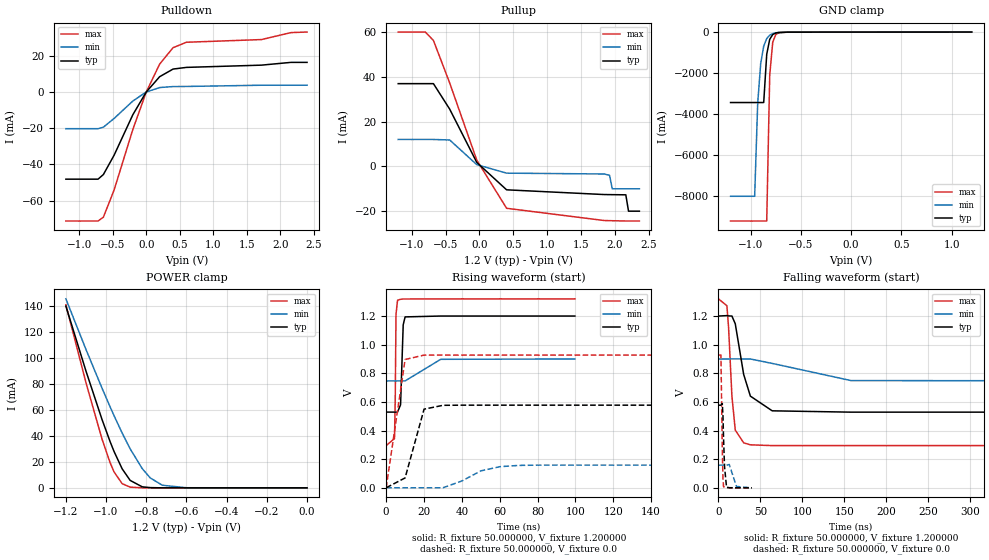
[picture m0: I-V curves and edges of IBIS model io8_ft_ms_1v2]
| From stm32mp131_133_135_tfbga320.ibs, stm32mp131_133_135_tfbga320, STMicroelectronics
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|   Model io8_ft_ms_1v2
[Model]  io8_ft_ms_1v2
Model_type I/O
Polarity   Non-Inverting
Enable   Active-Low
Vinl =   0.360000V
Vinh =   0.840000V
Vmeas =  0.600000V
Cref =   50.000000pF
Rref =   100.000000M
Vref =   0.0V
C_comp   2.961900pF   2.937700pF   2.984500pF
[Temperature Range]   25.000000   0.140000k   -40.000000
[Pullup Reference]   1.200000V   0.900000V   1.320000V
[Pulldown Reference]   0.0V   0.0V   0.0V
[POWER Clamp Reference]   1.200000V   0.900000V   1.320000V
[GND Clamp Reference]   0.0V   0.0V   0.0V
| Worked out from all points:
|   slope of the pulldown table from 0 to 0.18 V, typ, clamps not added: 23.2 ohm
|   slope of the pullup table from 0 to 0.18 V, typ, clamps not added: 28.5 ohm
|   GND clamp passes 1 mA (typ) near -0.47 V on its own axis
|   POWER clamp passes 1 mA (typ) near -0.83 V on its own axis
|   rising waveform, R_fixture 50.000000, V_fixture 1.200000: 20-80 % time 808ps typ, 2.63ns min, 431ps max; typ from 0.529 V to 1.2 V
|   rising waveform, R_fixture 50.000000, V_fixture 0.0: 20-80 % time 7.22ns typ, 16.4ns min, 6.21ns max; typ from 0 V to 0.577 V
|   falling waveform, R_fixture 50.000000, V_fixture 1.200000: 20-80 % time 13.7ns typ, 36.4ns min, 5.62ns max; typ from 1.2 V to 0.529 V
|   falling waveform, R_fixture 50.000000, V_fixture 0.0: 20-80 % time 2.02ns typ, 4.76ns min, 1.41ns max; typ from 0.577 V to 0 V
[Pulldown]
|Voltage   I(typ)   I(min)   I(max)
-1.2V     -48.14mA   -20.28mA   -71.24mA
-720mV    -48.14mA   -20.28mA   -71.24mA
-640mV    -45.58mA   -19.44mA   -69.11mA
-480mV    -34.9mA    -14.62mA   -54.1mA
-200mV    -12.54mA   -4.99mA    -20.65mA
0V        0A         0A         0A
200mV     8.434mA    2.44mA     15.39mA
400mV     12.64mA    2.983mA    24.45mA
600mV     13.57mA    3.042mA    27.45mA
1.72V     14.81mA    3.724mA    28.93mA
2.16V     16.34mA    3.724mA    32.78mA
2.4V      16.34mA    3.724mA    33.09mA
[Pullup]
|Voltage   I(typ)   I(min)   I(max)
-1.2V     36.95mA    12.02mA    60mA
-800mV    36.95mA    12.02mA    60mA
-680mV    36.95mA    12.02mA    56.24mA
-440mV    25.56mA    11.79mA    37.24mA
-40mV     1.753mA    765uA      2.773mA
400mV     -10.47mA   -3.023mA   -18.71mA
1.84V     -12.58mA   -3.4mA     -24.17mA
1.92V     -12.61mA   -4mA       -24.24mA
1.96V     -12.63mA   -10mA      -24.27mA
2.16V     -12.7mA    -10mA      -24.4mA
2.2V      -20mA      -10mA      -24.4mA
2.36V     -20mA      -10mA      -24.4mA
[GND_clamp]
|Voltage   I(typ)   I(min)   I(max)
-1.2V     -3.45A     -8.037A    -9.248A
-960mV    -3.45A     -8.037A    -9.248A
-930mV    -3.45A     -3.504A    -9.248A
-900mV    -3.45A     -1.544A    -9.248A
-870mV    -3.45A     -693.1mA   -9.248A
-840mV    -1.093A    -319.7mA   -9.248A
-810mV    -355mA     -153mA     -2.104A
-780mV    -122.1mA   -76.47mA   -492.8mA
-750mV    -46.85mA   -40.02mA   -125.6mA
-720mV    -21.41mA   -22.04mA   -38.94mA
-630mV    -6.028mA   -5.668mA   -6.589mA
1.2V      0A         44.19nA    0A
[POWER_clamp]
|Voltage   I(typ)   I(min)   I(max)
-1.2V     139.7mA    145.3mA    140.7mA
-1.1V     89.79mA    106.4mA    80.86mA
-1.02V    52.48mA    76.58mA    37.41mA
-980mV    35.57mA    62.3mA     19.38mA
-960mV    27.85mA    55.39mA    12.18mA
-920mV    14.63mA    42.15mA    3.226mA
-880mV    5.71mA     29.97mA    537.4uA
-820mV    777uA      14.76mA    28.17uA
-780mV    170.8uA    7.604mA    3.856uA
-720mV    16.71uA    2.018mA    195.3nA
-600mV    157.7nA    78.69uA    0A
0V        0A         56.62nA    0A
[Ramp]
| variable   typ   min   max
dV/dt_r  0.34636/5.28165n   95.23162m/14.22434n 0.55615/2.66557n
dV/dt_f  0.40279/13.61951n   92.01000m/36.38758n 0.61498/5.52083n
R_load = 50.000000
[Rising Waveform]
R_fixture= 50.000000
V_fixture= 1.200000
V_fixture_min= 0.900000
V_fixture_max= 1.320000
|time   V(typ)   V(min)   V(max)
0s        528.7mV    746.6mV    295mV
4.404ns   528.7mV    746.6mV    343.5mV
4.805ns   528.7mV    746.6mV    622.6mV
5.205ns   528.7mV    746.6mV    1.212V
6.006ns   528.3mV    746.6mV    1.31V
7.608ns   579.8mV    746.6mV    1.317V
9.009ns   1.139V     746.6mV    1.319V
10.01ns   1.194V     746.6mV    1.319V
28.83ns   1.2V       897.6mV    1.32V
99.7ns    1.2V       900mV      1.32V
[Rising Waveform]
R_fixture= 50.000000
V_fixture= 0.0
V_fixture_min= 0.0
V_fixture_max= 0.0
|time   V(typ)   V(min)   V(max)
0s        8.948nV    633.8nV    -5.106nV
10.01ns   68.77mV    634.1nV    896.4mV
20.02ns   549.2mV    -635.6uV   926.8mV
30.03ns   576.1mV    50.63uV    926.9mV
40.04ns   577.1mV    47.62mV    926.9mV
50.05ns   577.2mV    118.2mV    926.9mV
60.06ns   577.2mV    147.2mV    926.9mV
70.07ns   577.2mV    156.2mV    926.9mV
80.08ns   577.2mV    158mV      926.9mV
991ns     577.3mV    158.7mV    926.9mV
[Falling Waveform]
R_fixture= 50.000000
V_fixture= 1.200000
V_fixture_min= 0.900000
V_fixture_max= 1.320000
|time   V(typ)   V(min)   V(max)
0s        1.2V       900mV      1.32V
10.01ns   1.203V     900mV      1.272V
12.01ns   1.201V     899.9mV    1.122V
16.02ns   1.2V       900.9mV    639.5mV
20.02ns   1.146V     900.7mV    403.6mV
30.03ns   792.2mV    900.4mV    314.3mV
38.04ns   640.6mV    900mV      300.5mV
64.06ns   538mV      869.2mV    295.1mV
158.2ns   528.7mV    749.1mV    295mV
997ns     528.7mV    746.6mV    295mV
[Falling Waveform]
R_fixture= 50.000000
V_fixture= 0.0
V_fixture_min= 0.0
V_fixture_max= 0.0
|time   V(typ)   V(min)   V(max)
0s        577.3mV    158.7mV    926.9mV
2.883ns   577.3mV    158.7mV    927.6mV
4.565ns   589.1mV    158.7mV    261mV
5.365ns   499.6mV    158.7mV    63.97mV
6.006ns   352.4mV    158.7mV    9.718mV
7.207ns   148.3mV    158.7mV    2.954mV
9.61ns    3.974mV    158.6mV    1.562mV
12.81ns   921.1uV    163.1mV    784.7uV
21.46ns   480.6uV    9.73mV     155.7uV
39.88ns   8.948nV    633.8nV    -5.106nV
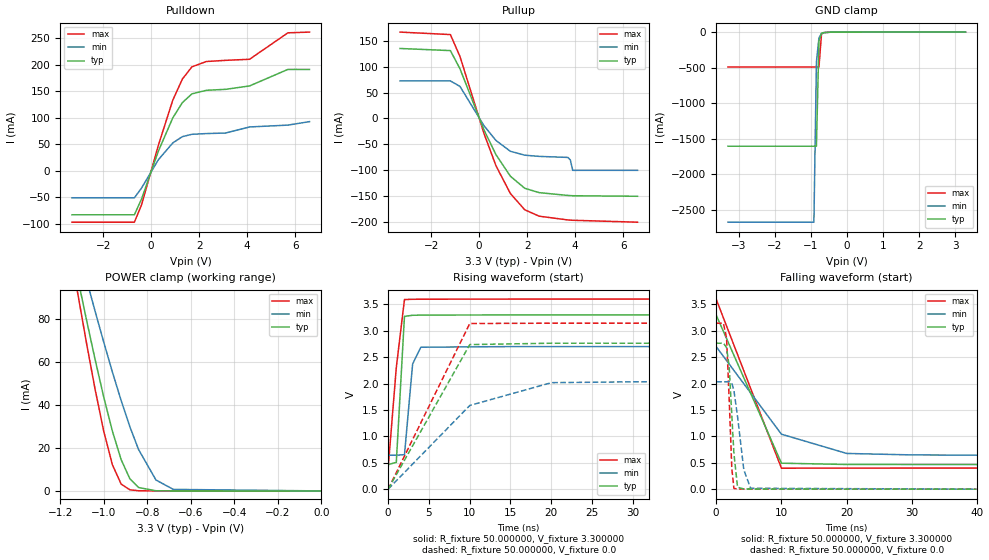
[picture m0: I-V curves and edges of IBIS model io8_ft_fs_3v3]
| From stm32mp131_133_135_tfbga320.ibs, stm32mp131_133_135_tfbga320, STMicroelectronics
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|   Model io8_ft_fs_3v3
[Model]  io8_ft_fs_3v3
Model_type I/O
Polarity   Non-Inverting
Enable   Active-Low
Vinl =   0.990000V
Vinh =   2.310000V
Vmeas =  1.650000V
Cref =   50.000000pF
Rref =   100.000000M
Vref =   0.0V
C_comp   3.331100pF   3.329200pF   3.346200pF
[Temperature Range]   25.000000   0.140000k   -40.000000
[Pullup Reference]   3.300000V   2.700000V   3.600000V
[Pulldown Reference]   0.0V   0.0V   0.0V
[POWER Clamp Reference]   3.300000V   2.700000V   3.600000V
[GND Clamp Reference]   0.0V   0.0V   0.0V
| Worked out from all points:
|   slope of the pulldown table from 0 to 0.495 V, typ, clamps not added: 8.27 ohm
|   slope of the pullup table from 0 to 0.495 V, typ, clamps not added: 9.61 ohm
|   GND clamp passes 1 mA (typ) near -0.46 V on its own axis
|   POWER clamp passes 1 mA (typ) near -0.82 V on its own axis
|   rising waveform, R_fixture 50.000000, V_fixture 3.300000: 20-80 % time 616ps typ, 720ps min, 1.17ns max; typ from 0.466 V to 3.3 V
|   rising waveform, R_fixture 50.000000, V_fixture 0.0: 20-80 % time 6.06ns typ, 8.41ns min, 6.02ns max; typ from 0 V to 2.76 V
|   falling waveform, R_fixture 50.000000, V_fixture 3.300000: 20-80 % time 6.06ns typ, 7.45ns min, 6ns max; typ from 3.3 V to 0.466 V
|   falling waveform, R_fixture 50.000000, V_fixture 0.0: 20-80 % time 734ps typ, 1.13ns min, 547ps max; typ from 2.76 V to 0 V
[Pulldown]
|Voltage   I(typ)   I(min)   I(max)
-3.3V     -82.68mA   -50.69mA   -96.69mA
-700mV    -82.68mA   -50.69mA   -96.69mA
-400mV    -52.74mA   -32.14mA   -63.87mA
300mV     37.41mA    21.2mA     48.47mA
900mV     100mA      52.8mA     133.4mA
1.3V      128.9mA    64.69mA    173.3mA
1.7V      145.4mA    69.09mA    196.4mA
2.3V      152.1mA    70.46mA    206.4mA
3.1V      153.9mA    71.5mA     208.6mA
4.1V      160.3mA    82.94mA    210.6mA
5.7V      191.5mA    86.44mA    260.5mA
6.6V      191.5mA    93mA       261.9mA
[Pullup]
|Voltage   I(typ)   I(min)   I(max)
-3.3V     135mA      72.45mA    166.6mA
-1.2V     130.9mA    72.45mA    161.8mA
-800mV    95.9mA     61.87mA    119.5mA
200mV     -22.04mA   -13.96mA   -28.88mA
700mV     -69.71mA   -42.31mA   -91.11mA
1.3V      -111.3mA   -63.25mA   -144.6mA
1.9V      -134.6mA   -70.77mA   -176.1mA
2.5V      -143mA     -73.1mA    -188.4mA
3.7V      -148.4mA   -75.1mA    -195.7mA
3.8V      -148.7mA   -80mA      -196mA
3.9V      -149mA     -100mA     -196.3mA
6.6V      -150mA     -100mA     -200mA
[GND_clamp]
|Voltage   I(typ)   I(min)   I(max)
-3.3V     -1.605A    -2.674A    -491.7mA
-920mV    -1.605A    -2.674A    -491.7mA
-850mV    -1.605A    -419.8mA   -491.7mA
-780mV    -124.6mA   -80.71mA   -491.7mA
-710mV    -18.13mA   -20.11mA   -27.93mA
-640mV    -6.917mA   -6.958mA   -7.362mA
-430mV    -466.9uA   -1.206mA   -281.7uA
3.28V     0A         45.63nA    0A
[POWER_clamp]
|Voltage   I(typ)   I(min)   I(max)
-3.28V    1.28A      1.024A     1.509A
-1.12V    99.56mA    114.1mA    92.51mA
-1.08V    80.16mA    98.83mA    69.45mA
-1.04V    61.47mA    83.9mA     47.62mA
-1V       43.82mA    69.37mA    27.91mA
-960mV    27.85mA    55.39mA    12.18mA
-920mV    14.63mA    42.15mA    3.226mA
-880mV    5.71mA     29.97mA    537.4uA
-840mV    1.599mA    19.32mA    75.95uA
-760mV    78.93uA    5.095mA    1.426uA
-680mV    3.528uA    713.7uA    27.27nA
0V        0A         62.3nA     0A
[Ramp]
| variable   typ   min   max
dV/dt_r  1.65858/1.98757n   1.22046/4.05944n   1.88568/1.46534n
dV/dt_f  1.70023/1.60172n   1.23439/3.65057n   1.92035/1.27355n
R_load = 50.000000
[Rising Waveform]
R_fixture= 50.000000
V_fixture= 3.300000
V_fixture_min= 2.700000
V_fixture_max= 3.600000
|time   V(typ)   V(min)   V(max)
0s        466.3mV    642.7mV    399.6mV
1.001ns   507.8mV    642.7mV    2.303V
2.002ns   3.273V     652.8mV    3.591V
3.003ns   3.293V     2.37V      3.596V
4.004ns   3.296V     2.688V     3.597V
15.02ns   3.3V       2.7V       3.6V
99.1ns    3.3V       2.7V       3.6V
[Rising Waveform]
R_fixture= 50.000000
V_fixture= 0.0
V_fixture_min= 0.0
V_fixture_max= 0.0
|time   V(typ)   V(min)   V(max)
0s        2.574nV    280.9nV    5.711nV
10.01ns   2.738V     1.585V     3.137V
20.02ns   2.764V     2.017V     3.143V
30.03ns   2.764V     2.033V     3.143V
991ns     2.764V     2.034V     3.143V
[Falling Waveform]
R_fixture= 50.000000
V_fixture= 3.300000
V_fixture_min= 2.700000
V_fixture_max= 3.600000
|time   V(typ)   V(min)   V(max)
0s        3.3V       2.7V       3.6V
10.01ns   491.7mV    1.041V     397mV
20.02ns   467.4mV    676.4mV    399.4mV
30.03ns   466.4mV    648.6mV    399.6mV
40.04ns   466.3mV    643.8mV    399.6mV
991ns     466.3mV    642.7mV    399.6mV
[Falling Waveform]
R_fixture= 50.000000
V_fixture= 0.0
V_fixture_min= 0.0
V_fixture_max= 0.0
|time   V(typ)   V(min)   V(max)
0s        2.764V     2.034V     3.143V
1.121ns   2.764V     2.034V     3.14V
1.602ns   2.683V     2.034V     2.86V
2.002ns   2.313V     2.037V     1.695V
2.402ns   1.399V     2.005V     398mV
2.723ns   679.6mV    1.871V     14.33mV
3.283ns   37.66mV    1.373V     3.216mV
4.244ns   3.147mV    366mV      1.679mV
5.285ns   1.801mV    16.96mV    1.163mV
39.88ns   2.574nV    280.9nV    5.711nV
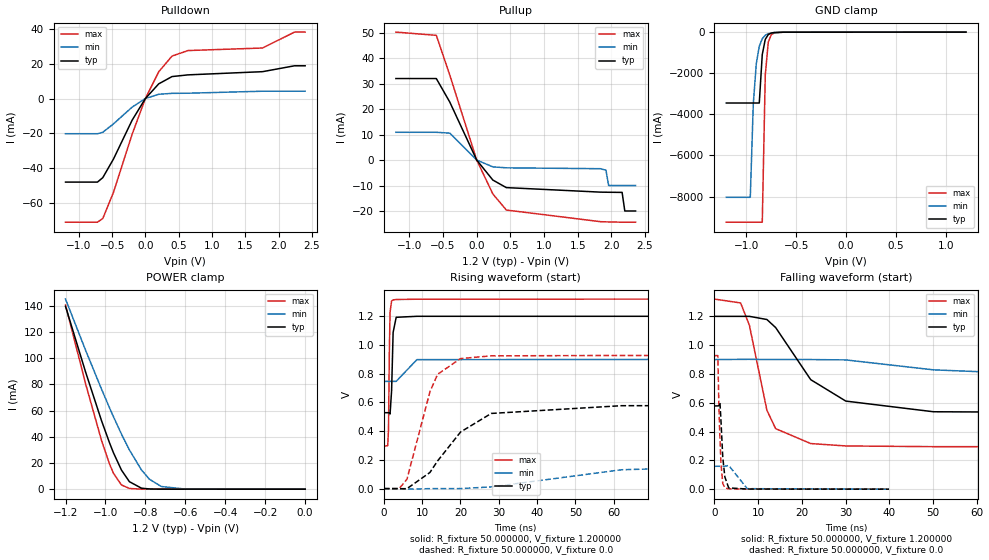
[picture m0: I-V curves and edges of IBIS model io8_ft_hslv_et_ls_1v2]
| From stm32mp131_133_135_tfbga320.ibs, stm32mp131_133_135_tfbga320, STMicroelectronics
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|   Model io8_ft_hslv_et_ls_1v2
[Model]  io8_ft_hslv_et_ls_1v2
Model_type I/O
Polarity   Non-Inverting
Enable   Active-Low
Vinl =   0.360000V
Vinh =   0.840000V
Vmeas =  0.600000V
Cref =   50.000000pF
Rref =   100.000000M
Vref =   0.0V
C_comp   2.961500pF   2.939400pF   2.982700pF
[Temperature Range]   25.000000   0.140000k   -40.000000
[Pullup Reference]   1.200000V   0.900000V   1.320000V
[Pulldown Reference]   0.0V   0.0V   0.0V
[POWER Clamp Reference]   1.200000V   0.900000V   1.320000V
[GND Clamp Reference]   0.0V   0.0V   0.0V
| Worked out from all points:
|   slope of the pulldown table from 0 to 0.18 V, typ, clamps not added: 23.2 ohm
|   slope of the pullup table from 0 to 0.18 V, typ, clamps not added: 28.5 ohm
|   GND clamp passes 1 mA (typ) near -0.47 V on its own axis
|   POWER clamp passes 1 mA (typ) near -0.83 V on its own axis
|   rising waveform, R_fixture 50.000000, V_fixture 1.200000: 20-80 % time 406ps typ, 1.12ns min, 291ps max; typ from 0.529 V to 1.2 V
|   rising waveform, R_fixture 50.000000, V_fixture 0.0: 20-80 % time 11.1ns typ, 27.1ns min, 5.96ns max; typ from 0 V to 0.578 V
|   falling waveform, R_fixture 50.000000, V_fixture 1.200000: 20-80 % time 10.9ns typ, 27.7ns min, 4.6ns max; typ from 1.2 V to 0.529 V
|   falling waveform, R_fixture 50.000000, V_fixture 0.0: 20-80 % time 720ps typ, 1.5ns min, 567ps max; typ from 0.578 V to 0 V
[Pulldown]
|Voltage   I(typ)   I(min)   I(max)
-1.2V     -48.14mA   -20.28mA   -71.24mA
-720mV    -48.14mA   -20.28mA   -71.24mA
-640mV    -45.58mA   -19.44mA   -69.11mA
-480mV    -34.9mA    -14.62mA   -54.1mA
-200mV    -12.54mA   -4.988mA   -20.65mA
0V        0A         -5pA       0A
200mV     8.434mA    2.439mA    15.39mA
400mV     12.64mA    2.982mA    24.45mA
640mV     13.62mA    3.048mA    27.62mA
1.76V     15.46mA    4.2mA      29.09mA
2.24V     18.85mA    4.2mA      38.26mA
2.4V      18.85mA    4.2mA      38.26mA
[Pullup]
|Voltage   I(typ)   I(min)   I(max)
-1.2V     32mA       10.9mA     50.24mA
-600mV    32mA       10.9mA     48.96mA
-400mV    22.77mA    10.57mA    33.4mA
0V        4.56pA     736pA      2.874pA
240mV     -7.862mA   -2.681mA   -13.32mA
440mV     -10.82mA   -3.056mA   -19.62mA
1.84V     -12.6mA    -3.4mA     -24.2mA
1.92V     -12.63mA   -4mA       -24.27mA
1.96V     -12.65mA   -10mA      -24.3mA
2.16V     -12.7mA    -10mA      -24.4mA
2.2V      -20mA      -10mA      -24.4mA
2.36V     -20mA      -10mA      -24.4mA
[GND_clamp]
|Voltage   I(typ)   I(min)   I(max)
-1.2V     -3.45A     -8.037A    -9.248A
-960mV    -3.45A     -8.037A    -9.248A
-930mV    -3.45A     -3.504A    -9.248A
-900mV    -3.45A     -1.544A    -9.248A
-870mV    -3.45A     -693.1mA   -9.248A
-840mV    -1.093A    -319.7mA   -9.248A
-810mV    -355mA     -153mA     -2.104A
-780mV    -122.1mA   -76.47mA   -492.8mA
-750mV    -46.85mA   -40.02mA   -125.6mA
-720mV    -21.41mA   -22.04mA   -38.94mA
-630mV    -6.028mA   -5.668mA   -6.589mA
1.2V      0A         44.1nA     0A
[POWER_clamp]
|Voltage   I(typ)   I(min)   I(max)
-1.2V     139.7mA    145.3mA    140.7mA
-1.1V     89.79mA    106.4mA    80.86mA
-1.02V    52.48mA    76.58mA    37.41mA
-980mV    35.57mA    62.3mA     19.38mA
-960mV    27.85mA    55.39mA    12.18mA
-920mV    14.63mA    42.15mA    3.226mA
-880mV    5.71mA     29.97mA    537.4uA
-820mV    777uA      14.76mA    28.17uA
-780mV    170.8uA    7.604mA    3.856uA
-720mV    16.71uA    2.018mA    195.3nA
-600mV    157.7nA    78.69uA    0A
0V        0A         56.62nA    0A
[Ramp]
| variable   typ   min   max
dV/dt_r  0.34679/11.12933n   95.37562m/27.01924n 0.55638/5.76617n
dV/dt_f  0.40279/10.87971n   91.97400m/27.71296n 0.61499/4.42118n
R_load = 50.000000
[Rising Waveform]
R_fixture= 50.000000
V_fixture= 1.200000
V_fixture_min= 0.900000
V_fixture_max= 1.320000
|time   V(typ)   V(min)   V(max)
0s        528.7mV    746.7mV    295mV
1.001ns   528.7mV    746.7mV    299.4mV
1.201ns   529.1mV    746.7mV    417.4mV
1.401ns   524.8mV    746.7mV    933.8mV
1.602ns   519.9mV    746.7mV    1.229V
2.002ns   681.5mV    746.7mV    1.307V
2.402ns   1.088V     746.7mV    1.314V
3.203ns   1.193V     746.8mV    1.317V
8.609ns   1.2V       898.2mV    1.319V
99.7ns    1.2V       900mV      1.32V
[Rising Waveform]
R_fixture= 50.000000
V_fixture= 0.0
V_fixture_min= 0.0
V_fixture_max= 0.0
|time   V(typ)   V(min)   V(max)
0s        2.355nV    640.6nV    922.8pV
4.004ns   -781.1uV   177.4uV    1.005mV
6.006ns   -347.3uV   -3.799mV   64.82mV
12.01ns   112.3mV    -159.2uV   673.9mV
14.01ns   192.4mV    -71.37uV   795.9mV
20.02ns   394.2mV    385uV      905.6mV
28.03ns   523.5mV    11.86mV    924.5mV
62.06ns   577.5mV    131.3mV    927.3mV
96.1ns    577.8mV    156.7mV    927.3mV
997ns     578mV      159mV      927.3mV
[Falling Waveform]
R_fixture= 50.000000
V_fixture= 1.200000
V_fixture_min= 0.900000
V_fixture_max= 1.320000
|time   V(typ)   V(min)   V(max)
0s        1.2V       900mV      1.32V
6.006ns   1.2V       901.2mV    1.293V
8.008ns   1.2V       901.4mV    1.138V
12.01ns   1.178V     900.4mV    547.6mV
14.01ns   1.122V     900mV      420.1mV
22.02ns   760.3mV    900mV      316.7mV
30.03ns   611.6mV    897.5mV    300.1mV
50.05ns   537.5mV    828.5mV    295.1mV
114.1ns   528.7mV    749.5mV    295mV
997ns     528.7mV    746.7mV    295mV
[Falling Waveform]
R_fixture= 50.000000
V_fixture= 0.0
V_fixture_min= 0.0
V_fixture_max= 0.0
|time   V(typ)   V(min)   V(max)
0s        578mV      159mV      927.3mV
800.8ps   578.2mV    159mV      927.5mV
1.041ns   580.3mV    159mV      576.3mV
1.281ns   600.9mV    159mV      349.1mV
1.522ns   472.8mV    159mV      177mV
1.922ns   223.3mV    159mV      40.48mV
2.402ns   85.02mV    159.1mV    9.092mV
3.283ns   8.813mV    165mV      2.349mV
7.528ns   842.2uV    3.331mV    1.073mV
39.88ns   2.355nV    640.6nV    922.8pV
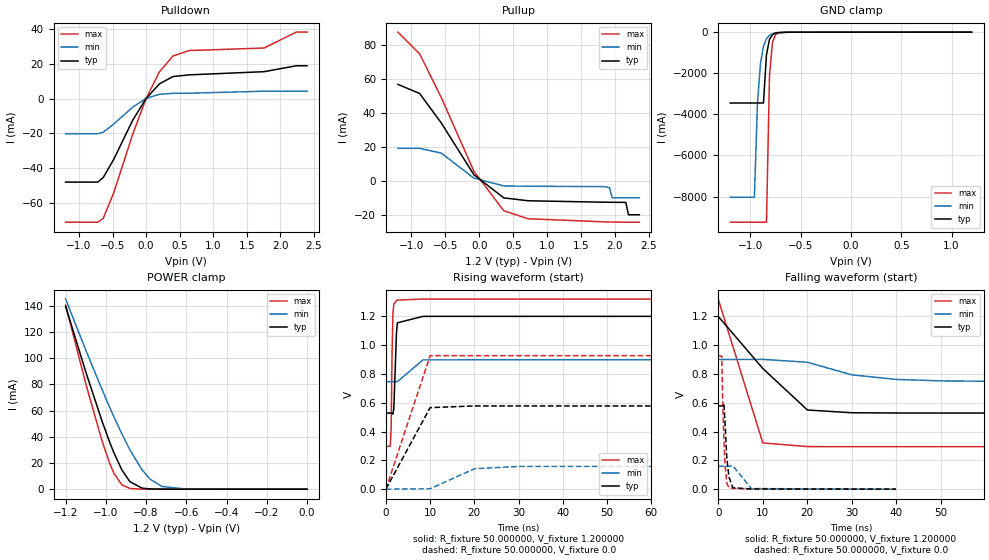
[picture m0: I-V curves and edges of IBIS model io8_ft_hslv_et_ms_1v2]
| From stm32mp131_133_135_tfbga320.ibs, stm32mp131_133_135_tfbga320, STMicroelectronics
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|   Model io8_ft_hslv_et_ms_1v2
[Model]  io8_ft_hslv_et_ms_1v2
Model_type I/O
Polarity   Non-Inverting
Enable   Active-Low
Vinl =   0.360000V
Vinh =   0.840000V
Vmeas =  0.600000V
Cref =   50.000000pF
Rref =   100.000000M
Vref =   0.0V
C_comp   2.961500pF   2.939400pF   2.982700pF
[Temperature Range]   25.000000   0.140000k   -40.000000
[Pullup Reference]   1.200000V   0.900000V   1.320000V
[Pulldown Reference]   0.0V   0.0V   0.0V
[POWER Clamp Reference]   1.200000V   0.900000V   1.320000V
[GND Clamp Reference]   0.0V   0.0V   0.0V
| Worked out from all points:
|   slope of the pulldown table from 0 to 0.18 V, typ, clamps not added: 23.2 ohm
|   slope of the pullup table from 0 to 0.18 V, typ, clamps not added: 28.5 ohm
|   GND clamp passes 1 mA (typ) near -0.47 V on its own axis
|   POWER clamp passes 1 mA (typ) near -0.83 V on its own axis
|   rising waveform, R_fixture 50.000000, V_fixture 1.200000: 20-80 % time 417ps typ, 1.1ns min, 296ps max; typ from 0.529 V to 1.2 V
|   rising waveform, R_fixture 50.000000, V_fixture 0.0: 20-80 % time 6.13ns typ, 6.88ns min, 6.01ns max; typ from 0 V to 0.578 V
|   falling waveform, R_fixture 50.000000, V_fixture 1.200000: 20-80 % time 12.4ns typ, 13.8ns min, 6.16ns max; typ from 1.2 V to 0.529 V
|   falling waveform, R_fixture 50.000000, V_fixture 0.0: 20-80 % time 724ps typ, 1.52ns min, 571ps max; typ from 0.578 V to 0 V
[Pulldown]
|Voltage   I(typ)   I(min)   I(max)
-1.2V     -48.14mA   -20.28mA   -71.24mA
-720mV    -48.14mA   -20.28mA   -71.24mA
-640mV    -45.58mA   -19.44mA   -69.11mA
-480mV    -34.9mA    -14.62mA   -54.1mA
-200mV    -12.54mA   -4.989mA   -20.65mA
0V        0A         -5pA       0A
200mV     8.434mA    2.44mA     15.39mA
400mV     12.64mA    2.983mA    24.45mA
640mV     13.62mA    3.049mA    27.62mA
1.76V     15.46mA    4.201mA    29.09mA
2.24V     18.85mA    4.201mA    38.26mA
2.4V      18.85mA    4.201mA    38.26mA
[Pullup]
|Voltage   I(typ)   I(min)   I(max)
-1.2V     56.97mA    19.21mA    87.84mA
-880mV    51.58mA    19.21mA    75mA
-560mV    34.14mA    16.37mA    49.11mA
-80mV     3.633mA    1.627mA    5.693mA
360mV     -10.03mA   -2.99mA    -17.65mA
720mV     -11.75mA   -3.174mA   -22.37mA
1.84V     -12.6mA    -3.4mA     -24.2mA
1.92V     -12.63mA   -4mA       -24.27mA
1.96V     -12.65mA   -10mA      -24.3mA
2.16V     -12.7mA    -10mA      -24.4mA
2.2V      -20mA      -10mA      -24.4mA
2.36V     -20mA      -10mA      -24.4mA
[GND_clamp]
|Voltage   I(typ)   I(min)   I(max)
-1.2V     -3.45A     -8.037A    -9.248A
-960mV    -3.45A     -8.037A    -9.248A
-930mV    -3.45A     -3.504A    -9.248A
-900mV    -3.45A     -1.544A    -9.248A
-870mV    -3.45A     -693.1mA   -9.248A
-840mV    -1.093A    -319.7mA   -9.248A
-810mV    -355mA     -153mA     -2.104A
-780mV    -122.1mA   -76.47mA   -492.8mA
-750mV    -46.85mA   -40.02mA   -125.6mA
-720mV    -21.41mA   -22.04mA   -38.94mA
-630mV    -6.028mA   -5.668mA   -6.589mA
1.2V      0A         44.1nA     0A
[POWER_clamp]
|Voltage   I(typ)   I(min)   I(max)
-1.2V     139.7mA    145.3mA    140.7mA
-1.1V     89.79mA    106.4mA    80.86mA
-1.02V    52.48mA    76.58mA    37.41mA
-980mV    35.57mA    62.3mA     19.38mA
-960mV    27.85mA    55.39mA    12.18mA
-920mV    14.63mA    42.15mA    3.226mA
-880mV    5.71mA     29.97mA    537.4uA
-820mV    777uA      14.76mA    28.17uA
-780mV    170.8uA    7.604mA    3.856uA
-720mV    16.71uA    2.018mA    195.3nA
-600mV    157.7nA    78.69uA    0A
0V        0A         56.62nA    0A
[Ramp]
| variable   typ   min   max
dV/dt_r  0.34679/2.43029n   95.41762m/5.70342n  0.55638/1.39894n
dV/dt_f  0.40279/4.90733n   92.01000m/12.32053n 0.61499/2.07988n
R_load = 50.000000
[Rising Waveform]
R_fixture= 50.000000
V_fixture= 1.200000
V_fixture_min= 0.900000
V_fixture_max= 1.320000
|time   V(typ)   V(min)   V(max)
0s        528.7mV    746.7mV    295mV
1.001ns   528.7mV    746.7mV    298.8mV
1.201ns   529.2mV    746.7mV    426.7mV
1.401ns   525.4mV    746.7mV    940.7mV
1.602ns   520.9mV    746.7mV    1.222V
1.802ns   561.7mV    746.7mV    1.286V
2.402ns   1.087V     746.7mV    1.31V
2.603ns   1.155V     746.7mV    1.313V
8.408ns   1.2V       897.8mV    1.32V
99.7ns    1.2V       900mV      1.32V
[Rising Waveform]
R_fixture= 50.000000
V_fixture= 0.0
V_fixture_min= 0.0
V_fixture_max= 0.0
|time   V(typ)   V(min)   V(max)
0s        2.355nV    640.5nV    922.8pV
10.01ns   566mV      2.87mV     927mV
20.02ns   577.8mV    141.7mV    927.3mV
30.03ns   577.9mV    157.8mV    927.3mV
991ns     578mV      159mV      927.3mV
[Falling Waveform]
R_fixture= 50.000000
V_fixture= 1.200000
V_fixture_min= 0.900000
V_fixture_max= 1.320000
|time   V(typ)   V(min)   V(max)
0s        1.2V       900mV      1.32V
10.01ns   837.9mV    901.3mV    321.1mV
20.02ns   549.7mV    881.1mV    295.7mV
30.03ns   530.6mV    793.6mV    295mV
40.04ns   528.9mV    761.8mV    295mV
50.05ns   528.7mV    751.8mV    295mV
70.07ns   528.7mV    746.9mV    295mV
991ns     528.7mV    746.7mV    295mV
[Falling Waveform]
R_fixture= 50.000000
V_fixture= 0.0
V_fixture_min= 0.0
V_fixture_max= 0.0
|time   V(typ)   V(min)   V(max)
0s        578mV      159mV      927.3mV
800.8ps   578.1mV    159mV      923.6mV
1.041ns   580.1mV    159.1mV    573.1mV
1.281ns   595.6mV    159.1mV    348.3mV
1.522ns   469.1mV    159.1mV    178.6mV
1.922ns   221.4mV    159mV      42.83mV
2.402ns   85.74mV    159.2mV    11.29mV
3.283ns   9.852mV    162.7mV    4.563mV
7.447ns   1.557mV    4.099mV    453.9uV
39.88ns   2.355nV    640.5nV    922.8pV
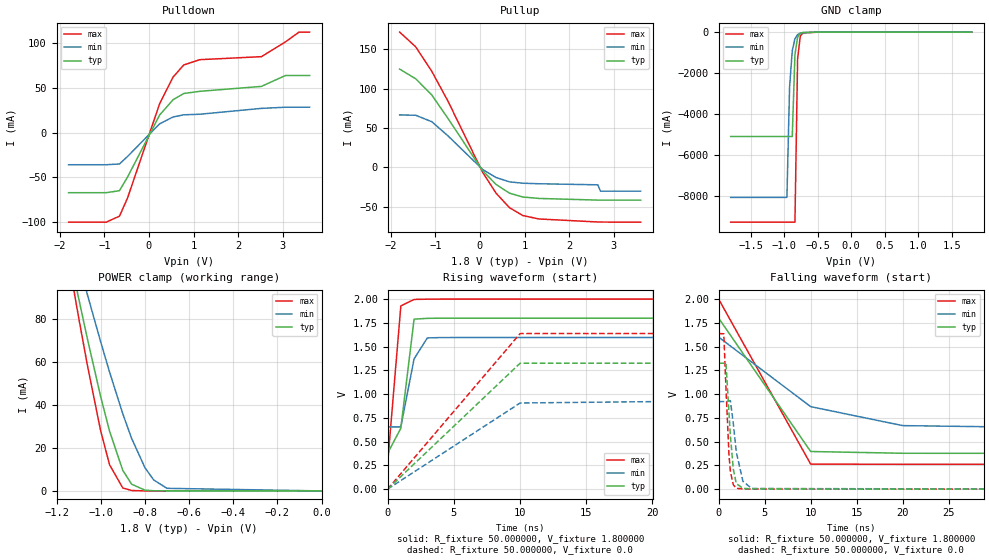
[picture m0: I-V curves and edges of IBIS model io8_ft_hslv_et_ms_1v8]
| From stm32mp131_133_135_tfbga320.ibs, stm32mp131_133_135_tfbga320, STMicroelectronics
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|   Model io8_ft_hslv_et_ms_1v8
[Model]  io8_ft_hslv_et_ms_1v8
Model_type I/O
Polarity   Non-Inverting
Enable   Active-Low
Vinl =   0.540000V
Vinh =   1.260000V
Vmeas =  0.900000V
Cref =   50.000000pF
Rref =   100.000000M
Vref =   0.0V
C_comp   3.177500pF   3.161600pF   3.207000pF
[Temperature Range]   25.000000   0.140000k   -40.000000
[Pullup Reference]   1.800000V   1.600000V   2.000000V
[Pulldown Reference]   0.0V   0.0V   0.0V
[POWER Clamp Reference]   1.800000V   1.600000V   2.000000V
[GND Clamp Reference]   0.0V   0.0V   0.0V
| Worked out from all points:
|   slope of the pulldown table from 0 to 0.27 V, typ, clamps not added: 12.5 ohm
|   slope of the pullup table from 0 to 0.27 V, typ, clamps not added: 16 ohm
|   GND clamp passes 1 mA (typ) near -0.47 V on its own axis
|   POWER clamp passes 1 mA (typ) near -0.83 V on its own axis
|   rising waveform, R_fixture 50.000000, V_fixture 1.800000: 20-80 % time 744ps typ, 917ps min, 627ps max; typ from 0.377 V to 1.8 V
|   rising waveform, R_fixture 50.000000, V_fixture 0.0: 20-80 % time 6.01ns typ, 6.1ns min, 6.01ns max; typ from 0 V to 1.32 V
|   falling waveform, R_fixture 50.000000, V_fixture 1.800000: 20-80 % time 6.09ns typ, 8.66ns min, 6.01ns max; typ from 1.8 V to 0.377 V
|   falling waveform, R_fixture 50.000000, V_fixture 0.0: 20-80 % time 548ps typ, 754ps min, 438ps max; typ from 1.32 V to 0 V
[Pulldown]
|Voltage   I(typ)   I(min)   I(max)
-1.8V     -67.09mA   -35.91mA   -100mA
-960mV    -67.09mA   -35.91mA   -100mA
-660mV    -64.86mA   -35.04mA   -93.29mA
-480mV    -49.73mA   -26.69mA   -73.15mA
240mV     19.58mA    9.767mA    32.18mA
540mV     36.57mA    17.36mA    61.85mA
780mV     43.58mA    19.81mA    75.41mA
1.14V     46.02mA    20.44mA    81.32mA
2.52V     51.5mA     26.98mA    84.69mA
3.06V     63.69mA    28.28mA    101.2mA
3.36V     63.69mA    28.28mA    112mA
3.6V      63.69mA    28.28mA    112.1mA
[Pullup]
|Voltage   I(typ)   I(min)   I(max)
-1.8V     124.8mA    66.67mA    171.7mA
-1.44V    112.5mA    66.21mA    153mA
-1.08V    91.95mA    58.05mA    122mA
-720mV    62.47mA    40.28mA    84.45mA
60mV      -4.156mA   -2.568mA   -6.128mA
360mV     -21.47mA   -12.71mA   -32.54mA
660mV     -32.57mA   -18.23mA   -50.94mA
960mV     -37.44mA   -19.97mA   -60.97mA
1.32V     -39.27mA   -20.64mA   -65.31mA
2.64V     -41.4mA    -22mA      -69.14mA
2.7V      -41.4mA    -30mA      -69.23mA
3.6V      -41.4mA    -30mA      -69.4mA
[GND_clamp]
|Voltage   I(typ)   I(min)   I(max)
-1.8V     -5.08A     -8.044A    -9.251A
-960mV    -5.08A     -8.044A    -9.251A
-920mV    -5.08A     -2.669A    -9.251A
-880mV    -5.08A     -908mA     -9.251A
-840mV    -1.096A    -323.6mA   -9.251A
-800mV    -248.9mA   -123.7mA   -1.293A
-760mV    -64.81mA   -51.32mA   -196.6mA
-720mV    -22.13mA   -23.23mA   -39.69mA
-480mV    -1.149mA   -1.898mA   -936.1uA
1.8V      0A         44.23nA    0A
[POWER_clamp]
|Voltage   I(typ)   I(min)   I(max)
-1.8V     460.5mA    392.1mA    526.9mA
-1.12V    99.56mA    114.1mA    92.51mA
-1.1V     89.79mA    106.4mA    80.86mA
-1.06V    70.71mA    91.32mA    58.34mA
-1V       43.82mA    69.37mA    27.91mA
-960mV    27.85mA    55.39mA    12.18mA
-900mV    9.544mA    35.9mA     1.368mA
-860mV    3.133mA    24.42mA    203.6uA
-800mV    367uA      10.84mA    10.43uA
-760mV    78.93uA    5.095mA    1.426uA
-700mV    7.679uA    1.212mA    72.46nA
0V        0A         59.16nA    0A
[Ramp]
| variable   typ   min   max
dV/dt_r  0.79494/1.05601n   0.55271/2.58524n   0.98232/0.66792n
dV/dt_f  0.85363/1.86364n   0.56723/4.41681n   1.04297/1.12588n
R_load = 50.000000
[Rising Waveform]
R_fixture= 50.000000
V_fixture= 1.800000
V_fixture_min= 1.600000
V_fixture_max= 2.000000
|time   V(typ)   V(min)   V(max)
0s        377.3mV    654.6mV    261.7mV
1.001ns   640.6mV    654.7mV    1.928V
2.002ns   1.789V     1.371V     1.996V
3.003ns   1.797V     1.591V     1.999V
4.004ns   1.799V     1.595V     2V
99.1ns    1.8V       1.6V       2V
[Rising Waveform]
R_fixture= 50.000000
V_fixture= 0.0
V_fixture_min= 0.0
V_fixture_max= 0.0
|time   V(typ)   V(min)   V(max)
0s        2.011nV    381.3nV    939.1pV
10.01ns   1.325V     906.6mV    1.637V
20.02ns   1.325V     921mV      1.637V
991ns     1.325V     921.2mV    1.637V
[Falling Waveform]
R_fixture= 50.000000
V_fixture= 1.800000
V_fixture_min= 1.600000
V_fixture_max= 2.000000
|time   V(typ)   V(min)   V(max)
0s        1.8V       1.6V       2V
10.01ns   396.2mV    868.3mV    263.5mV
20.02ns   377.6mV    668.6mV    261.7mV
30.03ns   377.3mV    655.8mV    261.7mV
991ns     377.3mV    654.6mV    261.7mV
[Falling Waveform]
R_fixture= 50.000000
V_fixture= 0.0
V_fixture_min= 0.0
V_fixture_max= 0.0
|time   V(typ)   V(min)   V(max)
0s        1.325V     921.2mV    1.637V
560.6ps   1.325V     921.3mV    1.635V
800.8ps   1.326V     921.3mV    1.064V
1.121ns   811.6mV    928.4mV    374.9mV
1.281ns   562.6mV    930.1mV    183.1mV
1.602ns   207.9mV    684.9mV    45.57mV
1.922ns   59.69mV    391.6mV    9.243mV
2.643ns   8.436mV    82.7mV     2.54mV
3.604ns   2.876mV    6.95mV     1.258mV
39.88ns   2.011nV    381.3nV    939.1pV
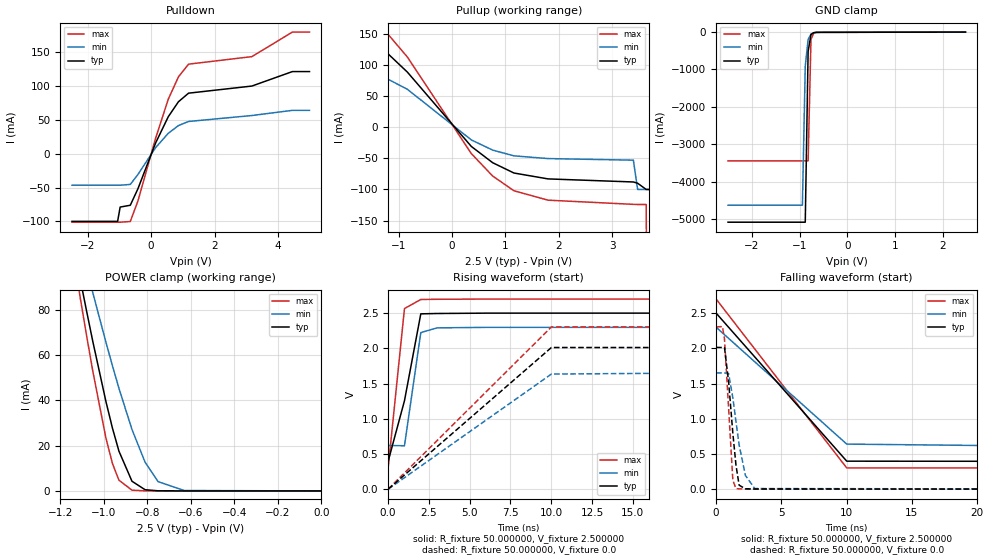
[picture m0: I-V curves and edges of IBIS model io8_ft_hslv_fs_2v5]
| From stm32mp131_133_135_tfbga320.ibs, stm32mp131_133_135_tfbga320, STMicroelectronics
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|   Model io8_ft_hslv_fs_2v5
[Model]  io8_ft_hslv_fs_2v5
Model_type I/O
Polarity   Non-Inverting
Enable   Active-Low
Vinl =   0.750000V
Vinh =   1.750000V
Vmeas =  1.250000V
Cref =   50.000000pF
Rref =   100.000000M
Vref =   0.0V
C_comp   3.247300pF   3.246200pF   3.289300pF
[Temperature Range]   25.000000   0.140000k   -40.000000
[Pullup Reference]   2.500000V   2.300000V   2.700000V
[Pulldown Reference]   0.0V   0.0V   0.0V
[POWER Clamp Reference]   2.500000V   2.300000V   2.700000V
[GND Clamp Reference]   0.0V   0.0V   0.0V
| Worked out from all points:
|   slope of the pulldown table from 0 to 0.375 V, typ, clamps not added: 9.35 ohm
|   slope of the pullup table from 0 to 0.375 V, typ, clamps not added: 11.7 ohm
|   GND clamp passes 1 mA (typ) near -0.47 V on its own axis
|   POWER clamp passes 1 mA (typ) near -0.82 V on its own axis
|   rising waveform, R_fixture 50.000000, V_fixture 2.500000: 20-80 % time 1.18ns typ, 628ps min, 637ps max; typ from 0.396 V to 2.5 V
|   rising waveform, R_fixture 50.000000, V_fixture 0.0: 20-80 % time 6.01ns typ, 6.07ns min, 6.01ns max; typ from 0 V to 2.01 V
|   falling waveform, R_fixture 50.000000, V_fixture 2.500000: 20-80 % time 6.01ns typ, 6.08ns min, 6.01ns max; typ from 2.5 V to 0.396 V
|   falling waveform, R_fixture 50.000000, V_fixture 0.0: 20-80 % time 563ps typ, 798ps min, 407ps max; typ from 2.01 V to 0 V
[Pulldown]
|Voltage   I(typ)   I(min)   I(max)
-2.5V     -100mA     -46.5mA    -101.2mA
-1.06V    -100mA     -46.5mA    -101.2mA
-980mV    -78.83mA   -46.5mA    -101.2mA
-660mV    -76.17mA   -45.35mA   -100.2mA
-420mV    -51.93mA   -30.73mA   -70.08mA
140mV     15.93mA    9.072mA    22.96mA
540mV     54.77mA    30.25mA    80.67mA
860mV     76.84mA    41.64mA    113.6mA
1.18V     89.58mA    47.74mA    132.5mA
3.18V     100.1mA    56.52mA    143.6mA
4.46V     121.5mA    64.18mA    179.9mA
5V        121.5mA    64.18mA    179.9mA
[Pullup]
|Voltage   I(typ)   I(min)   I(max)
-2.5V     139.1mA    85.69mA    180.7mA
-1.4V     133.7mA    85.69mA    168.9mA
-840mV    88.37mA    60.77mA    112.6mA
360mV     -30.93mA   -20.47mA   -42.36mA
760mV     -57.06mA   -36.84mA   -78.41mA
1.16V     -73.62mA   -46.07mA   -102.1mA
1.8V      -83.07mA   -50.45mA   -117.2mA
3.4V      -88mA      -53mA      -123.9mA
3.48V     -90mA      -100mA     -124.1mA
3.64V     -100mA     -100mA     -124.1mA
3.72V     -100mA     -100mA     -1A
4.92V     -100mA     -100mA     -1A
[GND_clamp]
|Voltage   I(typ)   I(min)   I(max)
-2.5V     -5.082A    -4.628A    -3.442A
-940mV    -5.082A    -4.628A    -3.442A
-880mV    -5.082A    -910.9mA   -3.442A
-820mV    -518.2mA   -200mA     -3.442A
-760mV    -65.41mA   -52.42mA   -196.1mA
-700mV    -14.98mA   -16.7mA    -21.53mA
-640mV    -6.913mA   -6.897mA   -7.503mA
2.48V     0A         43.12nA    0A
[POWER_clamp]
|Voltage   I(typ)   I(min)   I(max)
-2.49V    840.6mA    685.1mA    983.2mA
-1.11V    94.66mA    110.3mA    86.66mA
-1.08V    80.16mA    98.83mA    69.45mA
-1.05V    66.06mA    87.6mA     52.92mA
-990mV    39.64mA    65.82mA    23.5mA
-960mV    27.85mA    55.39mA    12.18mA
-930mV    17.59mA    45.37mA    4.744mA
-870mV    4.273mA    27.14mA    331.7uA
-810mV    535.4uA    12.72mA    17.14uA
-750mV    53.58uA    4.101mA    867.4nA
-630mV    505.2nA    181.4uA    0A
0V        0A         61.21nA    0A
[Ramp]
| variable   typ   min   max
dV/dt_r  1.20750/1.29660n   0.99036/2.29959n   1.38252/1.19782n
dV/dt_f  1.26241/1.27627n   1.00776/1.91550n   1.43924/0.66013n
R_load = 50.000000
[Rising Waveform]
R_fixture= 50.000000
V_fixture= 2.500000
V_fixture_min= 2.300000
V_fixture_max= 2.700000
|time   V(typ)   V(min)   V(max)
0s        396mV      620.4mV    301.3mV
1.001ns   1.256V     616.4mV    2.565V
2.002ns   2.49V      2.224V     2.694V
3.003ns   2.495V     2.291V     2.697V
6.006ns   2.5V       2.298V     2.7V
99.1ns    2.5V       2.3V       2.7V
[Rising Waveform]
R_fixture= 50.000000
V_fixture= 0.0
V_fixture_min= 0.0
V_fixture_max= 0.0
|time   V(typ)   V(min)   V(max)
0s        2.072nV    301.7nV    1.128nV
10.01ns   2.012V     1.635V     2.304V
20.02ns   2.012V     1.651V     2.304V
991ns     2.013V     1.651V     2.304V
[Falling Waveform]
R_fixture= 50.000000
V_fixture= 2.500000
V_fixture_min= 2.300000
V_fixture_max= 2.700000
|time   V(typ)   V(min)   V(max)
0s        2.5V       2.3V       2.7V
10.01ns   397.6mV    639.9mV    301.3mV
20.02ns   396mV      620.8mV    301.3mV
30.03ns   396mV      620.4mV    301.3mV
991ns     396mV      620.4mV    301.3mV
[Falling Waveform]
R_fixture= 50.000000
V_fixture= 0.0
V_fixture_min= 0.0
V_fixture_max= 0.0
|time   V(typ)   V(min)   V(max)
0s        2.013V     1.651V     2.304V
480.5ps   2.012V     1.651V     2.31V
640.6ps   2.012V     1.651V     2.135V
961ps     1.518V     1.639V     1.129V
1.281ns   792.3mV    1.297V     125.4mV
1.522ns   338.7mV    958.2mV    8.053mV
1.762ns   56.86mV    629.8mV    4.279mV
2.242ns   5.095mV    194.9mV    2.432mV
2.963ns   2.45mV     8.498mV    1.429mV
39.88ns   2.072nV    301.7nV    1.128nV
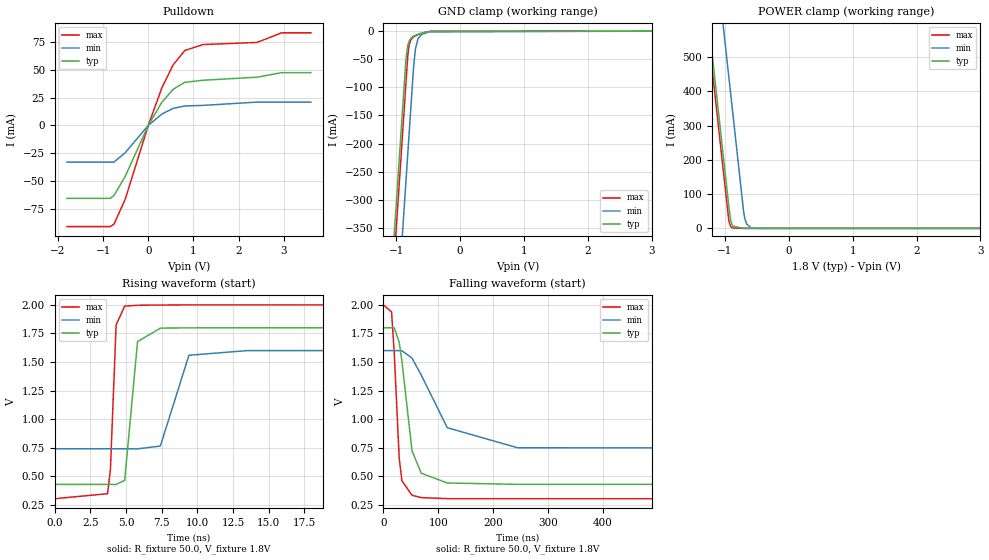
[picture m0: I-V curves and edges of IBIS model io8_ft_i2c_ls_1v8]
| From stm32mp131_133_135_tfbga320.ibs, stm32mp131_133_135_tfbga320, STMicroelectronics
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|   io8_ft_i2c_ls_1v8
[Model]   io8_ft_i2c_ls_1v8
Model_type I/O_open_drain
Polarity   Non-Inverting
Enable   Active-Low
| CAP_THRESHOLD on pad IOFT is "UDTCAPC" :
| Rising=20.0% of vddiom   Falling=80.0% of vddiom
| C_comp min and max val. don't necessarily correlate with the min and max pvt
| but are the smallest and greatest pad capacitance found.
| var   typ   min   max
C_comp   1.45870pF  1.28163pF  1.53120pF
Vinl = 540.0mV
Vinh = 1.26V
Vmeas = 900.0mV   | Reference voltage for timing measurements
Cref  = 100.0nF   | Timing specification test load capacitance value
Rref  = 1.0kOhm   | Timing specification test load resistance value
Vref  = 900.1mV   | Timing specification test load voltage
[Model Spec]
| TIME_THRESHOLD on pin ZIV11 is "CMOS" :
| Rising=40.0% of vdd   Falling=60.0% of vdd
Vinl 740.80000mV 668.80000mV 832.80000mV
Vinh 1.03520V 915.20000mV 1.12020V
| variable   typ   min   max
[Temperature Range] 25.0 140.0 -40.0
| variable   typ   min   max
[Voltage Range] 1.8V 1.6V 2.0V
| variable   typ   min   max
[POWER Clamp Reference] 1.8V 1.6V 2.0V
| variable   typ   min   max
[GND Clamp Reference] 0V 0V 0V
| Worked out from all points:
|   slope of the pulldown table from 0 to 0.27 V, typ, clamps not added: 14.5 ohm
|   GND clamp passes 1 mA (typ) near -0.49 V on its own axis
|   POWER clamp passes 1 mA (typ) near -0.83 V on its own axis
|   rising waveform, R_fixture 50.0, V_fixture 1.8V: 20-80 % time 406ps typ, 830ps min, 292ps max; typ from 0.428 V to 1.8 V
|   falling waveform, R_fixture 50.0, V_fixture 1.8V: 20-80 % time 19.6ns typ, 57.4ns min, 10.2ns max; typ from 1.8 V to 0.428 V
[POWER Clamp]
-1.8V     1.527A     1.905A     1.483A
-940mV    65mA       442.8mA    22.8mA
-910mV    22.04mA    391.8mA    5.123mA
-880mV    6.856mA    340.8mA    1.151mA
-710mV    9.171uA    51.95mA    243.5nA
-690mV    4.21uA     29.62mA    90.02nA
-660mV    1.309uA    12.75mA    20.26nA
-600mV    126nA      2.365mA    1.066nA
-490mV    1.212nA    108uA      55.85pA
3.6V      0A         0A         0A
[GND Clamp]
-1.8V     -1.667A    -1.885A    -1.711A
-1.2V     -647.4mA   -864.8mA   -690.7mA
-850mV    -52.41mA   -269.8mA   -95.74mA
-820mV    -25.59mA   -218.8mA   -44.74mA
-800mV    -18.09mA   -184.8mA   -25.73mA
-770mV    -12.56mA   -133.8mA   -15.37mA
-730mV    -9.041mA   -65.79mA   -10.63mA
-700mV    -7.362mA   -32.04mA   -8.614mA
-660mV    -5.605mA   -13.99mA   -6.466mA
-600mV    -3.519mA   -5.612mA   -3.864mA
-470mV    -757.9uA   -1.397mA   -584.8uA
3.6V      7.149nA    1.67uA     413.4pA
| variable   typ   min   max
[Pullup Reference] 1.8V 1.6V 2.0V
| variable   typ   min   max
[Pulldown Reference] 0V 0V 0V
[Pulldown]
-1.8V     -65.59mA   -33.02mA   -91mA
-840mV    -65.59mA   -33.02mA   -91mA
-760mV    -63.14mA   -33.02mA   -88.84mA
-510mV    -45.79mA   -24.49mA   -66.42mA
0V        0A         0A         0A
300mV     20.74mA    10.18mA    33.66mA
550mV     32.47mA    15.31mA    54.44mA
810mV     38.76mA    17.5mA     67.42mA
1.21V     40.63mA    18.01mA    72.72mA
2.41V     43.39mA    20.99mA    74.66mA
2.95V     47.42mA    20.99mA    83.3mA
3.6V      47.42mA    20.99mA    83.3mA
[Ramp]
dV/dt_r 823.09565mV/400.07771ps 515.90748mV/827.80235ps 1.0183V/271.63722ps
dV/dt_f 823.10173mV/19.55376ns 515.99677mV/54.69946ns 1.0183V/10.16466ns
R_load = 50.0
| Removed startup time: 0s 0s 0s  .
| Removed end time: 2.1994us.
[Rising Waveform]
R_fixture   = 50.0
V_fixture   = 1.8V
V_fixture_min = 1.6V
V_fixture_max = 2.0V
0s        428.2mV    740.1mV    302.8mV
3.7ns     428.1mV    740.1mV    346.7mV
3.9ns     427.8mV    740.1mV    560.1mV
4.3ns     426.8mV    740.1mV    1.825V
4.9ns     464.2mV    740.1mV    1.99V
5.8ns     1.678V     739.4mV    1.997V
7.4ns     1.797V     764.2mV    1.999V
9.4ns     1.799V     1.559V     2V
13.5ns    1.8V       1.6V       2V
2.199us   1.8V       1.6V       2V
| Removed startup time: 0s 0s 0s  .
| Removed end time: 2.1994us.
[Falling Waveform]
R_fixture   = 50.0
V_fixture   = 1.8V
V_fixture_min = 1.6V
V_fixture_max = 2.0V
0s        1.8V       1.6V       2V
14.7ns    1.8V       1.6V       1.939V
19.6ns    1.8V       1.6V       1.582V
28.6ns    1.673V     1.6V       661.9mV
33.5ns    1.513V     1.599V     460.5mV
52ns      721.6mV    1.534V     332.9mV
68.9ns    525.8mV    1.385V     312.2mV
116.2ns   440.5mV    924.7mV    303.4mV
244.4ns   428.3mV    748.9mV    302.8mV
2.199us   428.2mV    740mV      302.8mV
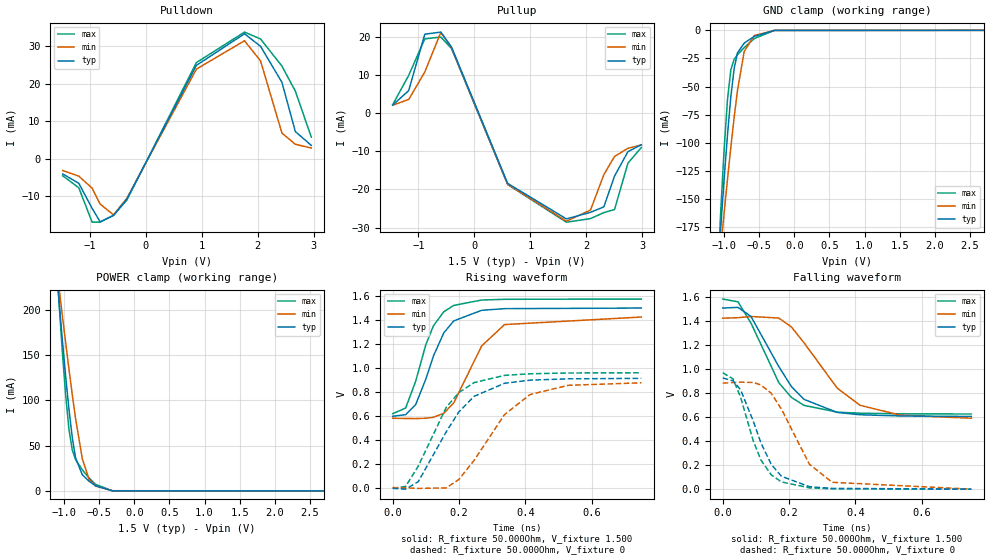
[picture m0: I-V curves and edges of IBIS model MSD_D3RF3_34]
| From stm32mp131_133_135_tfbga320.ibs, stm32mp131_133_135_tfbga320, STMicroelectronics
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[Model] MSD_D3RF3_34
Model_type   I/O
C_comp 2.240pF   2.160pF   2.357pF
Vinh = 925.000mV
Vinl = 575.000mV
Vmeas = 750.000mV
Vref = 750.000mV
[Model Spec]
Vinh   925.000mV   888.000mV   963.000mV
Vinl   575.000mV   538.000mV   613.000mV
Vmeas   750.000mV   713.000mV   788.000mV
Vref   750.000mV   713.000mV   788.000mV
[Temperature Range]   25.000   125.000   -40.000
[Voltage Range]   1.500V   1.425V   1.575V
[GND Clamp Reference]   0.00V   0.00V   0.00V
[Pulldown Reference]   0.00V   0.00V   0.00V
[POWER Clamp Reference]   1.500V   1.425V   1.575V
[Pullup Reference]   1.500V   1.425V   1.575V
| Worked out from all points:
|   slope of the pulldown table from 0 to 0.225 V, typ, clamps not added: 31.5 ohm
|   slope of the pullup table from 0 to 0.225 V, typ, clamps not added: 26.9 ohm
|   GND clamp passes 1 mA (typ) near -0.40 V on its own axis
|   POWER clamp passes 1 mA (typ) near -0.41 V on its own axis
|   rising waveform, R_fixture 50.000Ohm, V_fixture 1.500: 20-80 % time 77.2ps typ, 93.4ps min, 68.4ps max; typ from 0.596 V to 1.5 V
|   rising waveform, R_fixture 50.000Ohm, V_fixture 0: 20-80 % time 122ps typ, 138ps min, 111ps max; typ from -0.005 V to 0.913 V
|   falling waveform, R_fixture 50.000Ohm, V_fixture 1.500: 20-80 % time 118ps typ, 144ps min, 104ps max; typ from 1.51 V to 0.605 V
|   falling waveform, R_fixture 50.000Ohm, V_fixture 0: 20-80 % time 82.4ps typ, 101ps min, 72.4ps max; typ from 0.925 V to 0 V
[GND Clamp]
-1.48V    -593.9mA   -479.7mA   -763.1mA
-1.098V   -218.2mA   -223.3mA   -220.2mA
-1.05V    -174.1mA   -192.4mA   -159.6mA
-1.002V   -131.9mA   -161.9mA   -105.2mA
-954.6mV  -92.83mA   -132.3mA   -61.52mA
-906.8mV  -59.01mA   -103.9mA   -35.13mA
-859.1mV  -33.79mA   -77.16mA   -25.62mA
-811.4mV  -19.9mA    -53.07mA   -21.61mA
-715.9mV  -11.4mA    -18.73mA   -15.39mA
-572.7mV  -5.41mA    -4.631mA   -7.313mA
-286.4mV  -67.53uA   -115uA     -52.79uA
2.959V    27.81nA    447.4nA    3.163nA
[Power Clamp]
-1.459V   577.6mA    479.2mA    722.9mA
-1.077V   211mA      225.5mA    210.2mA
-1.03V    168.2mA    194.7mA    155.6mA
-981.8mV  127.5mA    164.3mA    106.7mA
-934.1mV  90.48mA    134.7mA    68.25mA
-886.4mV  59mA       106.2mA    45.16mA
-838.6mV  36.16mA    79.4mA     34.6mA
-743.2mV  17.85mA    35.54mA    23.3mA
-647.7mV  10.74mA    12.83mA    14.33mA
-552.3mV  5.472mA    5.424mA    7.214mA
-313.6mV  99.23uA    231.1uA    112.6uA
2.98V     -43.92nA   -827nA     -4.179nA
[Pulldown]
-1.48V    -4mA       -3.1mA     -4.5mA
-1.193V   -6.5mA     -4.6mA     -7.7mA
-954.6mV  -13.17mA   -7.8mA     -16.87mA
-811.4mV  -16.78mA   -12.04mA   -16.85mA
-572.7mV  -15.06mA   -14.91mA   -15.04mA
-334.1mV  -10.72mA   -10.48mA   -10.95mA
906.8mV   24.93mA    23.93mA    25.67mA
1.766V    33.35mA    31.49mA    33.8mA
2.052V    30.02mA    26.14mA    31.97mA
2.434V    20.42mA    6.9mA      24.74mA
2.673V    7.3mA      3.9mA      18.1mA
2.959V    3.6mA      2.9mA      5.8mA
[Pullup]
-1.459V   2.1mA      2.057mA    2.214mA
-1.173V   5.9mA      3.586mA    9.9mA
-886.4mV  20.67mA    10.76mA    19.45mA
-600mV    21.23mA    21.13mA    19.93mA
-409.1mV  17.29mA    17.18mA    16.92mA
593.2mV   -18.41mA   -18.64mA   -18.71mA
1.643V    -27.73mA   -28.33mA   -28.59mA
2.073V    -25.99mA   -25.39mA   -27.65mA
2.311V    -24.57mA   -16.14mA   -26.08mA
2.502V    -16.5mA    -11.36mA   -25.27mA
2.741V    -10.1mA    -9.229mA   -13.11mA
2.98V     -8.3mA     -8.343mA   -9.029mA
[Ramp]
R_load=50.000Ohm
dV/dt_r   542.580mV/99.500ps  515.459mV/116.500ps  572.760mV/90.500ps
dV/dt_f   542.580mV/100.500ps  515.459mV/124.500ps  572.760mV/89.000ps
[Rising waveform]
R_fixture=50.000Ohm
V_fixture=1.500
V_fixture_min=1.425
V_fixture_max=1.575
0s        596.5mV    580.1mV    618.2mV
39ps      609.5mV    577.8mV    665.1mV
69ps      692.6mV    577.2mV    887.1mV
100ps     909mV      580mV      1.196V
123ps     1.102V     588.2mV    1.353V
154ps     1.293V     621.6mV    1.469V
184ps     1.393V     708.6mV    1.522V
268ps     1.481V     1.184V     1.567V
337ps     1.495V     1.362V     1.573V
749ps     1.5V       1.425V     1.575V
[Rising waveform]
R_fixture=50.000Ohm
V_fixture=0
0s        -5.453mV   818.4uV    -5.814mV
39ps      -12.32mV   -1.118mV   10.88mV
77ps      50.28mV    -5.812mV   180mV
161ps     465.3mV    -1.835mV   669.3mV
199ps     631.8mV    67.48mV    794mV
245ps     762.4mV    227.5mV    877.3mV
337ps     871.9mV    610.9mV    937.9mV
414ps     898mV      778.2mV    951.1mV
529ps     908.8mV    854.7mV    957.7mV
749ps     913mV      875.8mV    959.5mV
[Falling waveform]
R_fixture=50.000Ohm
V_fixture=1.500
V_fixture_min=1.425
V_fixture_max=1.575
0s        1.507V     1.423V     1.582V
46ps      1.513V     1.427V     1.559V
85ps      1.438V     1.437V     1.383V
169ps     1.02V      1.424V     886.4mV
207ps     854mV      1.35V      763.5mV
245ps     747.3mV    1.218V     697.5mV
345ps     638.6mV    841.1mV    640.9mV
414ps     619.2mV    697.6mV    632.2mV
536ps     609.1mV    615.2mV    627mV
749ps     605.2mV    590.6mV    625.5mV
[Falling waveform]
R_fixture=50.000Ohm
V_fixture=0
0s        925.2mV    882.2mV    968.8mV
31ps      902.2mV    887.3mV    918.6mV
54ps      826.7mV    891.1mV    763.9mV
92ps      566.9mV    887.7mV    402.4mV
115ps     386.2mV    867.4mV    242.8mV
146ps     207.4mV    798.8mV    119.8mV
177ps     107.1mV    665.5mV    60.24mV
261ps     20.51mV    207.7mV    11.13mV
330ps     6.543mV    57.15mV    2.982mV
749ps     21.46uV    267.9uV    14.11uV
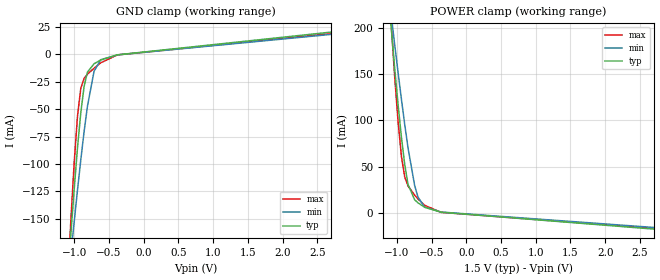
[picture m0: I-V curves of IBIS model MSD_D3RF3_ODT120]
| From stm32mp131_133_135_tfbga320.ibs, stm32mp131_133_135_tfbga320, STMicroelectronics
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[Model] MSD_D3RF3_ODT120
Model_type   Input
C_comp 2.181pF   2.140pF   2.280pF
Vinh = 925.000mV
Vinl = 575.000mV
[Model Spec]
Vinh   925.000mV   888.000mV   963.000mV
Vinl   575.000mV   538.000mV   613.000mV
[Temperature Range]   25.000   125.000   -40.000
[Voltage Range]   1.500V   1.425V   1.575V
[GND Clamp Reference]   0.00V   0.00V   0.00V
[POWER Clamp Reference]   1.500V   1.425V   1.575V
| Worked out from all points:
|   GND clamp passes 1 mA (typ) near -0.44 V on its own axis
|   POWER clamp passes 1 mA (typ) near -0.39 V on its own axis
[GND Clamp]
-1.48V    -577.6mA   -465.4mA   -747.1mA
-1.098V   -207mA     -212.9mA   -210.2mA
-1.05V    -163.8mA   -182.4mA   -151.2mA
-1.002V   -122.8mA   -152.6mA   -98.72mA
-954.6mV  -85.17mA   -123.8mA   -56.41mA
-906.8mV  -53.02mA   -96.03mA   -30.76mA
-859.1mV  -29.15mA   -70.25mA   -21.7mA
-811.4mV  -16.07mA   -47.25mA   -18.06mA
-715.9mV  -8.511mA   -15.32mA   -12.55mA
-620.5mV  -5.113mA   -4.826mA   -7.688mA
-381.8mV  -365uA     -430.6uA   -437.6uA
2.959V    22.13mA    19.88mA    20.67mA
[Power Clamp]
-1.459V   556.7mA    460.9mA    703mA
-1.077V   196.8mA    211.5mA    199.6mA
-1.03V    155.5mA    181.4mA    146.4mA
-981.8mV  116.9mA    151.8mA    98.64mA
-934.1mV  82.02mA    123.1mA    61.14mA
-886.4mV  52.35mA    95.66mA    38.94mA
-838.6mV  30.82mA    70.18mA    29.16mA
-743.2mV  14.21mA    29.64mA    19.24mA
-695.5mV  10.99mA    17.18mA    15.18mA
-600mV    6.166mA    6.426mA    8.339mA
-361.4mV  816uA      995.3uA    663uA
2.98V     -19.07mA   -17.17mA   -18.22mA
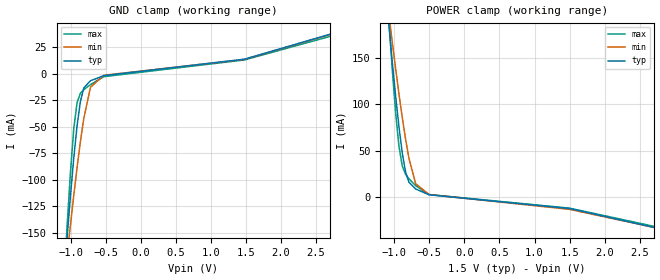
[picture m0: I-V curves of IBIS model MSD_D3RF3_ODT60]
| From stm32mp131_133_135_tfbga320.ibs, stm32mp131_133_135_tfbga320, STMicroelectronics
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[Model] MSD_D3RF3_ODT60
Model_type   Input
C_comp 2.171pF   2.128pF   2.226pF
Vinh = 925.000mV
Vinl = 575.000mV
[Temperature Range]   25.000   125.000   -40.000
[Voltage Range]   1.500V   1.425V   1.575V
[GND Clamp Reference]   0.00V   0.00V   0.00V
[POWER Clamp Reference]   1.500V   1.425V   1.575V
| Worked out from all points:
|   GND clamp passes 1 mA (typ) near -0.48 V on its own axis
|   POWER clamp passes 1 mA (typ) near -0.30 V on its own axis
[GND Clamp]
-1.48V    -562.7mA   -449.4mA   -732.1mA
-1.098V   -197.3mA   -201.4mA   -201.6mA
-1.05V    -155.3mA   -171.8mA   -144.4mA
-1.002V   -115.6mA   -142.8mA   -93.39mA
-954.6mV  -79.61mA   -114.8mA   -52.04mA
-906.8mV  -48.87mA   -88.29mA   -26.94mA
-859.1mV  -25.89mA   -63.76mA   -18.27mA
-811.4mV  -13.34mA   -42.19mA   -14.97mA
-715.9mV  -6.476mA   -12.63mA   -10.14mA
-525mV    -1.688mA   -1.345mA   -2.655mA
1.48V     13.83mA    13.63mA    13.12mA
2.959V    42.37mA    42.04mA    40.01mA
[Power Clamp]
-1.459V   537.8mA    440.7mA    684.7mA
-1.077V   185.4mA    196.8mA    190.9mA
-1.03V    146.3mA    167.6mA    138.7mA
-981.8mV  109.6mA    139.1mA    91.85mA
-934.1mV  76.33mA    111.7mA    55.24mA
-886.4mV  47.71mA    86mA       33.83mA
-838.6mV  27.02mA    62.46mA    24.77mA
-790.9mV  16.29mA    42mA       19.98mA
-695.5mV  9.062mA    14.68mA    12.6mA
-504.6mV  2.831mA    3.039mA    3.087mA
1.5V      -11.98mA   -12.86mA   -11.59mA
2.98V     -36.95mA   -36.78mA   -35.63mA
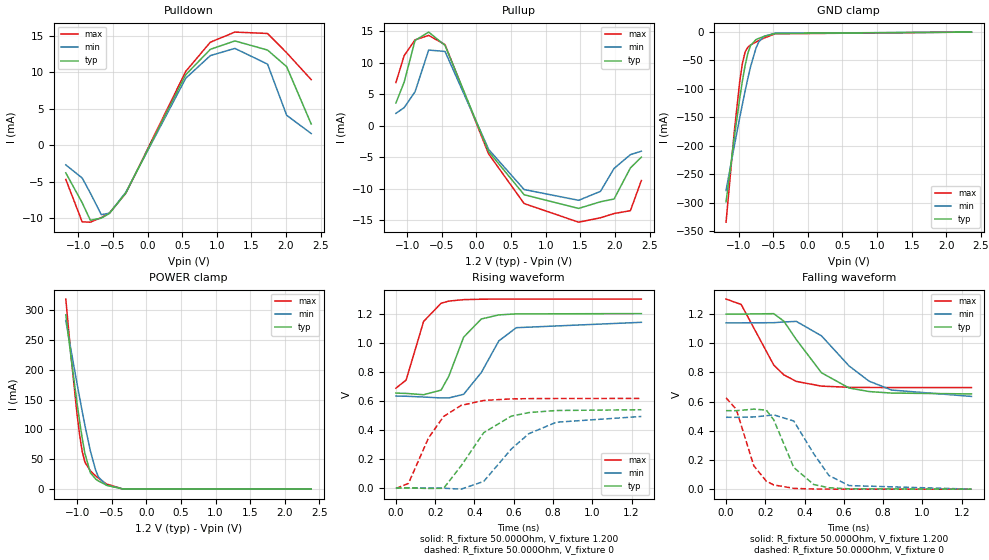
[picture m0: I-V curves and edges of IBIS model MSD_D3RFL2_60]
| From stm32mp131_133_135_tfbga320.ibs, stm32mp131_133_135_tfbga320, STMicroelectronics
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[Model] MSD_D3RFL2_60
Model_type   I/O
C_comp 2.255pF   2.172pF   2.373pF
Vinh = 820.000mV
Vinl = 380.000mV
Vmeas = 600.000mV
Vref = 600.000mV
[Model Spec]
Vinh   820.000mV   790.000mV   870.000mV
Vinl   380.000mV   350.000mV   430.000mV
Vmeas   600.000mV   570.000mV   650.000mV
Vref   600.000mV   570.000mV   650.000mV
[Receiver Thresholds]
Vth   =  0.600V
Vth_min  =  0.5880V
Vth_max  =  0.6120V
Vinh_ac  =  0.220V
Vinh_dc  =  0.130V
Vinl_ac  = -0.220V
Vinl_dc  = -0.130V
Tslew_ac =  5.000ns |Not specified, so set to high value
[Temperature Range]   25.000   125.000   -40.000
[Voltage Range]   1.200V   1.140V   1.300V
[GND Clamp Reference]   0.00V   0.00V   0.00V
[Pulldown Reference]   0.00V   0.00V   0.00V
[POWER Clamp Reference]   1.200V   1.140V   1.300V
[Pullup Reference]   1.200V   1.140V   1.300V
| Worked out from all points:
|   slope of the pulldown table from 0 to 0.18 V, typ, clamps not added: 50.1 ohm
|   slope of the pullup table from 0 to 0.18 V, typ, clamps not added: 42.9 ohm
|   GND clamp passes 1 mA (typ) near -0.41 V on its own axis
|   POWER clamp passes 1 mA (typ) near -0.41 V on its own axis
|   rising waveform, R_fixture 50.000Ohm, V_fixture 1.200: 20-80 % time 103ps typ, 131ps min, 85.3ps max; typ from 0.653 V to 1.2 V
|   rising waveform, R_fixture 50.000Ohm, V_fixture 0: 20-80 % time 177ps typ, 217ps min, 147ps max; typ from 0 V to 0.538 V
|   falling waveform, R_fixture 50.000Ohm, V_fixture 1.200: 20-80 % time 192ps typ, 240ps min, 154ps max; typ from 1.2 V to 0.653 V
|   falling waveform, R_fixture 50.000Ohm, V_fixture 0: 20-80 % time 109ps typ, 134ps min, 93.5ps max; typ from 0.538 V to 0 V
[GND Clamp]
-1.182V   -298.7mA   -278.8mA   -334.6mA
-1.064V   -186.5mA   -201.2mA   -176.5mA
-984.9mV  -117.2mA   -151mA     -87.71mA
-945.5mV  -85.9mA    -126.8mA   -54.95mA
-906.1mV  -58.53mA   -103.4mA   -34.88mA
-866.7mV  -37.07mA   -81.25mA   -26.52mA
-827.3mV  -23.31mA   -60.73mA   -22.77mA
-748.5mV  -13.21mA   -27.8mA    -17.44mA
-709.1mV  -11.06mA   -17.22mA   -14.97mA
-630.3mV  -7.606mA   -7.312mA   -10.35mA
-472.7mV  -2.342mA   -2.056mA   -3.037mA
2.364V    24.05nA    406.6nA    2.606nA
[Power Clamp]
-1.164V   291.7mA    282.1mA    318.2mA
-1.085V   217.9mA    230.4mA    219.1mA
-1.006V   147.8mA    179.6mA    130.3mA
-966.7mV  115.3mA    154.7mA    92.57mA
-927.3mV  85.58mA    130.4mA    63.26mA
-887.9mV  59.89mA    107mA      45.2mA
-809.1mV  27.4mA     63.99mA    30.58mA
-730.3mV  16.7mA     30.88mA    21.97mA
-690.9mV  13.64mA    20.08mA    18.15mA
-572.7mV  6.466mA    6.412mA    8.539mA
-336.4mV  182.5uA    350.9uA    204.7uA
2.382V    -20.25nA   -432nA     -2.132nA
[Pulldown]
-1.182V   -3.8mA     -2.7mA     -4.7mA
-945.5mV  -7.9mA     -4.5mA     -10.52mA
-827.3mV  -10.3mA    -6.57mA    -10.57mA
-669.7mV  -10.02mA   -9.53mA    -9.94mA
-551.5mV  -9.368mA   -9.334mA   -9.306mA
-315.1mV  -6.567mA   -6.464mA   -6.607mA
551.5mV   9.679mA    9.198mA    10.14mA
906.1mV   13.16mA    12.3mA     14.14mA
1.261V    14.32mA    13.29mA    15.53mA
1.733V    13.06mA    11.13mA    15.34mA
2.009V    10.78mA    4.11mA     12.69mA
2.364V    2.9mA      1.6mA      9mA
[Pullup]
-1.164V   3.6mA      1.952mA    6.838mA
-1.045V   6.9mA      2.862mA    11.11mA
-887.9mV  13.51mA    5.376mA    13.61mA
-690.9mV  14.84mA    11.99mA    14.32mA
-454.5mV  12.73mA    11.77mA    12.85mA
175.8mV   -4.107mA   -3.772mA   -4.491mA
687.9mV   -10.95mA   -10.13mA   -12.35mA
1.476V    -13.13mA   -11.84mA   -15.31mA
1.791V    -12.07mA   -10.42mA   -14.61mA
1.988V    -11.63mA   -6.784mA   -13.94mA
2.224V    -6.7mA     -4.595mA   -13.48mA
2.382V    -5mA       -4.048mA   -8.7mA
[Ramp]
R_load=50.000Ohm
dV/dt_r   325.710mV/140.500ps  300.149mV/175.500ps  366.060mV/116.500ps
dV/dt_f   325.740mV/151.500ps  300.090mV/188.500ps  366.060mV/124.500ps
[Rising waveform]
R_fixture=50.000Ohm
V_fixture=1.200
V_fixture_min=1.140
V_fixture_max=1.300
0s        652.8mV    632.7mV    686.9mV
52ps      650.8mV    631.2mV    742.8mV
141ps     641.6mV    625.8mV    1.146V
230ps     673.4mV    619.4mV    1.271V
269ps     767.9mV    619.4mV    1.286V
345ps     1.038V     644.8mV    1.296V
435ps     1.163V     794.7mV    1.299V
524ps     1.191V     1.012V     1.3V
613ps     1.198V     1.103V     1.3V
1.25ns    1.2V       1.14V      1.3V
[Rising waveform]
R_fixture=50.000Ohm
V_fixture=0
0s        128.9uV    127.7uV    -3.707mV
64ps      683.8uV    487.7uV    31.51mV
166ps     -3.462mV   622.1uV    344.5mV
243ps     -2.163mV   -1.678mV   492.3mV
332ps     152.1mV    -8.254mV   568.2mV
447ps     380.6mV    44.98mV    602.2mV
588ps     494.5mV    268.5mV    613mV
677ps     518.8mV    373.5mV    614.7mV
817ps     533.1mV    452.4mV    615.6mV
1.25ns    538.4mV    492mV      616mV
[Falling waveform]
R_fixture=50.000Ohm
V_fixture=1.200
V_fixture_min=1.140
V_fixture_max=1.300
0s        1.2V       1.14V      1.303V
77ps      1.2V       1.14V      1.266V
243ps     1.203V     1.141V     850.5mV
294ps     1.152V     1.146V     783.7mV
358ps     1.025V     1.15V      738.5mV
486ps     797.9mV    1.051V     706.2mV
626ps     693.7mV    845.4mV    698.3mV
728ps     669.1mV    740.5mV    697mV
843ps     658.6mV    679.4mV    696.4mV
1.25ns    652.8mV    635.7mV    696.1mV
[Falling waveform]
R_fixture=50.000Ohm
V_fixture=0
0s        538.1mV    492.8mV    625.8mV
52ps      537.8mV    492.4mV    547.1mV
141ps     548.6mV    494.9mV    161.2mV
205ps     541.9mV    503.3mV    54.78mV
243ps     474.8mV    509.2mV    29.05mV
345ps     148.5mV    467.2mV    5.444mV
447ps     31.52mV    241.9mV    1.01mV
524ps     9.877mV    93.5mV     245uV
626ps     2.294mV    24.61mV    16.78uV
1.25ns    -11.36uV   10.36uV    720.5nV
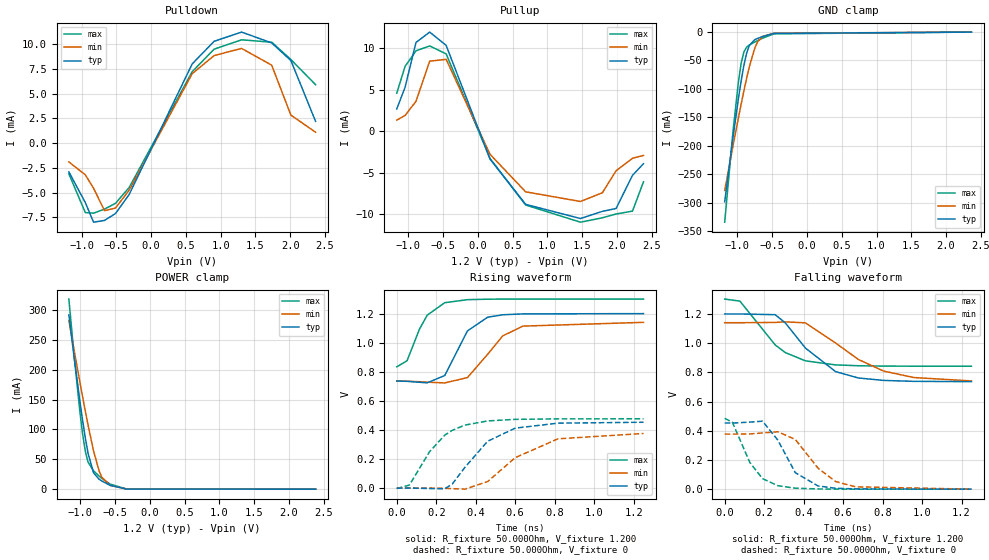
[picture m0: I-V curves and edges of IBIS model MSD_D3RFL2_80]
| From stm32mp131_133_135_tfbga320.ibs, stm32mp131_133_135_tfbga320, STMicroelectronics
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[Model] MSD_D3RFL2_80
Model_type   I/O
C_comp 2.255pF   2.172pF   2.373pF
Vinh = 820.000mV
Vinl = 380.000mV
Vmeas = 600.000mV
Vref = 600.000mV
[Model Spec]
Vinh   820.000mV   790.000mV   870.000mV
Vinl   380.000mV   350.000mV   430.000mV
Vmeas   600.000mV   570.000mV   650.000mV
Vref   600.000mV   570.000mV   650.000mV
[Receiver Thresholds]
Vth   =  0.600V
Vth_min  =  0.5880V
Vth_max  =  0.6120V
Vinh_ac  =  0.220V
Vinh_dc  =  0.130V
Vinl_ac  = -0.220V
Vinl_dc  = -0.130V
Tslew_ac =  5.000ns |Not specified, so set to high value
[Temperature Range]   25.000   125.000   -40.000
[Voltage Range]   1.200V   1.140V   1.300V
[GND Clamp Reference]   0.00V   0.00V   0.00V
[Pulldown Reference]   0.00V   0.00V   0.00V
[POWER Clamp Reference]   1.200V   1.140V   1.300V
[Pullup Reference]   1.200V   1.140V   1.300V
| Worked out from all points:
|   slope of the pulldown table from 0 to 0.18 V, typ, clamps not added: 63.6 ohm
|   slope of the pullup table from 0 to 0.18 V, typ, clamps not added: 52.8 ohm
|   GND clamp passes 1 mA (typ) near -0.41 V on its own axis
|   POWER clamp passes 1 mA (typ) near -0.41 V on its own axis
|   rising waveform, R_fixture 50.000Ohm, V_fixture 1.200: 20-80 % time 108ps typ, 144ps min, 95.2ps max; typ from 0.736 V to 1.2 V
|   rising waveform, R_fixture 50.000Ohm, V_fixture 0: 20-80 % time 186ps typ, 231ps min, 162ps max; typ from 0 V to 0.453 V
|   falling waveform, R_fixture 50.000Ohm, V_fixture 1.200: 20-80 % time 201ps typ, 272ps min, 183ps max; typ from 1.2 V to 0.736 V
|   falling waveform, R_fixture 50.000Ohm, V_fixture 0: 20-80 % time 114ps typ, 146ps min, 107ps max; typ from 0.453 V to 0 V
[GND Clamp]
-1.182V   -298.7mA   -278.8mA   -334.6mA
-1.064V   -186.5mA   -201.2mA   -176.5mA
-984.9mV  -117.2mA   -151mA     -87.71mA
-945.5mV  -85.9mA    -126.8mA   -54.95mA
-906.1mV  -58.53mA   -103.4mA   -34.88mA
-866.7mV  -37.07mA   -81.25mA   -26.52mA
-827.3mV  -23.31mA   -60.73mA   -22.77mA
-748.5mV  -13.21mA   -27.8mA    -17.44mA
-709.1mV  -11.06mA   -17.22mA   -14.97mA
-630.3mV  -7.606mA   -7.312mA   -10.35mA
-472.7mV  -2.342mA   -2.056mA   -3.037mA
2.364V    24.05nA    406.6nA    2.606nA
[Power Clamp]
-1.164V   291.7mA    282.1mA    318.2mA
-1.085V   217.9mA    230.4mA    219.1mA
-1.006V   147.8mA    179.6mA    130.3mA
-966.7mV  115.3mA    154.7mA    92.57mA
-927.3mV  85.58mA    130.4mA    63.26mA
-887.9mV  59.89mA    107mA      45.2mA
-809.1mV  27.4mA     63.99mA    30.58mA
-730.3mV  16.7mA     30.88mA    21.97mA
-690.9mV  13.64mA    20.08mA    18.15mA
-572.7mV  6.466mA    6.412mA    8.539mA
-336.4mV  182.5uA    350.9uA    204.7uA
2.382V    -20.25nA   -432nA     -2.132nA
[Pulldown]
-1.182V   -2.9mA     -1.9mA     -3.1mA
-945.5mV  -6mA       -3.2mA     -7.01mA
-827.3mV  -7.98mA    -4.55mA    -7.07mA
-669.7mV  -7.802mA   -6.81mA    -6.66mA
-512.1mV  -7.11mA    -6.557mA   -6.074mA
-315.1mV  -5.18mA    -4.739mA   -4.478mA
590.9mV   8.002mA    7.016mA    7.22mA
906.1mV   10.28mA    8.84mA     9.488mA
1.3V      11.21mA    9.561mA    10.43mA
1.733V    10.12mA    7.873mA    10.19mA
2.009V    8.34mA     2.83mA     8.44mA
2.364V    2.2mA      1.1mA      5.9mA
[Pullup]
-1.164V   2.7mA      1.352mA    4.608mA
-1.045V   5.3mA      1.909mA    7.823mA
-887.9mV  10.71mA    3.619mA    9.704mA
-690.9mV  11.96mA    8.455mA    10.29mA
-454.5mV  10.36mA    8.68mA     9.331mA
175.8mV   -3.334mA   -2.766mA   -3.264mA
687.9mV   -8.798mA   -7.289mA   -8.88mA
1.476V    -10.51mA   -8.454mA   -10.95mA
1.791V    -9.646mA   -7.403mA   -10.42mA
1.988V    -9.3mA     -4.754mA   -9.962mA
2.224V    -5.3mA     -3.248mA   -9.615mA
2.382V    -3.9mA     -2.9mA     -6.085mA
[Ramp]
R_load=50.000Ohm
dV/dt_r   275.100mV/148.000ps  234.149mV/189.000ps  280.380mV/128.500ps
dV/dt_f   275.100mV/158.000ps  234.180mV/213.000ps  280.380mV/144.500ps
[Rising waveform]
R_fixture=50.000Ohm
V_fixture=1.200
V_fixture_min=1.140
V_fixture_max=1.300
0s        736.5mV    736.8mV    833.9mV
52ps      734.4mV    735.3mV    875.9mV
115ps     728.1mV    731.6mV    1.093V
154ps     724mV      728.7mV    1.189V
243ps     774.4mV    723.4mV    1.275V
358ps     1.081V     760.2mV    1.296V
460ps     1.175V     919.9mV    1.299V
537ps     1.192V     1.047V     1.3V
639ps     1.198V     1.114V     1.3V
1.25ns    1.2V       1.14V      1.3V
[Rising waveform]
R_fixture=50.000Ohm
V_fixture=0
0s        85.97uV    105.2uV    -2.584mV
64ps      564.1uV    382.4uV    21.36mV
166ps     -2.484mV   502.5uV    250.5mV
243ps     -4.398mV   -1.302mV   364.2mV
281ps     28.17mV    -3.417mV   397.5mV
345ps     142.8mV    -6.888mV   433.5mV
460ps     322.4mV    45.1mV     462.2mV
600ps     412.7mV    209.6mV    473mV
817ps     446.9mV    339.3mV    476.4mV
1.25ns    453.1mV    376mV      476.8mV
[Falling waveform]
R_fixture=50.000Ohm
V_fixture=1.200
V_fixture_min=1.140
V_fixture_max=1.300
0s        1.2V       1.14V      1.302V
77ps      1.2V       1.14V      1.288V
256ps     1.195V     1.142V     987.8mV
307ps     1.139V     1.146V     935.4mV
409ps     966.3mV    1.139V     878.8mV
562ps     805.1mV    1.001V     851.1mV
677ps     761.6mV    888.5mV    845.3mV
805ps     744.8mV    808.9mV    842.9mV
958ps     738.4mV    764.6mV    842.3mV
1.25ns    736.5mV    741.2mV    842.2mV
[Falling waveform]
R_fixture=50.000Ohm
V_fixture=0
0s        453mV      377.1mV    485.2mV
39ps      452.7mV    376.9mV    458.1mV
128ps     459.4mV    378.3mV    180.9mV
192ps     465.6mV    384.9mV    72.03mV
269ps     336.3mV    393.3mV    23.68mV
358ps     112.6mV    340.2mV    6.585mV
473ps     21.8mV     143.6mV    1.375mV
562ps     6.327mV    51.93mV    334.4uV
664ps     1.655mV    16.04mV    -16.03uV
1.25ns    5.35uV     12.15uV    -7.666uV
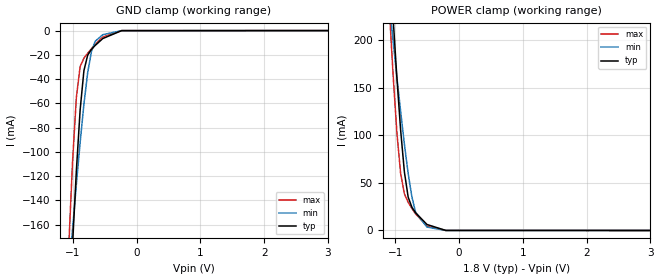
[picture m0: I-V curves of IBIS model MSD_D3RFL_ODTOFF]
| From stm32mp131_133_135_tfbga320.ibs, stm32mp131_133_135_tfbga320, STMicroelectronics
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[Model] MSD_D3RFL_ODTOFF
Model_type   Input
C_comp 2.206pF   2.147pF   2.347pF
Vinh = 1.440V
Vinl = 360.000mV
[Temperature Range]   25.000   125.000   -40.000
[Voltage Range]   1.800V   1.650V   1.950V
[GND Clamp Reference]   0.00V   0.00V   0.00V
[POWER Clamp Reference]   1.800V   1.650V   1.950V
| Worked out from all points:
|   GND clamp passes 1 mA (typ) near -0.35 V on its own axis
|   POWER clamp passes 1 mA (typ) near -0.35 V on its own axis
[GND Clamp]
-1.773V   -1.116A    -680.4mA   -1.192A
-1.064V   -241.9mA   -201.2mA   -176.5mA
-1.005V   -175.9mA   -163.4mA   -107.6mA
-945.5mV  -115.4mA   -126.8mA   -54.95mA
-886.4mV  -65.3mA    -92.18mA   -29.68mA
-827.3mV  -33.03mA   -60.73mA   -22.77mA
-768.2mV  -20.28mA   -34.71mA   -18.7mA
-709.1mV  -15.53mA   -17.22mA   -14.97mA
-650mV    -12.21mA   -8.794mA   -11.47mA
-531.8mV  -6.589mA   -3.406mA   -5.382mA
-236.4mV  -73.12uA   -36.2uA    -7.669uA
3.545V    240.9nA    447.4nA    3.631nA
[Power Clamp]
-1.745V   1.068A     673.3mA    1.125A
-1.095V   289.3mA    237.3mA    232.3mA
-1.036V   223.2mA    199mA      163.4mA
-977.3mV  161mA      161.5mA    103.2mA
-918.2mV  105.6mA    125.1mA    60.03mA
-859.1mV  61.5mA     90.74mA    38.59mA
-800mV    35.11mA    59.93mA    29.58mA
-740.9mV  24.34mA    35.13mA    23.09mA
-681.8mV  18.5mA     18.78mA    17.36mA
-504.5mV  6.286mA    3.577mA    4.548mA
-209.1mV  28.34uA    23.37uA    3.148uA
3.573V    -330.8nA   -532.8nA   -4.245nA
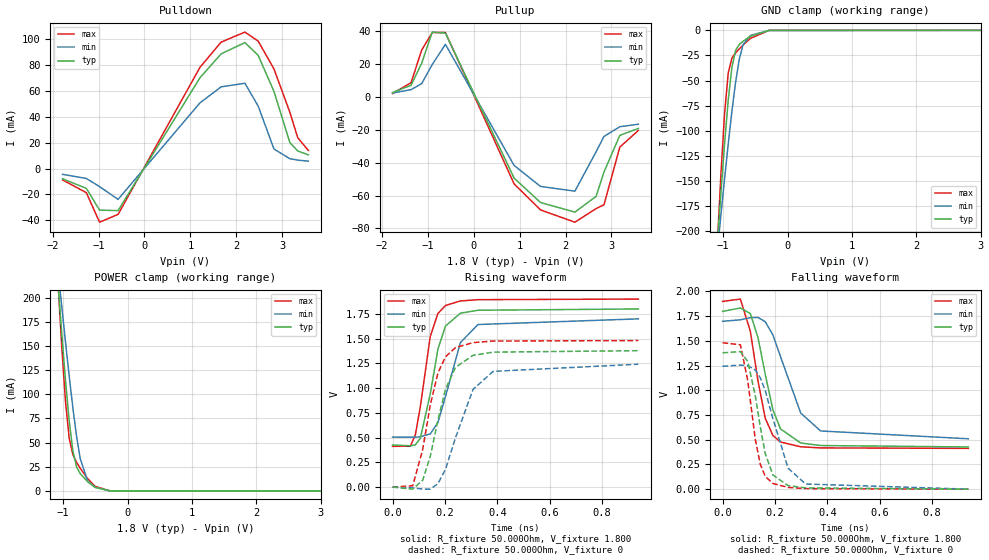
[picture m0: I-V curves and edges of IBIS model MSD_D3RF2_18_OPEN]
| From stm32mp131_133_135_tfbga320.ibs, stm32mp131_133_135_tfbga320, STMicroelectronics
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[Model] MSD_D3RF2_18_OPEN
Model_type   I/O
C_comp 2.550pF   2.465pF   2.675pF
Vinh = 1.150V
Vinl = 650.000mV
Vmeas = 900.000mV
Vref = 900.000mV
[Model Spec]
Vinh   1.150V   1.100V   1.200V
Vinl   650.000mV   600.000mV   700.000mV
Vmeas   900.000mV   850.000mV   950.000mV
Vref   900.000mV   850.000mV   950.000mV
[Temperature Range]   25.000   125.000   -40.000
[Voltage Range]   1.800V   1.700V   1.900V
[GND Clamp Reference]   0.00V   0.00V   0.00V
[Pulldown Reference]   0.00V   0.00V   0.00V
[POWER Clamp Reference]   1.800V   1.700V   1.900V
[Pullup Reference]   1.800V   1.700V   1.900V
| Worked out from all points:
|   slope of the pulldown table from 0 to 0.27 V, typ, clamps not added: 15.3 ohm
|   slope of the pullup table from 0 to 0.27 V, typ, clamps not added: 14.6 ohm
|   GND clamp passes 1 mA (typ) near -0.40 V on its own axis
|   POWER clamp passes 1 mA (typ) near -0.40 V on its own axis
|   rising waveform, R_fixture 50.000Ohm, V_fixture 1.800: 20-80 % time 58.8ps typ, 74.1ps min, 51.5ps max; typ from 0.426 V to 1.8 V
|   rising waveform, R_fixture 50.000Ohm, V_fixture 0: 20-80 % time 77.4ps typ, 97ps min, 68.8ps max; typ from 0.001 V to 1.38 V
|   falling waveform, R_fixture 50.000Ohm, V_fixture 1.800: 20-80 % time 69ps typ, 97.6ps min, 58.2ps max; typ from 1.8 V to 0.427 V
|   falling waveform, R_fixture 50.000Ohm, V_fixture 0: 20-80 % time 57.5ps typ, 80.2ps min, 48.7ps max; typ from 1.38 V to 0 V
[GND Clamp]
-1.785V   -904.7mA   -691.7mA   -1.214A
-1.094V   -216.3mA   -222.2mA   -217.4mA
-1.036V   -163.3mA   -184.8mA   -145.2mA
-978.8mV  -113.5mA   -148.4mA   -83.76mA
-921.2mV  -69.69mA   -113.3mA   -42.51mA
-863.6mV  -36.79mA   -80.49mA   -27.53mA
-806.1mV  -19.91mA   -51.37mA   -22.45mA
-748.5mV  -14mA      -28.45mA   -18.47mA
-690.9mV  -10.87mA   -14.34mA   -14.73mA
-575.8mV  -5.929mA   -5.08mA    -8.007mA
-287.9mV  -82.85uA   -135.6uA   -69.2uA
3.57V     41.7nA     685.7nA    4.362nA
[Power Clamp]
-1.77V    886.2mA    693mA      1.163A
-1.079V   214.1mA    227.9mA    214.3mA
-1.021V   162.4mA    190.6mA    148.6mA
-963.6mV  114.3mA    154.1mA    92.64mA
-906.1mV  72.38mA    118.8mA    54.46mA
-848.5mV  41.09mA    85.68mA    37.53mA
-790.9mV  24.71mA    56.22mA    29.66mA
-733.3mV  17.76mA    32.9mA     23.31mA
-618.2mV  9.462mA    10.19mA    12.58mA
-503mV    3.682mA    3.772mA    4.784mA
-272.7mV  36.6uA     118.7uA    36.53uA
3.585V    -62.58nA   -1.1uA     -6.985nA
[Pulldown]
-1.785V   -7.8mA     -4.4mA     -8.7mA
-1.267V   -15.3mA    -7.6mA     -18.6mA
-978.8mV  -32.1mA    -13.9mA    -41.44mA
-575.8mV  -32.49mA   -23.76mA   -35.4mA
1.209V    70.38mA    50.93mA    78.44mA
1.67V     88.85mA    63.32mA    97.95mA
2.188V    97.58mA    66.1mA     105.7mA
2.476V    87.76mA    48.51mA    98.76mA
2.821V    59.8mA     15.2mA     77.17mA
3.167V    20.2mA     7.7mA      43.7mA
3.339V    13.7mA     6.6mA      23.9mA
3.57V     10.7mA     5.8mA      14.1mA
[Pullup]
-1.77V    2.8mA      2.474mA    2.179mA
-1.367V   7.2mA      4.542mA    8.789mA
-1.136V   20.6mA     8.205mA    28.66mA
-906.1mV  39.62mA    19.85mA    39.36mA
-618.2mV  38.98mA    32.14mA    39.33mA
878.8mV   -49.38mA   -41.65mA   -52.89mA
1.455V    -64.25mA   -54.44mA   -68.75mA
2.203V    -70.07mA   -57.29mA   -76.21mA
2.664V    -60.5mA    -33.33mA   -67.93mA
2.836V    -45.7mA    -23.98mA   -65.62mA
3.182V    -23.3mA    -18.03mA   -30.45mA
3.585V    -19.1mA    -16.53mA   -20.3mA
[Ramp]
R_load=50.000Ohm
dV/dt_r   825.630mV/68.500ps  729.899mV/86.500ps  890.610mV/61.000ps
dV/dt_f   825.630mV/64.000ps  729.899mV/89.500ps  890.610mV/54.000ps
[Rising waveform]
R_fixture=50.000Ohm
V_fixture=1.800
V_fixture_min=1.700
V_fixture_max=1.900
0s        426mV      506.7mV    412.6mV
68ps      418.1mV    505.1mV    414.7mV
87ps      428.3mV    505.9mV    530.2mV
106ps     494.4mV    508.8mV    813.9mV
144ps     943.8mV    538.9mV    1.525V
173ps     1.393V     652.4mV    1.754V
202ps     1.627V     916mV      1.835V
259ps     1.758V     1.461V     1.881V
326ps     1.787V     1.643V     1.894V
938ps     1.8V       1.7V       1.9V
[Rising waveform]
R_fixture=50.000Ohm
V_fixture=0
0s        1.022mV    964.9uV    1.006mV
77ps      -19.7mV    -6.905mV   14.95mV
115ps     70.66mV    -18.63mV   381.3mV
144ps     312.3mV    -19.62mV   830.4mV
173ps     676mV      35.56mV    1.153V
202ps     989.7mV    180.7mV    1.317V
240ps     1.209V     497.8mV    1.41V
307ps     1.332V     987.5mV    1.46V
384ps     1.364V     1.17V      1.476V
938ps     1.379V     1.242V     1.481V
[Falling waveform]
R_fixture=50.000Ohm
V_fixture=1.800
V_fixture_min=1.700
V_fixture_max=1.900
0s        1.798V     1.698V     1.899V
68ps      1.833V     1.713V     1.923V
106ps     1.776V     1.735V     1.597V
135ps     1.535V     1.737V     1.097V
163ps     1.161V     1.694V     716.5mV
192ps     804.3mV    1.561V     543.5mV
221ps     609.3mV    1.342V     477mV
298ps     467.5mV    771.2mV    428.8mV
374ps     441.3mV    588.8mV    417.3mV
938ps     427.1mV    509.6mV    412.8mV
[Falling waveform]
R_fixture=50.000Ohm
V_fixture=0
0s        1.379V     1.243V     1.481V
68ps      1.392V     1.255V     1.461V
96ps      1.293V     1.25V      1.101V
125ps     944.8mV    1.205V     503.4mV
144ps     628.4mV    1.127V     251.2mV
163ps     358.6mV    997.2mV    129.4mV
192ps     143.8mV    713.9mV    57.28mV
250ps     36.35mV    212.5mV    17.83mV
317ps     12.85mV    52.16mV    5.436mV
938ps     13.26uV    62.98uV    -622.7nV
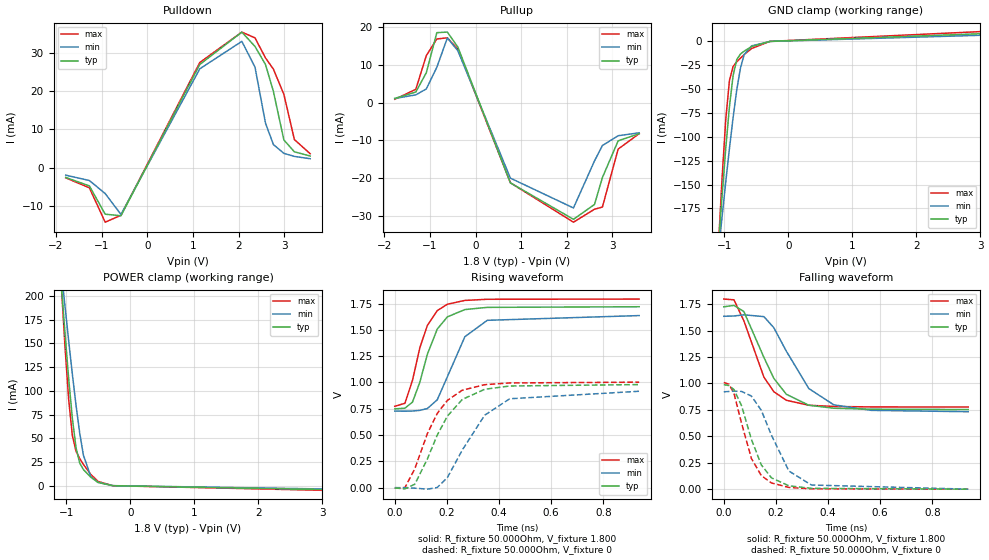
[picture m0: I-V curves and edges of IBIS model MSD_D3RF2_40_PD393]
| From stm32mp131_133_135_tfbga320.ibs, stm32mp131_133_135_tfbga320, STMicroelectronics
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[Model] MSD_D3RF2_40_PD393
Model_type   I/O
C_comp 2.343pF   2.262pF   2.463pF
Vinh = 1.150V
Vinl = 650.000mV
Vmeas = 900.000mV
Vref = 900.000mV
[Model Spec]
Vinh   1.150V   1.100V   1.200V
Vinl   650.000mV   600.000mV   700.000mV
Vmeas   900.000mV   850.000mV   950.000mV
Vref   900.000mV   850.000mV   950.000mV
[Temperature Range]   25.000   125.000   -40.000
[Voltage Range]   1.800V   1.700V   1.900V
[GND Clamp Reference]   0.00V   0.00V   0.00V
[Pulldown Reference]   0.00V   0.00V   0.00V
[POWER Clamp Reference]   1.800V   1.700V   1.900V
[Pullup Reference]   1.800V   1.700V   1.900V
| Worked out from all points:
|   slope of the pulldown table from 0 to 0.27 V, typ, clamps not added: 37.2 ohm
|   slope of the pullup table from 0 to 0.27 V, typ, clamps not added: 29.4 ohm
|   GND clamp passes 1 mA (typ) near -0.41 V on its own axis
|   POWER clamp passes 1 mA (typ) near -0.41 V on its own axis
|   rising waveform, R_fixture 50.000Ohm, V_fixture 1.800: 20-80 % time 78.5ps typ, 96.1ps min, 70.7ps max; typ from 0.749 V to 1.72 V
|   rising waveform, R_fixture 50.000Ohm, V_fixture 0: 20-80 % time 122ps typ, 140ps min, 112ps max; typ from -0.002 V to 0.98 V
|   falling waveform, R_fixture 50.000Ohm, V_fixture 1.800: 20-80 % time 112ps typ, 133ps min, 95.8ps max; typ from 1.73 V to 0.753 V
|   falling waveform, R_fixture 50.000Ohm, V_fixture 0: 20-80 % time 83.9ps typ, 100ps min, 72.2ps max; typ from 0.988 V to 0 V
[GND Clamp]
-1.785V   -901.7mA   -689.1mA   -1.21A
-1.094V   -214.9mA   -221.1mA   -215.5mA
-1.036V   -162mA     -183.8mA   -143.5mA
-978.8mV  -112.3mA   -147.4mA   -82.22mA
-921.2mV  -68.63mA   -112.4mA   -41.13mA
-863.6mV  -35.85mA   -79.72mA   -26.32mA
-806.1mV  -19.09mA   -50.71mA   -21.39mA
-748.5mV  -13.31mA   -27.88mA   -17.56mA
-690.9mV  -10.29mA   -13.87mA   -13.98mA
-575.8mV  -5.571mA   -4.782mA   -7.532mA
-287.9mV  -72.78uA   -122.5uA   -58.3uA
3.57V     9.343mA    7.446mA    11.95mA
[Power Clamp]
-1.77V    883mA      690.1mA    1.159A
-1.079V   212.6mA    226.6mA    212.3mA
-1.021V   161mA      189.4mA    146.9mA
-963.6mV  113.1mA    153mA      91.13mA
-906.1mV  71.28mA    117.8mA    53.07mA
-848.5mV  40.13mA    84.84mA    36.32mA
-790.9mV  23.88mA    55.48mA    28.61mA
-733.3mV  17.05mA    32.27mA    22.42mA
-618.2mV  8.997mA    9.762mA    11.99mA
-503mV    3.435mA    3.526mA    4.476mA
-272.7mV  28uA       96.27uA    27.84uA
3.585V    -4.731mA   -4.02mA    -5.687mA
[Pulldown]
-1.785V   -2.6mA     -2mA       -2.7mA
-1.267V   -4.8mA     -3.4mA     -5.3mA
-921.2mV  -12.19mA   -6.8mA     -14.28mA
-575.8mV  -12.6mA    -12.25mA   -12.47mA
1.152V    26.92mA    25.78mA    27.43mA
2.073V    35.36mA    32.95mA    35.37mA
2.361V    31.62mA    26.22mA    33.86mA
2.591V    26.91mA    11.6mA     28.62mA
2.764V    19.9mA     6mA        25.7mA
2.994V    7.2mA      3.7mA      19.1mA
3.224V    4.1mA      2.9mA      7.3mA
3.57V     3mA        2.3mA      3.6mA
[Pullup]
-1.77V    1.1mA      1.1mA      873.7uA
-1.309V   2.8mA      2.047mA    3.516mA
-1.079V   7.9mA      3.616mA    12.43mA
-848.5mV  18.49mA    9.339mA    16.82mA
-618.2mV  18.64mA    17.11mA    17.12mA
-387.9mV  14.68mA    13.71mA    14.14mA
763.6mV   -21.21mA   -19.96mA   -21.19mA
2.145V    -30.84mA   -27.84mA   -31.6mA
2.606V    -26.91mA   -15.4mA    -28.17mA
2.779V    -19.8mA    -11.34mA   -27.6mA
3.124V    -10.1mA    -8.753mA   -12.28mA
3.585V    -8.2mA     -7.974mA   -8.2mA
[Ramp]
R_load=50.000Ohm
dV/dt_r   584.160mV/101.000ps  546.599mV/119.000ps  605.820mV/92.000ps
dV/dt_f   584.160mV/99.000ps  546.599mV/117.000ps  605.820mV/84.000ps
[Rising waveform]
R_fixture=50.000Ohm
V_fixture=1.800
V_fixture_min=1.700
V_fixture_max=1.900
0s        749.2mV    728.1mV    773.4mV
39ps      755.6mV    727.3mV    802.6mV
68ps      813.8mV    728.8mV    1.02V
96ps      1.001V     735mV      1.328V
125ps     1.267V     752.4mV    1.542V
163ps     1.508V     835.4mV    1.683V
202ps     1.624V     1.055V     1.744V
269ps     1.693V     1.435V     1.78V
355ps     1.714V     1.591V     1.791V
938ps     1.72V      1.636V     1.793V
[Rising waveform]
R_fixture=50.000Ohm
V_fixture=0
0s        -2.079mV   655.5uV    -2.629mV
39ps      -11.37mV   -460.8uV   1.176mV
77ps      33.33mV    -4.472mV   180.2mV
125ps     272.1mV    -13.98mV   513.7mV
163ps     499.8mV    1.62mV     706.2mV
202ps     680.5mV    96.89mV    830.2mV
259ps     839mV      357.6mV    926.5mV
345ps     935.4mV    688.9mV    979.2mV
441ps     966.7mV    845.3mV    995.7mV
938ps     980.3mV    916.7mV    1.003V
[Falling waveform]
R_fixture=50.000Ohm
V_fixture=1.800
V_fixture_min=1.700
V_fixture_max=1.900
0s        1.725V     1.635V     1.798V
39ps      1.738V     1.638V     1.791V
77ps      1.68V      1.649V     1.593V
154ps     1.246V     1.632V     1.059V
192ps     1.048V     1.527V     922.1mV
240ps     897.6mV    1.305V     840.9mV
326ps     794.1mV    952.2mV    793.7mV
422ps     765.3mV    797.7mV    782.2mV
566ps     756.1mV    745.4mV    777.8mV
938ps     753.2mV    732.5mV    777mV
[Falling waveform]
R_fixture=50.000Ohm
V_fixture=0
0s        988.4mV    920.8mV    1.009V
20ps      979.9mV    923.9mV    992.5mV
39ps      941.8mV    926.6mV    906.8mV
68ps      790.8mV    924.8mV    625.2mV
106ps     471.4mV    880.5mV    289.8mV
144ps     229.3mV    745.5mV    128.6mV
183ps     106.9mV    509.4mV    58.58mV
250ps     31.63mV    171.1mV    16.36mV
336ps     7.702mV    39.2mV     3.387mV
938ps     3.497uV    26.78uV    -4.712uV
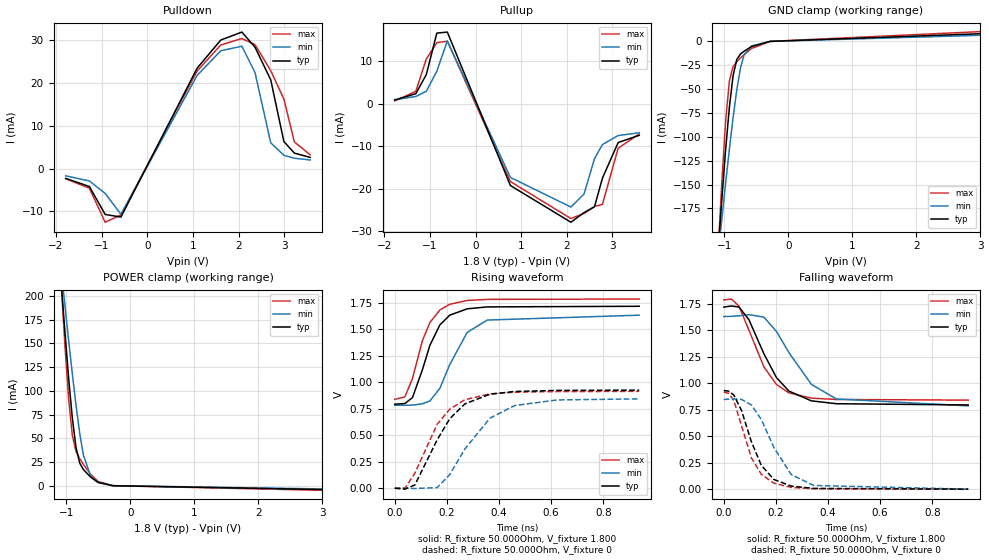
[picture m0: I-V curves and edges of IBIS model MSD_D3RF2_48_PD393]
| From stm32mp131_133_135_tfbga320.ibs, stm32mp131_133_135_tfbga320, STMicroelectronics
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[Model] MSD_D3RF2_48_PD393
Model_type   I/O
C_comp 2.343pF   2.262pF   2.463pF
Vinh = 1.150V
Vinl = 650.000mV
Vmeas = 900.000mV
Vref = 900.000mV
[Model Spec]
Vinh   1.150V   1.100V   1.200V
Vinl   650.000mV   600.000mV   700.000mV
Vmeas   900.000mV   850.000mV   950.000mV
Vref   900.000mV   850.000mV   950.000mV
[Temperature Range]   25.000   125.000   -40.000
[Voltage Range]   1.800V   1.700V   1.900V
[GND Clamp Reference]   0.00V   0.00V   0.00V
[Pulldown Reference]   0.00V   0.00V   0.00V
[POWER Clamp Reference]   1.800V   1.700V   1.900V
[Pullup Reference]   1.800V   1.700V   1.900V
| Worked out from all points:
|   slope of the pulldown table from 0 to 0.27 V, typ, clamps not added: 41 ohm
|   slope of the pullup table from 0 to 0.27 V, typ, clamps not added: 32.3 ohm
|   GND clamp passes 1 mA (typ) near -0.41 V on its own axis
|   POWER clamp passes 1 mA (typ) near -0.41 V on its own axis
|   rising waveform, R_fixture 50.000Ohm, V_fixture 1.800: 20-80 % time 81.9ps typ, 100ps min, 75.7ps max; typ from 0.791 V to 1.72 V
|   rising waveform, R_fixture 50.000Ohm, V_fixture 0: 20-80 % time 128ps typ, 151ps min, 121ps max; typ from -0.002 V to 0.924 V
|   falling waveform, R_fixture 50.000Ohm, V_fixture 1.800: 20-80 % time 117ps typ, 143ps min, 105ps max; typ from 1.72 V to 0.795 V
|   falling waveform, R_fixture 50.000Ohm, V_fixture 0: 20-80 % time 86.3ps typ, 107ps min, 77.7ps max; typ from 0.932 V to 0 V
[GND Clamp]
-1.785V   -901.7mA   -689.1mA   -1.21A
-1.094V   -214.9mA   -221.1mA   -215.5mA
-1.036V   -162mA     -183.8mA   -143.5mA
-978.8mV  -112.3mA   -147.4mA   -82.22mA
-921.2mV  -68.63mA   -112.4mA   -41.13mA
-863.6mV  -35.85mA   -79.72mA   -26.32mA
-806.1mV  -19.09mA   -50.71mA   -21.39mA
-748.5mV  -13.31mA   -27.88mA   -17.56mA
-690.9mV  -10.29mA   -13.87mA   -13.98mA
-575.8mV  -5.571mA   -4.782mA   -7.532mA
-287.9mV  -72.78uA   -122.5uA   -58.3uA
3.57V     9.343mA    7.446mA    11.95mA
[Power Clamp]
-1.77V    883mA      690.1mA    1.159A
-1.079V   212.6mA    226.6mA    212.3mA
-1.021V   161mA      189.4mA    146.9mA
-963.6mV  113.1mA    153mA      91.13mA
-906.1mV  71.28mA    117.8mA    53.07mA
-848.5mV  40.13mA    84.84mA    36.32mA
-790.9mV  23.88mA    55.48mA    28.61mA
-733.3mV  17.05mA    32.27mA    22.42mA
-618.2mV  8.997mA    9.762mA    11.99mA
-503mV    3.435mA    3.526mA    4.476mA
-272.7mV  28uA       96.27uA    27.84uA
3.585V    -4.731mA   -4.02mA    -5.687mA
[Pulldown]
-1.785V   -2.3mA     -1.7mA     -2.4mA
-1.267V   -4.2mA     -2.9mA     -4.6mA
-921.2mV  -10.72mA   -5.8mA     -12.52mA
-575.8mV  -11.32mA   -10.69mA   -10.82mA
1.094V    23.43mA    21.74mA    22.76mA
1.612V    29.99mA    27.49mA    28.84mA
2.073V    31.84mA    28.54mA    30.34mA
2.361V    28.33mA    22.42mA    28.91mA
2.706V    20.7mA     6mA        22.84mA
2.994V    6.3mA      3.1mA      16.2mA
3.224V    3.6mA      2.4mA      6.2mA
3.57V     2.6mA      2mA        3.2mA
[Pullup]
-1.77V    900uA      973.7uA    673.7uA
-1.309V   2.4mA      1.747mA    2.963mA
-1.079V   6.9mA      2.968mA    10.55mA
-848.5mV  16.65mA    7.693mA    14.41mA
-618.2mV  16.89mA    14.81mA    14.74mA
763.6mV   -19.22mA   -17.31mA   -18.28mA
2.088V    -27.84mA   -24.27mA   -26.98mA
2.376V    -25.59mA   -21.22mA   -25.8mA
2.606V    -24.21mA   -12.89mA   -24.14mA
2.779V    -17.5mA    -9.584mA   -23.66mA
3.124V    -9.1mA     -7.453mA   -10.44mA
3.585V    -7.4mA     -6.8mA     -7.074mA
[Ramp]
R_load=50.000Ohm
dV/dt_r   553.320mV/105.500ps  506.459mV/127.000ps  556.530mV/99.000ps
dV/dt_f   553.320mV/102.500ps  506.459mV/125.500ps  556.530mV/91.500ps
[Rising waveform]
R_fixture=50.000Ohm
V_fixture=1.800
V_fixture_min=1.700
V_fixture_max=1.900
0s        791.1mV    781.4mV    837.6mV
39ps      797.6mV    780.8mV    860.2mV
68ps      853.6mV    782.8mV    1.034V
106ps     1.116V     794.9mV    1.39V
135ps     1.348V     822.6mV    1.562V
173ps     1.539V     940.9mV    1.68V
211ps     1.631V     1.165V     1.734V
278ps     1.691V     1.469V     1.77V
355ps     1.709V     1.585V     1.78V
938ps     1.715V     1.631V     1.783V
[Rising waveform]
R_fixture=50.000Ohm
V_fixture=0
0s        -1.682mV   573.4uV    -1.968mV
39ps      -10.4mV    -575.8uV   -1.563mV
77ps      29.01mV    -4.465mV   139.9mV
163ps     456.8mV    4.612mV    603mV
211ps     654.2mV    127.7mV    743.6mV
269ps     794.2mV    368.4mV    833.7mV
365ps     885.6mV    659.2mV    888.4mV
460ps     911.2mV    778.2mV    904.5mV
623ps     921.2mV    831.4mV    910.7mV
938ps     923.9mV    841.3mV    912.1mV
[Falling waveform]
R_fixture=50.000Ohm
V_fixture=1.800
V_fixture_min=1.700
V_fixture_max=1.900
0s        1.719V     1.63V      1.787V
29ps      1.73V      1.632V     1.795V
58ps      1.72V      1.637V     1.73V
96ps      1.602V     1.648V     1.504V
154ps     1.278V     1.624V     1.154V
202ps     1.054V     1.49V      988.6mV
250ps     926.2mV    1.289V     909.5mV
336ps     833.9mV    989.9mV    859.6mV
432ps     806.8mV    851.7mV    846.9mV
938ps     795.2mV    786.5mV    840.8mV
[Falling waveform]
R_fixture=50.000Ohm
V_fixture=0
0s        932mV      846.8mV    917.5mV
20ps      924.3mV    850.1mV    902.9mV
39ps      887.3mV    852.3mV    833.8mV
68ps      743mV      847.6mV    598mV
106ps     446.5mV    794.8mV    296mV
144ps     225.4mV    658.1mV    140.7mV
192ps     91.85mV    394.5mV    56.77mV
259ps     28.8mV     137.1mV    16.79mV
345ps     7.264mV    34.88mV    3.714mV
938ps     4.156uV    38.07uV    -1.693uV
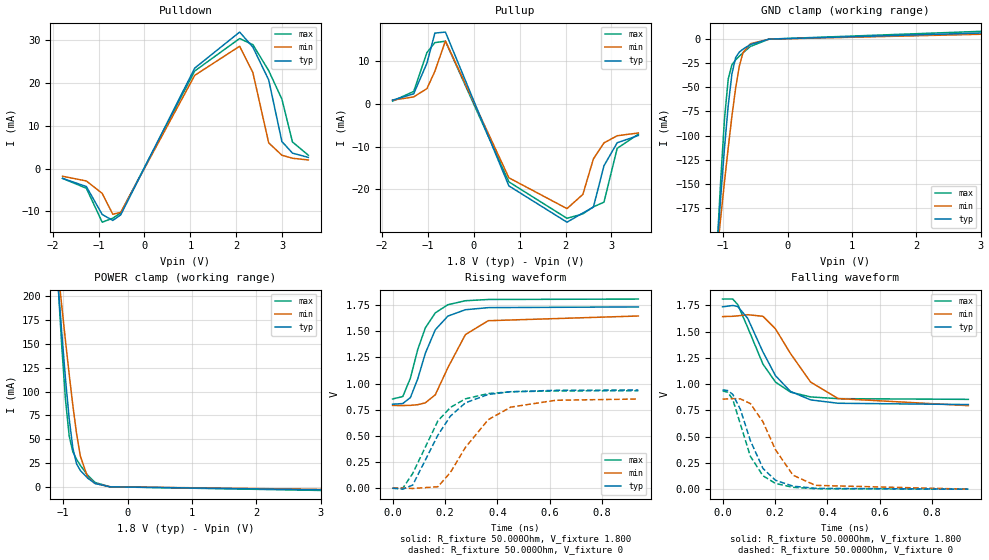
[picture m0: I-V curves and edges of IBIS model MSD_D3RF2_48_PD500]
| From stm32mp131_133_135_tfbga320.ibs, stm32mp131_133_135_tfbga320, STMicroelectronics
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[Model] MSD_D3RF2_48_PD500
Model_type   I/O
C_comp 2.389pF   2.307pF   2.511pF
Vinh = 1.150V
Vinl = 650.000mV
Vmeas = 900.000mV
Vref = 900.000mV
[Model Spec]
Vinh   1.150V   1.100V   1.200V
Vinl   650.000mV   600.000mV   700.000mV
Vmeas   900.000mV   850.000mV   950.000mV
Vref   900.000mV   850.000mV   950.000mV
[Temperature Range]   25.000   125.000   -40.000
[Voltage Range]   1.800V   1.700V   1.900V
[GND Clamp Reference]   0.00V   0.00V   0.00V
[Pulldown Reference]   0.00V   0.00V   0.00V
[POWER Clamp Reference]   1.800V   1.700V   1.900V
[Pullup Reference]   1.800V   1.700V   1.900V
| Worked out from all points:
|   slope of the pulldown table from 0 to 0.27 V, typ, clamps not added: 41 ohm
|   slope of the pullup table from 0 to 0.27 V, typ, clamps not added: 32.3 ohm
|   GND clamp passes 1 mA (typ) near -0.40 V on its own axis
|   POWER clamp passes 1 mA (typ) near -0.41 V on its own axis
|   rising waveform, R_fixture 50.000Ohm, V_fixture 1.800: 20-80 % time 82.6ps typ, 102ps min, 76.9ps max; typ from 0.802 V to 1.73 V
|   rising waveform, R_fixture 50.000Ohm, V_fixture 0: 20-80 % time 130ps typ, 153ps min, 124ps max; typ from -0.002 V to 0.938 V
|   falling waveform, R_fixture 50.000Ohm, V_fixture 1.800: 20-80 % time 120ps typ, 145ps min, 108ps max; typ from 1.74 V to 0.806 V
|   falling waveform, R_fixture 50.000Ohm, V_fixture 0: 20-80 % time 88.2ps typ, 108ps min, 79.8ps max; typ from 0.946 V to 0 V
[GND Clamp]
-1.785V   -902.3mA   -689.6mA   -1.211A
-1.094V   -215.1mA   -221.3mA   -215.9mA
-1.036V   -162.2mA   -184mA     -144mA
-978.8mV  -112.6mA   -147.7mA   -82.55mA
-921.2mV  -68.85mA   -112.7mA   -41.43mA
-863.6mV  -36.05mA   -79.88mA   -26.58mA
-806.1mV  -19.27mA   -50.85mA   -21.61mA
-748.5mV  -13.46mA   -28mA      -17.75mA
-690.9mV  -10.41mA   -13.96mA   -14.14mA
-575.8mV  -5.648mA   -4.846mA   -7.634mA
-287.9mV  -74.98uA   -125.3uA   -60.3uA
3.57V     7.346mA    5.855mA    9.39mA
[Power Clamp]
-1.77V    883.7mA    690.7mA    1.16A
-1.079V   212.9mA    226.9mA    212.8mA
-1.021V   161.3mA    189.7mA    147.3mA
-963.6mV  113.3mA    153.3mA    91.41mA
-906.1mV  71.51mA    118.1mA    53.37mA
-848.5mV  40.33mA    85.03mA    36.57mA
-790.9mV  24.05mA    55.63mA    28.83mA
-733.3mV  17.2mA     32.4mA     22.61mA
-618.2mV  9.094mA    9.85mA     12.12mA
-503mV    3.487mA    3.577mA    4.547mA
-272.7mV  29uA       100.4uA    30.26uA
3.585V    -3.718mA   -3.159mA   -4.469mA
[Pulldown]
-1.785V   -2.3mA     -1.8mA     -2.3mA
-1.267V   -4.2mA     -2.9mA     -4.6mA
-921.2mV  -10.72mA   -5.8mA     -12.52mA
-690.9mV  -12.11mA   -10.66mA   -11.59mA
-518.2mV  -10.81mA   -10.23mA   -10.35mA
1.094V    23.43mA    21.74mA    22.76mA
2.073V    31.84mA    28.54mA    30.34mA
2.361V    28.33mA    22.42mA    28.91mA
2.706V    20.69mA    6mA        22.85mA
2.994V    6.3mA      3.1mA      16.2mA
3.224V    3.6mA      2.4mA      6.2mA
3.57V     2.6mA      2mA        3.1mA
[Pullup]
-1.77V    900uA      900uA      673.7uA
-1.309V   2.4mA      1.674mA    2.963mA
-1.021V   9.6mA      3.616mA    12.09mA
-848.5mV  16.65mA    7.674mA    14.42mA
-618.2mV  16.89mA    14.81mA    14.74mA
763.6mV   -19.22mA   -17.32mA   -18.28mA
2.03V     -27.75mA   -24.56mA   -26.84mA
2.376V    -25.59mA   -21.23mA   -25.8mA
2.606V    -24.21mA   -12.89mA   -24.14mA
2.836V    -14.5mA    -9.132mA   -23.05mA
3.124V    -9.1mA     -7.453mA   -10.41mA
3.585V    -7.4mA     -6.8mA     -7.074mA
[Ramp]
R_load=50.000Ohm
dV/dt_r   559.710mV/107.000ps  511.379mV/128.500ps  565.140mV/101.000ps
dV/dt_f   559.710mV/104.500ps  511.379mV/127.500ps  565.140mV/94.500ps
[Rising waveform]
R_fixture=50.000Ohm
V_fixture=1.800
V_fixture_min=1.700
V_fixture_max=1.900
0s        801.9mV    790.5mV    852.3mV
39ps      808.6mV    789.6mV    875.5mV
68ps      865.5mV    791.2mV    1.051V
96ps      1.044V     797.6mV    1.325V
125ps     1.289V     815.4mV    1.532V
163ps     1.514V     892.3mV    1.676V
211ps     1.645V     1.151V     1.754V
278ps     1.706V     1.468V     1.792V
365ps     1.726V     1.601V     1.804V
938ps     1.733V     1.646V     1.808V
[Rising waveform]
R_fixture=50.000Ohm
V_fixture=0
0s        -1.679mV   610.7uV    -1.967mV
39ps      -10.41mV   -361.8uV   -1.576mV
77ps      28.98mV    -3.922mV   140mV
173ps     506.4mV    12.89mV    643.1mV
221ps     689mV      150.3mV    771.8mV
278ps     815.5mV    388.9mV    853.8mV
365ps     895.6mV    654.1mV    903.8mV
451ps     921.9mV    774.5mV    921mV
623ps     935.1mV    839.9mV    929.4mV
938ps     938.3mV    852mV      931.2mV
[Falling waveform]
R_fixture=50.000Ohm
V_fixture=1.800
V_fixture_min=1.700
V_fixture_max=1.900
0s        1.737V     1.644V     1.811V
39ps      1.75V      1.647V     1.811V
58ps      1.74V      1.651V     1.758V
96ps      1.627V     1.662V     1.54V
154ps     1.308V     1.647V     1.192V
202ps     1.081V     1.527V     1.02V
259ps     931.5mV    1.293V     924.7mV
336ps     850.4mV    1.02V      878.6mV
441ps     818.4mV    863.2mV    862.3mV
938ps     806mV      795.6mV    855.6mV
[Falling waveform]
R_fixture=50.000Ohm
V_fixture=0
0s        946.4mV    857.1mV    936.7mV
20ps      939mV      860.3mV    922.6mV
39ps      902.8mV    863mV      854.6mV
68ps      760mV      860.1mV    619.6mV
106ps     463.2mV    815.6mV    313.6mV
154ps     197.9mV    641.9mV    127.7mV
202ps     84.59mV    375.4mV    54.49mV
269ps     28.52mV    132.5mV    17.46mV
355ps     7.905mV    36mV       4.29mV
938ps     -4.491uV   45.12uV    12.18uV
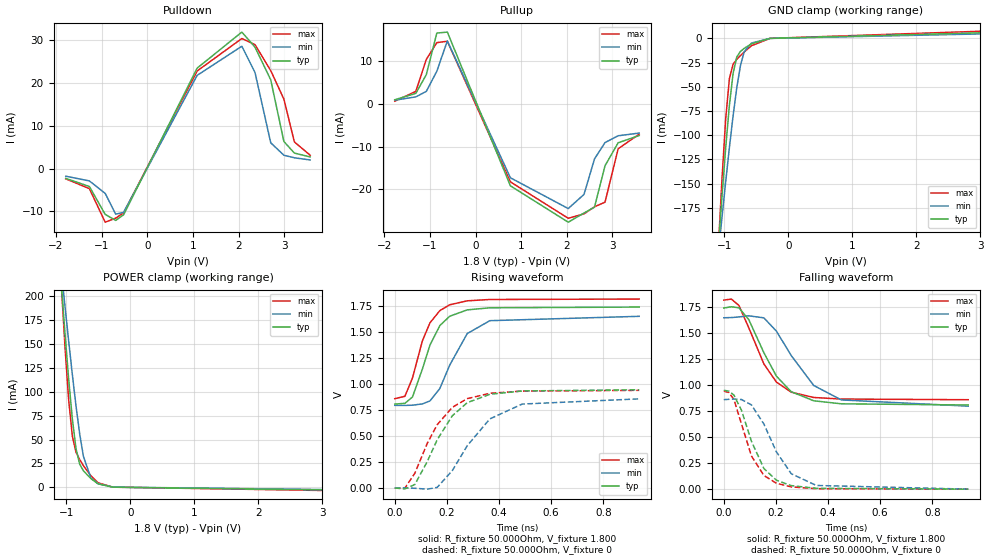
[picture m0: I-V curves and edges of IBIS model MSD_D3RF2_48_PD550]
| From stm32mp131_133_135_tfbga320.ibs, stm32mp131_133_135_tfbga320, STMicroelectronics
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[Model] MSD_D3RF2_48_PD550
Model_type   I/O
C_comp 2.402pF   2.319pF   2.523pF
Vinh = 1.150V
Vinl = 650.000mV
Vmeas = 900.000mV
Vref = 900.000mV
[Model Spec]
Vinh   1.150V   1.100V   1.200V
Vinl   650.000mV   600.000mV   700.000mV
Vmeas   900.000mV   850.000mV   950.000mV
Vref   900.000mV   850.000mV   950.000mV
[Temperature Range]   25.000   125.000   -40.000
[Voltage Range]   1.800V   1.700V   1.900V
[GND Clamp Reference]   0.00V   0.00V   0.00V
[Pulldown Reference]   0.00V   0.00V   0.00V
[POWER Clamp Reference]   1.800V   1.700V   1.900V
[Pullup Reference]   1.800V   1.700V   1.900V
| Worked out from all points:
|   slope of the pulldown table from 0 to 0.27 V, typ, clamps not added: 41 ohm
|   slope of the pullup table from 0 to 0.27 V, typ, clamps not added: 32.3 ohm
|   GND clamp passes 1 mA (typ) near -0.40 V on its own axis
|   POWER clamp passes 1 mA (typ) near -0.41 V on its own axis
|   rising waveform, R_fixture 50.000Ohm, V_fixture 1.800: 20-80 % time 82.9ps typ, 101ps min, 77ps max; typ from 0.806 V to 1.74 V
|   rising waveform, R_fixture 50.000Ohm, V_fixture 0: 20-80 % time 131ps typ, 154ps min, 125ps max; typ from -0.002 V to 0.943 V
|   falling waveform, R_fixture 50.000Ohm, V_fixture 1.800: 20-80 % time 121ps typ, 147ps min, 110ps max; typ from 1.74 V to 0.81 V
|   falling waveform, R_fixture 50.000Ohm, V_fixture 0: 20-80 % time 88.9ps typ, 109ps min, 80.4ps max; typ from 0.951 V to 0 V
[GND Clamp]
-1.785V   -902.5mA   -689.8mA   -1.211A
-1.094V   -215.2mA   -221.3mA   -216.1mA
-1.036V   -162.3mA   -184.1mA   -144mA
-978.8mV  -112.6mA   -147.7mA   -82.66mA
-921.2mV  -68.94mA   -112.7mA   -41.52mA
-863.6mV  -36.12mA   -79.94mA   -26.66mA
-806.1mV  -19.32mA   -50.9mA    -21.69mA
-748.5mV  -13.5mA    -28.05mA   -17.83mA
-690.9mV  -10.45mA   -14mA      -14.19mA
-575.8mV  -5.674mA   -4.868mA   -7.668mA
-287.9mV  -75.78uA   -126.4uA   -61.1uA
3.57V     6.676mA    5.321mA    8.541mA
[Power Clamp]
-1.77V    883.8mA    690.9mA    1.161A
-1.079V   213mA      227mA      212.9mA
-1.021V   161.4mA    189.7mA    147.4mA
-963.6mV  113.4mA    153.3mA    91.57mA
-906.1mV  71.59mA    118.1mA    53.46mA
-848.5mV  40.4mA     85.07mA    36.66mA
-790.9mV  24.12mA    55.69mA    28.9mA
-733.3mV  17.24mA    32.45mA    22.67mA
-618.2mV  9.128mA    9.881mA    12.16mA
-503mV    3.505mA    3.595mA    4.563mA
-272.7mV  30uA       102.8uA    29.36uA
3.585V    -3.38mA    -2.872mA   -4.063mA
[Pulldown]
-1.785V   -2.3mA     -1.8mA     -2.4mA
-1.267V   -4.2mA     -2.9mA     -4.7mA
-921.2mV  -10.71mA   -5.8mA     -12.53mA
-690.9mV  -12.11mA   -10.66mA   -11.59mA
-518.2mV  -10.81mA   -10.24mA   -10.35mA
1.094V    23.43mA    21.74mA    22.76mA
2.073V    31.84mA    28.54mA    30.34mA
2.361V    28.33mA    22.42mA    28.91mA
2.706V    20.7mA     6mA        22.85mA
2.994V    6.3mA      3.1mA      16.2mA
3.224V    3.6mA      2.5mA      6.2mA
3.57V     2.7mA      2mA        3.1mA
[Pullup]
-1.77V    1mA        900uA      673.7uA
-1.309V   2.5mA      1.674mA    2.963mA
-1.079V   6.9mA      2.968mA    10.47mA
-848.5mV  16.66mA    7.7mA      14.42mA
-618.2mV  16.89mA    14.82mA    14.74mA
763.6mV   -19.21mA   -17.32mA   -18.28mA
2.03V     -27.75mA   -24.55mA   -26.83mA
2.376V    -25.6mA    -21.23mA   -25.8mA
2.606V    -24.21mA   -12.89mA   -24.14mA
2.836V    -14.5mA    -9.058mA   -23.05mA
3.124V    -9.1mA     -7.453mA   -10.51mA
3.585V    -7.4mA     -6.826mA   -7.074mA
[Ramp]
R_load=50.000Ohm
dV/dt_r   561.870mV/107.500ps  513.059mV/128.500ps  568.050mV/101.500ps
dV/dt_f   561.870mV/105.000ps  513.059mV/129.000ps  568.050mV/96.000ps
[Rising waveform]
R_fixture=50.000Ohm
V_fixture=1.800
V_fixture_min=1.700
V_fixture_max=1.900
0s        805.5mV    793.4mV    857.3mV
39ps      813mV      792.7mV    880.7mV
68ps      873.9mV    794.8mV    1.057V
106ps     1.143V     807.3mV    1.414V
135ps     1.373V     835.8mV    1.587V
173ps     1.561V     955.9mV    1.705V
211ps     1.651V     1.181V     1.761V
278ps     1.712V     1.484V     1.799V
365ps     1.732V     1.608V     1.812V
938ps     1.739V     1.65V      1.816V
[Rising waveform]
R_fixture=50.000Ohm
V_fixture=0
0s        -1.817mV   576uV      -1.966mV
39ps      -10.61mV   -572.1uV   -1.581mV
77ps      31.64mV    -4.463mV   140mV
125ps     254.4mV    -13.04mV   429.4mV
163ps     463.3mV    4.563mV    607.6mV
221ps     693.6mV    166.4mV    774.6mV
278ps     819.3mV    405.1mV    857.9mV
365ps     899.6mV    663.4mV    909.3mV
489ps     932mV      805.8mV    930.6mV
938ps     943.2mV    855.7mV    937.7mV
[Falling waveform]
R_fixture=50.000Ohm
V_fixture=1.800
V_fixture_min=1.700
V_fixture_max=1.900
0s        1.743V     1.649V     1.819V
29ps      1.755V     1.651V     1.829V
58ps      1.745V     1.657V     1.768V
96ps      1.631V     1.668V     1.552V
154ps     1.312V     1.648V     1.204V
202ps     1.087V     1.52V      1.03V
259ps     937.2mV    1.285V     932.9mV
345ps     850.4mV    997.9mV    882.1mV
451ps     821.2mV    858.5mV    866.9mV
938ps     809.7mV    798.7mV    860.6mV
[Falling waveform]
R_fixture=50.000Ohm
V_fixture=0
0s        951.3mV    861.3mV    943.2mV
20ps      942.8mV    864.6mV    929.4mV
39ps      905.2mV    866.9mV    861.7mV
68ps      758.6mV    862.4mV    627mV
106ps     461.1mV    810.9mV    319.5mV
154ps     198.5mV    626.2mV    131.6mV
202ps     85.65mV    358.6mV    56.76mV
259ps     34.18mV    148.5mV    21.76mV
355ps     8.231mV    35.67mV    4.615mV
938ps     -4.867uV   62.68uV    -2.708uV
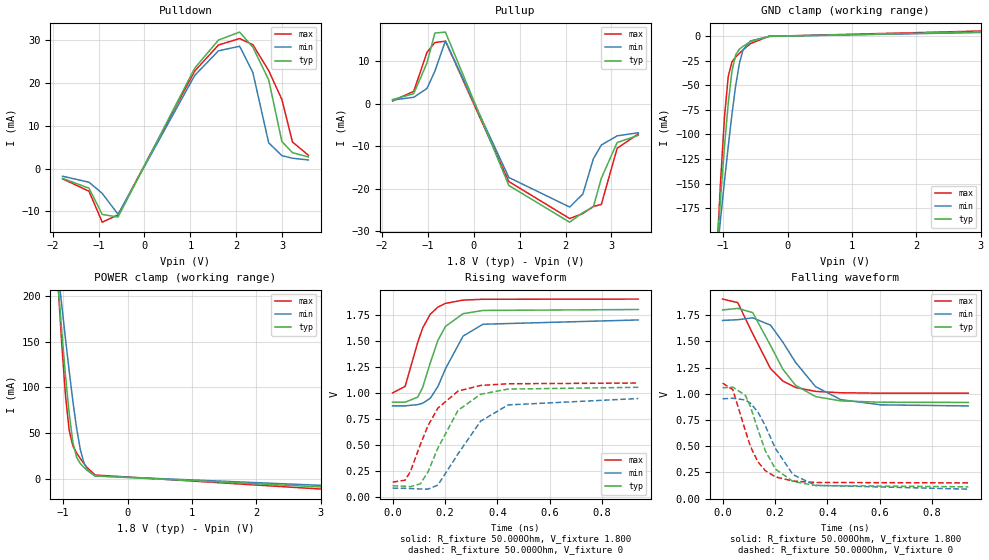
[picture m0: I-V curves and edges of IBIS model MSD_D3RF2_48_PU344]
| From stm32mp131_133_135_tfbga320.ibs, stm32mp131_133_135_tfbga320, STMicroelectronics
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[Model] MSD_D3RF2_48_PU344
Model_type   I/O
C_comp 2.316pF   2.235pF   2.435pF
Vinh = 1.150V
Vinl = 650.000mV
Vmeas = 900.000mV
Vref = 900.000mV
[Model Spec]
Vinh   1.150V   1.100V   1.200V
Vinl   650.000mV   600.000mV   700.000mV
Vmeas   900.000mV   850.000mV   950.000mV
Vref   900.000mV   850.000mV   950.000mV
[Temperature Range]   25.000   125.000   -40.000
[Voltage Range]   1.800V   1.700V   1.900V
[GND Clamp Reference]   0.00V   0.00V   0.00V
[Pulldown Reference]   0.00V   0.00V   0.00V
[POWER Clamp Reference]   1.800V   1.700V   1.900V
[Pullup Reference]   1.800V   1.700V   1.900V
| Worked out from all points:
|   slope of the pulldown table from 0 to 0.27 V, typ, clamps not added: 41 ohm
|   slope of the pullup table from 0 to 0.27 V, typ, clamps not added: 32.3 ohm
|   GND clamp passes 1 mA (typ) near -0.41 V on its own axis
|   POWER clamp passes 1 mA (typ) near -0.41 V on its own axis
|   rising waveform, R_fixture 50.000Ohm, V_fixture 1.800: 20-80 % time 78.1ps typ, 97.1ps min, 70.4ps max; typ from 0.913 V to 1.8 V
|   rising waveform, R_fixture 50.000Ohm, V_fixture 0: 20-80 % time 116ps typ, 140ps min, 108ps max; typ from 0.112 V to 1.05 V
|   falling waveform, R_fixture 50.000Ohm, V_fixture 1.800: 20-80 % time 121ps typ, 147ps min, 112ps max; typ from 1.8 V to 0.916 V
|   falling waveform, R_fixture 50.000Ohm, V_fixture 0: 20-80 % time 88.7ps typ, 110ps min, 79.6ps max; typ from 1.06 V to 0.112 V
[GND Clamp]
-1.785V   -901.1mA   -688.6mA   -1.21A
-1.094V   -214.7mA   -220.8mA   -215.3mA
-1.036V   -161.7mA   -183.5mA   -143.3mA
-978.8mV  -112.2mA   -147.2mA   -81.99mA
-921.2mV  -68.46mA   -112.3mA   -40.92mA
-863.6mV  -35.71mA   -79.59mA   -26.13mA
-806.1mV  -18.97mA   -50.59mA   -21.23mA
-748.5mV  -13.2mA    -27.78mA   -17.42mA
-690.9mV  -10.2mA    -13.78mA   -13.86mA
-575.8mV  -5.513mA   -4.723mA   -7.459mA
-287.9mV  -68.99uA   -116uA     -52.99uA
3.57V     5.268mA    4.537mA    6.293mA
[Power Clamp]
-1.77V    882.6mA    689.9mA    1.159A
-1.079V   212.4mA    226.5mA    212.1mA
-1.021V   160.9mA    189.3mA    146.7mA
-963.6mV  112.9mA    152.9mA    90.9mA
-906.1mV  71.15mA    117.8mA    52.89mA
-848.5mV  40.01mA    84.77mA    36.16mA
-790.9mV  23.78mA    55.42mA    28.47mA
-733.3mV  16.97mA    32.21mA    22.3mA
-675.8mV  12.59mA    17.37mA    16.79mA
-618.2mV  8.95mA     9.729mA    11.92mA
-503mV    3.412mA    3.511mA    4.443mA
3.585V    -10.57mA   -8.572mA   -13.43mA
[Pulldown]
-1.785V   -2.3mA     -1.8mA     -2.4mA
-1.209V   -4.6mA     -3.2mA     -5.3mA
-921.2mV  -10.72mA   -5.8mA     -12.53mA
-575.8mV  -11.32mA   -10.69mA   -10.82mA
1.094V    23.43mA    21.74mA    22.75mA
1.612V    29.99mA    27.48mA    28.84mA
2.073V    31.85mA    28.54mA    30.34mA
2.361V    28.33mA    22.42mA    28.91mA
2.706V    20.7mA     6mA        22.85mA
2.994V    6.3mA      3mA        16.1mA
3.224V    3.7mA      2.4mA      6.2mA
3.57V     2.7mA      2mA        3.1mA
[Pullup]
-1.77V    1mA        900uA      673.7uA
-1.309V   2.4mA      1.547mA    2.937mA
-1.021V   9.6mA      3.616mA    12.09mA
-848.5mV  16.65mA    7.674mA    14.42mA
-618.2mV  16.88mA    14.82mA    14.75mA
763.6mV   -19.21mA   -17.32mA   -18.28mA
2.088V    -27.84mA   -24.27mA   -26.98mA
2.376V    -25.59mA   -21.23mA   -25.8mA
2.606V    -24.21mA   -12.89mA   -24.15mA
2.779V    -17.5mA    -9.684mA   -23.65mA
3.124V    -9.1mA     -7.526mA   -10.44mA
3.585V    -7.4mA     -6.8mA     -7.074mA
[Ramp]
R_load=50.000Ohm
dV/dt_r   548.370mV/97.500ps  503.040mV/119.500ps  552.720mV/89.500ps
dV/dt_f   548.370mV/105.500ps  503.040mV/129.000ps  552.720mV/96.500ps
[Rising waveform]
R_fixture=50.000Ohm
V_fixture=1.800
V_fixture_min=1.700
V_fixture_max=1.900
0s        913mV      877.3mV    1.001V
48ps      912.2mV    877.2mV    1.064V
96ps      960.6mV    889.1mV    1.485V
115ps     1.055V     902.8mV    1.624V
144ps     1.29V      950.6mV    1.755V
173ps     1.504V     1.062V     1.823V
202ps     1.638V     1.233V     1.859V
269ps     1.76V      1.545V     1.89V
345ps     1.791V     1.659V     1.898V
938ps     1.8V       1.7V       1.9V
[Rising waveform]
R_fixture=50.000Ohm
V_fixture=0
0s        111.9mV    89.42mV    147.3mV
48ps      107.6mV    87.75mV    165.8mV
68ps      103.3mV    86mV       247.9mV
106ps     130.6mV    80.96mV    506.1mV
135ps     243.8mV    79.64mV    687mV
173ps     473.7mV    119.3mV    855.8mV
250ps     834.8mV    418.1mV    1.019V
336ps     988.5mV    730.4mV    1.073V
441ps     1.038V     886.4mV    1.089V
938ps     1.055V     947.6mV    1.096V
[Falling waveform]
R_fixture=50.000Ohm
V_fixture=1.800
V_fixture_min=1.700
V_fixture_max=1.900
0s        1.799V     1.699V     1.903V
58ps      1.814V     1.706V     1.869V
115ps     1.774V     1.724V     1.572V
183ps     1.46V      1.654V     1.24V
230ps     1.234V     1.492V     1.121V
278ps     1.081V     1.301V     1.06V
355ps     972.5mV    1.067V     1.022V
451ps     931.4mV    943.8mV    1.009V
604ps     918.9mV    893.7mV    1.005V
938ps     916.5mV    883.3mV    1.005V
[Falling waveform]
R_fixture=50.000Ohm
V_fixture=0
0s        1.057V     951.6mV    1.101V
39ps      1.063V     956.8mV    1.039V
87ps      984.9mV    940.5mV    647.4mV
106ps     879.6mV    910.7mV    500.3mV
135ps     657.3mV    825mV      349.5mV
163ps     456.5mV    694.2mV    265.9mV
202ps     280.6mV    476.3mV    206.1mV
269ps     162.2mV    227mV      166.4mV
355ps     124mV      125.7mV    152.9mV
938ps     111.5mV    89.24mV    149.2mV
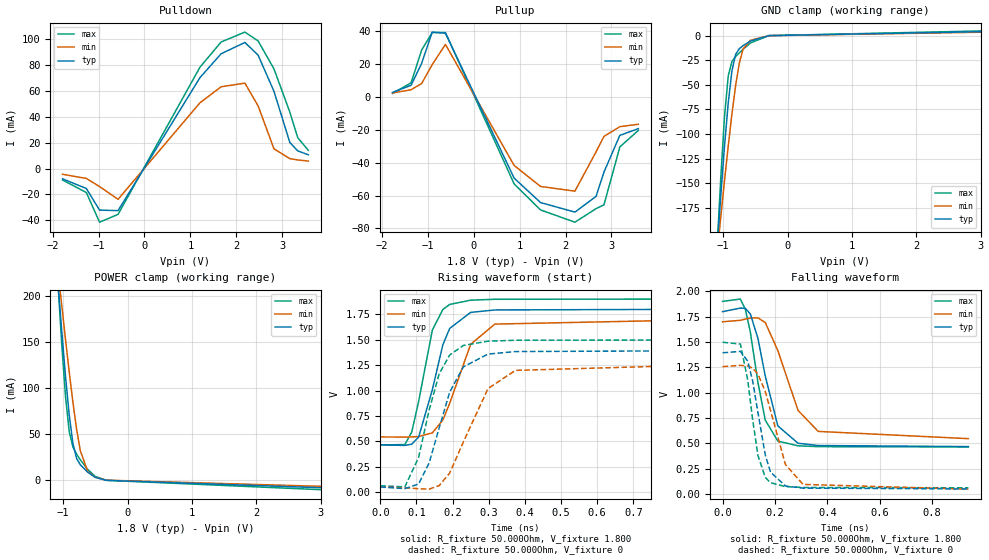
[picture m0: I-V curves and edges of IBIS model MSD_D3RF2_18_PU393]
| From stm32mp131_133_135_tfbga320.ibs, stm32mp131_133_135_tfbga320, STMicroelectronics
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[Model] MSD_D3RF2_18_PU393
Model_type   I/O
C_comp 2.345pF   2.264pF   2.466pF
Vinh = 1.150V
Vinl = 650.000mV
Vmeas = 900.000mV
Vref = 900.000mV
[Model Spec]
Vinh   1.150V   1.100V   1.200V
Vinl   650.000mV   600.000mV   700.000mV
Vmeas   900.000mV   850.000mV   950.000mV
Vref   900.000mV   850.000mV   950.000mV
[Temperature Range]   25.000   125.000   -40.000
[Voltage Range]   1.800V   1.700V   1.900V
[GND Clamp Reference]   0.00V   0.00V   0.00V
[Pulldown Reference]   0.00V   0.00V   0.00V
[POWER Clamp Reference]   1.800V   1.700V   1.900V
[Pullup Reference]   1.800V   1.700V   1.900V
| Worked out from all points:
|   slope of the pulldown table from 0 to 0.27 V, typ, clamps not added: 15.3 ohm
|   slope of the pullup table from 0 to 0.27 V, typ, clamps not added: 14.6 ohm
|   GND clamp passes 1 mA (typ) near -0.41 V on its own axis
|   POWER clamp passes 1 mA (typ) near -0.41 V on its own axis
|   rising waveform, R_fixture 50.000Ohm, V_fixture 1.800: 20-80 % time 55.4ps typ, 71.2ps min, 47.7ps max; typ from 0.468 V to 1.8 V
|   rising waveform, R_fixture 50.000Ohm, V_fixture 0: 20-80 % time 71.1ps typ, 90.3ps min, 62.1ps max; typ from 0.053 V to 1.39 V
|   falling waveform, R_fixture 50.000Ohm, V_fixture 1.800: 20-80 % time 66.1ps typ, 93.6ps min, 55.9ps max; typ from 1.8 V to 0.47 V
|   falling waveform, R_fixture 50.000Ohm, V_fixture 0: 20-80 % time 55.7ps typ, 77.7ps min, 46.8ps max; typ from 1.39 V to 0.052 V
[GND Clamp]
-1.785V   -901.6mA   -689mA     -1.21A
-1.094V   -214.8mA   -221mA     -215.5mA
-1.036V   -162mA     -183.8mA   -143.6mA
-978.8mV  -112.3mA   -147.4mA   -82.21mA
-921.2mV  -68.61mA   -112.4mA   -41.12mA
-863.6mV  -35.84mA   -79.69mA   -26.31mA
-806.1mV  -19.09mA   -50.68mA   -21.38mA
-748.5mV  -13.3mA    -27.86mA   -17.56mA
-690.9mV  -10.28mA   -13.84mA   -13.97mA
-575.8mV  -5.56mA    -4.768mA   -7.53mA
-287.9mV  -69.99uA   -117uA     -56.99uA
3.57V     4.61mA     3.97mA     5.507mA
[Power Clamp]
-1.77V    883mA      690.2mA    1.159A
-1.079V   212.6mA    226.6mA    212.4mA
-1.021V   161mA      189.5mA    146.9mA
-963.6mV  113.1mA    153.1mA    91.15mA
-906.1mV  71.31mA    117.9mA    53.09mA
-848.5mV  40.15mA    84.87mA    36.33mA
-790.9mV  23.9mA     55.52mA    28.61mA
-733.3mV  17.07mA    32.3mA     22.42mA
-618.2mV  9.01mA     9.784mA    12.01mA
-503mV    3.446mA    3.544mA    4.486mA
-330.3mV  160.6uA    336.1uA    187.2uA
3.585V    -9.248mA   -7.505mA   -11.75mA
[Pulldown]
-1.785V   -7.9mA     -4.4mA     -8.8mA
-1.267V   -15.4mA    -7.6mA     -18.5mA
-978.8mV  -32.1mA    -13.9mA    -41.45mA
-575.8mV  -32.5mA    -23.75mA   -35.4mA
1.209V    70.38mA    50.93mA    78.44mA
1.67V     88.85mA    63.31mA    97.95mA
2.188V    97.58mA    66.1mA     105.6mA
2.476V    87.77mA    48.51mA    98.73mA
2.821V    59.8mA     15.3mA     77.15mA
3.167V    20.2mA     7.7mA      43.7mA
3.339V    13.7mA     6.7mA      23.9mA
3.57V     10.7mA     5.8mA      14.1mA
[Pullup]
-1.77V    2.9mA      2.547mA    2.253mA
-1.367V   7.2mA      4.495mA    8.716mA
-1.136V   20.6mA     8.305mA    28.69mA
-906.1mV  39.63mA    19.82mA    39.35mA
-618.2mV  38.98mA    32.14mA    39.33mA
878.8mV   -49.38mA   -41.66mA   -52.88mA
1.455V    -64.25mA   -54.44mA   -68.75mA
2.203V    -70.07mA   -57.29mA   -76.21mA
2.664V    -60.48mA   -33.33mA   -67.94mA
2.836V    -45.7mA    -23.95mA   -65.66mA
3.182V    -23.3mA    -18.01mA   -30.35mA
3.585V    -19.2mA    -16.53mA   -20.27mA
[Ramp]
R_load=50.000Ohm
dV/dt_r   801.285mV/64.000ps  707.547mV/82.000ps  860.346mV/55.500ps
dV/dt_f   801.285mV/61.500ps  707.547mV/86.500ps  860.346mV/52.000ps
[Rising waveform]
R_fixture=50.000Ohm
V_fixture=1.800
V_fixture_min=1.700
V_fixture_max=1.900
0s        468.3mV    544.6mV    465.6mV
68ps      461.5mV    543.5mV    470.2mV
87ps      473.3mV    544.9mV    592mV
106ps     542.1mV    548.7mV    891.4mV
144ps     1.008V     584.7mV    1.594V
173ps     1.449V     709.6mV    1.797V
192ps     1.611V     875.3mV    1.847V
250ps     1.769V     1.455V     1.889V
317ps     1.793V     1.654V     1.898V
938ps     1.8V       1.7V       1.9V
[Rising waveform]
R_fixture=50.000Ohm
V_fixture=0
0s        53.16mV    50.97mV    64.72mV
68ps      36.92mV    45.27mV    53.97mV
106ps     82.33mV    35.83mV    342.6mV
135ps     287.1mV    31.41mV    806.6mV
163ps     633.6mV    66.44mV    1.165V
192ps     985.2mV    189.5mV    1.35V
230ps     1.234V     496.2mV    1.444V
298ps     1.359V     1.02V      1.486V
374ps     1.384V     1.199V     1.495V
938ps     1.393V     1.256V     1.498V
[Falling waveform]
R_fixture=50.000Ohm
V_fixture=1.800
V_fixture_min=1.700
V_fixture_max=1.900
0s        1.798V     1.698V     1.899V
68ps      1.833V     1.713V     1.922V
87ps      1.831V     1.725V     1.821V
106ps     1.775V     1.735V     1.597V
135ps     1.535V     1.737V     1.101V
163ps     1.164V     1.691V     729.9mV
211ps     673.2mV    1.415V     523.6mV
288ps     502.5mV    825.9mV    477.3mV
365ps     479.9mV    618.9mV    468.9mV
938ps     469.6mV    547.7mV    466mV
[Falling waveform]
R_fixture=50.000Ohm
V_fixture=0
0s        1.393V     1.257V     1.497V
68ps      1.407V     1.269V     1.479V
96ps      1.311V     1.264V     1.127V
115ps     1.114V     1.242V     730mV
135ps     805.8mV    1.184V     382.8mV
163ps     386.8mV    1.012V     166.8mV
183ps     218.4mV    825.4mV    113.7mV
240ps     81.58mV    292.9mV    75.53mV
307ps     60.6mV     97.26mV    66.89mV
938ps     52.36mV    50.33mV    63.88mV
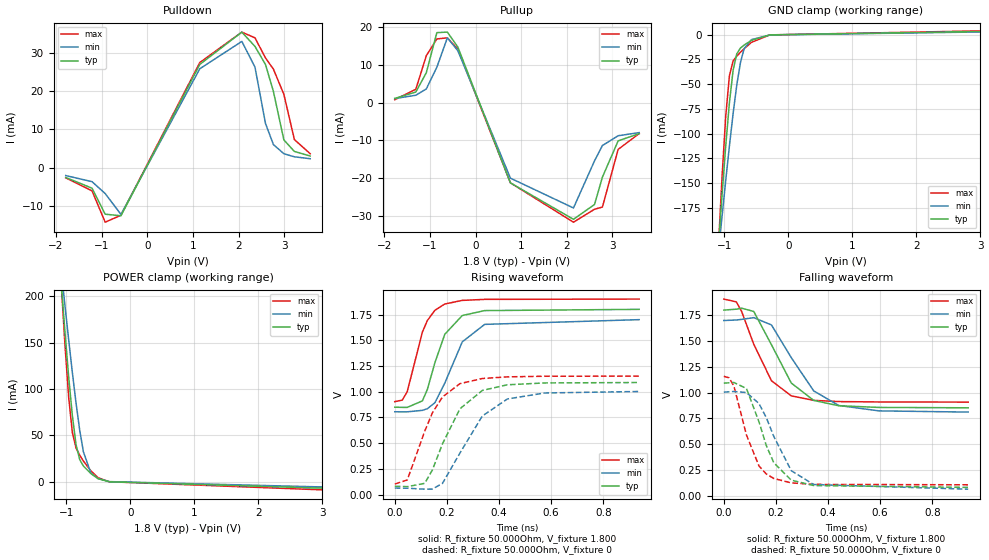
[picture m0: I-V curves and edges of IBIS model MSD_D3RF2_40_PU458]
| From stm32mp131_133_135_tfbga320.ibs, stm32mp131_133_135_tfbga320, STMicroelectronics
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[Model] MSD_D3RF2_40_PU458
Model_type   I/O
C_comp 2.374pF   2.292pF   2.496pF
Vinh = 1.150V
Vinl = 650.000mV
Vmeas = 900.000mV
Vref = 900.000mV
[Model Spec]
Vinh   1.150V   1.100V   1.200V
Vinl   650.000mV   600.000mV   700.000mV
Vmeas   900.000mV   850.000mV   950.000mV
Vref   900.000mV   850.000mV   950.000mV
[Temperature Range]   25.000   125.000   -40.000
[Voltage Range]   1.800V   1.700V   1.900V
[GND Clamp Reference]   0.00V   0.00V   0.00V
[Pulldown Reference]   0.00V   0.00V   0.00V
[POWER Clamp Reference]   1.800V   1.700V   1.900V
[Pullup Reference]   1.800V   1.700V   1.900V
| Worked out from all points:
|   slope of the pulldown table from 0 to 0.27 V, typ, clamps not added: 37.2 ohm
|   slope of the pullup table from 0 to 0.27 V, typ, clamps not added: 29.4 ohm
|   GND clamp passes 1 mA (typ) near -0.40 V on its own axis
|   POWER clamp passes 1 mA (typ) near -0.41 V on its own axis
|   rising waveform, R_fixture 50.000Ohm, V_fixture 1.800: 20-80 % time 76.1ps typ, 94.1ps min, 68.1ps max; typ from 0.849 V to 1.8 V
|   rising waveform, R_fixture 50.000Ohm, V_fixture 0: 20-80 % time 116ps typ, 135ps min, 105ps max; typ from 0.081 V to 1.09 V
|   falling waveform, R_fixture 50.000Ohm, V_fixture 1.800: 20-80 % time 119ps typ, 138ps min, 104ps max; typ from 1.8 V to 0.852 V
|   falling waveform, R_fixture 50.000Ohm, V_fixture 0: 20-80 % time 87.2ps typ, 104ps min, 76.1ps max; typ from 1.09 V to 0.08 V
[GND Clamp]
-1.785V   -902.1mA   -689.3mA   -1.211A
-1.094V   -215mA     -221.2mA   -215.8mA
-1.036V   -162.1mA   -183.9mA   -143.7mA
-978.8mV  -112.5mA   -147.5mA   -82.43mA
-921.2mV  -68.76mA   -112.6mA   -41.32mA
-863.6mV  -35.98mA   -79.81mA   -26.48mA
-806.1mV  -19.2mA    -50.78mA   -21.53mA
-748.5mV  -13.39mA   -27.95mA   -17.68mA
-690.9mV  -10.36mA   -13.92mA   -14.07mA
-575.8mV  -5.615mA   -4.814mA   -7.598mA
-287.9mV  -70.99uA   -120uA     -56.99uA
3.57V     3.952mA    3.403mA    4.721mA
[Power Clamp]
-1.77V    883.4mA    690.7mA    1.16A
-1.079V   212.8mA    226.9mA    212.7mA
-1.021V   161.2mA    189.6mA    147.2mA
-963.6mV  113.2mA    153.2mA    91.32mA
-906.1mV  71.46mA    118mA      53.29mA
-848.5mV  40.28mA    85mA       36.5mA
-790.9mV  24.01mA    55.62mA    28.77mA
-733.3mV  17.16mA    32.39mA    22.55mA
-618.2mV  9.07mA     9.843mA    12.09mA
-503mV    3.48mA     3.576mA    4.528mA
-330.3mV  164.3uA    342.2uA    191.7uA
3.585V    -7.932mA   -6.431mA   -10.07mA
[Pulldown]
-1.785V   -2.6mA     -2.1mA     -2.7mA
-1.209V   -5.4mA     -3.7mA     -6.1mA
-921.2mV  -12.19mA   -6.8mA     -14.28mA
-575.8mV  -12.6mA    -12.24mA   -12.47mA
1.152V    26.93mA    25.79mA    27.42mA
2.073V    35.36mA    32.94mA    35.37mA
2.361V    31.62mA    26.21mA    33.86mA
2.591V    26.91mA    11.5mA     28.62mA
2.764V    19.9mA     6mA        25.71mA
2.994V    7.2mA      3.6mA      19.1mA
3.224V    4.2mA      2.8mA      7.3mA
3.57V     3mA        2.3mA      3.6mA
[Pullup]
-1.77V    1.1mA      1.074mA    773.7uA
-1.309V   2.8mA      1.947mA    3.516mA
-1.079V   7.9mA      3.616mA    12.4mA
-848.5mV  18.49mA    9.339mA    16.82mA
-618.2mV  18.64mA    17.12mA    17.12mA
-387.9mV  14.68mA    13.72mA    14.14mA
763.6mV   -21.21mA   -19.96mA   -21.19mA
2.145V    -30.84mA   -27.84mA   -31.6mA
2.606V    -26.92mA   -15.4mA    -28.18mA
2.779V    -19.7mA    -11.34mA   -27.6mA
3.124V    -10.1mA    -8.753mA   -12.36mA
3.585V    -8.2mA     -7.926mA   -8.174mA
[Ramp]
R_load=50.000Ohm
dV/dt_r   587.172mV/97.000ps  548.808mV/115.000ps  611.610mV/87.500ps
dV/dt_f   587.172mV/103.500ps  548.778mV/122.000ps  611.610mV/90.500ps
[Rising waveform]
R_fixture=50.000Ohm
V_fixture=1.800
V_fixture_min=1.700
V_fixture_max=1.900
0s        849.2mV    804.9mV    903.3mV
29ps      847.6mV    804mV      918.3mV
48ps      847.5mV    804.3mV    1.002V
106ps     910.7mV    818.7mV    1.579V
125ps     1.021V     834.4mV    1.691V
154ps     1.282V     892.9mV    1.791V
192ps     1.558V     1.084V     1.852V
259ps     1.74V      1.484V     1.887V
345ps     1.788V     1.654V     1.897V
938ps     1.8V       1.7V       1.9V
[Rising waveform]
R_fixture=50.000Ohm
V_fixture=0
0s        80.95mV    63.64mV    102.3mV
48ps      77.12mV    62.04mV    142mV
115ps     109.5mV    52.79mV    616.1mV
144ps     237.1mV    53.32mV    792.5mV
183ps     492.5mV    108.9mV    948.4mV
250ps     833.6mV    403.3mV    1.078V
336ps     1.012V     763.7mV    1.128V
432ps     1.067V     929.1mV    1.144V
575ps     1.085V     987.4mV    1.15V
938ps     1.089V     1.002V     1.151V
[Falling waveform]
R_fixture=50.000Ohm
V_fixture=1.800
V_fixture_min=1.700
V_fixture_max=1.900
0s        1.799V     1.698V     1.906V
48ps      1.808V     1.703V     1.879V
68ps      1.818V     1.709V     1.789V
115ps     1.786V     1.726V     1.468V
183ps     1.463V     1.655V     1.114V
259ps     1.092V     1.338V     967.8mV
345ps     923.8mV    1.016V     923.9mV
441ps     871.8mV    874.6mV    912.3mV
595ps     855.7mV    822.2mV    908.6mV
938ps     851.9mV    810.4mV    907.2mV
[Falling waveform]
R_fixture=50.000Ohm
V_fixture=0
0s        1.091V     1.004V     1.157V
20ps      1.094V     1.007V     1.143V
39ps      1.097V     1.01V      1.061V
87ps      1.039V     1V         588mV
135ps     716.7mV    893.5mV    288.4mV
163ps     487.2mV    757.1mV    210.7mV
192ps     319.3mV    573.6mV    166.8mV
259ps     150.6mV    242.2mV    124.2mV
345ps     98.11mV    108mV      109.7mV
938ps     80.45mV    63.28mV    105.5mV
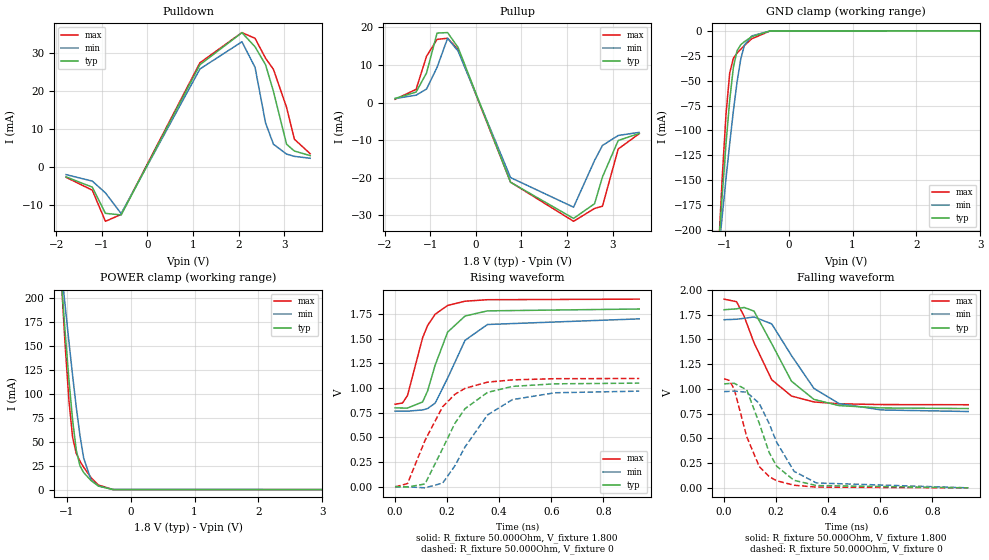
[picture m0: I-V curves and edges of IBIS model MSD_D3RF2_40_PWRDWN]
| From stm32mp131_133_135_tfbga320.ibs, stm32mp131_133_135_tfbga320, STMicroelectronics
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[Model] MSD_D3RF2_40_PWRDWN
Model_type   I/O
C_comp 2.550pF   2.465pF   2.675pF
Vinh = 1.150V
Vinl = 650.000mV
Vmeas = 900.000mV
Vref = 900.000mV
[Model Spec]
Vinh   1.150V   1.100V   1.200V
Vinl   650.000mV   600.000mV   700.000mV
Vmeas   900.000mV   850.000mV   950.000mV
Vref   900.000mV   850.000mV   950.000mV
[Temperature Range]   25.000   125.000   -40.000
[Voltage Range]   1.800V   1.700V   1.900V
[GND Clamp Reference]   0.00V   0.00V   0.00V
[Pulldown Reference]   0.00V   0.00V   0.00V
[POWER Clamp Reference]   1.800V   1.700V   1.900V
[Pullup Reference]   1.800V   1.700V   1.900V
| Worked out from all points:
|   slope of the pulldown table from 0 to 0.27 V, typ, clamps not added: 37.2 ohm
|   slope of the pullup table from 0 to 0.27 V, typ, clamps not added: 29.4 ohm
|   GND clamp passes 1 mA (typ) near -0.40 V on its own axis
|   POWER clamp passes 1 mA (typ) near -0.40 V on its own axis
|   rising waveform, R_fixture 50.000Ohm, V_fixture 1.800: 20-80 % time 81.9ps typ, 99.4ps min, 75ps max; typ from 0.798 V to 1.8 V
|   rising waveform, R_fixture 50.000Ohm, V_fixture 0: 20-80 % time 132ps typ, 149ps min, 124ps max; typ from 0.001 V to 1.05 V
|   falling waveform, R_fixture 50.000Ohm, V_fixture 1.800: 20-80 % time 126ps typ, 145ps min, 112ps max; typ from 1.8 V to 0.801 V
|   falling waveform, R_fixture 50.000Ohm, V_fixture 0: 20-80 % time 91.9ps typ, 108ps min, 81.7ps max; typ from 1.05 V to 0 V
[GND Clamp]
-1.785V   -904.7mA   -691.7mA   -1.214A
-1.094V   -216.3mA   -222.2mA   -217.4mA
-1.036V   -163.3mA   -184.8mA   -145.2mA
-978.8mV  -113.5mA   -148.4mA   -83.76mA
-921.2mV  -69.69mA   -113.3mA   -42.51mA
-863.6mV  -36.79mA   -80.49mA   -27.53mA
-806.1mV  -19.91mA   -51.37mA   -22.45mA
-748.5mV  -14mA      -28.45mA   -18.47mA
-690.9mV  -10.87mA   -14.34mA   -14.73mA
-575.8mV  -5.929mA   -5.08mA    -8.007mA
-287.9mV  -82.85uA   -135.6uA   -69.2uA
3.57V     41.7nA     685.7nA    4.362nA
[Power Clamp]
-1.77V    886.2mA    693mA      1.163A
-1.079V   214.1mA    227.9mA    214.3mA
-1.021V   162.4mA    190.6mA    148.6mA
-963.6mV  114.3mA    154.1mA    92.64mA
-906.1mV  72.38mA    118.8mA    54.46mA
-848.5mV  41.09mA    85.68mA    37.53mA
-790.9mV  24.71mA    56.22mA    29.66mA
-733.3mV  17.76mA    32.9mA     23.31mA
-618.2mV  9.462mA    10.19mA    12.58mA
-503mV    3.682mA    3.772mA    4.784mA
-272.7mV  36.6uA     118.7uA    36.53uA
3.585V    -62.58nA   -1.1uA     -6.985nA
[Pulldown]
-1.785V   -2.6mA     -2mA       -2.7mA
-1.209V   -5.3mA     -3.7mA     -6.1mA
-921.2mV  -12.19mA   -6.8mA     -14.28mA
-575.8mV  -12.6mA    -12.25mA   -12.47mA
1.152V    26.92mA    25.79mA    27.42mA
2.073V    35.35mA    32.95mA    35.37mA
2.361V    31.62mA    26.21mA    33.85mA
2.591V    26.91mA    11.6mA     28.62mA
2.764V    19.9mA     6mA        25.7mA
3.052V    6mA        3.4mA      15.7mA
3.224V    4.2mA      2.8mA      7.3mA
3.57V     3mA        2.3mA      3.5mA
[Pullup]
-1.77V    1.1mA      1.074mA    873.7uA
-1.309V   2.8mA      1.974mA    3.516mA
-1.079V   7.9mA      3.616mA    12.35mA
-848.5mV  18.5mA     9.373mA    16.82mA
-618.2mV  18.64mA    17.12mA    17.13mA
-387.9mV  14.68mA    13.71mA    14.14mA
763.6mV   -21.21mA   -19.96mA   -21.18mA
2.145V    -30.84mA   -27.84mA   -31.6mA
2.606V    -26.91mA   -15.4mA    -28.18mA
2.779V    -19.8mA    -11.41mA   -27.59mA
3.124V    -10.1mA    -8.753mA   -12.36mA
3.585V    -8.2mA     -7.926mA   -8.274mA
[Ramp]
R_load=50.000Ohm
dV/dt_r   614.460mV/108.000ps  569.819mV/125.000ps  646.950mV/100.000ps
dV/dt_f   614.460mV/110.000ps  569.819mV/128.000ps  646.950mV/98.000ps
[Rising waveform]
R_fixture=50.000Ohm
V_fixture=1.800
V_fixture_min=1.700
V_fixture_max=1.900
0s        798.4mV    765.6mV    835.6mV
29ps      796.8mV    764.6mV    848mV
48ps      796.6mV    764.9mV    925mV
106ps     858.5mV    777.6mV    1.51V
125ps     969.7mV    791.8mV    1.633V
154ps     1.231V     846.2mV    1.747V
202ps     1.566V     1.1V       1.836V
269ps     1.729V     1.483V     1.879V
355ps     1.781V     1.643V     1.894V
938ps     1.8V       1.7V       1.9V
[Rising waveform]
R_fixture=50.000Ohm
V_fixture=0
0s        671.3uV    672.7uV    -3.063mV
48ps      -3.498mV   -982.5uV   31.85mV
115ps     27.34mV    -11.92mV   468.6mV
183ps     387.4mV    36.51mV    810.9mV
230ps     642.6mV    212mV      935.6mV
269ps     790.5mV    403.2mV    996.4mV
355ps     954.9mV    726.2mV    1.059V
451ps     1.016V     882mV      1.082V
614ps     1.042V     951.4mV    1.094V
938ps     1.049V     967.9mV    1.096V
[Falling waveform]
R_fixture=50.000Ohm
V_fixture=1.800
V_fixture_min=1.700
V_fixture_max=1.900
0s        1.799V     1.698V     1.906V
48ps      1.808V     1.703V     1.88V
77ps      1.822V     1.712V     1.733V
115ps     1.785V     1.726V     1.466V
183ps     1.456V     1.656V     1.092V
259ps     1.077V     1.336V     927.2mV
345ps     893.7mV    1.005V     867.7mV
441ps     830.9mV    851.8mV    849.1mV
604ps     807mV      786.9mV    841.2mV
938ps     801mV      771mV      839.4mV
[Falling waveform]
R_fixture=50.000Ohm
V_fixture=0
0s        1.05V      971.9mV    1.102V
20ps      1.054V     974.8mV    1.085V
39ps      1.056V     977.5mV    997.3mV
87ps      989.8mV    966.1mV    517.3mV
135ps     653mV      853.3mV    215.9mV
173ps     358.3mV    650.6mV    113.7mV
202ps     218.8mV    460.7mV    71.96mV
269ps     75.86mV    166.5mV    26.19mV
355ps     23.39mV    49.41mV    7.451mV
938ps     -2.021uV   130.8uV    20.61uV
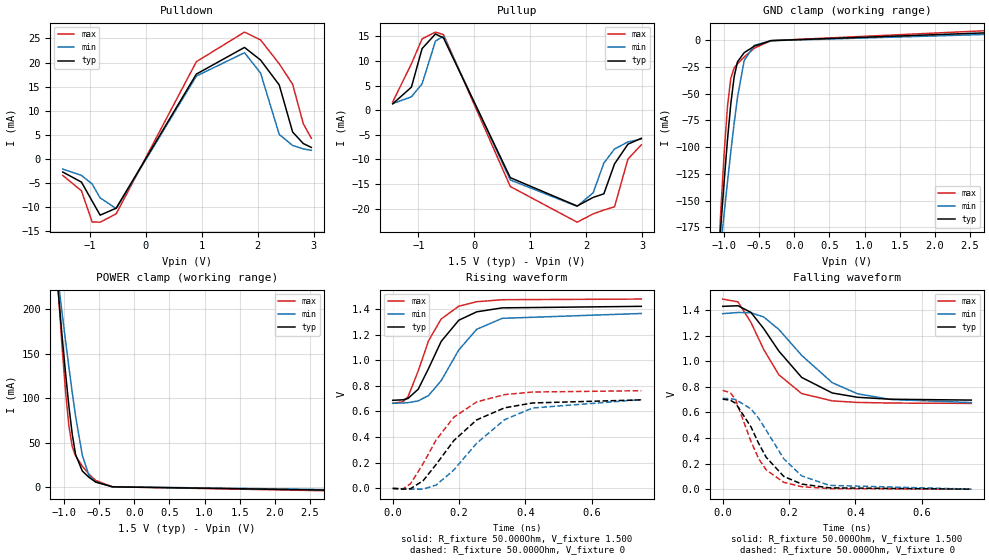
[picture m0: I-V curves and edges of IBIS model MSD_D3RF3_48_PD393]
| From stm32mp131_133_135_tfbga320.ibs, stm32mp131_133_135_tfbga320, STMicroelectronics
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[Model] MSD_D3RF3_48_PD393
Model_type   I/O
C_comp 2.355pF   2.274pF   2.477pF
Vinh = 925.000mV
Vinl = 575.000mV
Vmeas = 750.000mV
Vref = 750.000mV
[Model Spec]
Vinh   925.000mV   888.000mV   963.000mV
Vinl   575.000mV   538.000mV   613.000mV
Vmeas   750.000mV   713.000mV   788.000mV
Vref   750.000mV   713.000mV   788.000mV
[Temperature Range]   25.000   125.000   -40.000
[Voltage Range]   1.500V   1.425V   1.575V
[GND Clamp Reference]   0.00V   0.00V   0.00V
[Pulldown Reference]   0.00V   0.00V   0.00V
[POWER Clamp Reference]   1.500V   1.425V   1.575V
[Pullup Reference]   1.500V   1.425V   1.575V
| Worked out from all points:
|   slope of the pulldown table from 0 to 0.225 V, typ, clamps not added: 44.1 ohm
|   slope of the pullup table from 0 to 0.225 V, typ, clamps not added: 37.5 ohm
|   GND clamp passes 1 mA (typ) near -0.40 V on its own axis
|   POWER clamp passes 1 mA (typ) near -0.41 V on its own axis
|   rising waveform, R_fixture 50.000Ohm, V_fixture 1.500: 20-80 % time 92.1ps typ, 109ps min, 78.3ps max; typ from 0.688 V to 1.42 V
|   rising waveform, R_fixture 50.000Ohm, V_fixture 0: 20-80 % time 147ps typ, 168ps min, 126ps max; typ from -0.003 V to 0.691 V
|   falling waveform, R_fixture 50.000Ohm, V_fixture 1.500: 20-80 % time 137ps typ, 166ps min, 109ps max; typ from 1.43 V to 0.696 V
|   falling waveform, R_fixture 50.000Ohm, V_fixture 0: 20-80 % time 93.9ps typ, 113ps min, 77.2ps max; typ from 0.703 V to 0 V
[GND Clamp]
-1.48V    -594.2mA   -480mA     -763.6mA
-1.098V   -218.4mA   -223.5mA   -220.5mA
-1.05V    -174.3mA   -192.5mA   -159.9mA
-1.002V   -132.1mA   -162.1mA   -105.5mA
-954.6mV  -92.99mA   -132.5mA   -61.72mA
-906.8mV  -59.16mA   -104mA     -35.32mA
-859.1mV  -33.93mA   -77.28mA   -25.79mA
-811.4mV  -20.01mA   -53.17mA   -21.76mA
-715.9mV  -11.49mA   -18.81mA   -15.51mA
-572.7mV  -5.463mA   -4.679mA   -7.379mA
-334.1mV  -245.4uA   -313.4uA   -248.8uA
2.959V    7.591mA    5.979mA    9.761mA
[Power Clamp]
-1.459V   577.8mA    479.3mA    723.3mA
-1.077V   211.2mA    225.6mA    210.4mA
-1.03V    168.3mA    194.7mA    155.7mA
-981.8mV  127.7mA    164.4mA    106.9mA
-934.1mV  90.61mA    134.7mA    68.43mA
-886.4mV  59.12mA    106.2mA    45.32mA
-838.6mV  36.26mA    79.46mA    34.74mA
-743.2mV  17.92mA    35.58mA    23.41mA
-647.7mV  10.79mA    12.86mA    14.4mA
-552.3mV  5.5mA      5.442mA    7.264mA
-313.6mV  95.81uA    225.2uA    112.2uA
2.98V     -3.864mA   -3.241mA   -4.693mA
[Pulldown]
-1.48V    -2.7mA     -2.1mA     -3.4mA
-1.145V   -4.8mA     -3.4mA     -6.6mA
-954.6mV  -8.72mA    -5.2mA     -13.06mA
-811.4mV  -11.65mA   -8.07mA    -13.11mA
-525mV    -10.2mA    -10.28mA   -11.37mA
906.8mV   17.61mA    17.2mA     20.18mA
1.766V    23.14mA    22.04mA    26.32mA
2.052V    20.53mA    17.85mA    24.7mA
2.386V    15.36mA    5.1mA      19.75mA
2.625V    5.6mA      2.8mA      15.5mA
2.816V    3.2mA      2.1mA      7.3mA
2.959V    2.4mA      1.8mA      4.3mA
[Pullup]
-1.459V   1.3mA      1.357mA    1.686mA
-1.125V   4.7mA      2.729mA    9.443mA
-934.1mV  12.54mA    5.386mA    14.52mA
-695.5mV  15.51mA    14.06mA    15.89mA
-552.3mV  14.7mA     15.08mA    15.38mA
640.9mV   -13.71mA   -14.18mA   -15.51mA
1.834V    -19.47mA   -19.54mA   -22.76mA
2.12V     -17.72mA   -16.78mA   -21.07mA
2.311V    -16.99mA   -10.74mA   -20.29mA
2.502V    -10.9mA    -7.871mA   -19.63mA
2.741V    -6.9mA     -6.443mA   -9.928mA
2.98V     -5.7mA     -5.843mA   -7.029mA
[Ramp]
R_load=50.000Ohm
dV/dt_r   426.660mV/120.500ps  417.599mV/139.500ps  472.320mV/102.500ps
dV/dt_f   426.660mV/116.000ps  417.599mV/140.500ps  472.320mV/93.500ps
[Rising waveform]
R_fixture=50.000Ohm
V_fixture=1.500
V_fixture_min=1.425
V_fixture_max=1.575
0s        687.7mV    664.5mV    664.3mV
31ps      691.5mV    666.3mV    676.3mV
46ps      701.8mV    669mV      715.1mV
77ps      775.1mV    683.1mV    918.5mV
108ps     937.1mV    725.2mV    1.154V
146ps     1.149V     841.4mV    1.325V
199ps     1.315V     1.082V     1.425V
253ps     1.381V     1.244V     1.46V
330ps     1.412V     1.33V      1.476V
749ps     1.424V     1.368V     1.481V
[Rising waveform]
R_fixture=50.000Ohm
V_fixture=0
0s        -2.897mV   -1.868mV   -3.356mV
31ps      -8.445mV   -5.466mV   -6.13mV
54ps      -4.686mV   -8.807mV   34.04mV
92ps      58.58mV    -8.54mV    192.6mV
131ps     185.6mV    23.65mV    377.9mV
184ps     371.6mV    141.3mV    554.7mV
253ps     534.2mV    351.3mV    675.2mV
337ps     628.6mV    535.6mV    732.1mV
421ps     666.7mV    627.1mV    752.4mV
749ps     691mV      693mV      762.8mV
[Falling waveform]
R_fixture=50.000Ohm
V_fixture=1.500
V_fixture_min=1.425
V_fixture_max=1.575
0s        1.428V     1.371V     1.485V
46ps      1.433V     1.38V      1.463V
85ps      1.381V     1.378V     1.303V
123ps     1.256V     1.346V     1.094V
169ps     1.079V     1.248V     893.6mV
238ps     872.7mV    1.045V     746.9mV
330ps     751.4mV    831.8mV    689.7mV
406ps     717.7mV    745.3mV    677.6mV
506ps     702.4mV    700.7mV    672.7mV
749ps     695.9mV    676.4mV    670mV
[Falling waveform]
R_fixture=50.000Ohm
V_fixture=0
0s        703mV      708.6mV    771.5mV
23ps      695mV      707.1mV    754mV
39ps      670.8mV    700.1mV    698.8mV
85ps      487mV      627.4mV    374.5mV
108ps     359mV      554.4mV    239mV
131ps     248.9mV    460.5mV    150.4mV
184ps     99.61mV    237.2mV    53.29mV
238ps     39.71mV    103.5mV    19.48mV
322ps     10.3mV     29.57mV    4.31mV
749ps     31.26uV    180uV      -10.72uV
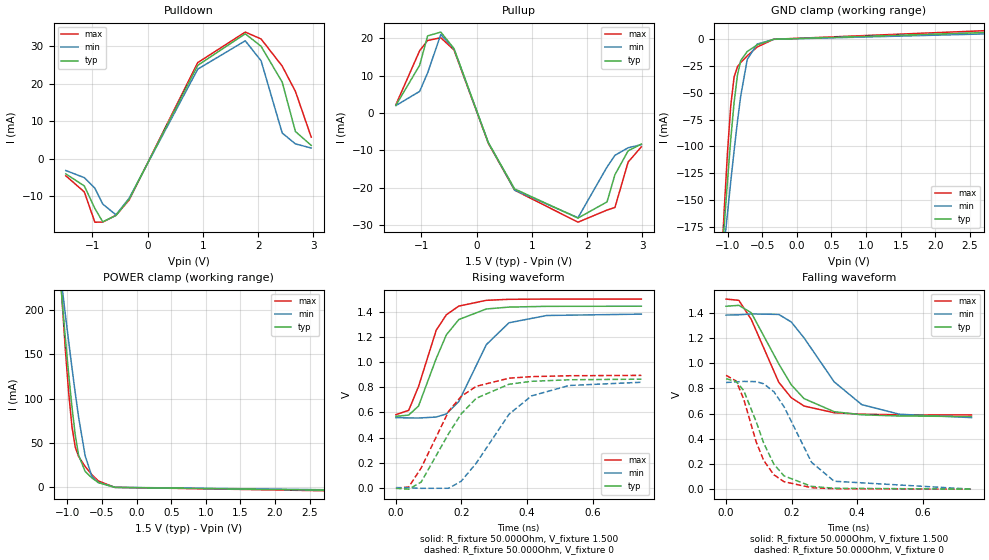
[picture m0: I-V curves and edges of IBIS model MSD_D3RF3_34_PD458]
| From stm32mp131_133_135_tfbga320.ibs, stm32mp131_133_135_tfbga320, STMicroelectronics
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[Model] MSD_D3RF3_34_PD458
Model_type   I/O
C_comp 2.385pF   2.303pF   2.507pF
Vinh = 925.000mV
Vinl = 575.000mV
Vmeas = 750.000mV
Vref = 750.000mV
[Model Spec]
Vinh   925.000mV   888.000mV   963.000mV
Vinl   575.000mV   538.000mV   613.000mV
Vmeas   750.000mV   713.000mV   788.000mV
Vref   750.000mV   713.000mV   788.000mV
[Temperature Range]   25.000   125.000   -40.000
[Voltage Range]   1.500V   1.425V   1.575V
[GND Clamp Reference]   0.00V   0.00V   0.00V
[Pulldown Reference]   0.00V   0.00V   0.00V
[POWER Clamp Reference]   1.500V   1.425V   1.575V
[Pullup Reference]   1.500V   1.425V   1.575V
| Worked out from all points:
|   slope of the pulldown table from 0 to 0.225 V, typ, clamps not added: 31.5 ohm
|   slope of the pullup table from 0 to 0.225 V, typ, clamps not added: 26.9 ohm
|   GND clamp passes 1 mA (typ) near -0.40 V on its own axis
|   POWER clamp passes 1 mA (typ) near -0.41 V on its own axis
|   rising waveform, R_fixture 50.000Ohm, V_fixture 1.500: 20-80 % time 81.1ps typ, 97ps min, 72.2ps max; typ from 0.569 V to 1.45 V
|   rising waveform, R_fixture 50.000Ohm, V_fixture 0: 20-80 % time 126ps typ, 142ps min, 114ps max; typ from -0.005 V to 0.865 V
|   falling waveform, R_fixture 50.000Ohm, V_fixture 1.500: 20-80 % time 116ps typ, 143ps min, 101ps max; typ from 1.45 V to 0.577 V
|   falling waveform, R_fixture 50.000Ohm, V_fixture 0: 20-80 % time 83.6ps typ, 102ps min, 72.8ps max; typ from 0.878 V to 0 V
[GND Clamp]
-1.48V    -594.6mA   -480.3mA   -764mA
-1.098V   -218.6mA   -223.7mA   -220.8mA
-1.05V    -174.4mA   -192.7mA   -160.1mA
-1.002V   -132.3mA   -162.2mA   -105.6mA
-954.6mV  -93.15mA   -132.6mA   -61.94mA
-906.8mV  -59.31mA   -104.2mA   -35.51mA
-859.1mV  -34.06mA   -77.39mA   -25.96mA
-811.4mV  -20.13mA   -53.27mA   -21.92mA
-715.9mV  -11.58mA   -18.88mA   -15.63mA
-572.7mV  -5.513mA   -4.72mA    -7.447mA
-334.1mV  -249.6uA   -317.8uA   -254.1uA
2.959V    6.512mA    5.126mA    8.372mA
[Power Clamp]
-1.459V   578.2mA    479.5mA    723.7mA
-1.077V   211.3mA    225.7mA    210.8mA
-1.03V    168.5mA    194.9mA    156mA
-981.8mV  127.8mA    164.6mA    107.1mA
-934.1mV  90.77mA    134.9mA    68.64mA
-886.4mV  59.26mA    106.4mA    45.51mA
-838.6mV  36.4mA     79.58mA    34.92mA
-743.2mV  18.03mA    35.67mA    23.54mA
-647.7mV  10.86mA    12.93mA    14.5mA
-552.3mV  5.551mA    5.488mA    7.32mA
-313.6mV  97.21uA    230.9uA    114.2uA
2.98V     -3.313mA   -2.778mA   -4.023mA
[Pulldown]
-1.48V    -4mA       -3.1mA     -4.5mA
-1.145V   -7.2mA     -5mA       -8.8mA
-954.6mV  -13.21mA   -7.8mA     -16.87mA
-811.4mV  -16.78mA   -12.04mA   -16.85mA
-572.7mV  -15.07mA   -14.91mA   -15.03mA
-334.1mV  -10.72mA   -10.48mA   -10.95mA
906.8mV   24.93mA    23.93mA    25.67mA
1.766V    33.35mA    31.48mA    33.8mA
2.052V    30.01mA    26.15mA    31.97mA
2.434V    20.47mA    6.9mA      24.73mA
2.673V    7.3mA      4mA        18mA
2.959V    3.6mA      2.9mA      5.8mA
[Pullup]
-1.459V   2.1mA      2.014mA    2.271mA
-1.03V    12.8mA     5.814mA    16.7mA
-886.4mV  20.67mA    10.74mA    19.44mA
-647.7mV  21.69mA    21.03mA    20.17mA
-409.1mV  17.29mA    17.18mA    16.92mA
211.4mV   -7.901mA   -7.87mA    -8.056mA
688.6mV   -20.3mA    -20.62mA   -20.64mA
1.834V    -28.1mA    -28.01mA   -29.21mA
2.359V    -23.78mA   -14.44mA   -25.96mA
2.502V    -16.5mA    -11.3mA    -25.27mA
2.741V    -10.1mA    -9.286mA   -13.11mA
2.98V     -8.3mA     -8.443mA   -9.029mA
[Ramp]
R_load=50.000Ohm
dV/dt_r   520.800mV/104.000ps  499.589mV/120.500ps  543.330mV/93.500ps
dV/dt_f   520.800mV/100.000ps  499.559mV/124.500ps  543.330mV/87.500ps
[Rising waveform]
R_fixture=50.000Ohm
V_fixture=1.500
V_fixture_min=1.425
V_fixture_max=1.575
0s        568.9mV    558.7mV    582.8mV
39ps      579.3mV    556.5mV    617.2mV
69ps      651.2mV    555.6mV    807mV
123ps     1.03V      563.5mV    1.256V
154ps     1.219V     588.5mV    1.379V
192ps     1.341V     687.6mV    1.448V
276ps     1.425V     1.141V     1.494V
345ps     1.44V      1.315V     1.502V
460ps     1.446V     1.373V     1.504V
749ps     1.447V     1.384V     1.504V
[Rising waveform]
R_fixture=50.000Ohm
V_fixture=0
0s        -4.989mV   861.6uV    -4.846mV
39ps      -11.59mV   -716.1uV   5.72mV
77ps      45.08mV    -4.815mV   157.3mV
161ps     431.7mV    -4.367mV   609.9mV
199ps     588mV      51.37mV    727.8mV
245ps     712.9mV    195.2mV    808.4mV
345ps     824.9mV    585.6mV    873.1mV
414ps     848.3mV    732.3mV    885.7mV
529ps     860.6mV    815.2mV    892.7mV
749ps     865.4mV    840.6mV    895.5mV
[Falling waveform]
R_fixture=50.000Ohm
V_fixture=1.500
V_fixture_min=1.425
V_fixture_max=1.575
0s        1.453V     1.383V     1.51V
39ps      1.46V      1.385V     1.5V
77ps      1.401V     1.392V     1.348V
161ps     995.1mV    1.388V     848.2mV
199ps     829mV      1.328V     726.7mV
238ps     719.4mV    1.202V     660.3mV
330ps     615.4mV    852.4mV    607.1mV
414ps     590.7mV    671.8mV    595.5mV
529ps     581.2mV    595.1mV    590.6mV
749ps     577.1mV    568.4mV    589.3mV
[Falling waveform]
R_fixture=50.000Ohm
V_fixture=0
0s        877.6mV    847.2mV    904.5mV
31ps      855.5mV    852.1mV    858.7mV
54ps      782.8mV    855.9mV    714.6mV
92ps      535.7mV    854.2mV    375.4mV
115ps     365.4mV    836.9mV    227.3mV
146ps     198.6mV    773.9mV    114.5mV
177ps     105.3mV    654.5mV    59.13mV
261ps     22.01mV    213.2mV    11.92mV
330ps     7.497mV    62.94mV    3.456mV
749ps     40.25uV    360.2uV    24.27uV
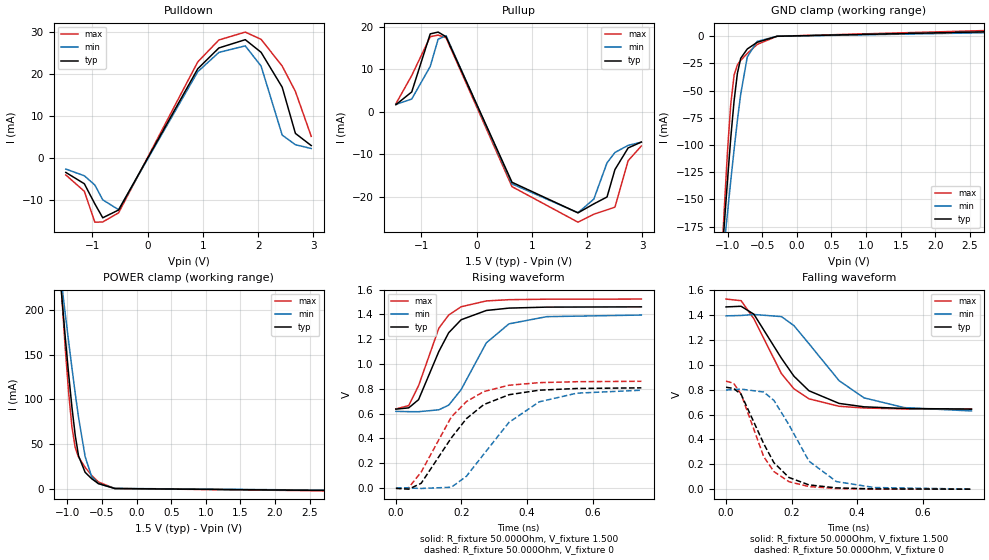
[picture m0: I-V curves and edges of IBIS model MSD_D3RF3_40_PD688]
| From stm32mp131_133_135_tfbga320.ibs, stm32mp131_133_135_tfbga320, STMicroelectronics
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[Model] MSD_D3RF3_40_PD688
Model_type   I/O
C_comp 2.444pF   2.361pF   2.568pF
Vinh = 925.000mV
Vinl = 575.000mV
Vmeas = 750.000mV
Vref = 750.000mV
[Model Spec]
Vinh   925.000mV   888.000mV   963.000mV
Vinl   575.000mV   538.000mV   613.000mV
Vmeas   750.000mV   713.000mV   788.000mV
Vref   750.000mV   713.000mV   788.000mV
[Temperature Range]   25.000   125.000   -40.000
[Voltage Range]   1.500V   1.425V   1.575V
[GND Clamp Reference]   0.00V   0.00V   0.00V
[Pulldown Reference]   0.00V   0.00V   0.00V
[POWER Clamp Reference]   1.500V   1.425V   1.575V
[Pullup Reference]   1.500V   1.425V   1.575V
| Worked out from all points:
|   slope of the pulldown table from 0 to 0.225 V, typ, clamps not added: 36.6 ohm
|   slope of the pullup table from 0 to 0.225 V, typ, clamps not added: 31.2 ohm
|   GND clamp passes 1 mA (typ) near -0.40 V on its own axis
|   POWER clamp passes 1 mA (typ) near -0.41 V on its own axis
|   rising waveform, R_fixture 50.000Ohm, V_fixture 1.500: 20-80 % time 87.3ps typ, 104ps min, 77.6ps max; typ from 0.636 V to 1.46 V
|   rising waveform, R_fixture 50.000Ohm, V_fixture 0: 20-80 % time 139ps typ, 155ps min, 125ps max; typ from -0.004 V to 0.807 V
|   falling waveform, R_fixture 50.000Ohm, V_fixture 1.500: 20-80 % time 131ps typ, 156ps min, 114ps max; typ from 1.47 V to 0.644 V
|   falling waveform, R_fixture 50.000Ohm, V_fixture 0: 20-80 % time 91.1ps typ, 109ps min, 79.5ps max; typ from 0.82 V to 0 V
[GND Clamp]
-1.48V    -595.2mA   -480.8mA   -764.9mA
-1.098V   -219.1mA   -224mA     -221.3mA
-1.05V    -174.8mA   -193mA     -160.6mA
-1.002V   -132.6mA   -162.5mA   -106.1mA
-954.6mV  -93.48mA   -132.9mA   -62.36mA
-906.8mV  -59.6mA    -104.4mA   -35.9mA
-859.1mV  -34.32mA   -77.6mA    -26.31mA
-811.4mV  -20.37mA   -53.46mA   -22.22mA
-715.9mV  -11.76mA   -19.03mA   -15.86mA
-572.7mV  -5.614mA   -4.804mA   -7.58mA
-286.4mV  -74.25uA   -124.6uA   -59.77uA
2.959V    4.342mA    3.42mA     5.581mA
[Power Clamp]
-1.459V   578.9mA    480.2mA    724.6mA
-1.077V   211.8mA    226.1mA    211.3mA
-1.03V    168.9mA    195.3mA    156.5mA
-981.8mV  128.3mA    164.9mA    107.6mA
-934.1mV  91.11mA    135.2mA    69.06mA
-886.4mV  59.57mA    106.6mA    45.9mA
-838.6mV  36.67mA    79.82mA    35.26mA
-743.2mV  18.24mA    35.86mA    23.8mA
-647.7mV  11.02mA    13.07mA    14.69mA
-552.3mV  5.649mA    5.582mA    7.444mA
-313.6mV  104.8uA    243.3uA    121.9uA
2.98V     -2.208mA   -1.853mA   -2.682mA
[Pulldown]
-1.48V    -3.4mA     -2.6mA     -4mA
-1.145V   -6.1mA     -4.2mA     -7.9mA
-954.6mV  -10.9mA    -6.4mA     -15.27mA
-811.4mV  -14.22mA   -9.94mA    -15.22mA
-525mV    -12.36mA   -12.3mA    -13.03mA
906.8mV   21.31mA    20.61mA    22.95mA
1.289V    26.28mA    25.22mA    28.18mA
1.766V    28.25mA    26.77mA    30.06mA
2.052V    25.24mA    21.96mA    28.34mA
2.434V    16.91mA    5.5mA      21.96mA
2.673V    5.9mA      3.2mA      15.9mA
2.959V    3mA        2.3mA      5.2mA
[Pullup]
-1.459V   1.7mA      1.757mA    1.929mA
-1.173V   4.7mA      3.029mA    8.571mA
-838.6mV  18.38mA    10.71mA    17.71mA
-695.5mV  18.8mA     17.13mA    18.09mA
-552.3mV  17.7mA     17.94mA    17.46mA
640.9mV   -16.59mA   -16.97mA   -17.62mA
1.834V    -23.79mA   -23.77mA   -25.99mA
2.12V     -21.68mA   -20.55mA   -24.11mA
2.359V    -20.05mA   -12.01mA   -23.08mA
2.502V    -13.6mA    -9.571mA   -22.45mA
2.741V    -8.5mA     -7.886mA   -11.5mA
2.98V     -7.1mA     -7.143mA   -8.029mA
[Ramp]
R_load=50.000Ohm
dV/dt_r   487.980mV/114.500ps  469.859mV/131.500ps  522.690mV/102.000ps
dV/dt_f   487.980mV/111.500ps  469.859mV/134.000ps  522.690mV/97.000ps
[Rising waveform]
R_fixture=50.000Ohm
V_fixture=1.500
V_fixture_min=1.425
V_fixture_max=1.575
0s        635.7mV    617.6mV    637.1mV
39ps      645.9mV    615.3mV    664.2mV
69ps      711.8mV    614.7mV    824.1mV
131ps     1.101V     630.3mV    1.289V
161ps     1.252V     667.6mV    1.395V
199ps     1.357V     793.1mV    1.462V
276ps     1.432V     1.171V     1.509V
345ps     1.451V     1.324V     1.519V
460ps     1.459V     1.382V     1.523V
749ps     1.461V     1.395V     1.524V
[Rising waveform]
R_fixture=50.000Ohm
V_fixture=0
0s        -4.119mV   800.7uV    -3.958mV
39ps      -10.37mV   -739.5uV   1.602mV
77ps      36.94mV    -4.717mV   127.5mV
169ps     403.4mV    5.026mV    572.2mV
215ps     558.4mV    93.39mV    696.3mV
268ps     672.1mV    271.9mV    777.3mV
345ps     752mV      528.8mV    828.5mV
437ps     788.4mV    694.1mV    849.3mV
552ps     802.3mV    764.4mV    857mV
749ps     807.4mV    788.3mV    860.4mV
[Falling waveform]
R_fixture=50.000Ohm
V_fixture=1.500
V_fixture_min=1.425
V_fixture_max=1.575
0s        1.466V     1.394V     1.529V
46ps      1.471V     1.397V     1.516V
85ps      1.407V     1.405V     1.37V
169ps     1.053V     1.388V     929.2mV
207ps     909.2mV    1.316V     807.6mV
253ps     791.4mV    1.17V      726.6mV
345ps     689.7mV    872.5mV    666.7mV
421ps     662.3mV    734.5mV    652.7mV
544ps     648.9mV    655.8mV    645.5mV
749ps     644.1mV    629mV      643.2mV
[Falling waveform]
R_fixture=50.000Ohm
V_fixture=0
0s        820mV      797.4mV    868.8mV
23ps      810mV      801mV      852.3mV
46ps      762.9mV    804.8mV    764.4mV
115ps     365.5mV    781.4mV    260.9mV
146ps     213.2mV    714.4mV    141.8mV
192ps     93.79mV    517.6mV    59.92mV
253ps     34.41mV    225.5mV    20.85mV
337ps     10.17mV    60.93mV    5.215mV
452ps     2.128mV    13.1mV     842.7uV
749ps     83.49uV    498.7uV    -10.96uV
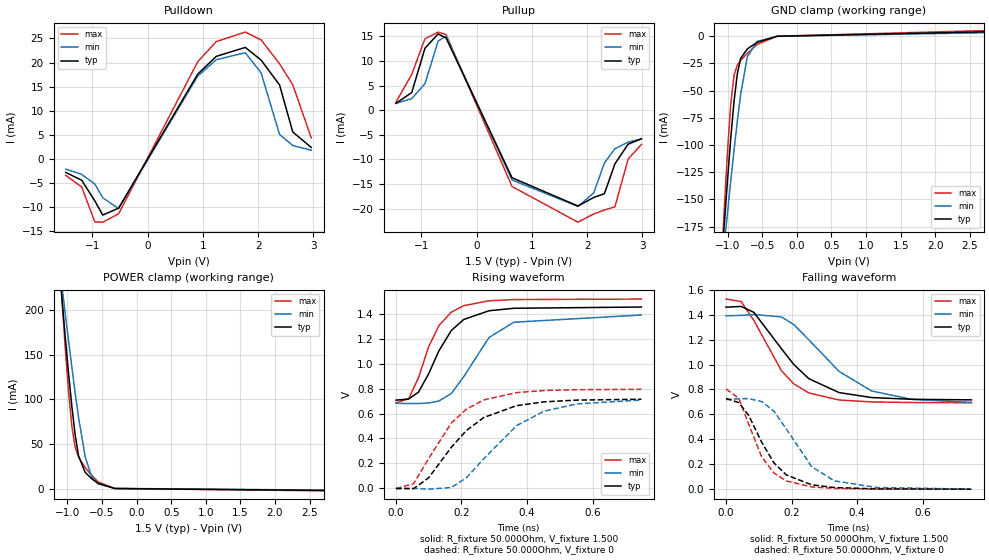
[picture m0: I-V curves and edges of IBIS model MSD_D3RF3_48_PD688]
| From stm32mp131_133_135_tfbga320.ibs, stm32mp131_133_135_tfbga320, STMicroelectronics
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[Model] MSD_D3RF3_48_PD688
Model_type   I/O
C_comp 2.444pF   2.361pF   2.568pF
Vinh = 925.000mV
Vinl = 575.000mV
Vmeas = 750.000mV
Vref = 750.000mV
[Model Spec]
Vinh   925.000mV   888.000mV   963.000mV
Vinl   575.000mV   538.000mV   613.000mV
Vmeas   750.000mV   713.000mV   788.000mV
Vref   750.000mV   713.000mV   788.000mV
[Temperature Range]   25.000   125.000   -40.000
[Voltage Range]   1.500V   1.425V   1.575V
[GND Clamp Reference]   0.00V   0.00V   0.00V
[Pulldown Reference]   0.00V   0.00V   0.00V
[POWER Clamp Reference]   1.500V   1.425V   1.575V
[Pullup Reference]   1.500V   1.425V   1.575V
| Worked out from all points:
|   slope of the pulldown table from 0 to 0.225 V, typ, clamps not added: 44.1 ohm
|   slope of the pullup table from 0 to 0.225 V, typ, clamps not added: 37.5 ohm
|   GND clamp passes 1 mA (typ) near -0.40 V on its own axis
|   POWER clamp passes 1 mA (typ) near -0.41 V on its own axis
|   rising waveform, R_fixture 50.000Ohm, V_fixture 1.500: 20-80 % time 94.3ps typ, 110ps min, 80ps max; typ from 0.708 V to 1.46 V
|   rising waveform, R_fixture 50.000Ohm, V_fixture 0: 20-80 % time 153ps typ, 170ps min, 131ps max; typ from -0.003 V to 0.715 V
|   falling waveform, R_fixture 50.000Ohm, V_fixture 1.500: 20-80 % time 144ps typ, 171ps min, 116ps max; typ from 1.46 V to 0.716 V
|   falling waveform, R_fixture 50.000Ohm, V_fixture 0: 20-80 % time 97.9ps typ, 116ps min, 81.4ps max; typ from 0.727 V to 0 V
[GND Clamp]
-1.48V    -595.2mA   -480.8mA   -764.9mA
-1.098V   -219.1mA   -224mA     -221.3mA
-1.05V    -174.8mA   -193mA     -160.6mA
-1.002V   -132.6mA   -162.5mA   -106.1mA
-954.6mV  -93.48mA   -132.9mA   -62.36mA
-906.8mV  -59.6mA    -104.4mA   -35.9mA
-859.1mV  -34.32mA   -77.6mA    -26.31mA
-811.4mV  -20.37mA   -53.46mA   -22.22mA
-715.9mV  -11.76mA   -19.03mA   -15.86mA
-572.7mV  -5.614mA   -4.804mA   -7.58mA
-286.4mV  -74.25uA   -124.6uA   -59.77uA
2.959V    4.342mA    3.42mA     5.581mA
[Power Clamp]
-1.459V   578.9mA    480.2mA    724.6mA
-1.077V   211.8mA    226.1mA    211.3mA
-1.03V    168.9mA    195.3mA    156.5mA
-981.8mV  128.3mA    164.9mA    107.6mA
-934.1mV  91.11mA    135.2mA    69.06mA
-886.4mV  59.57mA    106.6mA    45.9mA
-838.6mV  36.67mA    79.82mA    35.26mA
-743.2mV  18.24mA    35.86mA    23.8mA
-647.7mV  11.02mA    13.07mA    14.69mA
-552.3mV  5.649mA    5.582mA    7.444mA
-313.6mV  104.8uA    243.3uA    121.9uA
2.98V     -2.208mA   -1.853mA   -2.682mA
[Pulldown]
-1.48V    -2.8mA     -2.1mA     -3.4mA
-1.193V   -4.4mA     -3.2mA     -5.8mA
-954.6mV  -8.7mA     -5.2mA     -13.05mA
-811.4mV  -11.64mA   -8.06mA    -13.11mA
-525mV    -10.19mA   -10.28mA   -11.37mA
906.8mV   17.61mA    17.2mA     20.18mA
1.241V    21.28mA    20.59mA    24.35mA
1.766V    23.14mA    22.04mA    26.32mA
2.052V    20.52mA    17.86mA    24.7mA
2.386V    15.36mA    5.1mA      19.75mA
2.625V    5.6mA      2.8mA      15.4mA
2.959V    2.4mA      1.8mA      4.4mA
[Pullup]
-1.459V   1.4mA      1.4mA      1.629mA
-1.173V   3.6mA      2.371mA    7.3mA
-934.1mV  12.61mA    5.386mA    14.52mA
-695.5mV  15.52mA    14.06mA    15.89mA
-552.3mV  14.69mA    15.08mA    15.38mA
640.9mV   -13.72mA   -14.18mA   -15.51mA
1.834V    -19.47mA   -19.55mA   -22.76mA
2.12V     -17.72mA   -16.78mA   -21.08mA
2.311V    -16.98mA   -10.74mA   -20.29mA
2.502V    -10.9mA    -7.829mA   -19.63mA
2.741V    -6.9mA     -6.486mA   -9.928mA
2.98V     -5.8mA     -5.843mA   -6.971mA
[Ramp]
R_load=50.000Ohm
dV/dt_r   437.490mV/124.500ps  425.549mV/143.000ps  487.050mV/106.000ps
dV/dt_f   437.490mV/122.000ps  425.549mV/146.000ps  487.050mV/99.000ps
[Rising waveform]
R_fixture=50.000Ohm
V_fixture=1.500
V_fixture_min=1.425
V_fixture_max=1.575
0s        707.7mV    682.4mV    687mV
39ps      717mV      680.3mV    719.1mV
69ps      772.4mV    680.5mV    889.2mV
100ps     919.9mV    685.2mV    1.137V
131ps     1.103V     700.2mV    1.306V
169ps     1.267V     760.6mV    1.415V
207ps     1.356V     896.4mV    1.467V
284ps     1.426V     1.211V     1.506V
360ps     1.446V     1.334V     1.516V
749ps     1.456V     1.392V     1.52V
[Rising waveform]
R_fixture=50.000Ohm
V_fixture=0
0s        -3.055mV   655.6uV    -3.592mV
54ps      -4.047mV   -1.966mV   37.1mV
100ps     83.83mV    -7.82mV    238.8mV
169ps     328.6mV    5.591mV    523.8mV
215ps     463.7mV    83.51mV    635.2mV
268ps     567.9mV    236.2mV    709.3mV
368ps     663.3mV    502.1mV    768.2mV
452ps     693.9mV    618.9mV    785.1mV
552ps     708mV      677.4mV    791.6mV
749ps     714.9mV    708.1mV    794.8mV
[Falling waveform]
R_fixture=50.000Ohm
V_fixture=1.500
V_fixture_min=1.425
V_fixture_max=1.575
0s        1.46V      1.391V     1.525V
46ps      1.466V     1.394V     1.505V
85ps      1.418V     1.401V     1.353V
169ps     1.127V     1.382V     950mV
207ps     999.2mV    1.32V      843.8mV
253ps     885.7mV    1.197V     771.7mV
345ps     774.7mV    944.5mV    715.3mV
444ps     734.9mV    787.9mV    700mV
567ps     720.8mV    720.5mV    695.1mV
749ps     716.4mV    696mV      693.1mV
[Falling waveform]
R_fixture=50.000Ohm
V_fixture=0
0s        727.2mV    719mV      803.6mV
39ps      694.3mV    725.2mV    728.9mV
69ps      592.2mV    726.6mV    522.7mV
108ps     380mV      704.1mV    263.1mV
146ps     211.3mV    625.7mV    129.7mV
184ps     114.2mV    482.5mV    66.07mV
261ps     35.08mV    181.1mV    18.36mV
330ps     13.24mV    67.21mV    6.093mV
460ps     2.342mV    12.94mV    962.2uV
749ps     32.59uV    556uV      -37.35uV
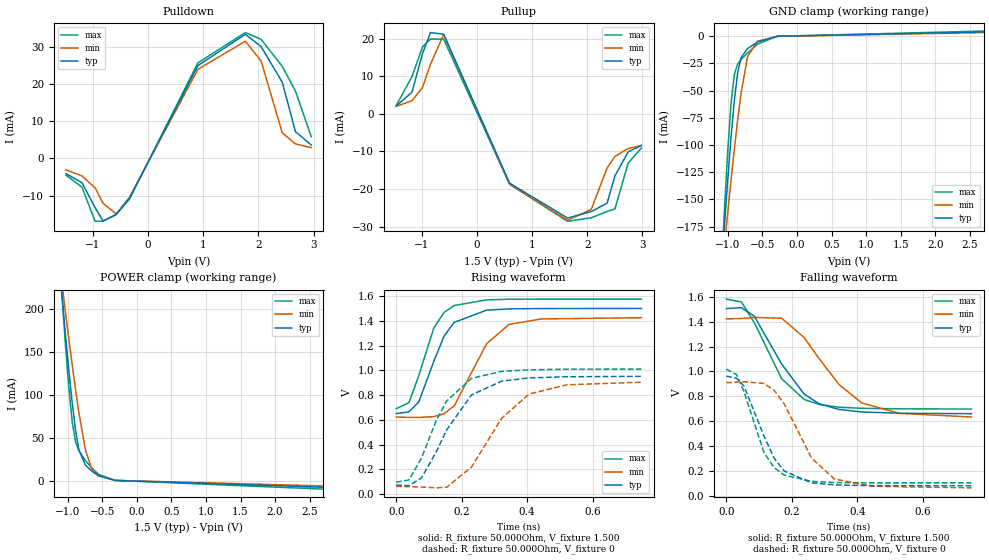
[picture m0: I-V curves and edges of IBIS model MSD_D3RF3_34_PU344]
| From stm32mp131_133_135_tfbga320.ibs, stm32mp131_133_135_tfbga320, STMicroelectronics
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[Model] MSD_D3RF3_34_PU344
Model_type   I/O
C_comp 2.329pF   2.247pF   2.450pF
Vinh = 925.000mV
Vinl = 575.000mV
Vmeas = 750.000mV
Vref = 750.000mV
[Model Spec]
Vinh   925.000mV   888.000mV   963.000mV
Vinl   575.000mV   538.000mV   613.000mV
Vmeas   750.000mV   713.000mV   788.000mV
Vref   750.000mV   713.000mV   788.000mV
[Temperature Range]   25.000   125.000   -40.000
[Voltage Range]   1.500V   1.425V   1.575V
[GND Clamp Reference]   0.00V   0.00V   0.00V
[Pulldown Reference]   0.00V   0.00V   0.00V
[POWER Clamp Reference]   1.500V   1.425V   1.575V
[Pullup Reference]   1.500V   1.425V   1.575V
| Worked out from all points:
|   slope of the pulldown table from 0 to 0.225 V, typ, clamps not added: 31.5 ohm
|   slope of the pullup table from 0 to 0.225 V, typ, clamps not added: 26.9 ohm
|   GND clamp passes 1 mA (typ) near -0.40 V on its own axis
|   POWER clamp passes 1 mA (typ) near -0.41 V on its own axis
|   rising waveform, R_fixture 50.000Ohm, V_fixture 1.500: 20-80 % time 76.7ps typ, 94.7ps min, 67.4ps max; typ from 0.65 V to 1.5 V
|   rising waveform, R_fixture 50.000Ohm, V_fixture 0: 20-80 % time 114ps typ, 132ps min, 100ps max; typ from 0.073 V to 0.951 V
|   falling waveform, R_fixture 50.000Ohm, V_fixture 1.500: 20-80 % time 120ps typ, 147ps min, 106ps max; typ from 1.51 V to 0.66 V
|   falling waveform, R_fixture 50.000Ohm, V_fixture 0: 20-80 % time 85.3ps typ, 104ps min, 74ps max; typ from 0.962 V to 0.079 V
[GND Clamp]
-1.48V    -593.8mA   -479.5mA   -763mA
-1.098V   -218.2mA   -223.3mA   -220.2mA
-1.05V    -174mA     -192.3mA   -159.6mA
-1.002V   -131.9mA   -161.9mA   -105.2mA
-954.6mV  -92.79mA   -132.2mA   -61.49mA
-906.8mV  -58.98mA   -103.9mA   -35.12mA
-859.1mV  -33.77mA   -77.12mA   -25.6mA
-811.4mV  -19.87mA   -53.03mA   -21.59mA
-715.9mV  -11.38mA   -18.7mA    -15.38mA
-572.7mV  -5.4mA     -4.611mA   -7.303mA
-286.4mV  -62.82uA   -108.6uA   -50.82uA
2.959V    4.272mA    3.643mA    5.154mA
[Power Clamp]
-1.459V   577.6mA    479.2mA    722.9mA
-1.077V   211mA      225.5mA    210.3mA
-1.03V    168.2mA    194.7mA    155.6mA
-981.8mV  127.5mA    164.3mA    106.7mA
-934.1mV  90.5mA     134.7mA    68.26mA
-886.4mV  59.02mA    106.2mA    45.17mA
-838.6mV  36.17mA    79.41mA    34.61mA
-743.2mV  17.86mA    35.55mA    23.3mA
-647.7mV  10.74mA    12.84mA    14.33mA
-552.3mV  5.478mA    5.433mA    7.218mA
-313.6mV  101.8uA    235.2uA    114.2uA
2.98V     -8.607mA   -6.939mA   -10.98mA
[Pulldown]
-1.48V    -4.1mA     -3.1mA     -4.5mA
-1.193V   -6.5mA     -4.7mA     -7.7mA
-954.6mV  -13.21mA   -7.9mA     -16.88mA
-811.4mV  -16.78mA   -12.04mA   -16.85mA
-572.7mV  -15.06mA   -14.91mA   -15.04mA
-334.1mV  -10.72mA   -10.49mA   -10.95mA
906.8mV   24.92mA    23.93mA    25.67mA
1.766V    33.34mA    31.48mA    33.8mA
2.052V    30.02mA    26.14mA    31.97mA
2.434V    20.47mA    6.9mA      24.73mA
2.673V    7.2mA      3.9mA      18.1mA
2.959V    3.6mA      2.9mA      5.8mA
[Pullup]
-1.459V   2.1mA      2.014mA    2.229mA
-1.173V   5.8mA      3.529mA    9.943mA
-981.8mV  16.1mA     7.043mA    17.88mA
-838.6mV  21.66mA    13.24mA    19.92mA
-600mV    21.23mA    21.13mA    19.93mA
593.2mV   -18.41mA   -18.64mA   -18.71mA
1.643V    -27.73mA   -28.33mA   -28.59mA
2.073V    -25.99mA   -25.4mA    -27.65mA
2.359V    -23.78mA   -14.44mA   -25.97mA
2.502V    -16.5mA    -11.3mA    -25.27mA
2.741V    -10.1mA    -9.229mA   -13.11mA
2.98V     -8.4mA     -8.4mA     -9.071mA
[Ramp]
R_load=50.000Ohm
dV/dt_r   514.194mV/96.000ps  492.543mV/114.000ps  535.830mV/84.500ps
dV/dt_f   514.194mV/103.500ps  492.543mV/127.500ps  535.830mV/90.000ps
[Rising waveform]
R_fixture=50.000Ohm
V_fixture=1.500
V_fixture_min=1.425
V_fixture_max=1.575
0s        650.5mV    622.3mV    690mV
39ps      664.4mV    620mV      739.1mV
69ps      744.9mV    619.5mV    957.9mV
115ps     1.074V     626.1mV    1.343V
146ps     1.275V     648.9mV    1.467V
177ps     1.387V     712.6mV    1.523V
276ps     1.486V     1.214V     1.569V
345ps     1.496V     1.371V     1.574V
444ps     1.499V     1.415V     1.575V
749ps     1.5V       1.425V     1.575V
[Rising waveform]
R_fixture=50.000Ohm
V_fixture=0
0s        73.38mV    62.42mV    96.55mV
39ps      68.5mV     60.79mV    114.8mV
77ps      130.2mV    56.98mV    290.6mV
123ps     344.4mV    50.65mV    597.6mV
154ps     518.9mV    55.42mV    751.7mV
230ps     801.2mV    218.7mV    935.2mV
322ps     912.7mV    612.1mV    991.7mV
406ps     938.7mV    808.4mV    1.004V
521ps     947.9mV    883mV      1.009V
749ps     951.2mV    904.1mV    1.01V
[Falling waveform]
R_fixture=50.000Ohm
V_fixture=1.500
V_fixture_min=1.425
V_fixture_max=1.575
0s        1.506V     1.423V     1.582V
46ps      1.513V     1.426V     1.559V
85ps      1.446V     1.435V     1.395V
169ps     1.059V     1.428V     940.9mV
238ps     816.5mV    1.272V     774mV
284ps     739.4mV    1.101V     733.6mV
345ps     693.4mV    892.1mV    711.3mV
414ps     673.2mV    746.1mV    703mV
529ps     663.4mV    662mV      698.9mV
749ps     659.5mV    633mV      697mV
[Falling waveform]
R_fixture=50.000Ohm
V_fixture=0
0s        962mV      908.9mV    1.018V
31ps      945.6mV    913.3mV    974.9mV
54ps      882mV      917mV      836.7mV
115ps     479.5mV    903.1mV    347.1mV
146ps     301.6mV    847.9mV    224.8mV
177ps     198.5mV    737.9mV    164.6mV
261ps     102.5mV    300.4mV    114.3mV
330ps     86.62mV    134mV      105.5mV
444ps     80.11mV    75.21mV    102.6mV
749ps     78.66mV    62.45mV    102.1mV
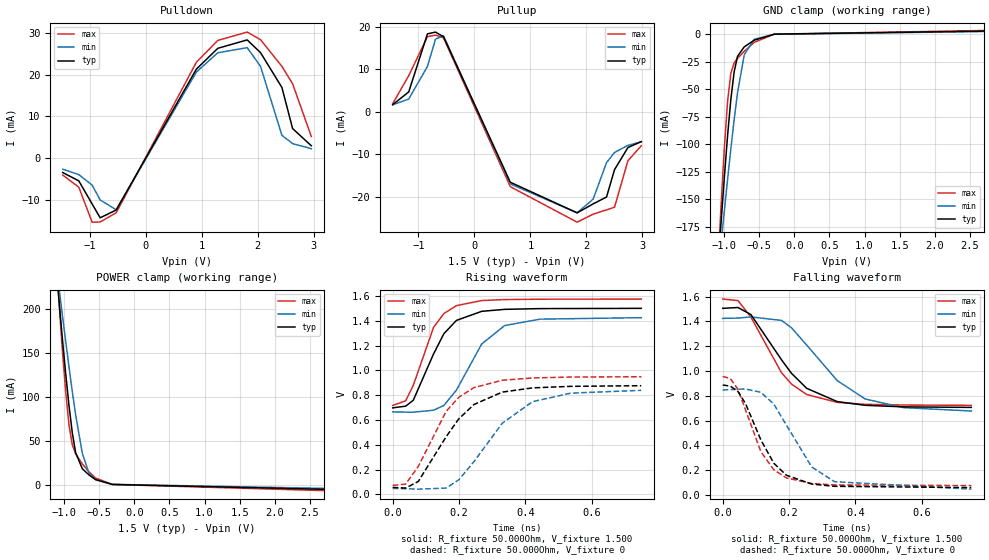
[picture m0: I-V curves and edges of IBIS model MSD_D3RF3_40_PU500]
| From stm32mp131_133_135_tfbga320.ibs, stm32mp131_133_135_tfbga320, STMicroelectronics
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[Model] MSD_D3RF3_40_PU500
Model_type   I/O
C_comp 2.404pF   2.322pF   2.527pF
Vinh = 925.000mV
Vinl = 575.000mV
Vmeas = 750.000mV
Vref = 750.000mV
[Model Spec]
Vinh   925.000mV   888.000mV   963.000mV
Vinl   575.000mV   538.000mV   613.000mV
Vmeas   750.000mV   713.000mV   788.000mV
Vref   750.000mV   713.000mV   788.000mV
[Temperature Range]   25.000   125.000   -40.000
[Voltage Range]   1.500V   1.425V   1.575V
[GND Clamp Reference]   0.00V   0.00V   0.00V
[Pulldown Reference]   0.00V   0.00V   0.00V
[POWER Clamp Reference]   1.500V   1.425V   1.575V
[Pullup Reference]   1.500V   1.425V   1.575V
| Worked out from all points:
|   slope of the pulldown table from 0 to 0.225 V, typ, clamps not added: 36.6 ohm
|   slope of the pullup table from 0 to 0.225 V, typ, clamps not added: 31.2 ohm
|   GND clamp passes 1 mA (typ) near -0.40 V on its own axis
|   POWER clamp passes 1 mA (typ) near -0.41 V on its own axis
|   rising waveform, R_fixture 50.000Ohm, V_fixture 1.500: 20-80 % time 83.8ps typ, 101ps min, 73.2ps max; typ from 0.697 V to 1.5 V
|   rising waveform, R_fixture 50.000Ohm, V_fixture 0: 20-80 % time 129ps typ, 147ps min, 114ps max; typ from 0.055 V to 0.876 V
|   falling waveform, R_fixture 50.000Ohm, V_fixture 1.500: 20-80 % time 133ps typ, 159ps min, 117ps max; typ from 1.5 V to 0.707 V
|   falling waveform, R_fixture 50.000Ohm, V_fixture 0: 20-80 % time 92.4ps typ, 110ps min, 80.7ps max; typ from 0.887 V to 0.06 V
[GND Clamp]
-1.48V    -594.7mA   -480.3mA   -764.2mA
-1.098V   -218.6mA   -223.8mA   -220.9mA
-1.05V    -174.5mA   -192.7mA   -160.2mA
-1.002V   -132.3mA   -162.3mA   -105.8mA
-954.6mV  -93.21mA   -132.7mA   -62.02mA
-906.8mV  -59.35mA   -104.2mA   -35.59mA
-859.1mV  -34.1mA    -77.4mA    -26.03mA
-811.4mV  -20.17mA   -53.28mA   -21.97mA
-715.9mV  -11.61mA   -18.89mA   -15.68mA
-572.7mV  -5.526mA   -4.722mA   -7.477mA
-286.4mV  -67.61uA   -115uA     -54.41uA
2.959V    2.938mA    2.505mA    3.545mA
[Power Clamp]
-1.459V   578.5mA    479.9mA    724mA
-1.077V   211.5mA    225.9mA    210.9mA
-1.03V    168.6mA    195.1mA    156.2mA
-981.8mV  128mA      164.7mA    107.3mA
-934.1mV  90.9mA     135mA      68.78mA
-886.4mV  59.39mA    106.5mA    45.64mA
-838.6mV  36.5mA     79.7mA     35.03mA
-743.2mV  18.11mA    35.77mA    23.62mA
-647.7mV  10.93mA    13mA       14.56mA
-552.3mV  5.593mA    5.539mA    7.365mA
-313.6mV  107.3uA    245.7uA    121uA
2.98V     -5.92mA    -4.774mA   -7.555mA
[Pulldown]
-1.48V    -3.4mA     -2.6mA     -4mA
-1.193V   -5.4mA     -3.9mA     -6.9mA
-954.6mV  -10.91mA   -6.4mA     -15.27mA
-811.4mV  -14.22mA   -9.95mA    -15.22mA
-525mV    -12.36mA   -12.3mA    -13.02mA
906.8mV   21.31mA    20.61mA    22.96mA
1.289V    26.28mA    25.22mA    28.17mA
1.814V    28.29mA    26.44mA    30.16mA
2.052V    25.25mA    21.96mA    28.34mA
2.434V    16.92mA    5.5mA      21.96mA
2.625V    7.1mA      3.5mA      17.8mA
2.959V    3mA        2.3mA      5.2mA
[Pullup]
-1.459V   1.7mA      1.657mA    1.929mA
-1.173V   4.7mA      3.029mA    8.528mA
-838.6mV  18.38mA    10.71mA    17.71mA
-695.5mV  18.8mA     17.13mA    18.09mA
-552.3mV  17.7mA     17.94mA    17.46mA
640.9mV   -16.58mA   -16.97mA   -17.62mA
1.834V    -23.79mA   -23.78mA   -25.99mA
2.12V     -21.68mA   -20.55mA   -24.1mA
2.359V    -20.05mA   -11.96mA   -23.08mA
2.502V    -13.6mA    -9.557mA   -22.45mA
2.741V    -8.4mA     -7.886mA   -11.5mA
2.98V     -7mA       -7.043mA   -7.971mA
[Ramp]
R_load=50.000Ohm
dV/dt_r   483.489mV/106.500ps  464.877mV/125.500ps  517.296mV/94.500ps
dV/dt_f   483.489mV/114.000ps  464.877mV/136.000ps  517.296mV/99.500ps
[Rising waveform]
R_fixture=50.000Ohm
V_fixture=1.500
V_fixture_min=1.425
V_fixture_max=1.575
0s        697.4mV    665.1mV    716.6mV
39ps      711mV      662.8mV    754mV
62ps      758.8mV    662.6mV    879.4mV
123ps     1.132V     678.1mV    1.346V
154ps     1.295V     716.5mV    1.458V
192ps     1.403V     840.7mV    1.522V
268ps     1.476V     1.212V     1.563V
337ps     1.492V     1.361V     1.571V
444ps     1.498V     1.413V     1.574V
749ps     1.5V       1.425V     1.575V
[Rising waveform]
R_fixture=50.000Ohm
V_fixture=0
0s        55.37mV    47.22mV    71.63mV
39ps      50.49mV    45.45mV    82.39mV
77ps      103.4mV    41.4mV     224.5mV
161ps     464.5mV    50.51mV    669.3mV
199ps     608.4mV    116.5mV    782.7mV
245ps     724.6mV    264.4mV    860.9mV
330ps     824.4mV    573.1mV    920mV
421ps     858.5mV    746.9mV    938.5mV
536ps     870.9mV    816mV      945.9mV
749ps     876mV      838.8mV    948.2mV
[Falling waveform]
R_fixture=50.000Ohm
V_fixture=1.500
V_fixture_min=1.425
V_fixture_max=1.575
0s        1.505V     1.424V     1.58V
46ps      1.512V     1.427V     1.568V
85ps      1.455V     1.436V     1.434V
177ps     1.091V     1.408V     987.2mV
207ps     981.9mV    1.349V     894.7mV
253ps     860.3mV    1.209V     810.6mV
345ps     753.5mV    922.7mV    747mV
429ps     723.5mV    774.7mV    731.1mV
544ps     711mV      704.8mV    725.7mV
749ps     706.6mV    677.5mV    723.3mV
[Falling waveform]
R_fixture=50.000Ohm
V_fixture=0
0s        887.1mV    846.4mV    955.9mV
23ps      878.1mV    849.8mV    939.8mV
46ps      834.3mV    853.3mV    851.6mV
69ps      735.8mV    854.9mV    685.2mV
115ps     444mV      828.1mV    349.5mV
154ps     256.5mV    733.2mV    203.3mV
192ps     159.5mV    563.6mV    138.1mV
268ps     88.49mV    226.5mV    92.82mV
337ps     70.46mV    107.6mV    81.47mV
749ps     59.93mV    47.35mV    76.16mV
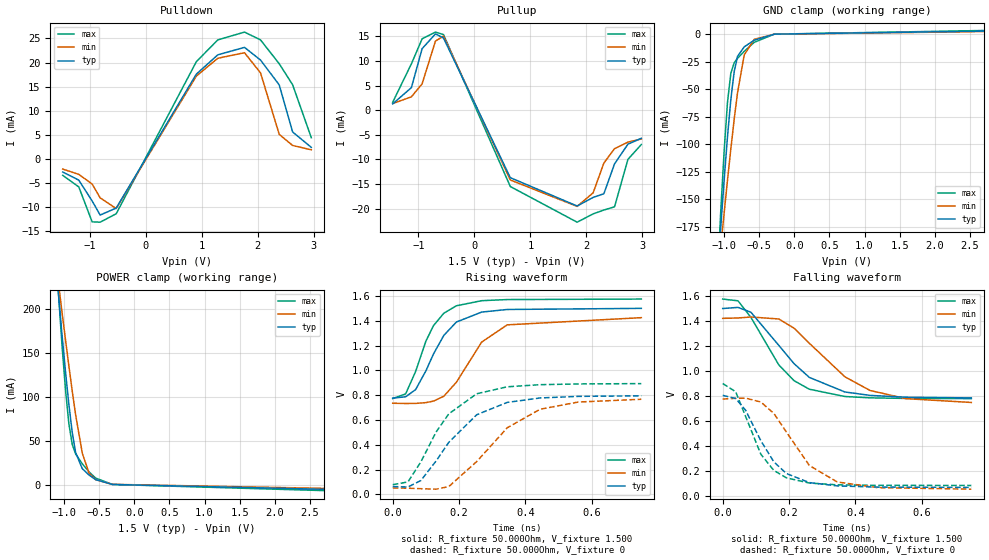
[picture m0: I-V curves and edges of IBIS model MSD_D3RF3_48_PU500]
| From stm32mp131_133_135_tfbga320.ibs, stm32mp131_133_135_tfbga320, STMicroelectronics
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[Model] MSD_D3RF3_48_PU500
Model_type   I/O
C_comp 2.404pF   2.322pF   2.527pF
Vinh = 925.000mV
Vinl = 575.000mV
Vmeas = 750.000mV
Vref = 750.000mV
[Model Spec]
Vinh   925.000mV   888.000mV   963.000mV
Vinl   575.000mV   538.000mV   613.000mV
Vmeas   750.000mV   713.000mV   788.000mV
Vref   750.000mV   713.000mV   788.000mV
[Temperature Range]   25.000   125.000   -40.000
[Voltage Range]   1.500V   1.425V   1.575V
[GND Clamp Reference]   0.00V   0.00V   0.00V
[Pulldown Reference]   0.00V   0.00V   0.00V
[POWER Clamp Reference]   1.500V   1.425V   1.575V
[Pullup Reference]   1.500V   1.425V   1.575V
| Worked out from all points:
|   slope of the pulldown table from 0 to 0.225 V, typ, clamps not added: 44.1 ohm
|   slope of the pullup table from 0 to 0.225 V, typ, clamps not added: 37.5 ohm
|   GND clamp passes 1 mA (typ) near -0.40 V on its own axis
|   POWER clamp passes 1 mA (typ) near -0.41 V on its own axis
|   rising waveform, R_fixture 50.000Ohm, V_fixture 1.500: 20-80 % time 90.2ps typ, 107ps min, 75.7ps max; typ from 0.776 V to 1.5 V
|   rising waveform, R_fixture 50.000Ohm, V_fixture 0: 20-80 % time 141ps typ, 160ps min, 119ps max; typ from 0.063 V to 0.795 V
|   falling waveform, R_fixture 50.000Ohm, V_fixture 1.500: 20-80 % time 148ps typ, 174ps min, 120ps max; typ from 1.5 V to 0.785 V
|   falling waveform, R_fixture 50.000Ohm, V_fixture 0: 20-80 % time 99.6ps typ, 118ps min, 82.2ps max; typ from 0.806 V to 0.066 V
[GND Clamp]
-1.48V    -594.7mA   -480.3mA   -764.2mA
-1.098V   -218.6mA   -223.8mA   -220.9mA
-1.05V    -174.5mA   -192.7mA   -160.2mA
-1.002V   -132.3mA   -162.3mA   -105.8mA
-954.6mV  -93.21mA   -132.7mA   -62.02mA
-906.8mV  -59.35mA   -104.2mA   -35.59mA
-859.1mV  -34.1mA    -77.4mA    -26.03mA
-811.4mV  -20.17mA   -53.28mA   -21.97mA
-715.9mV  -11.61mA   -18.89mA   -15.68mA
-572.7mV  -5.526mA   -4.722mA   -7.477mA
-286.4mV  -67.61uA   -115uA     -54.41uA
2.959V    2.938mA    2.505mA    3.545mA
[Power Clamp]
-1.459V   578.5mA    479.9mA    724mA
-1.077V   211.5mA    225.9mA    210.9mA
-1.03V    168.6mA    195.1mA    156.2mA
-981.8mV  128mA      164.7mA    107.3mA
-934.1mV  90.9mA     135mA      68.78mA
-886.4mV  59.39mA    106.5mA    45.64mA
-838.6mV  36.5mA     79.7mA     35.03mA
-743.2mV  18.11mA    35.77mA    23.62mA
-647.7mV  10.93mA    13mA       14.56mA
-552.3mV  5.593mA    5.539mA    7.365mA
-313.6mV  107.3uA    245.7uA    121uA
2.98V     -5.92mA    -4.774mA   -7.555mA
[Pulldown]
-1.48V    -2.7mA     -2.1mA     -3.4mA
-1.193V   -4.4mA     -3.2mA     -5.8mA
-954.6mV  -8.71mA    -5.2mA     -13.05mA
-811.4mV  -11.64mA   -8.07mA    -13.12mA
-525mV    -10.19mA   -10.29mA   -11.37mA
906.8mV   17.61mA    17.2mA     20.19mA
1.289V    21.6mA     20.89mA    24.7mA
1.766V    23.15mA    22.04mA    26.32mA
2.052V    20.52mA    17.86mA    24.7mA
2.386V    15.36mA    5.1mA      19.75mA
2.625V    5.6mA      2.8mA      15.4mA
2.959V    2.4mA      1.9mA      4.4mA
[Pullup]
-1.459V   1.3mA      1.357mA    1.629mA
-1.125V   4.6mA      2.729mA    9.443mA
-934.1mV  12.52mA    5.372mA    14.52mA
-695.5mV  15.52mA    14.06mA    15.89mA
-552.3mV  14.69mA    15.08mA    15.38mA
640.9mV   -13.71mA   -14.18mA   -15.51mA
1.834V    -19.47mA   -19.55mA   -22.76mA
2.12V     -17.72mA   -16.78mA   -21.07mA
2.311V    -16.98mA   -10.74mA   -20.29mA
2.502V    -10.9mA    -7.814mA   -19.63mA
2.741V    -6.9mA     -6.486mA   -9.986mA
2.98V     -5.7mA     -5.843mA   -6.971mA
[Ramp]
R_load=50.000Ohm
dV/dt_r   433.971mV/116.500ps  421.146mV/135.000ps  482.421mV/98.000ps
dV/dt_f   433.971mV/124.500ps  421.116mV/148.000ps  482.421mV/102.000ps
[Rising waveform]
R_fixture=50.000Ohm
V_fixture=1.500
V_fixture_min=1.425
V_fixture_max=1.575
0s        775.9mV    734.8mV    772.5mV
39ps      786.8mV    732.8mV    810.3mV
69ps      845mV      733.4mV    990.8mV
100ps     996mV      739.8mV    1.236V
123ps     1.133V     752.1mV    1.361V
154ps     1.282V     791.2mV    1.461V
192ps     1.39V      904.8mV    1.521V
268ps     1.47V      1.228V     1.562V
345ps     1.491V     1.367V     1.571V
749ps     1.5V       1.425V     1.575V
[Rising waveform]
R_fixture=50.000Ohm
V_fixture=0
0s        63mV       51.68mV    77.99mV
46ps      59.11mV    49.57mV    100.1mV
85ps      111.9mV    45.52mV    262.4mV
131ps     270.1mV    41.76mV    504.1mV
169ps     419.9mV    62.7mV     649.1mV
253ps     642mV      264mV      811.2mV
345ps     741.5mV    536.8mV    867.4mV
444ps     777.4mV    686.3mV    884.5mV
559ps     790.1mV    744.5mV    890.5mV
749ps     794.7mV    766.9mV    893.1mV
[Falling waveform]
R_fixture=50.000Ohm
V_fixture=1.500
V_fixture_min=1.425
V_fixture_max=1.575
0s        1.503V     1.424V     1.579V
46ps      1.512V     1.427V     1.565V
85ps      1.473V     1.435V     1.432V
169ps     1.207V     1.419V     1.05V
215ps     1.06V      1.345V     923.4mV
261ps     949.6mV    1.224V     854.8mV
368ps     832.8mV    954.8mV    796.3mV
444ps     805.2mV    844.6mV    785.5mV
552ps     790.6mV    779.1mV    781mV
749ps     785mV      748.5mV    779.4mV
[Falling waveform]
R_fixture=50.000Ohm
V_fixture=0
0s        805.8mV    775.9mV    900.6mV
39ps      780.3mV    781.6mV    834.7mV
69ps      686mV      783mV      636.2mV
115ps     440.4mV    752.1mV    332.2mV
154ps     271.7mV    660.6mV    202.5mV
192ps     177.6mV    510.1mV    143mV
261ps     104.8mV    242.4mV    101.1mV
345ps     78.13mV    109.7mV    86.69mV
467ps     68.49mV    64.27mV    82.56mV
749ps     66.24mV    52.01mV    81.78mV
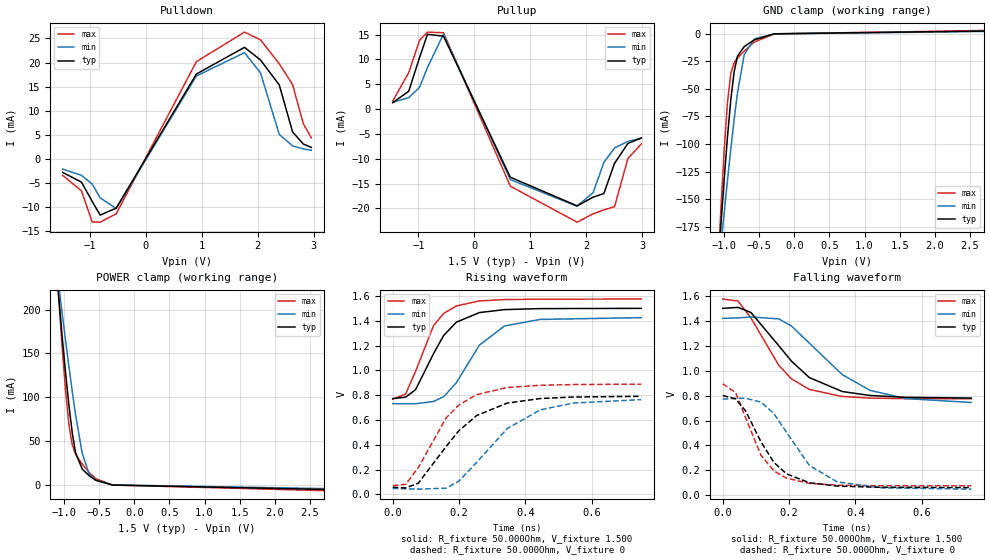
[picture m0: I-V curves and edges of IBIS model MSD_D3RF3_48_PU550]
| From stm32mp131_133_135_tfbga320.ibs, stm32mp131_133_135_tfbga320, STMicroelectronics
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[Model] MSD_D3RF3_48_PU550
Model_type   I/O
C_comp 2.417pF   2.334pF   2.540pF
Vinh = 925.000mV
Vinl = 575.000mV
Vmeas = 750.000mV
Vref = 750.000mV
[Model Spec]
Vinh   925.000mV   888.000mV   963.000mV
Vinl   575.000mV   538.000mV   613.000mV
Vmeas   750.000mV   713.000mV   788.000mV
Vref   750.000mV   713.000mV   788.000mV
[Temperature Range]   25.000   125.000   -40.000
[Voltage Range]   1.500V   1.425V   1.575V
[GND Clamp Reference]   0.00V   0.00V   0.00V
[Pulldown Reference]   0.00V   0.00V   0.00V
[POWER Clamp Reference]   1.500V   1.425V   1.575V
[Pullup Reference]   1.500V   1.425V   1.575V
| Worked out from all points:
|   slope of the pulldown table from 0 to 0.225 V, typ, clamps not added: 44.1 ohm
|   slope of the pullup table from 0 to 0.225 V, typ, clamps not added: 37.5 ohm
|   GND clamp passes 1 mA (typ) near -0.40 V on its own axis
|   POWER clamp passes 1 mA (typ) near -0.41 V on its own axis
|   rising waveform, R_fixture 50.000Ohm, V_fixture 1.500: 20-80 % time 91.1ps typ, 107ps min, 76.2ps max; typ from 0.772 V to 1.5 V
|   rising waveform, R_fixture 50.000Ohm, V_fixture 0: 20-80 % time 143ps typ, 161ps min, 121ps max; typ from 0.057 V to 0.791 V
|   falling waveform, R_fixture 50.000Ohm, V_fixture 1.500: 20-80 % time 148ps typ, 174ps min, 121ps max; typ from 1.5 V to 0.782 V
|   falling waveform, R_fixture 50.000Ohm, V_fixture 0: 20-80 % time 100ps typ, 118ps min, 82.6ps max; typ from 0.802 V to 0.06 V
[GND Clamp]
-1.48V    -594.8mA   -480.5mA   -764.4mA
-1.098V   -218.8mA   -223.8mA   -221mA
-1.05V    -174.6mA   -192.8mA   -160.3mA
-1.002V   -132.4mA   -162.4mA   -105.9mA
-954.6mV  -93.29mA   -132.7mA   -62.13mA
-906.8mV  -59.43mA   -104.2mA   -35.7mA
-859.1mV  -34.17mA   -77.46mA   -26.12mA
-811.4mV  -20.23mA   -53.34mA   -22.06mA
-715.9mV  -11.65mA   -18.94mA   -15.73mA
-572.7mV  -5.552mA   -4.746mA   -7.503mA
-286.4mV  -69.21uA   -117uA     -55.41uA
2.959V    2.671mA    2.278mA    3.222mA
[Power Clamp]
-1.459V   578.6mA    480mA      724.3mA
-1.077V   211.6mA    226mA      211.1mA
-1.03V    168.7mA    195.2mA    156.3mA
-981.8mV  128.1mA    164.8mA    107.4mA
-934.1mV  90.98mA    135.1mA    68.88mA
-886.4mV  59.46mA    106.6mA    45.73mA
-838.6mV  36.57mA    79.76mA    35.11mA
-743.2mV  18.16mA    35.82mA    23.68mA
-647.7mV  10.96mA    13.03mA    14.61mA
-552.3mV  5.616mA    5.561mA    7.395mA
-313.6mV  108.4uA    247.8uA    122.3uA
2.98V     -5.382mA   -4.337mA   -6.867mA
[Pulldown]
-1.48V    -2.8mA     -2.1mA     -3.4mA
-1.145V   -4.8mA     -3.4mA     -6.6mA
-954.6mV  -8.77mA    -5.2mA     -13.05mA
-811.4mV  -11.64mA   -8.06mA    -13.11mA
-525mV    -10.19mA   -10.28mA   -11.37mA
906.8mV   17.61mA    17.2mA     20.18mA
1.766V    23.15mA    22.04mA    26.31mA
2.052V    20.52mA    17.85mA    24.7mA
2.386V    15.36mA    5.1mA      19.75mA
2.625V    5.6mA      2.7mA      15.4mA
2.816V    3.1mA      2.1mA      7.3mA
2.959V    2.4mA      1.8mA      4.4mA
[Pullup]
-1.459V   1.3mA      1.357mA    1.629mA
-1.173V   3.6mA      2.314mA    7.343mA
-981.8mV  10.3mA     4.357mA    13.82mA
-838.6mV  15.06mA    8.384mA    15.51mA
-552.3mV  14.69mA    15.09mA    15.38mA
640.9mV   -13.71mA   -14.19mA   -15.51mA
1.834V    -19.47mA   -19.55mA   -22.76mA
2.12V     -17.72mA   -16.78mA   -21.07mA
2.311V    -16.99mA   -10.74mA   -20.29mA
2.502V    -10.9mA    -7.814mA   -19.63mA
2.741V    -6.9mA     -6.486mA   -9.928mA
2.98V     -5.8mA     -5.843mA   -7.014mA
[Ramp]
R_load=50.000Ohm
dV/dt_r   435.621mV/118.000ps  422.508mV/136.000ps  484.647mV/99.500ps
dV/dt_f   435.621mV/125.000ps  422.478mV/148.500ps  484.647mV/102.000ps
[Rising waveform]
R_fixture=50.000Ohm
V_fixture=1.500
V_fixture_min=1.425
V_fixture_max=1.575
0s        772.5mV    732.1mV    768mV
39ps      784.1mV    730.1mV    808.7mV
69ps      844.8mV    730.7mV    993.7mV
123ps     1.135V     749.3mV    1.361V
154ps     1.283V     788.1mV    1.46V
192ps     1.389V     901.5mV    1.52V
261ps     1.466V     1.203V     1.56V
337ps     1.49V      1.358V     1.571V
444ps     1.498V     1.411V     1.574V
749ps     1.5V       1.425V     1.575V
[Rising waveform]
R_fixture=50.000Ohm
V_fixture=0
0s        57.07mV    47.18mV    70.66mV
39ps      52.06mV    45.55mV    80.67mV
77ps      89.81mV    41.98mV    216.3mV
161ps     386mV      49.99mV    616.3mV
199ps     512.6mV    105.9mV    720.1mV
253ps     636.1mV    258mV      804.5mV
345ps     736.1mV    530.5mV    862mV
444ps     772.8mV    681.1mV    879.8mV
544ps     785.1mV    736.7mV    885.5mV
749ps     790.8mV    763.9mV    888.8mV
[Falling waveform]
R_fixture=50.000Ohm
V_fixture=1.500
V_fixture_min=1.425
V_fixture_max=1.575
0s        1.504V     1.424V     1.579V
46ps      1.512V     1.427V     1.563V
85ps      1.471V     1.435V     1.427V
169ps     1.203V     1.419V     1.045V
207ps     1.079V     1.362V     936.4mV
261ps     946.4mV    1.224V     851.1mV
360ps     834.3mV    970.7mV    794.2mV
444ps     802.1mV    843.3mV    781.2mV
552ps     787.3mV    777.2mV    776.6mV
749ps     781.5mV    745.9mV    774.9mV
[Falling waveform]
R_fixture=50.000Ohm
V_fixture=0
0s        802.1mV    773.2mV    896.4mV
39ps      774.3mV    779mV      825.3mV
69ps      677mV      780.3mV    623.2mV
115ps     430.5mV    749.3mV    322.6mV
154ps     263.9mV    657.4mV    194.7mV
192ps     171.2mV    506.5mV    136.1mV
261ps     99.19mV    238.7mV    94.26mV
345ps     72.49mV    105.9mV    79.68mV
475ps     62.49mV    58.8mV     75.37mV
749ps     60.42mV    47.48mV    74.58mV
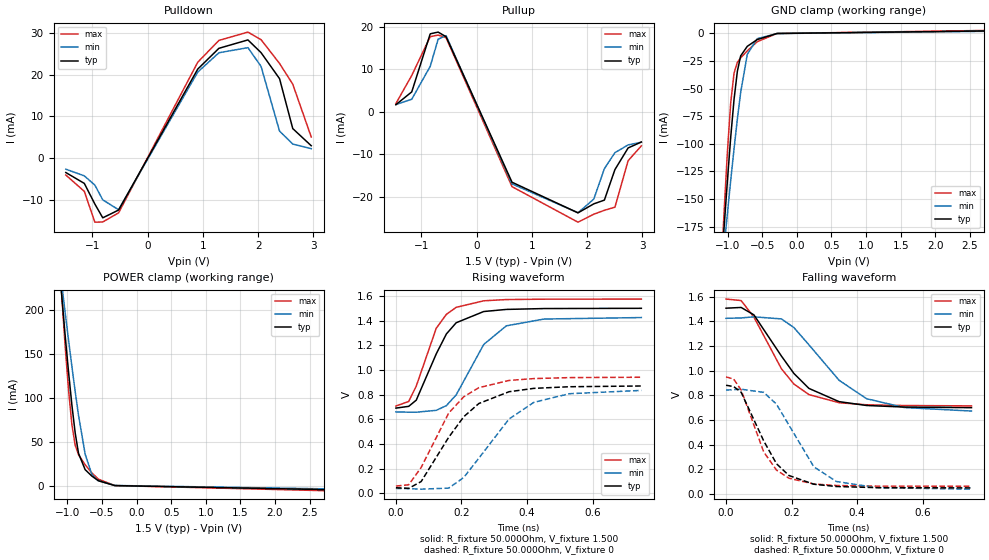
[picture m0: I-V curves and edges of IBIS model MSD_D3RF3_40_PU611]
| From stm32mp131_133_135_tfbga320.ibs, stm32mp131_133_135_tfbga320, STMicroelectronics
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[Model] MSD_D3RF3_40_PU611
Model_type   I/O
C_comp 2.434pF   2.351pF   2.557pF
Vinh = 925.000mV
Vinl = 575.000mV
Vmeas = 750.000mV
Vref = 750.000mV
[Model Spec]
Vinh   925.000mV   888.000mV   963.000mV
Vinl   575.000mV   538.000mV   613.000mV
Vmeas   750.000mV   713.000mV   788.000mV
Vref   750.000mV   713.000mV   788.000mV
[Temperature Range]   25.000   125.000   -40.000
[Voltage Range]   1.500V   1.425V   1.575V
[GND Clamp Reference]   0.00V   0.00V   0.00V
[Pulldown Reference]   0.00V   0.00V   0.00V
[POWER Clamp Reference]   1.500V   1.425V   1.575V
[Pullup Reference]   1.500V   1.425V   1.575V
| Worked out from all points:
|   slope of the pulldown table from 0 to 0.225 V, typ, clamps not added: 36.6 ohm
|   slope of the pullup table from 0 to 0.225 V, typ, clamps not added: 31.2 ohm
|   GND clamp passes 1 mA (typ) near -0.40 V on its own axis
|   POWER clamp passes 1 mA (typ) near -0.41 V on its own axis
|   rising waveform, R_fixture 50.000Ohm, V_fixture 1.500: 20-80 % time 84.8ps typ, 102ps min, 74.4ps max; typ from 0.691 V to 1.5 V
|   rising waveform, R_fixture 50.000Ohm, V_fixture 0: 20-80 % time 132ps typ, 149ps min, 117ps max; typ from 0.045 V to 0.87 V
|   falling waveform, R_fixture 50.000Ohm, V_fixture 1.500: 20-80 % time 134ps typ, 160ps min, 118ps max; typ from 1.51 V to 0.7 V
|   falling waveform, R_fixture 50.000Ohm, V_fixture 0: 20-80 % time 93ps typ, 110ps min, 81.3ps max; typ from 0.881 V to 0.049 V
[GND Clamp]
-1.48V    -595mA     -480.6mA   -764.6mA
-1.098V   -218.9mA   -223.9mA   -221.2mA
-1.05V    -174.8mA   -192.9mA   -160.5mA
-1.002V   -132.5mA   -162.4mA   -106.1mA
-954.6mV  -93.38mA   -132.8mA   -62.24mA
-906.8mV  -59.5mA    -104.2mA   -35.79mA
-859.1mV  -34.24mA   -77.51mA   -26.21mA
-811.4mV  -20.29mA   -53.38mA   -22.14mA
-715.9mV  -11.7mA    -18.98mA   -15.79mA
-572.7mV  -5.58mA    -4.768mA   -7.539mA
-286.4mV  -69.81uA   -117.8uA   -56.41uA
2.959V    2.404mA    2.05mA     2.9mA
[Power Clamp]
-1.459V   578.8mA    480.2mA    724.4mA
-1.077V   211.7mA    226.1mA    211.2mA
-1.03V    168.8mA    195.2mA    156.4mA
-981.8mV  128.2mA    164.8mA    107.5mA
-934.1mV  91.06mA    135.1mA    68.98mA
-886.4mV  59.53mA    106.6mA    45.83mA
-838.6mV  36.63mA    79.81mA    35.19mA
-743.2mV  18.22mA    35.86mA    23.75mA
-647.7mV  11mA       13.06mA    14.65mA
-552.3mV  5.639mA    5.582mA    7.423mA
-313.6mV  109.4uA    249.9uA    123.7uA
2.98V     -4.843mA   -3.907mA   -6.18mA
[Pulldown]
-1.48V    -3.4mA     -2.6mA     -4mA
-1.145V   -6mA       -4.2mA     -7.9mA
-954.6mV  -10.93mA   -6.4mA     -15.27mA
-811.4mV  -14.23mA   -9.94mA    -15.22mA
-525mV    -12.36mA   -12.3mA    -13.03mA
906.8mV   21.32mA    20.61mA    22.96mA
1.289V    26.28mA    25.22mA    28.17mA
1.814V    28.29mA    26.44mA    30.16mA
2.052V    25.24mA    21.96mA    28.34mA
2.386V    19.03mA    6.5mA      22.66mA
2.625V    7.1mA      3.4mA      17.7mA
2.959V    3mA        2.3mA      5.1mA
[Pullup]
-1.459V   1.7mA      1.714mA    1.971mA
-1.173V   4.7mA      2.971mA    8.571mA
-838.6mV  18.38mA    10.72mA    17.71mA
-695.5mV  18.79mA    17.12mA    18.09mA
-552.3mV  17.7mA     17.94mA    17.47mA
640.9mV   -16.58mA   -16.97mA   -17.62mA
1.834V    -23.79mA   -23.77mA   -25.99mA
2.12V     -21.67mA   -20.55mA   -24.11mA
2.311V    -20.79mA   -13.39mA   -23.19mA
2.502V    -13.6mA    -9.614mA   -22.45mA
2.741V    -8.5mA     -7.786mA   -11.5mA
2.98V     -7.1mA     -7.143mA   -8.014mA
[Ramp]
R_load=50.000Ohm
dV/dt_r   486.963mV/109.000ps  467.730mV/127.000ps  521.847mV/96.500ps
dV/dt_f   486.963mV/114.000ps  467.730mV/137.000ps  521.847mV/100.500ps
[Rising waveform]
R_fixture=50.000Ohm
V_fixture=1.500
V_fixture_min=1.425
V_fixture_max=1.575
0s        690.6mV    659.8mV    707.6mV
39ps      704.9mV    657.5mV    744.4mV
62ps      754.9mV    657.2mV    868.9mV
123ps     1.13V      672.5mV    1.338V
154ps     1.292V     710.5mV    1.451V
184ps     1.383V     798.5mV    1.508V
268ps     1.474V     1.207V     1.561V
337ps     1.491V     1.358V     1.571V
452ps     1.498V     1.413V     1.574V
749ps     1.5V       1.425V     1.575V
[Rising waveform]
R_fixture=50.000Ohm
V_fixture=0
0s        44.65mV    38.97mV    58.28mV
39ps      39.93mV    37.2mV     68.71mV
77ps      94.85mV    33.1mV     209.1mV
161ps     453.5mV    41.68mV    650.3mV
207ps     620.7mV    127.8mV    782.5mV
253ps     727.7mV    284.2mV    856.2mV
345ps     823.3mV    601.7mV    914.9mV
421ps     850.7mV    737.5mV    930mV
529ps     863.9mV    807.2mV    937.9mV
749ps     870mV      834.1mV    940.9mV
[Falling waveform]
R_fixture=50.000Ohm
V_fixture=1.500
V_fixture_min=1.425
V_fixture_max=1.575
0s        1.506V     1.424V     1.58V
46ps      1.512V     1.427V     1.568V
85ps      1.452V     1.436V     1.434V
169ps     1.118V     1.419V     1.015V
207ps     977.2mV    1.349V     891.4mV
253ps     855.7mV    1.209V     805.7mV
345ps     748.5mV    921.6mV    739.8mV
429ps     717.3mV    772.1mV    722.9mV
544ps     704.6mV    700.6mV    717mV
749ps     699.8mV    672.3mV    714.3mV
[Falling waveform]
R_fixture=50.000Ohm
V_fixture=0
0s        881.3mV    842.1mV    948.7mV
23ps      871mV      845.6mV    932.3mV
46ps      825mV      849.2mV    843.3mV
115ps     429.9mV    823.6mV    340.6mV
154ps     245.1mV    728mV      193.5mV
192ps     149.7mV    557.7mV    127.7mV
268ps     79.03mV    220.3mV    80.76mV
337ps     60.54mV    100.9mV    68.67mV
460ps     51.45mV    51.25mV    63.75mV
749ps     49.39mV    39.08mV    62.86mV
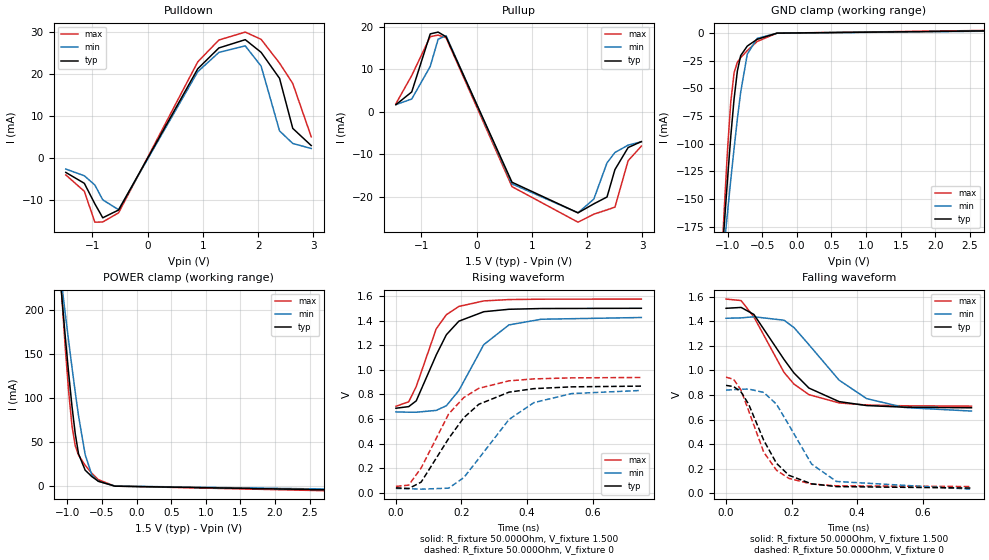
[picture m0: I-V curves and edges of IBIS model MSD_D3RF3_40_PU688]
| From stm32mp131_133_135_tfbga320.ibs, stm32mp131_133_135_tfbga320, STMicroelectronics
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[Model] MSD_D3RF3_40_PU688
Model_type   I/O
C_comp 2.446pF   2.363pF   2.570pF
Vinh = 925.000mV
Vinl = 575.000mV
Vmeas = 750.000mV
Vref = 750.000mV
[Model Spec]
Vinh   925.000mV   888.000mV   963.000mV
Vinl   575.000mV   538.000mV   613.000mV
Vmeas   750.000mV   713.000mV   788.000mV
Vref   750.000mV   713.000mV   788.000mV
[Temperature Range]   25.000   125.000   -40.000
[Voltage Range]   1.500V   1.425V   1.575V
[GND Clamp Reference]   0.00V   0.00V   0.00V
[Pulldown Reference]   0.00V   0.00V   0.00V
[POWER Clamp Reference]   1.500V   1.425V   1.575V
[Pullup Reference]   1.500V   1.425V   1.575V
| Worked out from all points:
|   slope of the pulldown table from 0 to 0.225 V, typ, clamps not added: 36.6 ohm
|   slope of the pullup table from 0 to 0.225 V, typ, clamps not added: 31.2 ohm
|   GND clamp passes 1 mA (typ) near -0.40 V on its own axis
|   POWER clamp passes 1 mA (typ) near -0.41 V on its own axis
|   rising waveform, R_fixture 50.000Ohm, V_fixture 1.500: 20-80 % time 84.9ps typ, 102ps min, 75.1ps max; typ from 0.687 V to 1.5 V
|   rising waveform, R_fixture 50.000Ohm, V_fixture 0: 20-80 % time 134ps typ, 150ps min, 118ps max; typ from 0.04 V to 0.867 V
|   falling waveform, R_fixture 50.000Ohm, V_fixture 1.500: 20-80 % time 135ps typ, 160ps min, 119ps max; typ from 1.5 V to 0.696 V
|   falling waveform, R_fixture 50.000Ohm, V_fixture 0: 20-80 % time 93.4ps typ, 110ps min, 81.7ps max; typ from 0.878 V to 0.044 V
[GND Clamp]
-1.48V    -595.2mA   -480.7mA   -764.8mA
-1.098V   -219mA     -224mA     -221.3mA
-1.05V    -174.8mA   -193mA     -160.7mA
-1.002V   -132.6mA   -162.5mA   -106.1mA
-954.6mV  -93.46mA   -132.8mA   -62.34mA
-906.8mV  -59.58mA   -104.4mA   -35.89mA
-859.1mV  -34.31mA   -77.57mA   -26.3mA
-811.4mV  -20.36mA   -53.44mA   -22.21mA
-715.9mV  -11.74mA   -19.01mA   -15.85mA
-572.7mV  -5.607mA   -4.792mA   -7.572mA
-286.4mV  -72.41uA   -119.8uA   -57.21uA
2.959V    2.137mA    1.823mA    2.578mA
[Power Clamp]
-1.459V   579mA      480.3mA    724.6mA
-1.077V   211.8mA    226.2mA    211.3mA
-1.03V    169mA      195.3mA    156.5mA
-981.8mV  128.3mA    164.9mA    107.6mA
-934.1mV  91.14mA    135.2mA    69.08mA
-886.4mV  59.6mA     106.7mA    45.92mA
-838.6mV  36.69mA    79.86mA    35.27mA
-743.2mV  18.26mA    35.9mA     23.82mA
-647.7mV  11.03mA    13.1mA     14.7mA
-552.3mV  5.662mA    5.603mA    7.453mA
-313.6mV  110.5uA    252uA      124.9uA
2.98V     -4.304mA   -3.47mA    -5.498mA
[Pulldown]
-1.48V    -3.4mA     -2.6mA     -4mA
-1.145V   -6mA       -4.2mA     -7.9mA
-954.6mV  -10.89mA   -6.4mA     -15.27mA
-811.4mV  -14.22mA   -9.94mA    -15.22mA
-525mV    -12.36mA   -12.3mA    -13.03mA
906.8mV   21.31mA    20.61mA    22.96mA
1.289V    26.28mA    25.22mA    28.17mA
1.766V    28.25mA    26.77mA    30.06mA
2.052V    25.24mA    21.96mA    28.34mA
2.386V    19.03mA    6.5mA      22.66mA
2.625V    7.1mA      3.5mA      17.8mA
2.959V    3mA        2.3mA      5.1mA
[Pullup]
-1.459V   1.7mA      1.714mA    1.929mA
-1.173V   4.7mA      3.029mA    8.571mA
-838.6mV  18.38mA    10.7mA     17.72mA
-695.5mV  18.8mA     17.13mA    18.09mA
-552.3mV  17.7mA     17.94mA    17.47mA
640.9mV   -16.58mA   -16.97mA   -17.62mA
1.834V    -23.79mA   -23.78mA   -25.99mA
2.12V     -21.67mA   -20.55mA   -24.11mA
2.359V    -20.05mA   -12.01mA   -23.08mA
2.502V    -13.6mA    -9.571mA   -22.45mA
2.741V    -8.4mA     -7.829mA   -11.5mA
2.98V     -7mA       -7.043mA   -8.071mA
[Ramp]
R_load=50.000Ohm
dV/dt_r   488.682mV/110.000ps  469.137mV/128.000ps  524.115mV/98.000ps
dV/dt_f   488.682mV/115.000ps  469.137mV/137.500ps  524.115mV/101.000ps
[Rising waveform]
R_fixture=50.000Ohm
V_fixture=1.500
V_fixture_min=1.425
V_fixture_max=1.575
0s        687.1mV    657.2mV    703.1mV
39ps      700.3mV    654.9mV    739.6mV
62ps      747.3mV    654.6mV    863.6mV
123ps     1.12V      669.6mV    1.333V
154ps     1.285V     707.5mV    1.448V
192ps     1.395V     830.6mV    1.515V
268ps     1.472V     1.204V     1.56V
345ps     1.492V     1.365V     1.571V
444ps     1.498V     1.411V     1.574V
749ps     1.5V       1.425V     1.575V
[Rising waveform]
R_fixture=50.000Ohm
V_fixture=0
0s        39.51mV    34.81mV    51.53mV
39ps      34.33mV    33.05mV    61.79mV
77ps      86.29mV    28.93mV    201.3mV
161ps     441.5mV    37.23mV    640.7mV
207ps     609.9mV    122.9mV    774mV
253ps     719.2mV    278.5mV    849.2mV
345ps     817.8mV    595.7mV    909.9mV
421ps     846.5mV    732.7mV    925.7mV
536ps     861mV      806.3mV    934.2mV
749ps     867mV      831.8mV    937.2mV
[Falling waveform]
R_fixture=50.000Ohm
V_fixture=1.500
V_fixture_min=1.425
V_fixture_max=1.575
0s        1.505V     1.424V     1.58V
46ps      1.512V     1.427V     1.568V
85ps      1.455V     1.436V     1.434V
177ps     1.089V     1.408V     983.9mV
207ps     979.8mV    1.349V     889.6mV
253ps     856.5mV    1.209V     803.1mV
345ps     746.6mV    921mV      736mV
429ps     714.5mV    770.8mV    718.7mV
544ps     701.2mV    698.6mV    712.5mV
749ps     696.4mV    669.7mV    709.8mV
[Falling waveform]
R_fixture=50.000Ohm
V_fixture=0
0s        878.3mV    840mV      945mV
23ps      869.1mV    843.5mV    928.4mV
46ps      824.5mV    847.1mV    839.1mV
69ps      725.2mV    848.6mV    671.6mV
115ps     432.1mV    821.3mV    335.7mV
154ps     244.7mV    725.4mV    188.4mV
192ps     147.3mV    554.7mV    122.2mV
261ps     78.27mV    239.1mV    76.75mV
337ps     55.72mV    97.41mV    62.11mV
749ps     44.05mV    34.9mV     56.1mV
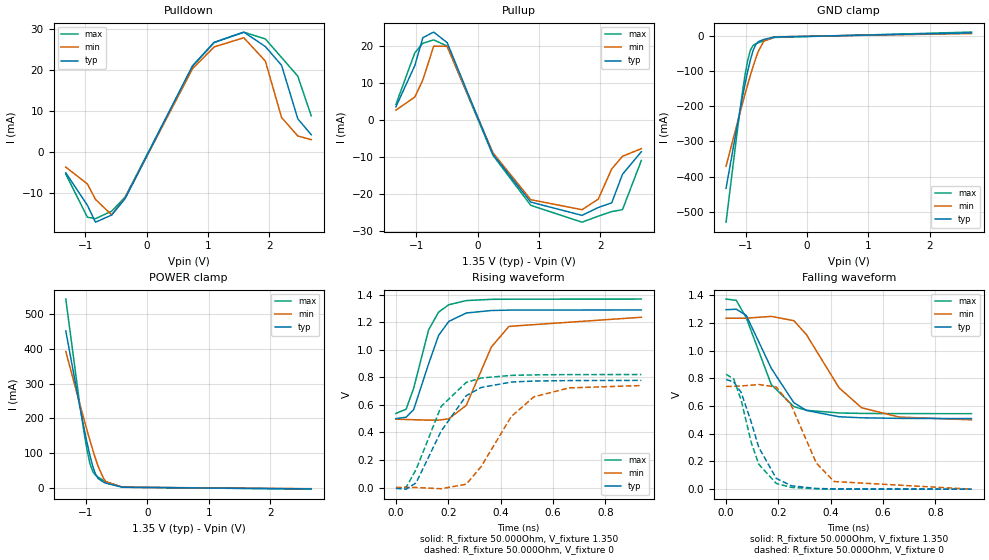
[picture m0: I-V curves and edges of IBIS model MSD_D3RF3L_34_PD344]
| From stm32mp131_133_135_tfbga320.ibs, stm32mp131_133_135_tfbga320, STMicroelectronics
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[Model] MSD_D3RF3L_34_PD344
Model_type   I/O
C_comp 2.333pF   2.249pF   2.455pF
Vinh = 810.000mV
Vinl = 540.000mV
Vmeas = 675.000mV
Vref = 675.000mV
[Model Spec]
Vinh   810.000mV   777.000mV   860.000mV
Vinl   540.000mV   507.000mV   590.000mV
Vmeas   675.000mV   642.000mV   725.000mV
Vref   675.000mV   642.000mV   725.000mV
[Receiver Thresholds]
Vth   =  0.675V
Vth_min  =  0.6615V
Vth_max  =  0.6885V
Vinh_ac  =  0.160V
Vinh_dc  =  0.090V
Vinl_ac  = -0.160V
Vinl_dc  = -0.090V
Tslew_ac =  5.000ns |Not specified, so set to high value
Threshold_sensitivity = 0.50
Reference_supply Pullup_ref
[Temperature Range]   25.000   125.000   -40.000
[Voltage Range]   1.350V   1.283V   1.450V
[GND Clamp Reference]   0.00V   0.00V   0.00V
[Pulldown Reference]   0.00V   0.00V   0.00V
[POWER Clamp Reference]   1.350V   1.283V   1.450V
[Pullup Reference]   1.350V   1.283V   1.450V
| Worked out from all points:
|   slope of the pulldown table from 0 to 0.203 V, typ, clamps not added: 31 ohm
|   slope of the pullup table from 0 to 0.203 V, typ, clamps not added: 26.2 ohm
|   GND clamp passes 1 mA (typ) near -0.41 V on its own axis
|   POWER clamp passes 1 mA (typ) near -0.41 V on its own axis
|   rising waveform, R_fixture 50.000Ohm, V_fixture 1.350: 20-80 % time 82.7ps typ, 104ps min, 73ps max; typ from 0.5 V to 1.29 V
|   rising waveform, R_fixture 50.000Ohm, V_fixture 0: 20-80 % time 130ps typ, 154ps min, 114ps max; typ from -0.006 V to 0.777 V
|   falling waveform, R_fixture 50.000Ohm, V_fixture 1.350: 20-80 % time 124ps typ, 156ps min, 105ps max; typ from 1.29 V to 0.509 V
|   falling waveform, R_fixture 50.000Ohm, V_fixture 0: 20-80 % time 86.2ps typ, 107ps min, 74.2ps max; typ from 0.791 V to 0 V
[GND Clamp]
-1.318V   -432.8mA   -370.3mA   -528.8mA
-1.142V   -260.6mA   -252.7mA   -280.2mA
-1.055V   -178.2mA   -195.3mA   -165.2mA
-1.011V   -139.1mA   -167.2mA   -114.1mA
-966.7mV  -102.3mA   -139.7mA   -71.26mA
-922.7mV  -69.52mA   -113.2mA   -41.65mA
-878.8mV  -42.92mA   -87.94mA   -28.29mA
-834.9mV  -25.34mA   -64.54mA   -23.37mA
-790.9mV  -16.86mA   -43.9mA    -20.2mA
-703mV    -10.78mA   -15.99mA   -14.6mA
-527.3mV  -3.885mA   -3.295mA   -5.182mA
2.68V     7.735mA    6.026mA    10.03mA
[Power Clamp]
-1.33V    451.9mA    392.5mA    543.7mA
-1.111V   241.7mA    247mA      250.6mA
-1.023V   162.1mA    190.1mA    147.8mA
-978.8mV  125mA      162.2mA    103.3mA
-934.9mV  90.96mA    135mA      67.89mA
-890.9mV  61.61mA    108.7mA    46.32mA
-847mV    39.32mA    83.78mA    35.87mA
-803mV    26.01mA    60.99mA    29.83mA
-715.1mV  15.42mA    26.29mA    20.43mA
-671.2mV  12.23mA    16.24mA    16.32mA
-407.6mV  863.9uA    1.131mA    1.056mA
2.668V    -3.889mA   -3.241mA   -4.623mA
[Pulldown]
-1.318V   -5.2mA     -3.8mA     -5.5mA
-966.7mV  -13.1mA    -7.9mA     -16.02mA
-834.9mV  -17.24mA   -11.67mA   -16.38mA
-571.2mV  -15.5mA    -15.45mA   -14.56mA
-351.5mV  -11.48mA   -11.32mA   -11.1mA
747mV     20.95mA    20.22mA    20.78mA
1.098V    26.62mA    25.53mA    26.63mA
1.582V    29.15mA    27.77mA    29.12mA
1.933V    25.61mA    22.07mA    27.48mA
2.197V    21.04mA    8.3mA      22.94mA
2.461V    8mA        3.8mA      18.4mA
2.68V     4.1mA      2.9mA      8.7mA
[Pullup]
-1.33V    3.5mA      2.605mA    4.152mA
-1.023V   14.6mA     6.125mA    18.04mA
-890.9mV  22.16mA    10.76mA    20.65mA
-715.1mV  23.66mA    19.86mA    21.56mA
-495.5mV  20.82mA    19.82mA    19.88mA
251.5mV   -9.373mA   -8.925mA   -9.601mA
866.7mV   -22.21mA   -21.56mA   -23.09mA
1.702V    -25.79mA   -24.26mA   -27.63mA
1.965V    -23.67mA   -21.42mA   -26.01mA
2.185V    -22.41mA   -13.27mA   -24.77mA
2.361V    -14.7mA    -9.838mA   -24.24mA
2.668V    -8.6mA     -7.795mA   -10.98mA
[Ramp]
R_load=50.000Ohm
dV/dt_r   466.950mV/106.500ps  443.729mV/130.000ps  492.420mV/93.500ps
dV/dt_f   466.950mV/105.000ps  443.729mV/133.000ps  492.420mV/90.000ps
[Rising waveform]
R_fixture=50.000Ohm
V_fixture=1.350
V_fixture_min=1.283
V_fixture_max=1.450
0s        499.7mV    495.5mV    537.5mV
39ps      510.1mV    493.6mV    567.8mV
68ps      566mV      491.9mV    721.6mV
125ps     897.7mV    488.7mV    1.144V
163ps     1.103V     489.2mV    1.272V
202ps     1.205V     498.4mV    1.326V
269ps     1.266V     596.4mV    1.356V
365ps     1.284V     1.02V      1.365V
432ps     1.287V     1.169V     1.366V
938ps     1.288V     1.235V     1.367V
[Rising waveform]
R_fixture=50.000Ohm
V_fixture=0
0s        -6.203mV   857.3uV    -5.495mV
39ps      -11.74mV   966.8uV    1.608mV
77ps      33.88mV    418.9uV    130.1mV
173ps     409.7mV    -8.653mV   589mV
269ps     666.6mV    24.2mV     762.8mV
326ps     725.9mV    152.9mV    794.6mV
441ps     765.1mV    515.5mV    813.6mV
527ps     772.4mV    657.7mV    817.1mV
662ps     775.8mV    722.8mV    819.2mV
938ps     777.2mV    739.8mV    819.7mV
[Falling waveform]
R_fixture=50.000Ohm
V_fixture=1.350
V_fixture_min=1.283
V_fixture_max=1.450
0s        1.295V     1.234V     1.372V
39ps      1.299V     1.234V     1.363V
77ps      1.255V     1.234V     1.238V
173ps     871.8mV    1.247V     754.1mV
259ps     624.2mV    1.216V     596mV
307ps     568.3mV    1.116V     569.2mV
432ps     522.5mV    731.3mV    550.1mV
518ps     515.1mV    587.6mV    546.7mV
662ps     510.9mV    520.1mV    545.1mV
938ps     509.4mV    500.5mV    544.9mV
[Falling waveform]
R_fixture=50.000Ohm
V_fixture=0
0s        791.2mV    741mV      829.3mV
29ps      774.9mV    742.1mV    796.1mV
58ps      697.7mV    744.9mV    641.4mV
96ps      484.7mV    750.6mV    338.5mV
125ps     302mV      755.2mV    179.8mV
192ps     77.49mV    736.9mV    40.99mV
250ps     24.34mV    602.2mV    12.84mV
345ps     5.134mV    188.1mV    2.138mV
413ps     1.907mV    55.01mV    592.9uV
938ps     5.587uV    113.3uV    2.861uV
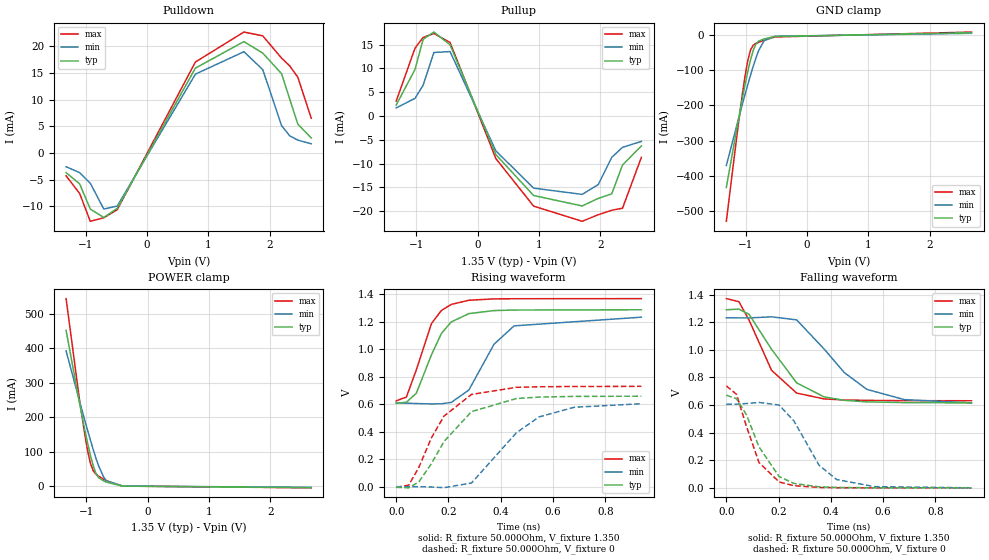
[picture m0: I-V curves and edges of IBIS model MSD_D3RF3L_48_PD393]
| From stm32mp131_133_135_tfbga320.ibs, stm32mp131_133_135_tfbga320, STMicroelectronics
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[Model] MSD_D3RF3L_48_PD393
Model_type   I/O
C_comp 2.363pF   2.279pF   2.485pF
Vinh = 810.000mV
Vinl = 540.000mV
Vmeas = 675.000mV
Vref = 675.000mV
[Model Spec]
Vinh   810.000mV   777.000mV   860.000mV
Vinl   540.000mV   507.000mV   590.000mV
Vmeas   675.000mV   642.000mV   725.000mV
Vref   675.000mV   642.000mV   725.000mV
[Receiver Thresholds]
Vth   =  0.675V
Vth_min  =  0.6615V
Vth_max  =  0.6885V
Vinh_ac  =  0.160V
Vinh_dc  =  0.090V
Vinl_ac  = -0.160V
Vinl_dc  = -0.090V
Tslew_ac =  5.000ns |Not specified, so set to high value
Threshold_sensitivity = 0.50
Reference_supply Pullup_ref
[Temperature Range]   25.000   125.000   -40.000
[Voltage Range]   1.350V   1.283V   1.450V
[GND Clamp Reference]   0.00V   0.00V   0.00V
[Pulldown Reference]   0.00V   0.00V   0.00V
[POWER Clamp Reference]   1.350V   1.283V   1.450V
[Pullup Reference]   1.350V   1.283V   1.450V
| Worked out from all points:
|   slope of the pulldown table from 0 to 0.203 V, typ, clamps not added: 42.2 ohm
|   slope of the pullup table from 0 to 0.203 V, typ, clamps not added: 34.5 ohm
|   GND clamp passes 1 mA (typ) near -0.40 V on its own axis
|   POWER clamp passes 1 mA (typ) near -0.41 V on its own axis
|   rising waveform, R_fixture 50.000Ohm, V_fixture 1.350: 20-80 % time 93.5ps typ, 116ps min, 79.1ps max; typ from 0.606 V to 1.29 V
|   rising waveform, R_fixture 50.000Ohm, V_fixture 0: 20-80 % time 151ps typ, 182ps min, 128ps max; typ from -0.004 V to 0.658 V
|   falling waveform, R_fixture 50.000Ohm, V_fixture 1.350: 20-80 % time 149ps typ, 183ps min, 116ps max; typ from 1.29 V to 0.615 V
|   falling waveform, R_fixture 50.000Ohm, V_fixture 0: 20-80 % time 98.5ps typ, 117ps min, 80.6ps max; typ from 0.671 V to 0 V
[GND Clamp]
-1.318V   -433.1mA   -370.5mA   -529.1mA
-1.142V   -260.9mA   -253mA     -280.5mA
-1.055V   -178.4mA   -195.4mA   -165.5mA
-1.011V   -139.3mA   -167.3mA   -114.3mA
-966.7mV  -102.5mA   -139.9mA   -71.47mA
-922.7mV  -69.67mA   -113.3mA   -41.85mA
-878.8mV  -43.06mA   -88.06mA   -28.46mA
-834.9mV  -25.47mA   -64.63mA   -23.53mA
-790.9mV  -16.97mA   -43.99mA   -20.34mA
-703mV    -10.86mA   -16.06mA   -14.72mA
-527.3mV  -3.925mA   -3.327mA   -5.234mA
2.68V     6.766mA    5.271mA    8.773mA
[Power Clamp]
-1.33V    452.2mA    392.7mA    544.1mA
-1.111V   241.9mA    247.2mA    250.9mA
-1.023V   162.3mA    190.3mA    148.1mA
-978.8mV  125.2mA    162.4mA    103.6mA
-934.9mV  91.13mA    135.2mA    68.12mA
-890.9mV  61.77mA    108.8mA    46.52mA
-847mV    39.46mA    83.89mA    36.05mA
-803mV    26.13mA    61.11mA    29.99mA
-715.1mV  15.51mA    26.39mA    20.56mA
-671.2mV  12.32mA    16.32mA    16.43mA
-407.6mV  880uA      1.151mA    1.073mA
2.668V    -3.403mA   -2.836mA   -4.045mA
[Pulldown]
-1.318V   -3.7mA     -2.6mA     -4.3mA
-1.098V   -5.8mA     -3.7mA     -7.6mA
-922.7mV  -10.55mA   -5.7mA     -12.83mA
-703mV    -12.11mA   -10.54mA   -12.17mA
-483.3mV  -10.41mA   -9.969mA   -10.65mA
790.9mV   15.9mA     14.77mA    17.05mA
1.582V    20.88mA    18.98mA    22.67mA
1.889V    18.72mA    15.62mA    21.96mA
2.197V    14.84mA    5.1mA      17.77mA
2.329V    10.1mA     3.2mA      16.32mA
2.461V    5.4mA      2.4mA      14.2mA
2.68V     2.8mA      1.7mA      6.5mA
[Pullup]
-1.33V    2.3mA      1.705mA    3.135mA
-1.023V   9.8mA      3.715mA    14.27mA
-890.9mV  16.12mA    6.482mA    16.51mA
-715.1mV  17.65mA    13.35mA    17.34mA
-451.5mV  14.98mA    13.54mA    15.46mA
295.4mV   -8.125mA   -7.33mA    -8.964mA
910.6mV   -16.72mA   -15.17mA   -18.95mA
1.702V    -18.92mA   -16.49mA   -22.14mA
1.965V    -17.33mA   -14.42mA   -20.77mA
2.185V    -16.38mA   -8.694mA   -19.82mA
2.361V    -10.3mA    -6.59mA    -19.39mA
2.668V    -6.3mA     -5.348mA   -8.693mA
[Ramp]
R_load=50.000Ohm
dV/dt_r   398.940mV/122.000ps  367.889mV/151.000ps  439.620mV/104.500ps
dV/dt_f   398.940mV/124.000ps  367.949mV/152.000ps  439.620mV/98.500ps
[Rising waveform]
R_fixture=50.000Ohm
V_fixture=1.350
V_fixture_min=1.283
V_fixture_max=1.450
0s        606mV      609.3mV    624.2mV
39ps      614.2mV    607.3mV    651.9mV
77ps      679.5mV    604.9mV    849.3mV
135ps     959.1mV    601.7mV    1.186V
173ps     1.114V     602.9mV    1.281V
211ps     1.198V     613.1mV    1.325V
278ps     1.258V     702.8mV    1.355V
374ps     1.28V      1.035V     1.365V
451ps     1.284V     1.169V     1.366V
938ps     1.286V     1.232V     1.367V
[Rising waveform]
R_fixture=50.000Ohm
V_fixture=0
0s        -4.092mV   605.5uV    -4.133mV
48ps      -7.81mV    815.7uV    11.81mV
87ps      35.94mV    481.5uV    142.1mV
135ps     169.3mV    -1.715mV   356.3mV
183ps     328.8mV    -6.606mV   513.5mV
288ps     545.9mV    27.14mV    671mV
460ps     641.2mV    392.9mV    722.4mV
547ps     651.5mV    507.5mV    726.6mV
681ps     656.4mV    577.6mV    728.5mV
938ps     657.9mV    603.2mV    729.4mV
[Falling waveform]
R_fixture=50.000Ohm
V_fixture=1.350
V_fixture_min=1.283
V_fixture_max=1.450
0s        1.29V      1.232V     1.371V
48ps      1.295V     1.231V     1.349V
87ps      1.257V     1.231V     1.215V
173ps     1.004V     1.239V     851.5mV
269ps     760.6mV    1.217V     686.6mV
374ps     658.9mV    1.006V     644.2mV
451ps     634mV      835.5mV    636.7mV
537ps     622.9mV    713.7mV    633.6mV
681ps     617.5mV    639.3mV    631.5mV
938ps     615.4mV    615.3mV    630.9mV
[Falling waveform]
R_fixture=50.000Ohm
V_fixture=0
0s        671.3mV    605.2mV    738.4mV
39ps      645.2mV    606.6mV    677.6mV
77ps      529mV      610.7mV    445mV
125ps     296.4mV    618.7mV    183.2mV
202ps     81.57mV    600mV      42.53mV
259ps     31.68mV    483.4mV    15.43mV
355ps     7.455mV    163.3mV    2.921mV
422ps     2.889mV    60.12mV    932.6uV
566ps     385.5uV    8.736mV    159uV
938ps     11uV       145.7uV    7.491uV
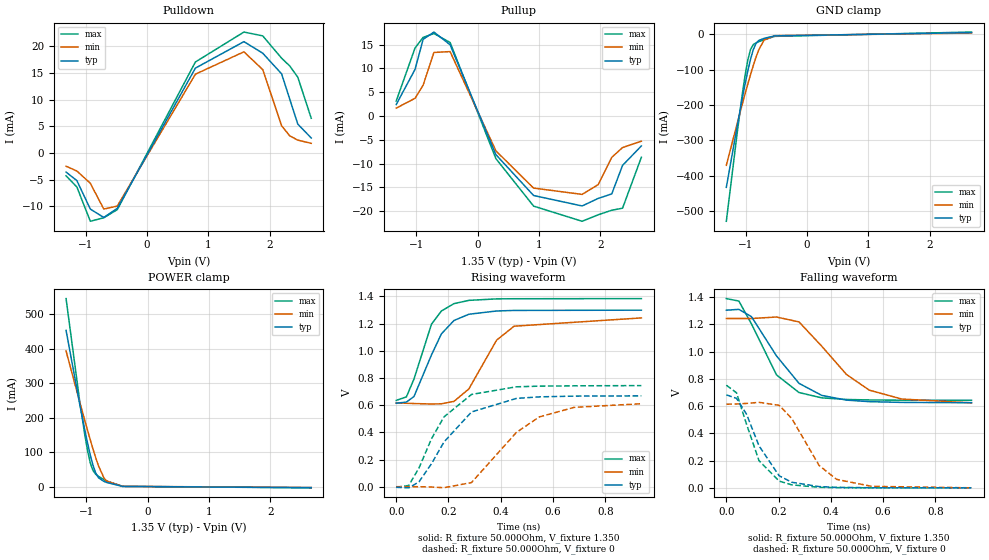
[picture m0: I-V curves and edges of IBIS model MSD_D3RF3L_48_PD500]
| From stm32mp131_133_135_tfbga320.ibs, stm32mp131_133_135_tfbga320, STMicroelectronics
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[Model] MSD_D3RF3L_48_PD500
Model_type   I/O
C_comp 2.410pF   2.326pF   2.533pF
Vinh = 810.000mV
Vinl = 540.000mV
Vmeas = 675.000mV
Vref = 675.000mV
[Model Spec]
Vinh   810.000mV   777.000mV   860.000mV
Vinl   540.000mV   507.000mV   590.000mV
Vmeas   675.000mV   642.000mV   725.000mV
Vref   675.000mV   642.000mV   725.000mV
[Receiver Thresholds]
Vth   =  0.675V
Vth_min  =  0.6615V
Vth_max  =  0.6885V
Vinh_ac  =  0.160V
Vinh_dc  =  0.090V
Vinl_ac  = -0.160V
Vinl_dc  = -0.090V
Tslew_ac =  5.000ns |Not specified, so set to high value
Threshold_sensitivity = 0.50
Reference_supply Pullup_ref
[Temperature Range]   25.000   125.000   -40.000
[Voltage Range]   1.350V   1.283V   1.450V
[GND Clamp Reference]   0.00V   0.00V   0.00V
[Pulldown Reference]   0.00V   0.00V   0.00V
[POWER Clamp Reference]   1.350V   1.283V   1.450V
[Pullup Reference]   1.350V   1.283V   1.450V
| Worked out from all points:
|   slope of the pulldown table from 0 to 0.203 V, typ, clamps not added: 42.2 ohm
|   slope of the pullup table from 0 to 0.203 V, typ, clamps not added: 34.5 ohm
|   GND clamp passes 1 mA (typ) near -0.40 V on its own axis
|   POWER clamp passes 1 mA (typ) near -0.41 V on its own axis
|   rising waveform, R_fixture 50.000Ohm, V_fixture 1.350: 20-80 % time 94.4ps typ, 117ps min, 80.2ps max; typ from 0.614 V to 1.3 V
|   rising waveform, R_fixture 50.000Ohm, V_fixture 0: 20-80 % time 153ps typ, 185ps min, 131ps max; typ from -0.004 V to 0.669 V
|   falling waveform, R_fixture 50.000Ohm, V_fixture 1.350: 20-80 % time 153ps typ, 185ps min, 121ps max; typ from 1.3 V to 0.624 V
|   falling waveform, R_fixture 50.000Ohm, V_fixture 0: 20-80 % time 101ps typ, 119ps min, 83.1ps max; typ from 0.682 V to 0 V
[GND Clamp]
-1.318V   -433.5mA   -370.9mA   -529.7mA
-1.142V   -261.2mA   -253.2mA   -280.9mA
-1.055V   -178.7mA   -195.7mA   -165.8mA
-1.011V   -139.6mA   -167.6mA   -114.7mA
-966.7mV  -102.7mA   -140.1mA   -71.8mA
-922.7mV  -69.9mA    -113.5mA   -42.14mA
-878.8mV  -43.27mA   -88.23mA   -28.74mA
-834.9mV  -25.65mA   -64.79mA   -23.77mA
-790.9mV  -17.14mA   -44.12mA   -20.57mA
-703mV    -10.99mA   -16.17mA   -14.89mA
-527.3mV  -3.983mA   -3.376mA   -5.312mA
2.68V     5.315mA    4.144mA    6.889mA
[Power Clamp]
-1.33V    452.7mA    393.1mA    544.7mA
-1.111V   242.2mA    247.6mA    251.3mA
-1.023V   162.6mA    190.6mA    148.4mA
-978.8mV  125.5mA    162.7mA    103.9mA
-934.9mV  91.39mA    135.4mA    68.44mA
-890.9mV  62.01mA    109mA      46.81mA
-847mV    39.69mA    84.09mA    36.32mA
-803mV    26.33mA    61.28mA    30.23mA
-715.1mV  15.66mA    26.52mA    20.75mA
-671.2mV  12.45mA    16.44mA    16.6mA
-407.6mV  904uA      1.178mA    1.103mA
2.668V    -2.674mA   -2.229mA   -3.179mA
[Pulldown]
-1.318V   -3.6mA     -2.5mA     -4.3mA
-1.142V   -5.2mA     -3.4mA     -6.4mA
-922.7mV  -10.54mA   -5.7mA     -12.83mA
-703mV    -12.11mA   -10.54mA   -12.17mA
-483.3mV  -10.41mA   -9.974mA   -10.65mA
790.9mV   15.91mA    14.77mA    17.06mA
1.582V    20.88mA    18.97mA    22.68mA
1.889V    18.71mA    15.63mA    21.96mA
2.197V    14.83mA    5.1mA      17.77mA
2.329V    10.1mA     3.2mA      16.32mA
2.461V    5.4mA      2.4mA      14.2mA
2.68V     2.8mA      1.8mA      6.5mA
[Pullup]
-1.33V    2.4mA      1.652mA    3.135mA
-1.023V   9.8mA      3.715mA    14.3mA
-890.9mV  16.12mA    6.482mA    16.52mA
-715.1mV  17.65mA    13.36mA    17.34mA
-451.5mV  14.98mA    13.54mA    15.46mA
295.4mV   -8.125mA   -7.33mA    -8.964mA
910.6mV   -16.72mA   -15.16mA   -18.95mA
1.702V    -18.92mA   -16.49mA   -22.14mA
1.965V    -17.33mA   -14.42mA   -20.77mA
2.185V    -16.38mA   -8.694mA   -19.82mA
2.361V    -10.4mA    -6.643mA   -19.39mA
2.668V    -6.3mA     -5.295mA   -8.693mA
[Ramp]
R_load=50.000Ohm
dV/dt_r   403.590mV/124.000ps  371.459mV/152.500ps  445.950mV/106.500ps
dV/dt_f   403.590mV/126.500ps  371.489mV/154.500ps  445.950mV/102.500ps
[Rising waveform]
R_fixture=50.000Ohm
V_fixture=1.350
V_fixture_min=1.283
V_fixture_max=1.450
0s        614.5mV    616.2mV    635.1mV
39ps      623mV      614.2mV    661.1mV
68ps      663.8mV    612.3mV    792.5mV
135ps     970mV      608.6mV    1.196V
173ps     1.125V     610.3mV    1.293V
221ps     1.223V     628mV      1.347V
278ps     1.269V     719.8mV    1.371V
384ps     1.293V     1.078V     1.382V
451ps     1.297V     1.181V     1.383V
938ps     1.299V     1.242V     1.384V
[Rising waveform]
R_fixture=50.000Ohm
V_fixture=0
0s        -4.09mV    629uV      -3.915mV
48ps      -7.825mV   813.9uV    9.737mV
87ps      35.92mV    403.5uV    137.8mV
135ps     169.5mV    -1.941mV   353.6mV
183ps     329.7mV    -6.957mV   514.3mV
288ps     550.1mV    30.81mV    679mV
460ps     649.9mV    400mV      735.3mV
547ps     661.2mV    513.4mV    740.1mV
681ps     666.8mV    584.1mV    742.7mV
938ps     668.7mV    610.9mV    744mV
[Falling waveform]
R_fixture=50.000Ohm
V_fixture=1.350
V_fixture_min=1.283
V_fixture_max=1.450
0s        1.303V     1.242V     1.388V
48ps      1.309V     1.242V     1.37V
96ps      1.256V     1.242V     1.203V
192ps     967.6mV    1.253V     828.4mV
278ps     766.5mV    1.217V     699.2mV
365ps     678.1mV    1.039V     660mV
460ps     643.4mV    831.1mV    648.1mV
547ps     632.1mV    716.5mV    644.7mV
671ps     626.7mV    651.4mV    642.8mV
938ps     624.1mV    623.2mV    641.8mV
[Falling waveform]
R_fixture=50.000Ohm
V_fixture=0
0s        682mV      613.4mV    752.8mV
39ps      656.4mV    615mV      696.8mV
77ps      541.2mV    619.2mV    468.4mV
125ps     308.2mV    627.1mV    199.5mV
202ps     88.58mV    605.5mV    49.6mV
250ps     41.12mV    509.8mV    21.97mV
355ps     9.12mV     164mV      3.959mV
422ps     3.707mV    62.15mV    1.358mV
556ps     628.3uV    10.93mV    266.1uV
938ps     17.36uV    193.6uV    9.142uV
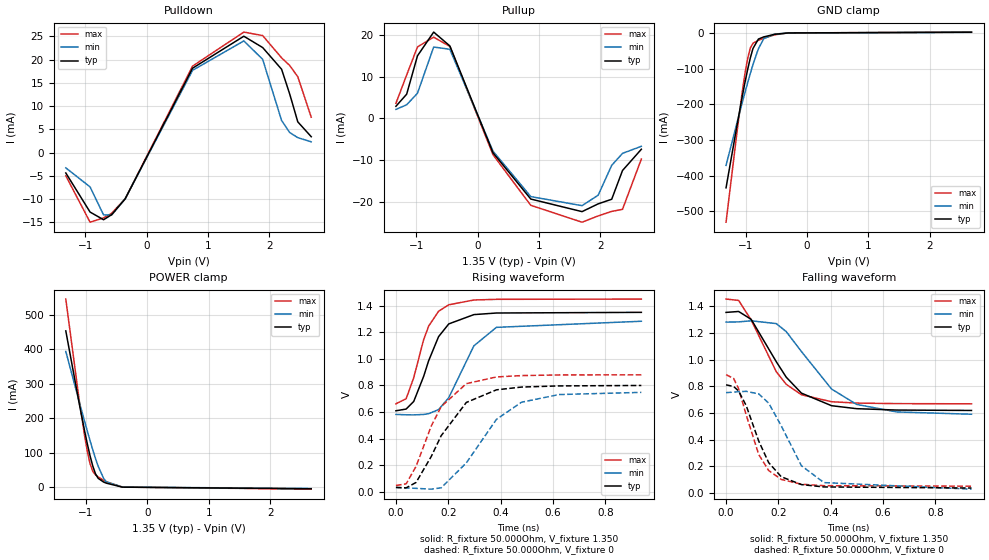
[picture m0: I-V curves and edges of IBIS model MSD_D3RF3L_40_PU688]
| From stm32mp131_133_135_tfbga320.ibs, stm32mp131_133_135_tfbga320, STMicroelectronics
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[Model] MSD_D3RF3L_40_PU688
Model_type   I/O
C_comp 2.455pF   2.369pF   2.579pF
Vinh = 810.000mV
Vinl = 540.000mV
Vmeas = 675.000mV
Vref = 675.000mV
[Model Spec]
Vinh   810.000mV   777.000mV   860.000mV
Vinl   540.000mV   507.000mV   590.000mV
Vmeas   675.000mV   642.000mV   725.000mV
Vref   675.000mV   642.000mV   725.000mV
[Receiver Thresholds]
Vth   =  0.675V
Vth_min  =  0.6615V
Vth_max  =  0.6885V
Vinh_ac  =  0.160V
Vinh_dc  =  0.090V
Vinl_ac  = -0.160V
Vinl_dc  = -0.090V
Tslew_ac =  5.000ns |Not specified, so set to high value
Threshold_sensitivity = 0.50
Reference_supply Pullup_ref
[Temperature Range]   25.000   125.000   -40.000
[Voltage Range]   1.350V   1.283V   1.450V
[GND Clamp Reference]   0.00V   0.00V   0.00V
[Pulldown Reference]   0.00V   0.00V   0.00V
[POWER Clamp Reference]   1.350V   1.283V   1.450V
[Pullup Reference]   1.350V   1.283V   1.450V
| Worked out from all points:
|   slope of the pulldown table from 0 to 0.203 V, typ, clamps not added: 35.6 ohm
|   slope of the pullup table from 0 to 0.203 V, typ, clamps not added: 29.7 ohm
|   GND clamp passes 1 mA (typ) near -0.40 V on its own axis
|   POWER clamp passes 1 mA (typ) near -0.41 V on its own axis
|   rising waveform, R_fixture 50.000Ohm, V_fixture 1.350: 20-80 % time 87.8ps typ, 109ps min, 74.9ps max; typ from 0.609 V to 1.35 V
|   rising waveform, R_fixture 50.000Ohm, V_fixture 0: 20-80 % time 138ps typ, 164ps min, 119ps max; typ from 0.033 V to 0.8 V
|   falling waveform, R_fixture 50.000Ohm, V_fixture 1.350: 20-80 % time 149ps typ, 177ps min, 129ps max; typ from 1.35 V to 0.62 V
|   falling waveform, R_fixture 50.000Ohm, V_fixture 0: 20-80 % time 98.5ps typ, 116ps min, 85.5ps max; typ from 0.812 V to 0.038 V
[GND Clamp]
-1.318V   -433.9mA   -371.1mA   -530.2mA
-1.142V   -261.5mA   -253.4mA   -281.4mA
-1.055V   -179mA     -195.9mA   -166.2mA
-1.011V   -139.7mA   -167.8mA   -115mA
-966.7mV  -103mA     -140.2mA   -72.1mA
-922.7mV  -70.1mA    -113.7mA   -42.42mA
-878.8mV  -43.45mA   -88.35mA   -28.99mA
-790.9mV  -17.28mA   -44.22mA   -20.77mA
-703mV    -11.1mA    -16.24mA   -15.04mA
-527.3mV  -4.032mA   -3.409mA   -5.385mA
-307.6mV  -129uA     -188.8uA   -119.4uA
2.68V     1.923mA    1.635mA    2.275mA
[Power Clamp]
-1.33V    453.3mA    393.7mA    545.4mA
-1.111V   242.7mA    248mA      251.8mA
-1.023V   163mA      191mA      148.9mA
-978.8mV  125.8mA    163mA      104.3mA
-934.9mV  91.7mA     135.6mA    68.79mA
-890.9mV  62.29mA    109.3mA    47.13mA
-847mV    39.94mA    84.35mA    36.61mA
-803mV    26.56mA    61.51mA    30.49mA
-715.1mV  15.84mA    26.7mA     20.95mA
-671.2mV  12.6mA     16.6mA     16.77mA
-407.6mV  937.9uA    1.223mA    1.135mA
2.668V    -3.791mA   -3.04mA    -4.872mA
[Pulldown]
-1.318V   -4.4mA     -3.3mA     -5mA
-922.7mV  -12.81mA   -7.4mA     -14.99mA
-703mV    -14.46mA   -13.42mA   -14.07mA
-571.2mV  -13.38mA   -13.44mA   -13.07mA
-351.5mV  -9.985mA   -9.958mA   -9.957mA
747mV     18.14mA    17.68mA    18.59mA
1.582V    25.02mA    24.01mA    25.91mA
1.889V    22.58mA    20.05mA    25.16mA
2.197V    17.92mA    6.9mA      20.37mA
2.329V    12.6mA     4.3mA      18.73mA
2.461V    6.6mA      3.2mA      16.3mA
2.68V     3.4mA      2.3mA      7.6mA
[Pullup]
-1.33V    2.9mA      2.152mA    3.607mA
-1.155V   5.8mA      3.262mA    10.41mA
-978.8mV  15mA       6.03mA     17.14mA
-715.1mV  20.69mA    17.11mA    19.47mA
-451.5mV  17.37mA    16.56mA    17.25mA
251.5mV   -8.249mA   -7.87mA    -8.719mA
866.7mV   -19.34mA   -18.75mA   -20.84mA
1.702V    -22.36mA   -20.93mA   -24.89mA
1.965V    -20.49mA   -18.41mA   -23.39mA
2.185V    -19.39mA   -11.26mA   -22.3mA
2.361V    -12.5mA    -8.39mA    -21.81mA
2.668V    -7.4mA     -6.695mA   -9.748mA
[Ramp]
R_load=50.000Ohm
dV/dt_r   447.564mV/113.000ps  424.182mV/137.000ps  482.463mV/97.000ps
dV/dt_f   447.564mV/124.000ps  424.182mV/148.500ps  482.463mV/108.000ps
[Rising waveform]
R_fixture=50.000Ohm
V_fixture=1.350
V_fixture_min=1.283
V_fixture_max=1.450
0s        609.1mV    581.5mV    661.6mV
39ps      621.9mV    578.9mV    699.4mV
68ps      679mV      578.1mV    857.7mV
106ps     868.1mV    581.4mV    1.145V
125ps     985.3mV    587.2mV    1.246V
163ps     1.167V     617.6mV    1.358V
202ps     1.263V     708mV      1.407V
298ps     1.333V     1.098V     1.443V
384ps     1.345V     1.237V     1.448V
938ps     1.35V      1.283V     1.45V
[Rising waveform]
R_fixture=50.000Ohm
V_fixture=0
0s        32.7mV     30.07mV    46.57mV
39ps      28.59mV    28.48mV    58.91mV
77ps      69.51mV    25.02mV    190.5mV
135ps     264.9mV    18.89mV    493.7mV
173ps     421.5mV    29.08mV    640.6mV
269ps     671.6mV    216.5mV    813.3mV
384ps     766.6mV    544.2mV    863.6mV
480ps     787.6mV    673.4mV    874mV
623ps     796.2mV    731.1mV    878.8mV
938ps     799.5mV    747.5mV    879.7mV
[Falling waveform]
R_fixture=50.000Ohm
V_fixture=1.350
V_fixture_min=1.283
V_fixture_max=1.450
0s        1.355V     1.282V     1.455V
48ps      1.362V     1.284V     1.445V
96ps      1.303V     1.292V     1.298V
192ps     985.3mV    1.271V     910.2mV
230ps     869.4mV    1.211V     816mV
288ps     749.9mV    1.062V     737.8mV
403ps     655.6mV    780.8mV    685.3mV
499ps     633.2mV    665.2mV    675.2mV
652ps     622.9mV    608.8mV    671.1mV
938ps     619.9mV    591.5mV    669.6mV
[Falling waveform]
R_fixture=50.000Ohm
V_fixture=0
0s        812mV      753.2mV    888.2mV
29ps      799.5mV    757.5mV    859.7mV
48ps      765.5mV    760.6mV    783.2mV
77ps      656.3mV    763.2mV    586.5mV
125ps     390.1mV    743.7mV    288.8mV
163ps     228.5mV    674.9mV    169.3mV
211ps     122.8mV    504.2mV    102.8mV
288ps     64.06mV    205.7mV    66.77mV
374ps     46.49mV    79.03mV    55.91mV
938ps     38.35mV    29.79mV    52.1mV
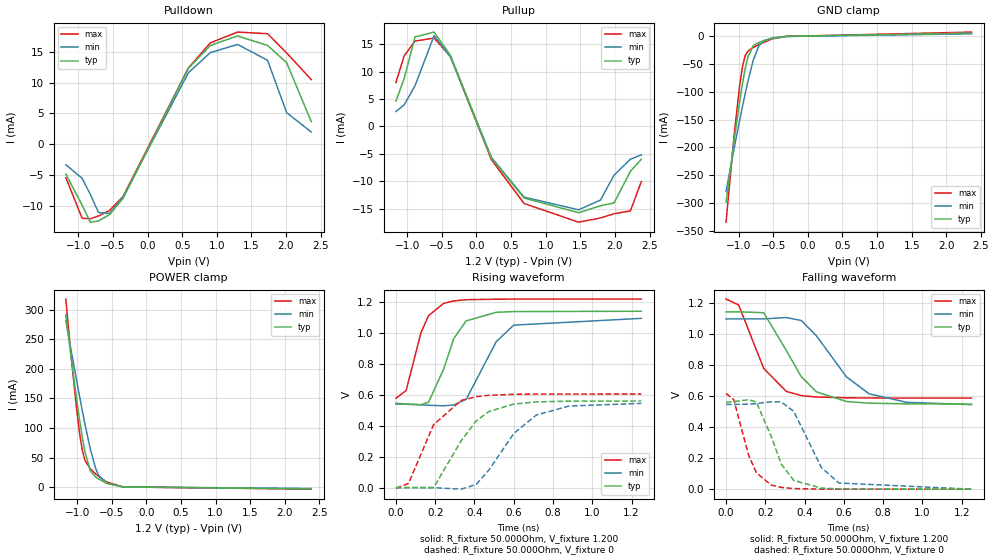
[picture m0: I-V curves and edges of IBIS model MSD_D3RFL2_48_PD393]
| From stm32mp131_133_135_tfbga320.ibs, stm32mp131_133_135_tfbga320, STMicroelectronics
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[Model] MSD_D3RFL2_48_PD393
Model_type   I/O
C_comp 2.371pF   2.287pF   2.495pF
Vinh = 820.000mV
Vinl = 380.000mV
Vmeas = 600.000mV
Vref = 600.000mV
[Model Spec]
Vinh   820.000mV   790.000mV   870.000mV
Vinl   380.000mV   350.000mV   430.000mV
Vmeas   600.000mV   570.000mV   650.000mV
Vref   600.000mV   570.000mV   650.000mV
[Receiver Thresholds]
Vth   =  0.600V
Vth_min  =  0.5880V
Vth_max  =  0.6120V
Vinh_ac  =  0.220V
Vinh_dc  =  0.130V
Vinl_ac  = -0.220V
Vinl_dc  = -0.130V
Tslew_ac =  5.000ns |Not specified, so set to high value
[Temperature Range]   25.000   125.000   -40.000
[Voltage Range]   1.200V   1.140V   1.300V
[GND Clamp Reference]   0.00V   0.00V   0.00V
[Pulldown Reference]   0.00V   0.00V   0.00V
[POWER Clamp Reference]   1.200V   1.140V   1.300V
[Pullup Reference]   1.200V   1.140V   1.300V
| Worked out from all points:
|   slope of the pulldown table from 0 to 0.18 V, typ, clamps not added: 41.6 ohm
|   slope of the pullup table from 0 to 0.18 V, typ, clamps not added: 36.2 ohm
|   GND clamp passes 1 mA (typ) near -0.40 V on its own axis
|   POWER clamp passes 1 mA (typ) near -0.42 V on its own axis
|   rising waveform, R_fixture 50.000Ohm, V_fixture 1.200: 20-80 % time 100ps typ, 129ps min, 86.2ps max; typ from 0.546 V to 1.14 V
|   rising waveform, R_fixture 50.000Ohm, V_fixture 0: 20-80 % time 167ps typ, 202ps min, 140ps max; typ from 0.001 V to 0.561 V
|   falling waveform, R_fixture 50.000Ohm, V_fixture 1.200: 20-80 % time 165ps typ, 213ps min, 130ps max; typ from 1.14 V to 0.548 V
|   falling waveform, R_fixture 50.000Ohm, V_fixture 0: 20-80 % time 102ps typ, 128ps min, 85.9ps max; typ from 0.561 V to 0 V
[GND Clamp]
-1.182V   -298.9mA   -279mA     -334.9mA
-1.064V   -186.7mA   -201.4mA   -176.7mA
-984.9mV  -117.4mA   -151.2mA   -87.93mA
-945.5mV  -86.07mA   -127mA     -55.15mA
-906.1mV  -58.69mA   -103.6mA   -35.07mA
-866.7mV  -37.21mA   -81.39mA   -26.69mA
-787.9mV  -16.61mA   -42.71mA   -20.15mA
-709.1mV  -11.16mA   -17.31mA   -15.09mA
-630.3mV  -7.681mA   -7.385mA   -10.44mA
-512.1mV  -3.463mA   -2.956mA   -4.587mA
-315.1mV  -156.4uA   -222.4uA   -144.7uA
2.364V    5.825mA    4.473mA    7.624mA
[Power Clamp]
-1.164V   291.7mA    281.8mA    318.4mA
-1.085V   218mA      230.2mA    219.3mA
-1.006V   147.9mA    179.5mA    130.4mA
-966.7mV  115.4mA    154.7mA    92.71mA
-927.3mV  85.63mA    130.4mA    63.4mA
-887.9mV  59.94mA    106.9mA    45.32mA
-809.1mV  27.44mA    63.95mA    30.69mA
-730.3mV  16.73mA    30.86mA    22.05mA
-690.9mV  13.67mA    20.06mA    18.23mA
-572.7mV  6.475mA    6.385mA    8.584mA
-336.4mV  171uA      329.6uA    200.9uA
2.382V    -2.997mA   -2.472mA   -3.554mA
[Pulldown]
-1.182V   -4.8mA     -3.3mA     -5.4mA
-945.5mV  -9.87mA    -5.5mA     -11.97mA
-827.3mV  -12.61mA   -8.1mA     -12.05mA
-709.1mV  -12.41mA   -11.06mA   -11.6mA
-551.5mV  -11.39mA   -11.19mA   -10.72mA
-354.6mV  -8.759mA   -8.528mA   -8.441mA
590.9mV   12.35mA    11.62mA    12.41mA
906.1mV   16.02mA    14.86mA    16.44mA
1.3V      17.57mA    16.19mA    18.19mA
1.733V    16.02mA    13.62mA    17.93mA
2.009V    13.24mA    5.14mA     14.81mA
2.364V    3.7mA      2mA        10.5mA
[Pullup]
-1.164V   4.6mA      2.705mA    7.977mA
-1.045V   8.7mA      3.914mA    12.86mA
-887.9mV  16.31mA    7.401mA    15.56mA
-612.1mV  17.19mA    16.55mA    16.09mA
-375.8mV  12.93mA    12.62mA    12.73mA
215.2mV   -5.799mA   -5.652mA   -6.081mA
687.9mV   -13.07mA   -12.91mA   -14.07mA
1.476V    -15.75mA   -15.22mA   -17.48mA
1.791V    -14.48mA   -13.45mA   -16.71mA
1.988V    -13.96mA   -8.899mA   -15.94mA
2.224V    -8.2mA     -5.995mA   -15.42mA
2.382V    -6mA       -5.195mA   -10.06mA
[Ramp]
R_load=50.000Ohm
dV/dt_r   346.860mV/134.500ps  330.509mV/166.500ps  372.600mV/113.000ps
dV/dt_f   346.860mV/135.000ps  330.509mV/171.500ps  372.600mV/108.000ps
[Rising waveform]
R_fixture=50.000Ohm
V_fixture=1.200
V_fixture_min=1.140
V_fixture_max=1.300
0s        546.5mV    541.7mV    578.9mV
52ps      542.5mV    540.3mV    629.6mV
128ps     537.8mV    536.4mV    1.006V
166ps     553.2mV    533.9mV    1.114V
243ps     767.9mV    530.4mV    1.194V
294ps     964.6mV    535.7mV    1.21V
358ps     1.081V     572.5mV    1.218V
511ps     1.136V     946.1mV    1.221V
600ps     1.141V     1.053V     1.222V
1.25ns    1.143V     1.097V     1.222V
[Rising waveform]
R_fixture=50.000Ohm
V_fixture=0
0s        673uV      201.8uV    -3.906mV
64ps      220.3uV    616.4uV    26.73mV
192ps     286.4uV    -4.981uV   408.3mV
332ps     303.3mV    -9.842mV   565.2mV
409ps     432.7mV    20.73mV    589.5mV
473ps     492.7mV    113.4mV    598.4mV
600ps     541.7mV    350.9mV    604.8mV
715ps     555.5mV    470.6mV    606.2mV
881ps     560.4mV    528.6mV    606.6mV
1.25ns    561.4mV    546.3mV    606.8mV
[Falling waveform]
R_fixture=50.000Ohm
V_fixture=1.200
V_fixture_min=1.140
V_fixture_max=1.300
0s        1.142V     1.097V     1.225V
64ps      1.143V     1.097V     1.187V
192ps     1.137V     1.097V     777.6mV
307ps     893.3mV    1.106V     629.8mV
383ps     725.5mV    1.087V     603.1mV
460ps     627.4mV    988.6mV    593.7mV
613ps     564.9mV    723.9mV    588.7mV
728ps     554.1mV    614.7mV    587.7mV
920ps     549.8mV    559.6mV    586.9mV
1.25ns    548.3mV    544.6mV    586.8mV
[Falling waveform]
R_fixture=50.000Ohm
V_fixture=0
0s        560.9mV    546.6mV    617mV
39ps      563.2mV    546.3mV    577.8mV
115ps     576.7mV    547.7mV    219.1mV
154ps     561mV      551.4mV    106.7mV
230ps     340.5mV    563.1mV    26.36mV
281ps     162.2mV    561.7mV    11.1mV
345ps     56.18mV    501.3mV    3.832mV
486ps     6.562mV    138.3mV    322.7uV
575ps     1.94mV     39.73mV    52.04uV
1.25ns    2.737uV    40.83uV    0V
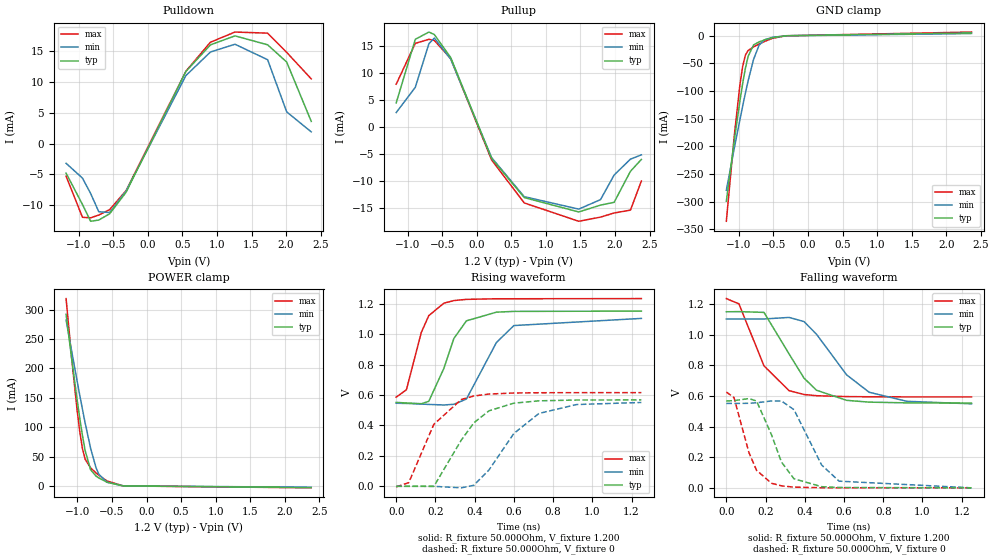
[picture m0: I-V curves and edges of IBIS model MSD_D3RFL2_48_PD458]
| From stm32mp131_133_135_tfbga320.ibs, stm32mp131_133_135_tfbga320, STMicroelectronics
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[Model] MSD_D3RFL2_48_PD458
Model_type   I/O
C_comp 2.402pF   2.316pF   2.526pF
Vinh = 820.000mV
Vinl = 380.000mV
Vmeas = 600.000mV
Vref = 600.000mV
[Model Spec]
Vinh   820.000mV   790.000mV   870.000mV
Vinl   380.000mV   350.000mV   430.000mV
Vmeas   600.000mV   570.000mV   650.000mV
Vref   600.000mV   570.000mV   650.000mV
[Receiver Thresholds]
Vth   =  0.600V
Vth_min  =  0.5880V
Vth_max  =  0.6120V
Vinh_ac  =  0.220V
Vinh_dc  =  0.130V
Vinl_ac  = -0.220V
Vinl_dc  = -0.130V
Tslew_ac =  5.000ns |Not specified, so set to high value
[Temperature Range]   25.000   125.000   -40.000
[Voltage Range]   1.200V   1.140V   1.300V
[GND Clamp Reference]   0.00V   0.00V   0.00V
[Pulldown Reference]   0.00V   0.00V   0.00V
[POWER Clamp Reference]   1.200V   1.140V   1.300V
[Pullup Reference]   1.200V   1.140V   1.300V
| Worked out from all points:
|   slope of the pulldown table from 0 to 0.18 V, typ, clamps not added: 41.6 ohm
|   slope of the pullup table from 0 to 0.18 V, typ, clamps not added: 36.3 ohm
|   GND clamp passes 1 mA (typ) near -0.40 V on its own axis
|   POWER clamp passes 1 mA (typ) near -0.41 V on its own axis
|   rising waveform, R_fixture 50.000Ohm, V_fixture 1.200: 20-80 % time 101ps typ, 129ps min, 87ps max; typ from 0.552 V to 1.15 V
|   rising waveform, R_fixture 50.000Ohm, V_fixture 0: 20-80 % time 169ps typ, 203ps min, 143ps max; typ from 0.001 V to 0.568 V
|   falling waveform, R_fixture 50.000Ohm, V_fixture 1.200: 20-80 % time 168ps typ, 216ps min, 133ps max; typ from 1.15 V to 0.554 V
|   falling waveform, R_fixture 50.000Ohm, V_fixture 0: 20-80 % time 103ps typ, 129ps min, 87.3ps max; typ from 0.567 V to 0 V
[GND Clamp]
-1.182V   -299.1mA   -279.3mA   -335.3mA
-1.064V   -187mA     -201.5mA   -177mA
-984.9mV  -117.6mA   -151.3mA   -88.16mA
-945.5mV  -86.22mA   -127.1mA   -55.37mA
-906.1mV  -58.84mA   -103.8mA   -35.26mA
-866.7mV  -37.35mA   -81.5mA    -26.87mA
-787.9mV  -16.73mA   -42.8mA    -20.29mA
-709.1mV  -11.25mA   -17.38mA   -15.2mA
-630.3mV  -7.745mA   -7.438mA   -10.54mA
-512.1mV  -3.498mA   -2.984mA   -4.633mA
-315.1mV  -158.7uA   -224.9uA   -147.6uA
2.364V    4.99mA     3.837mA    6.535mA
[Power Clamp]
-1.164V   292mA      282.1mA    318.7mA
-1.085V   218.3mA    230.5mA    219.6mA
-1.006V   148.1mA    179.7mA    130.7mA
-966.7mV  115.5mA    154.8mA    92.95mA
-927.3mV  85.81mA    130.6mA    63.61mA
-887.9mV  60.1mA     107.1mA    45.52mA
-809.1mV  27.58mA    64.08mA    30.85mA
-730.3mV  16.84mA    30.96mA    22.19mA
-690.9mV  13.77mA    20.14mA    18.34mA
-572.7mV  6.533mA    6.447mA    8.649mA
-336.4mV  178.2uA    339.3uA    207.6uA
2.382V    -2.569mA   -2.119mA   -3.047mA
[Pulldown]
-1.182V   -4.8mA     -3.2mA     -5.3mA
-945.5mV  -9.87mA    -5.6mA     -11.96mA
-827.3mV  -12.61mA   -8.09mA    -12.05mA
-709.1mV  -12.41mA   -11.06mA   -11.6mA
-551.5mV  -11.39mA   -11.19mA   -10.72mA
-315.1mV  -7.913mA   -7.7mA     -7.643mA
551.5mV   11.72mA    11.04mA    11.75mA
906.1mV   16.02mA    14.86mA    16.45mA
1.261V    17.48mA    16.12mA    18.1mA
1.733V    16.03mA    13.61mA    17.92mA
2.009V    13.23mA    5.14mA     14.8mA
2.364V    3.6mA      1.9mA      10.5mA
[Pullup]
-1.164V   4.5mA      2.709mA    7.977mA
-887.9mV  16.31mA    7.401mA    15.56mA
-690.9mV  17.66mA    15.5mA     16.31mA
-612.1mV  17.19mA    16.54mA    16.09mA
-375.8mV  12.93mA    12.63mA    12.73mA
215.2mV   -5.799mA   -5.653mA   -6.08mA
687.9mV   -13.08mA   -12.91mA   -14.07mA
1.476V    -15.75mA   -15.22mA   -17.48mA
1.791V    -14.48mA   -13.46mA   -16.71mA
1.988V    -13.96mA   -8.894mA   -15.94mA
2.224V    -8.2mA     -5.943mA   -15.41mA
2.382V    -6mA       -5.148mA   -10.01mA
[Ramp]
R_load=50.000Ohm
dV/dt_r   349.650mV/135.000ps  332.489mV/166.500ps  376.380mV/114.500ps
dV/dt_f   349.650mV/136.500ps  332.459mV/174.000ps  376.380mV/110.000ps
[Rising waveform]
R_fixture=50.000Ohm
V_fixture=1.200
V_fixture_min=1.140
V_fixture_max=1.300
0s        551.5mV    545.9mV    585.8mV
52ps      547.5mV    544.5mV    634.2mV
128ps     542.8mV    540.6mV    1.011V
166ps     558.5mV    538.1mV    1.121V
243ps     774.5mV    534.4mV    1.203V
294ps     971.2mV    539mV      1.22V
358ps     1.087V     573.4mV    1.228V
511ps     1.144V     944.7mV    1.232V
600ps     1.149V     1.056V     1.232V
1.25ns    1.151V     1.103V     1.233V
[Rising waveform]
R_fixture=50.000Ohm
V_fixture=0
0s        673.6uV    187.8uV    -3.713mV
64ps      222.8uV    597.8uV    24.54mV
192ps     261.6uV    70.67uV    407.9mV
332ps     304mV      -9.7mV     570.5mV
396ps     417.4mV    7.142mV    593.5mV
473ps     496.1mV    107.8mV    606.1mV
600ps     546.5mV    347.6mV    613.1mV
728ps     561.7mV    479mV      614.8mV
920ps     566.9mV    537.4mV    615.3mV
1.25ns    567.7mV    550.9mV    615.5mV
[Falling waveform]
R_fixture=50.000Ohm
V_fixture=1.200
V_fixture_min=1.140
V_fixture_max=1.300
0s        1.15V      1.103V     1.236V
64ps      1.151V     1.103V     1.202V
192ps     1.146V     1.103V     796.6mV
320ps     874.3mV    1.113V     634.7mV
396ps     716.7mV    1.086V     609.7mV
460ps     637.4mV    1.003V     601.7mV
613ps     571.5mV    738.5mV    595.9mV
728ps     559.8mV    624.4mV    594.8mV
920ps     555mV      565.2mV    594mV
1.25ns    553.5mV    548.8mV    593.8mV
[Falling waveform]
R_fixture=50.000Ohm
V_fixture=0
0s        567.3mV    551.4mV    625.6mV
39ps      569.6mV    551.1mV    589.6mV
115ps     583mV      552.2mV    231.2mV
154ps     567.5mV    555.7mV    114.7mV
230ps     347.6mV    567.4mV    30.07mV
281ps     168.8mV    567.1mV    12.8mV
345ps     59.12mV    510.6mV    4.495mV
486ps     7.388mV    148.9mV    565.7uV
575ps     2.291mV    43.53mV    135.9uV
1.25ns    3.29uV     47.45uV    -1.069uV
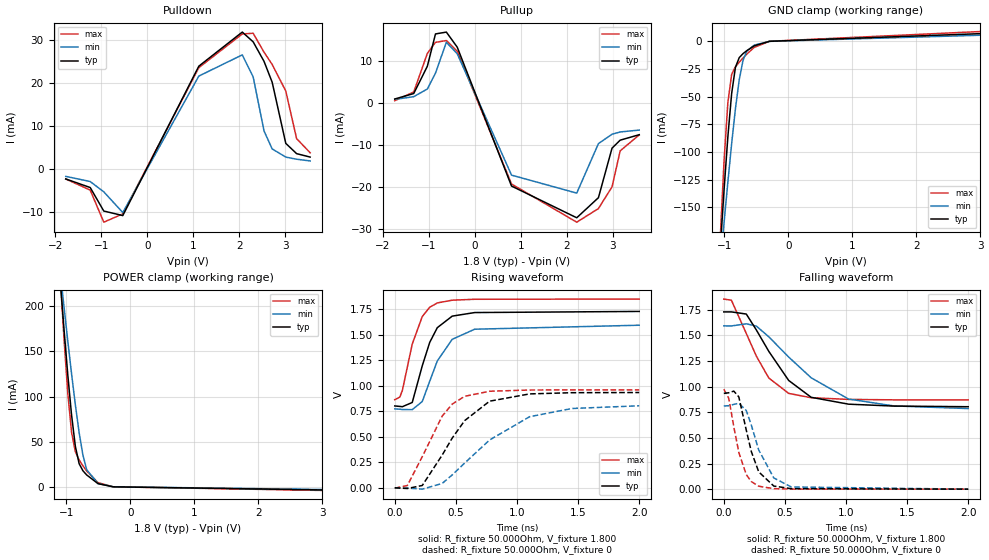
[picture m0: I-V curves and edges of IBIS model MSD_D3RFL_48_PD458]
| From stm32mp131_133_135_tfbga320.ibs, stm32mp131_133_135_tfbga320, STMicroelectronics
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[Model] MSD_D3RFL_48_PD458
Model_type   I/O
C_comp 2.372pF   2.289pF   2.495pF
Vinh = 1.440V
Vinl = 360.000mV
Vmeas = 900.000mV
Vref = 900.000mV
[Model Spec]
Vinh   1.440V   1.365V   1.515V
Vinl   360.000mV   285.000mV   435.000mV
Vmeas   900.000mV   825.000mV   975.000mV
Vref   900.000mV   825.000mV   975.000mV
[Temperature Range]   25.000   125.000   -40.000
[Voltage Range]   1.800V   1.650V   1.950V
[GND Clamp Reference]   0.00V   0.00V   0.00V
[Pulldown Reference]   0.00V   0.00V   0.00V
[POWER Clamp Reference]   1.800V   1.650V   1.950V
[Pullup Reference]   1.800V   1.650V   1.950V
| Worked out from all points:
|   slope of the pulldown table from 0 to 0.27 V, typ, clamps not added: 41 ohm
|   slope of the pullup table from 0 to 0.27 V, typ, clamps not added: 32.3 ohm
|   GND clamp passes 1 mA (typ) near -0.40 V on its own axis
|   POWER clamp passes 1 mA (typ) near -0.41 V on its own axis
|   rising waveform, R_fixture 50.000Ohm, V_fixture 1.800: 20-80 % time 150ps typ, 192ps min, 133ps max; typ from 0.802 V to 1.73 V
|   rising waveform, R_fixture 50.000Ohm, V_fixture 0: 20-80 % time 319ps typ, 496ps min, 246ps max; typ from 0.001 V to 0.934 V
|   falling waveform, R_fixture 50.000Ohm, V_fixture 1.800: 20-80 % time 319ps typ, 470ps min, 243ps max; typ from 1.73 V to 0.803 V
|   falling waveform, R_fixture 50.000Ohm, V_fixture 0: 20-80 % time 124ps typ, 155ps min, 106ps max; typ from 0.933 V to 0 V
[GND Clamp]
-1.773V   -889.8mA   -681.1mA   -1.193A
-1.064V   -186.9mA   -201.5mA   -177mA
-1.005V   -134.2mA   -163.7mA   -108.1mA
-945.5mV  -86.21mA   -127.1mA   -55.36mA
-886.4mV  -47.21mA   -92.42mA   -30.04mA
-827.3mV  -23.55mA   -60.94mA   -23.09mA
-768.2mV  -14.83mA   -34.89mA   -18.98mA
-709.1mV  -11.24mA   -17.37mA   -15.21mA
-650mV    -8.564mA   -8.917mA   -11.66mA
-531.8mV  -4.108mA   -3.477mA   -5.489mA
-295.4mV  -92.42uA   -147.5uA   -77.49uA
3.545V    7.956mA    6.311mA    10.19mA
[Power Clamp]
-1.745V   859.4mA    673.9mA    1.126A
-1.095V   228.1mA    237.7mA    232.9mA
-1.036V   174.5mA    199.3mA    163.9mA
-977.3mV  124.2mA    161.7mA    103.6mA
-918.2mV  79.53mA    125.3mA    60.41mA
-859.1mV  44.93mA    90.96mA    38.93mA
-800mV    25.67mA    60.11mA    29.88mA
-740.9mV  17.83mA    35.28mA    23.34mA
-681.8mV  13.15mA    18.9mA     17.56mA
-504.5mV  3.527mA    3.63mA     4.631mA
-268.2mV  25.02uA    91.72uA    29.52uA
3.573V    -4.026mA   -3.499mA   -4.7mA
[Pulldown]
-1.773V   -2.4mA     -1.8mA     -2.4mA
-1.241V   -4.4mA     -3mA       -5mA
-945.5mV  -9.88mA    -5.4mA     -12.48mA
-531.8mV  -10.94mA   -10.23mA   -10.54mA
1.123V    23.9mA     21.59mA    23.56mA
2.068V    31.84mA    26.53mA    31.41mA
2.305V    29.56mA    21.37mA    31.56mA
2.541V    25.01mA    8.8mA      27.15mA
2.718V    20.16mA    4.6mA      24.29mA
3.014V    5.9mA      2.7mA      18.1mA
3.25V     3.5mA      2.2mA      7mA
3.545V    2.7mA      1.8mA      3.7mA
[Pullup]
-1.745V   1mA        900uA      600uA
-1.332V   2.3mA      1.554mA    2.669mA
-1.036V   8.8mA      3.377mA    11.85mA
-859.1mV  16.48mA    7.155mA    14.48mA
-622.7mV  16.92mA    14.49mA    14.91mA
-386.4mV  13.34mA    11.77mA    12.34mA
795.5mV   -19.72mA   -17.12mA   -19.23mA
2.214V    -27.27mA   -21.4mA    -28.32mA
2.686V    -22.49mA   -9.623mA   -25.08mA
2.982V    -10.7mA    -7.392mA   -19.91mA
3.159V    -8.8mA     -6.846mA   -11.35mA
3.573V    -7.5mA     -6.4mA     -7.554mA
[Ramp]
R_load=50.000Ohm
dV/dt_r   557.580mV/235.000ps  486.179mV/344.500ps  581.340mV/189.500ps
dV/dt_f   557.489mV/222.000ps  485.367mV/313.500ps  581.340mV/175.000ps
[Rising waveform]
R_fixture=50.000Ohm
V_fixture=1.800
V_fixture_min=1.650
V_fixture_max=1.950
0s        802.2mV    773.6mV    863.2mV
41ps      797.6mV    769.9mV    888.1mV
62ps      794.6mV    767.2mV    953mV
143ps     836.1mV    765.9mV    1.408V
225ps     1.195V     845.5mV    1.677V
286ps     1.424V     1.044V     1.768V
348ps     1.568V     1.242V     1.81V
470ps     1.681V     1.454V     1.837V
654ps     1.716V     1.553V     1.846V
2ns       1.727V     1.592V     1.848V
[Rising waveform]
R_fixture=50.000Ohm
V_fixture=0
0s        1.047mV    1.11mV     -2.545mV
103ps     -5.793mV   -1.219mV   23.85mV
225ps     23.72mV    -12.28mV   305.7mV
388ps     321.4mV    43.89mV    702.7mV
470ps     487.7mV    126.9mV    820mV
572ps     658.7mV    243.5mV    896.3mV
776ps     848.8mV    469.1mV    945.9mV
1.103ns   919.8mV    696.6mV    957.9mV
1.45ns    931.7mV    777.2mV    959.2mV
2ns       933.5mV    803.6mV    959.4mV
[Falling waveform]
R_fixture=50.000Ohm
V_fixture=1.800
V_fixture_min=1.650
V_fixture_max=1.950
0s        1.727V     1.591V     1.852V
62ps      1.727V     1.59V      1.841V
184ps     1.706V     1.611V     1.517V
266ps     1.552V     1.589V     1.297V
368ps     1.343V     1.485V     1.083V
531ps     1.059V     1.287V     933mV
715ps     894.9mV    1.085V     890.9mV
1.021ns   828mV      877.9mV    874.4mV
1.389ns   809.5mV    811.3mV    870.2mV
2ns       803.2mV    785.2mV    869.4mV
[Falling waveform]
R_fixture=50.000Ohm
V_fixture=0
0s        932.8mV    809.9mV    974.4mV
41ps      939.3mV    813.3mV    884.1mV
82ps      955.3mV    825.9mV    607.1mV
123ps     898.7mV    836.9mV    357.3mV
184ps     575.2mV    766.4mV    141.8mV
225ps     367.1mV    624.4mV    74.22mV
286ps     168.4mV    381.2mV    28.51mV
409ps     30.37mV    109.5mV    4.725mV
552ps     5.042mV    21.55mV    988.2uV
2ns       14.44uV    85.3uV     0V
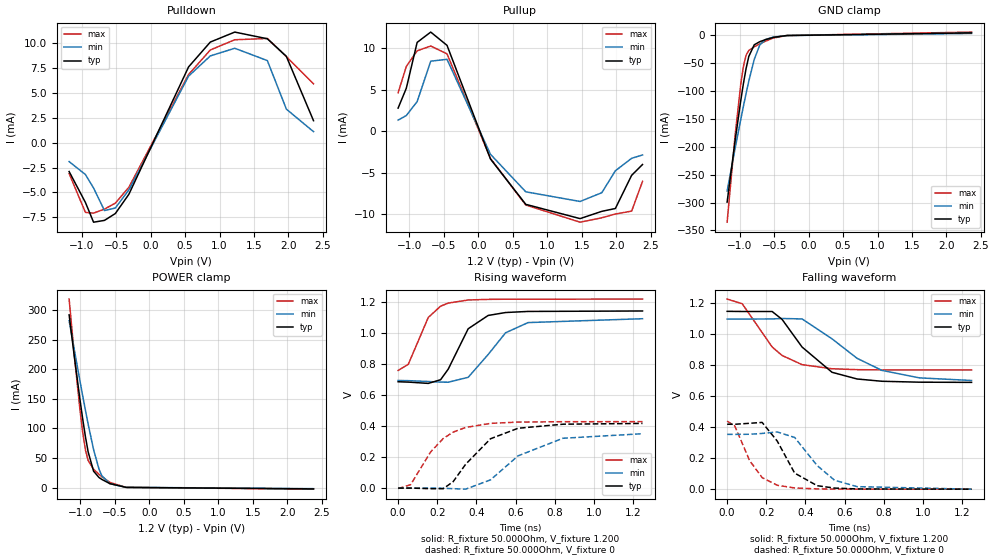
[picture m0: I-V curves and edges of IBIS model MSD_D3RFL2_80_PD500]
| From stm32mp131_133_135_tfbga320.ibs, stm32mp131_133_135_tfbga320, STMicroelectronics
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[Model] MSD_D3RFL2_80_PD500
Model_type   I/O
C_comp 2.418pF   2.333pF   2.542pF
Vinh = 820.000mV
Vinl = 380.000mV
Vmeas = 600.000mV
Vref = 600.000mV
[Model Spec]
Vinh   820.000mV   790.000mV   870.000mV
Vinl   380.000mV   350.000mV   430.000mV
Vmeas   600.000mV   570.000mV   650.000mV
Vref   600.000mV   570.000mV   650.000mV
[Receiver Thresholds]
Vth   =  0.600V
Vth_min  =  0.5880V
Vth_max  =  0.6120V
Vinh_ac  =  0.220V
Vinh_dc  =  0.130V
Vinl_ac  = -0.220V
Vinl_dc  = -0.130V
Tslew_ac =  5.000ns |Not specified, so set to high value
[Temperature Range]   25.000   125.000   -40.000
[Voltage Range]   1.200V   1.140V   1.300V
[GND Clamp Reference]   0.00V   0.00V   0.00V
[Pulldown Reference]   0.00V   0.00V   0.00V
[POWER Clamp Reference]   1.200V   1.140V   1.300V
[Pullup Reference]   1.200V   1.140V   1.300V
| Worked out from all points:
|   slope of the pulldown table from 0 to 0.18 V, typ, clamps not added: 63.6 ohm
|   slope of the pullup table from 0 to 0.18 V, typ, clamps not added: 52.8 ohm
|   GND clamp passes 1 mA (typ) near -0.40 V on its own axis
|   POWER clamp passes 1 mA (typ) near -0.41 V on its own axis
|   rising waveform, R_fixture 50.000Ohm, V_fixture 1.200: 20-80 % time 116ps typ, 150ps min, 101ps max; typ from 0.688 V to 1.15 V
|   rising waveform, R_fixture 50.000Ohm, V_fixture 0: 20-80 % time 187ps typ, 232ps min, 160ps max; typ from 0 V to 0.418 V
|   falling waveform, R_fixture 50.000Ohm, V_fixture 1.200: 20-80 % time 192ps typ, 269ps min, 173ps max; typ from 1.15 V to 0.688 V
|   falling waveform, R_fixture 50.000Ohm, V_fixture 0: 20-80 % time 115ps typ, 147ps min, 106ps max; typ from 0.418 V to 0 V
[GND Clamp]
-1.182V   -299.2mA   -279.4mA   -335.3mA
-1.064V   -187.1mA   -201.6mA   -177.2mA
-984.9mV  -117.6mA   -151.5mA   -88.27mA
-945.5mV  -86.31mA   -127.1mA   -55.47mA
-906.1mV  -58.92mA   -103.8mA   -35.36mA
-866.7mV  -37.41mA   -81.56mA   -26.95mA
-787.9mV  -16.78mA   -42.84mA   -20.37mA
-709.1mV  -11.29mA   -17.41mA   -15.26mA
-630.3mV  -7.777mA   -7.464mA   -10.57mA
-512.1mV  -3.515mA   -2.998mA   -4.657mA
-315.1mV  -159.9uA   -226.2uA   -149.3uA
2.364V    4.576mA    3.518mA    5.996mA
[Power Clamp]
-1.164V   292.1mA    282.3mA    318.9mA
-1.085V   218.4mA    230.6mA    219.7mA
-1.006V   148.2mA    179.8mA    130.8mA
-966.7mV  115.7mA    154.9mA    93.06mA
-927.3mV  85.9mA     130.7mA    63.72mA
-887.9mV  60.18mA    107.2mA    45.62mA
-809.1mV  27.64mA    64.14mA    30.93mA
-730.3mV  16.89mA    31.01mA    22.25mA
-690.9mV  13.81mA    20.19mA    18.4mA
-572.7mV  6.565mA    6.472mA    8.682mA
-336.4mV  180.4uA    344.1uA    207.9uA
2.382V    -2.355mA   -1.942mA   -2.793mA
[Pulldown]
-1.182V   -2.9mA     -1.9mA     -3.1mA
-945.5mV  -6mA       -3.2mA     -7mA
-827.3mV  -7.98mA    -4.55mA    -7.07mA
-669.7mV  -7.8mA     -6.81mA    -6.67mA
-512.1mV  -7.115mA   -6.561mA   -6.071mA
-315.1mV  -5.18mA    -4.739mA   -4.478mA
551.5mV   7.6mA      6.678mA    6.842mA
866.7mV   10.09mA    8.701mA    9.296mA
1.221V    11.09mA    9.466mA    10.32mA
1.694V    10.42mA    8.231mA    10.45mA
1.97V     8.65mA     3.36mA     8.63mA
2.364V    2.2mA      1.1mA      5.9mA
[Pullup]
-1.164V   2.8mA      1.352mA    4.654mA
-1.045V   5.2mA      1.905mA    7.823mA
-887.9mV  10.72mA    3.587mA    9.704mA
-690.9mV  11.96mA    8.455mA    10.28mA
-454.5mV  10.36mA    8.68mA     9.337mA
175.8mV   -3.335mA   -2.766mA   -3.264mA
687.9mV   -8.798mA   -7.288mA   -8.88mA
1.476V    -10.52mA   -8.453mA   -10.95mA
1.791V    -9.643mA   -7.398mA   -10.42mA
1.988V    -9.3mA     -4.754mA   -9.962mA
2.224V    -5.3mA     -3.248mA   -9.615mA
2.382V    -4mA       -2.848mA   -6.031mA
[Ramp]
R_load=50.000Ohm
dV/dt_r   262.650mV/151.500ps  225.749mV/194.000ps  265.170mV/130.500ps
dV/dt_f   262.620mV/154.500ps  225.689mV/211.500ps  265.170mV/139.500ps
[Rising waveform]
R_fixture=50.000Ohm
V_fixture=1.200
V_fixture_min=1.140
V_fixture_max=1.300
0s        687.6mV    696mV      760.7mV
52ps      685.4mV    694.7mV    800.4mV
154ps     677mV      689.2mV    1.103V
217ps     700.8mV    685.3mV    1.176V
256ps     769mV      684.6mV    1.196V
358ps     1.03V      716.2mV    1.216V
460ps     1.116V     863.5mV    1.22V
549ps     1.135V     1.004V     1.221V
664ps     1.142V     1.07V      1.221V
1.249ns   1.145V     1.095V     1.222V
[Rising waveform]
R_fixture=50.000Ohm
V_fixture=0
0s        149.9uV    95.13uV    -2.66mV
64ps      579.4uV    357.7uV    22.65mV
166ps     -3.429mV   479.5uV    233.8mV
230ps     -3.778mV   -700.9uV   320.2mV
281ps     41.77mV    -3.208mV   361.9mV
345ps     154.2mV    -6.506mV   392.4mV
472ps     319.2mV    53.49mV    418.6mV
613ps     387.1mV    208.8mV    426.9mV
842ps     413.3mV    322.4mV    429.5mV
1.249ns   418.4mV    351.8mV    429.9mV
[Falling waveform]
R_fixture=50.000Ohm
V_fixture=1.200
V_fixture_min=1.140
V_fixture_max=1.300
0s        1.145V     1.095V     1.224V
77ps      1.144V     1.095V     1.194V
230ps     1.144V     1.096V     915.6mV
281ps     1.093V     1.099V     860.7mV
383ps     915.1mV    1.096V     801.8mV
536ps     752.6mV    968.2mV    775.3mV
664ps     709.4mV    842.6mV    769.5mV
791ps     694.7mV    764.6mV    768.1mV
983ps     688.8mV    716.6mV    767.6mV
1.249ns   687.6mV    699.7mV    767.5mV
[Falling waveform]
R_fixture=50.000Ohm
V_fixture=0
0s        418mV      353mV      438mV
39ps      417.8mV    352.7mV    407.4mV
115ps     424.2mV    353.5mV    183.7mV
179ps     429.7mV    358.8mV    74.45mV
256ps     309.9mV    368.5mV    25.22mV
345ps     103.7mV    333mV      7.751mV
460ps     22.35mV    152mV      1.733mV
549ps     6.967mV    57.61mV    494.6uV
664ps     1.499mV    16.2mV     74.51uV
1.249ns   -2.824uV   17.41uV    5.767uV
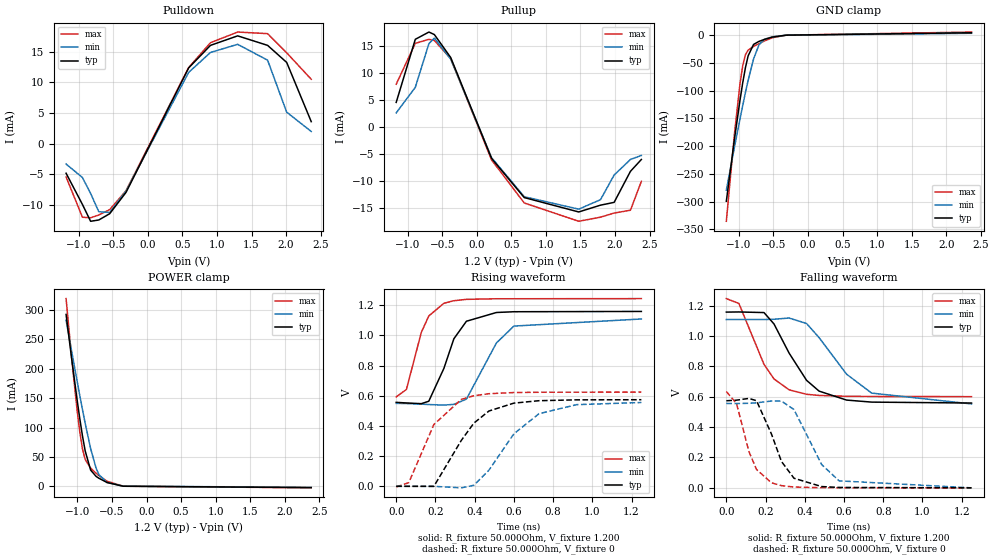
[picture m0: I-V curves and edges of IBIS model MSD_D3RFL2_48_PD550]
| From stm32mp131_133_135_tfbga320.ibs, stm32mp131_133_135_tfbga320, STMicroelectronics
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[Model] MSD_D3RFL2_48_PD550
Model_type   I/O
C_comp 2.431pF   2.345pF   2.556pF
Vinh = 820.000mV
Vinl = 380.000mV
Vmeas = 600.000mV
Vref = 600.000mV
[Model Spec]
Vinh   820.000mV   790.000mV   870.000mV
Vinl   380.000mV   350.000mV   430.000mV
Vmeas   600.000mV   570.000mV   650.000mV
Vref   600.000mV   570.000mV   650.000mV
[Receiver Thresholds]
Vth   =  0.600V
Vth_min  =  0.5880V
Vth_max  =  0.6120V
Vinh_ac  =  0.220V
Vinh_dc  =  0.130V
Vinl_ac  = -0.220V
Vinl_dc  = -0.130V
Tslew_ac =  5.000ns |Not specified, so set to high value
[Temperature Range]   25.000   125.000   -40.000
[Voltage Range]   1.200V   1.140V   1.300V
[GND Clamp Reference]   0.00V   0.00V   0.00V
[Pulldown Reference]   0.00V   0.00V   0.00V
[POWER Clamp Reference]   1.200V   1.140V   1.300V
[Pullup Reference]   1.200V   1.140V   1.300V
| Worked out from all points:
|   slope of the pulldown table from 0 to 0.18 V, typ, clamps not added: 41.6 ohm
|   slope of the pullup table from 0 to 0.18 V, typ, clamps not added: 36.3 ohm
|   GND clamp passes 1 mA (typ) near -0.40 V on its own axis
|   POWER clamp passes 1 mA (typ) near -0.41 V on its own axis
|   rising waveform, R_fixture 50.000Ohm, V_fixture 1.200: 20-80 % time 101ps typ, 129ps min, 87.8ps max; typ from 0.557 V to 1.16 V
|   rising waveform, R_fixture 50.000Ohm, V_fixture 0: 20-80 % time 171ps typ, 205ps min, 145ps max; typ from 0.001 V to 0.574 V
|   falling waveform, R_fixture 50.000Ohm, V_fixture 1.200: 20-80 % time 171ps typ, 219ps min, 136ps max; typ from 1.16 V to 0.559 V
|   falling waveform, R_fixture 50.000Ohm, V_fixture 0: 20-80 % time 105ps typ, 130ps min, 88.7ps max; typ from 0.574 V to 0 V
[GND Clamp]
-1.182V   -299.4mA   -279.4mA   -335.5mA
-1.064V   -187.2mA   -201.7mA   -177.2mA
-984.9mV  -117.7mA   -151.5mA   -88.38mA
-945.5mV  -86.38mA   -127.3mA   -55.57mA
-906.1mV  -58.98mA   -103.8mA   -35.45mA
-866.7mV  -37.48mA   -81.61mA   -27.05mA
-787.9mV  -16.83mA   -42.88mA   -20.43mA
-709.1mV  -11.34mA   -17.45mA   -15.32mA
-630.3mV  -7.809mA   -7.49mA    -10.62mA
-512.1mV  -3.532mA   -3.013mA   -4.68mA
-315.1mV  -161.1uA   -227.4uA   -151.1uA
2.364V    4.162mA    3.192mA    5.446mA
[Power Clamp]
-1.164V   292.2mA    282.4mA    319.1mA
-1.085V   218.5mA    230.7mA    219.9mA
-1.006V   148.3mA    179.9mA    131mA
-966.7mV  115.8mA    155mA      93.19mA
-927.3mV  85.99mA    130.7mA    63.83mA
-887.9mV  60.26mA    107.3mA    45.72mA
-809.1mV  27.71mA    64.21mA    31.02mA
-730.3mV  16.94mA    31.06mA    22.31mA
-690.9mV  13.86mA    20.24mA    18.46mA
-572.7mV  6.594mA    6.506mA    8.718mA
-336.4mV  182.6uA    351.4uA    213.2uA
2.382V    -2.141mA   -1.766mA   -2.539mA
[Pulldown]
-1.182V   -4.8mA     -3.3mA     -5.4mA
-945.5mV  -9.88mA    -5.5mA     -11.96mA
-827.3mV  -12.62mA   -8.09mA    -12.05mA
-709.1mV  -12.41mA   -11.06mA   -11.6mA
-551.5mV  -11.39mA   -11.19mA   -10.73mA
-315.1mV  -7.913mA   -7.7mA     -7.643mA
590.9mV   12.35mA    11.62mA    12.41mA
906.1mV   16.02mA    14.86mA    16.45mA
1.3V      17.57mA    16.19mA    18.19mA
1.733V    16.02mA    13.61mA    17.93mA
2.009V    13.24mA    5.14mA     14.81mA
2.364V    3.6mA      2mA        10.5mA
[Pullup]
-1.164V   4.6mA      2.657mA    7.977mA
-887.9mV  16.31mA    7.401mA    15.56mA
-690.9mV  17.66mA    15.51mA    16.31mA
-612.1mV  17.19mA    16.54mA    16.09mA
-375.8mV  12.93mA    12.63mA    12.74mA
215.2mV   -5.8mA     -5.653mA   -6.08mA
687.9mV   -13.07mA   -12.91mA   -14.07mA
1.476V    -15.74mA   -15.22mA   -17.47mA
1.791V    -14.48mA   -13.46mA   -16.71mA
1.988V    -13.96mA   -8.894mA   -15.94mA
2.224V    -8.2mA     -5.995mA   -15.42mA
2.382V    -6mA       -5.248mA   -10.06mA
[Ramp]
R_load=50.000Ohm
dV/dt_r   352.440mV/137.000ps  334.499mV/168.000ps  380.130mV/116.500ps
dV/dt_f   352.440mV/138.500ps  334.469mV/176.500ps  380.130mV/112.500ps
[Rising waveform]
R_fixture=50.000Ohm
V_fixture=1.200
V_fixture_min=1.140
V_fixture_max=1.300
0s        556.7mV    550.1mV    592.9mV
52ps      552.6mV    548.7mV    642mV
128ps     547.9mV    544.8mV    1.02V
166ps     563.9mV    542.2mV    1.129V
243ps     781.2mV    538.5mV    1.213V
294ps     977.8mV    543.1mV    1.23V
358ps     1.094V     578mV      1.239V
511ps     1.152V     950.2mV    1.243V
600ps     1.157V     1.062V     1.243V
1.25ns    1.159V     1.109V     1.244V
[Rising waveform]
R_fixture=50.000Ohm
V_fixture=0
0s        674.1uV    187.9uV    -3.712mV
64ps      225.2uV    598.4uV    24.53mV
192ps     236.6uV    73.57uV    409.8mV
332ps     304.7mV    -9.712mV   576.3mV
396ps     419.2mV    7.111mV    600.5mV
473ps     499.4mV    107.8mV    614mV
600ps     551.5mV    348.5mV    621.6mV
728ps     567.6mV    481.5mV    623.5mV
920ps     573.2mV    541.4mV    624.1mV
1.25ns    574.1mV    555.6mV    624.4mV
[Falling waveform]
R_fixture=50.000Ohm
V_fixture=1.200
V_fixture_min=1.140
V_fixture_max=1.300
0s        1.158V     1.109V     1.247V
64ps      1.159V     1.109V     1.215V
192ps     1.155V     1.109V     813.9mV
243ps     1.08V      1.111V     717.6mV
320ps     888mV      1.119V     646mV
409ps     708.6mV    1.083V     616.4mV
473ps     637.3mV    989.8mV    608.8mV
613ps     578.3mV    749.1mV    603.3mV
741ps     564.9mV    624.3mV    602.1mV
1.25ns    558.8mV    553mV      601mV
[Falling waveform]
R_fixture=50.000Ohm
V_fixture=0
0s        573.8mV    556.2mV    634.4mV
52ps      577.8mV    555.8mV    555.9mV
115ps     589.3mV    557mV      239.6mV
154ps     574.1mV    560.5mV    120.9mV
230ps     354.9mV    572mV      33.14mV
281ps     173.9mV    571.8mV    14.55mV
345ps     63.1mV     515.8mV    5.328mV
486ps     8.368mV    153.5mV    675.4uV
575ps     2.674mV    45.95mV    253.6uV
1.25ns    4.269uV    54.19uV    1.437uV
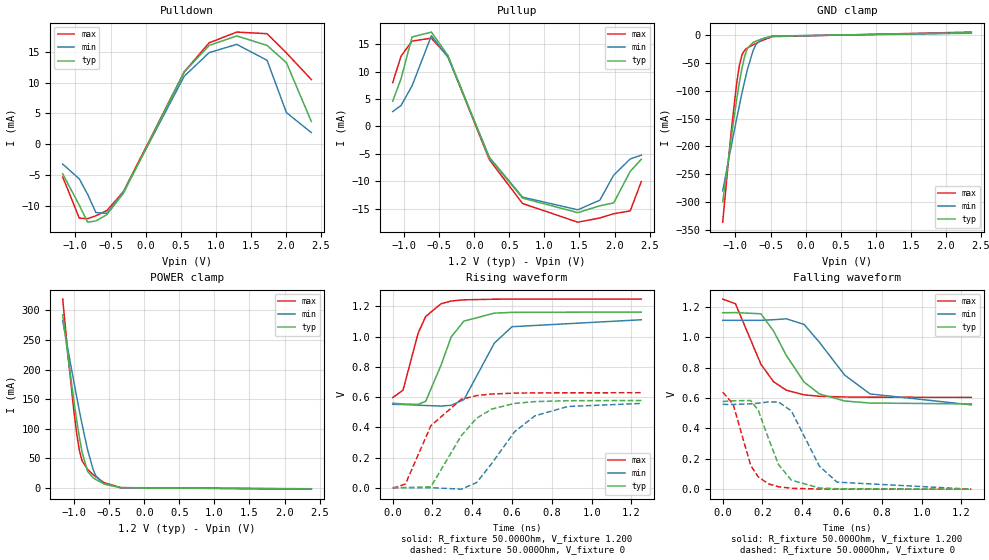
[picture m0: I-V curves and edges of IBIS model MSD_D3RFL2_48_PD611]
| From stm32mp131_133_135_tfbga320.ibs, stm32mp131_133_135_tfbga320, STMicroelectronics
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[Model] MSD_D3RFL2_48_PD611
Model_type   I/O
C_comp 2.448pF   2.362pF   2.573pF
Vinh = 820.000mV
Vinl = 380.000mV
Vmeas = 600.000mV
Vref = 600.000mV
[Model Spec]
Vinh   820.000mV   790.000mV   870.000mV
Vinl   380.000mV   350.000mV   430.000mV
Vmeas   600.000mV   570.000mV   650.000mV
Vref   600.000mV   570.000mV   650.000mV
[Receiver Thresholds]
Vth   =  0.600V
Vth_min  =  0.5880V
Vth_max  =  0.6120V
Vinh_ac  =  0.220V
Vinh_dc  =  0.130V
Vinl_ac  = -0.220V
Vinl_dc  = -0.130V
Tslew_ac =  5.000ns |Not specified, so set to high value
[Temperature Range]   25.000   125.000   -40.000
[Voltage Range]   1.200V   1.140V   1.300V
[GND Clamp Reference]   0.00V   0.00V   0.00V
[Pulldown Reference]   0.00V   0.00V   0.00V
[POWER Clamp Reference]   1.200V   1.140V   1.300V
[Pullup Reference]   1.200V   1.140V   1.300V
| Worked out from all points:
|   slope of the pulldown table from 0 to 0.18 V, typ, clamps not added: 41.6 ohm
|   slope of the pullup table from 0 to 0.18 V, typ, clamps not added: 36.3 ohm
|   GND clamp passes 1 mA (typ) near -0.40 V on its own axis
|   POWER clamp passes 1 mA (typ) near -0.41 V on its own axis
|   rising waveform, R_fixture 50.000Ohm, V_fixture 1.200: 20-80 % time 103ps typ, 130ps min, 87.8ps max; typ from 0.559 V to 1.16 V
|   rising waveform, R_fixture 50.000Ohm, V_fixture 0: 20-80 % time 172ps typ, 205ps min, 146ps max; typ from 0.001 V to 0.577 V
|   falling waveform, R_fixture 50.000Ohm, V_fixture 1.200: 20-80 % time 173ps typ, 220ps min, 138ps max; typ from 1.16 V to 0.561 V
|   falling waveform, R_fixture 50.000Ohm, V_fixture 0: 20-80 % time 106ps typ, 131ps min, 89.4ps max; typ from 0.577 V to 0 V
[GND Clamp]
-1.182V   -299.5mA   -279.6mA   -335.7mA
-1.064V   -187.3mA   -201.7mA   -177.4mA
-984.9mV  -117.8mA   -151.5mA   -88.49mA
-945.5mV  -86.46mA   -127.3mA   -55.67mA
-906.1mV  -59.05mA   -103.8mA   -35.55mA
-866.7mV  -37.55mA   -81.66mA   -27.13mA
-827.3mV  -23.74mA   -61.1mA    -23.33mA
-748.5mV  -13.56mA   -28.1mA    -17.89mA
-709.1mV  -11.37mA   -17.48mA   -15.38mA
-630.3mV  -7.842mA   -7.517mA   -10.66mA
-472.7mV  -2.44mA    -2.145mA   -3.165mA
2.364V    3.741mA    2.874mA    4.907mA
[Power Clamp]
-1.164V   292.4mA    282.5mA    319.2mA
-1.085V   218.6mA    230.8mA    220mA
-1.006V   148.4mA    180mA      131.1mA
-966.7mV  115.9mA    155.1mA    93.3mA
-927.3mV  86.08mA    130.8mA    63.93mA
-887.9mV  60.35mA    107.3mA    45.81mA
-809.1mV  27.78mA    64.27mA    31.09mA
-730.3mV  17.01mA    31.11mA    22.38mA
-690.9mV  13.91mA    20.28mA    18.51mA
-572.7mV  6.625mA    6.535mA    8.753mA
-336.4mV  188.6uA    356.2uA    213.6uA
2.382V    -1.927mA   -1.589mA   -2.285mA
[Pulldown]
-1.182V   -4.8mA     -3.2mA     -5.3mA
-945.5mV  -9.87mA    -5.6mA     -11.96mA
-827.3mV  -12.62mA   -8.09mA    -12.05mA
-709.1mV  -12.42mA   -11.06mA   -11.59mA
-551.5mV  -11.38mA   -11.19mA   -10.73mA
-315.1mV  -7.913mA   -7.7mA     -7.644mA
551.5mV   11.71mA    11.04mA    11.75mA
906.1mV   16.02mA    14.86mA    16.45mA
1.3V      17.57mA    16.2mA     18.19mA
1.733V    16.03mA    13.62mA    17.93mA
2.009V    13.23mA    5.14mA     14.81mA
2.364V    3.7mA      1.9mA      10.5mA
[Pullup]
-1.164V   4.6mA      2.705mA    7.977mA
-1.045V   8.7mA      3.814mA    12.81mA
-887.9mV  16.31mA    7.401mA    15.56mA
-612.1mV  17.2mA     16.54mA    16.09mA
-375.8mV  12.93mA    12.62mA    12.74mA
215.2mV   -5.8mA     -5.652mA   -6.08mA
687.9mV   -13.08mA   -12.91mA   -14.07mA
1.476V    -15.74mA   -15.22mA   -17.48mA
1.791V    -14.48mA   -13.46mA   -16.71mA
1.988V    -13.96mA   -8.894mA   -15.93mA
2.224V    -8.2mA     -5.943mA   -15.42mA
2.382V    -6mA       -5.248mA   -10.06mA
[Ramp]
R_load=50.000Ohm
dV/dt_r   353.820mV/137.500ps  335.489mV/168.000ps  382.050mV/117.500ps
dV/dt_f   353.850mV/140.000ps  335.458mV/177.000ps  382.050mV/114.500ps
[Rising waveform]
R_fixture=50.000Ohm
V_fixture=1.200
V_fixture_min=1.140
V_fixture_max=1.300
0s        559mV      552.2mV    596.5mV
52ps      554.6mV    550.7mV    646mV
128ps     551.5mV    546.7mV    1.024V
166ps     572.5mV    544.2mV    1.134V
243ps     811.1mV    540.5mV    1.218V
294ps     998.4mV    545.8mV    1.236V
358ps     1.103V     582.7mV    1.244V
511ps     1.156V     957.4mV    1.248V
600ps     1.161V     1.066V     1.249V
1.25ns    1.163V     1.112V     1.249V
[Rising waveform]
R_fixture=50.000Ohm
V_fixture=0
0s        715uV      197.3uV    -3.712mV
64ps      -22.86uV   611.6uV    24.52mV
192ps     6.203mV    26.63uV    410.6mV
345ps     344.8mV    -9.635mV   585.8mV
422ps     460.1mV    33.81mV    609.9mV
498ps     520.6mV    160.8mV    620.3mV
613ps     557.8mV    370.8mV    626.3mV
715ps     570mV      475.8mV    627.8mV
881ps     576.1mV    537.9mV    628.5mV
1.25ns    577.4mV    557.9mV    628.9mV
[Falling waveform]
R_fixture=50.000Ohm
V_fixture=1.200
V_fixture_min=1.140
V_fixture_max=1.300
0s        1.162V     1.112V     1.252V
64ps      1.163V     1.112V     1.221V
192ps     1.155V     1.112V     822.8mV
256ps     1.041V     1.116V     707.2mV
320ps     880.3mV    1.122V     651.9mV
409ps     705.5mV    1.085V     621.1mV
486ps     627.6mV    967.7mV    611.9mV
613ps     580.7mV    751.5mV    607.1mV
741ps     567.2mV    627.2mV    605.8mV
1.25ns    561.4mV    555.2mV    604.7mV
[Falling waveform]
R_fixture=50.000Ohm
V_fixture=0
0s        577.2mV    558.6mV    638.9mV
52ps      582.1mV    558.2mV    560.7mV
141ps     583.7mV    561.7mV    155.6mV
179ps     519.2mV    566.6mV    80.76mV
230ps     334.1mV    574.6mV    34.86mV
281ps     161.3mV    573.8mV    15.58mV
345ps     59.28mV    515.7mV    5.832mV
486ps     8.205mV    151.7mV    791.2uV
575ps     2.695mV    46.16mV    273.2uV
1.25ns    4.669uV    58.44uV    -1.081uV
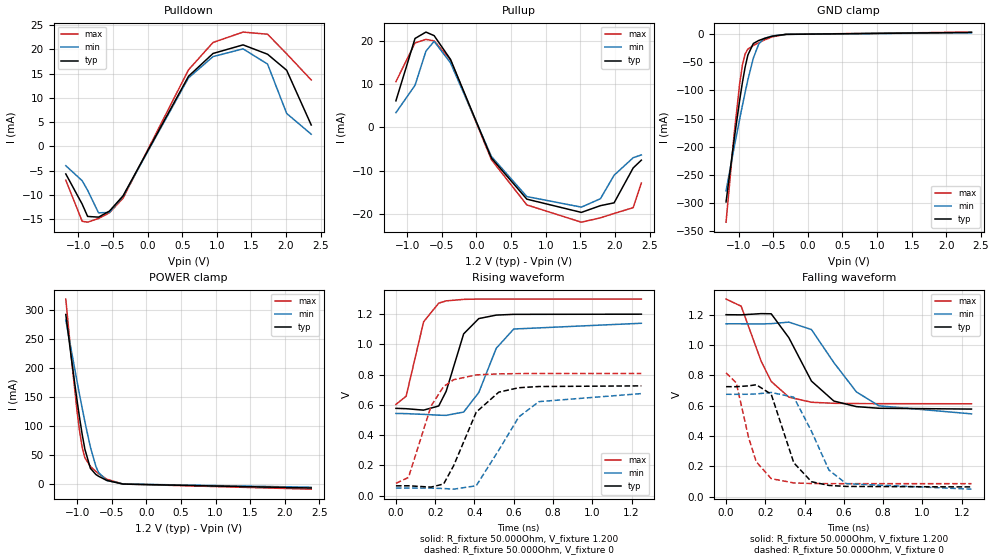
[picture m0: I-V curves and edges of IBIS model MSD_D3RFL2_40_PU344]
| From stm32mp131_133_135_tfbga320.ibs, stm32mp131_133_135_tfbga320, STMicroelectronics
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[Model] MSD_D3RFL2_40_PU344
Model_type   I/O
C_comp 2.348pF   2.261pF   2.473pF
Vinh = 820.000mV
Vinl = 380.000mV
Vmeas = 600.000mV
Vref = 600.000mV
[Model Spec]
Vinh   820.000mV   790.000mV   870.000mV
Vinl   380.000mV   350.000mV   430.000mV
Vmeas   600.000mV   570.000mV   650.000mV
Vref   600.000mV   570.000mV   650.000mV
[Receiver Thresholds]
Vth   =  0.600V
Vth_min  =  0.5880V
Vth_max  =  0.6120V
Vinh_ac  =  0.220V
Vinh_dc  =  0.130V
Vinl_ac  = -0.220V
Vinl_dc  = -0.130V
Tslew_ac =  5.000ns |Not specified, so set to high value
[Temperature Range]   25.000   125.000   -40.000
[Voltage Range]   1.200V   1.140V   1.300V
[GND Clamp Reference]   0.00V   0.00V   0.00V
[Pulldown Reference]   0.00V   0.00V   0.00V
[POWER Clamp Reference]   1.200V   1.140V   1.300V
[Pullup Reference]   1.200V   1.140V   1.300V
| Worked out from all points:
|   slope of the pulldown table from 0 to 0.18 V, typ, clamps not added: 35.6 ohm
|   slope of the pullup table from 0 to 0.18 V, typ, clamps not added: 29.6 ohm
|   GND clamp passes 1 mA (typ) near -0.41 V on its own axis
|   POWER clamp passes 1 mA (typ) near -0.41 V on its own axis
|   rising waveform, R_fixture 50.000Ohm, V_fixture 1.200: 20-80 % time 88.9ps typ, 117ps min, 74.8ps max; typ from 0.578 V to 1.2 V
|   rising waveform, R_fixture 50.000Ohm, V_fixture 0: 20-80 % time 138ps typ, 172ps min, 114ps max; typ from 0.065 V to 0.726 V
|   falling waveform, R_fixture 50.000Ohm, V_fixture 1.200: 20-80 % time 162ps typ, 204ps min, 129ps max; typ from 1.2 V to 0.578 V
|   falling waveform, R_fixture 50.000Ohm, V_fixture 0: 20-80 % time 102ps typ, 127ps min, 84.5ps max; typ from 0.726 V to 0.065 V
[GND Clamp]
-1.182V   -298.5mA   -278.7mA   -334.6mA
-1.064V   -186.4mA   -201mA     -176.4mA
-984.9mV  -117.1mA   -150.9mA   -87.65mA
-945.5mV  -85.8mA    -126.7mA   -54.89mA
-906.1mV  -58.45mA   -103.4mA   -34.82mA
-866.7mV  -36.99mA   -81.15mA   -26.46mA
-787.9mV  -16.43mA   -42.51mA   -19.96mA
-709.1mV  -11.02mA   -17.14mA   -14.94mA
-630.3mV  -7.563mA   -7.255mA   -10.33mA
-512.1mV  -3.391mA   -2.874mA   -4.513mA
-315.1mV  -135.6uA   -195uA     -130uA
2.364V    3.306mA    2.793mA    3.888mA
[Power Clamp]
-1.164V   291.7mA    282.1mA    318.2mA
-1.085V   217.9mA    230.5mA    219.1mA
-1.006V   147.8mA    179.6mA    130.3mA
-966.7mV  115.4mA    154.8mA    92.58mA
-927.3mV  85.61mA    130.5mA    63.27mA
-887.9mV  59.92mA    107mA      45.21mA
-809.1mV  27.42mA    64.02mA    30.59mA
-730.3mV  16.72mA    30.92mA    21.98mA
-690.9mV  13.66mA    20.11mA    18.17mA
-572.7mV  6.48mA     6.432mA    8.549mA
-336.4mV  188.5uA    360.2uA    208.2uA
2.382V    -6.618mA   -5.26mA    -8.576mA
[Pulldown]
-1.182V   -5.7mA     -4mA       -7mA
-945.5mV  -11.93mA   -7.1mA     -15.47mA
-866.7mV  -14.47mA   -9.07mA    -15.66mA
-709.1mV  -14.62mA   -13.73mA   -14.89mA
-551.5mV  -13.37mA   -13.65mA   -13.72mA
-354.6mV  -10.22mA   -10.3mA    -10.7mA
590.9mV   14.46mA    14.13mA    15.79mA
945.5mV   19.17mA    18.52mA    21.44mA
1.379V    20.94mA    20.12mA    23.58mA
1.733V    19.01mA    16.98mA    23.14mA
2.009V    15.7mA     6.79mA     19.1mA
2.364V    4.4mA      2.5mA      13.7mA
[Pullup]
-1.164V   6.1mA      3.357mA    10.52mA
-887.9mV  20.5mA     9.684mA    19.46mA
-730.3mV  21.97mA    17.57mA    20.29mA
-612.1mV  21.15mA    19.84mA    19.94mA
-375.8mV  15.67mA    14.87mA    15.58mA
215.2mV   -7.105mA   -6.743mA   -7.481mA
727.3mV   -16.61mA   -16.01mA   -17.94mA
1.515V    -19.67mA   -18.45mA   -21.93mA
1.791V    -18.11mA   -16.51mA   -20.92mA
1.988V    -17.46mA   -11.09mA   -19.92mA
2.264V    -9.4mA     -7.043mA   -18.57mA
2.382V    -7.6mA     -6.395mA   -12.88mA
[Ramp]
R_load=50.000Ohm
dV/dt_r   385.071mV/114.500ps  366.561mV/145.500ps  422.586mV/94.500ps
dV/dt_f   385.071mV/132.500ps  366.471mV/167.000ps  422.586mV/107.000ps
[Rising waveform]
R_fixture=50.000Ohm
V_fixture=1.200
V_fixture_min=1.140
V_fixture_max=1.300
0s        577.5mV    543.9mV    603.4mV
52ps      575.2mV    542.6mV    657.5mV
141ps     565.8mV    537.7mV    1.15V
218ps     593.3mV    532.4mV    1.273V
256ps     690.7mV    531.2mV    1.288V
345ps     1.07V      553.1mV    1.298V
422ps     1.171V     682.3mV    1.3V
511ps     1.194V     974.7mV    1.3V
600ps     1.199V     1.102V     1.3V
1.25ns    1.2V       1.14V      1.3V
[Rising waveform]
R_fixture=50.000Ohm
V_fixture=0
0s        65.25mV    50.26mV    81.75mV
64ps      65.58mV    50.56mV    121mV
179ps     56.87mV    50.14mV    593.3mV
243ps     77.58mV    47.5mV     722.1mV
294ps     198.5mV    43.24mV    766.7mV
409ps     552.4mV    65.86mV    798.6mV
524ps     684.7mV    301.7mV    805.4mV
626ps     713.8mV    521mV      807.3mV
728ps     721.8mV    621.9mV    807.8mV
1.25ns    726.1mV    675.1mV    808mV
[Falling waveform]
R_fixture=50.000Ohm
V_fixture=1.200
V_fixture_min=1.140
V_fixture_max=1.300
0s        1.2V       1.14V      1.303V
77ps      1.199V     1.14V      1.256V
179ps     1.207V     1.139V     893mV
230ps     1.206V     1.141V     760mV
320ps     1.048V     1.151V     656.8mV
435ps     762.4mV    1.102V     622.9mV
549ps     630.9mV    884.4mV    616.1mV
664ps     594.2mV    691mV      614.3mV
779ps     583.4mV    599.4mV    613.7mV
1.25ns    578mV      546.5mV    612.9mV
[Falling waveform]
R_fixture=50.000Ohm
V_fixture=0
0s        725.7mV    675.6mV    816.6mV
52ps      725.5mV    675.2mV    751.4mV
115ps     731.1mV    675.7mV    389.4mV
154ps     738.4mV    677.8mV    230.3mV
230ps     675.9mV    687.3mV    119.8mV
345ps     224.1mV    656.5mV    91.26mV
435ps     99.31mV    432.4mV    87.55mV
524ps     74.86mV    176mV      86.73mV
613ps     68.3mV     86.14mV    86.57mV
1.25ns    65.03mV    50.24mV    86.48mV
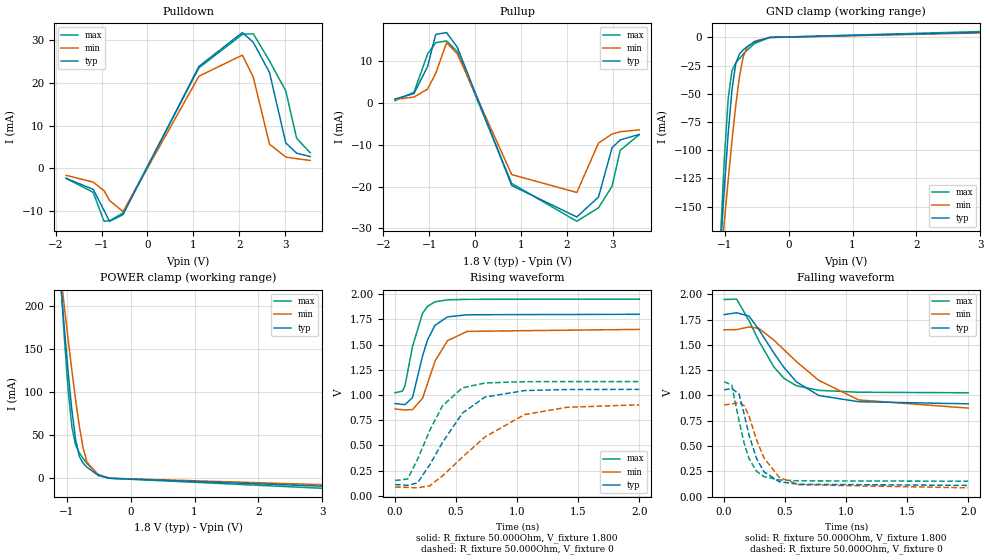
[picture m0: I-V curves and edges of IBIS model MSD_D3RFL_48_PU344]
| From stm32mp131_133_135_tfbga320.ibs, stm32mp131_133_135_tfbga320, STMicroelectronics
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[Model] MSD_D3RFL_48_PU344
Model_type   I/O
C_comp 2.315pF   2.233pF   2.437pF
Vinh = 1.440V
Vinl = 360.000mV
Vmeas = 900.000mV
Vref = 900.000mV
[Model Spec]
Vinh   1.440V   1.365V   1.515V
Vinl   360.000mV   285.000mV   435.000mV
Vmeas   900.000mV   825.000mV   975.000mV
Vref   900.000mV   825.000mV   975.000mV
[Temperature Range]   25.000   125.000   -40.000
[Voltage Range]   1.800V   1.650V   1.950V
[GND Clamp Reference]   0.00V   0.00V   0.00V
[Pulldown Reference]   0.00V   0.00V   0.00V
[POWER Clamp Reference]   1.800V   1.650V   1.950V
[Pullup Reference]   1.800V   1.650V   1.950V
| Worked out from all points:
|   slope of the pulldown table from 0 to 0.27 V, typ, clamps not added: 41 ohm
|   slope of the pullup table from 0 to 0.27 V, typ, clamps not added: 32.3 ohm
|   GND clamp passes 1 mA (typ) near -0.41 V on its own axis
|   POWER clamp passes 1 mA (typ) near -0.41 V on its own axis
|   rising waveform, R_fixture 50.000Ohm, V_fixture 1.800: 20-80 % time 123ps typ, 157ps min, 106ps max; typ from 0.915 V to 1.8 V
|   rising waveform, R_fixture 50.000Ohm, V_fixture 0: 20-80 % time 309ps typ, 493ps min, 235ps max; typ from 0.112 V to 1.06 V
|   falling waveform, R_fixture 50.000Ohm, V_fixture 1.800: 20-80 % time 332ps typ, 479ps min, 260ps max; typ from 1.8 V to 0.918 V
|   falling waveform, R_fixture 50.000Ohm, V_fixture 0: 20-80 % time 143ps typ, 181ps min, 122ps max; typ from 1.05 V to 0.112 V
[GND Clamp]
-1.773V   -888.9mA   -680.2mA   -1.192A
-1.064V   -186.5mA   -201.1mA   -176.5mA
-1.005V   -133.8mA   -163.4mA   -107.6mA
-945.5mV  -85.87mA   -126.8mA   -54.94mA
-886.4mV  -46.91mA   -92.14mA   -29.67mA
-827.3mV  -23.29mA   -60.7mA    -22.77mA
-768.2mV  -14.6mA    -34.69mA   -18.7mA
-709.1mV  -11.05mA   -17.19mA   -14.97mA
-650mV    -8.402mA   -8.775mA   -11.46mA
-531.8mV  -4.02mA    -3.393mA   -5.381mA
-295.4mV  -84.23uA   -134.8uA   -70.84uA
3.545V    5.195mA    4.583mA    6.021mA
[Power Clamp]
-1.745V   858.7mA    673.3mA    1.125A
-1.095V   227.7mA    237.3mA    232.4mA
-1.036V   174.2mA    199mA      163.4mA
-977.3mV  123.9mA    161.5mA    103.2mA
-918.2mV  79.25mA    125.1mA    60.03mA
-859.1mV  44.68mA    90.76mA    38.59mA
-800mV    25.45mA    59.94mA    29.58mA
-740.9mV  17.65mA    35.13mA    23.1mA
-681.8mV  13mA       18.78mA    17.36mA
-504.5mV  3.469mA    3.583mA    4.55mA
-327.3mV  146.1uA    320.8uA    184.6uA
3.573V    -10.54mA   -8.515mA   -13.4mA
[Pulldown]
-1.773V   -2.4mA     -1.7mA     -2.4mA
-1.182V   -5mA       -3.3mA     -5.7mA
-945.5mV  -9.92mA    -5.3mA     -12.48mA
-827.3mV  -12.5mA    -7.6mA     -12.4mA
-531.8mV  -10.94mA   -10.23mA   -10.54mA
1.123V    23.9mA     21.59mA    23.56mA
2.068V    31.83mA    26.53mA    31.41mA
2.305V    29.56mA    21.37mA    31.55mA
2.659V    22.44mA    5.6mA      25.16mA
3.014V    5.9mA      2.6mA      18.1mA
3.25V     3.5mA      2.2mA      7mA
3.545V    2.7mA      1.8mA      3.6mA
[Pullup]
-1.745V   1mA        900uA      600uA
-1.332V   2.3mA      1.454mA    2.623mA
-1.036V   8.8mA      3.377mA    11.79mA
-859.1mV  16.47mA    7.15mA     14.48mA
-622.7mV  16.91mA    14.48mA    14.91mA
-386.4mV  13.35mA    11.77mA    12.34mA
795.5mV   -19.73mA   -17.12mA   -19.23mA
2.214V    -27.27mA   -21.4mA    -28.31mA
2.686V    -22.49mA   -9.569mA   -25.08mA
2.982V    -10.7mA    -7.392mA   -19.91mA
3.159V    -8.8mA     -6.846mA   -11.3mA
3.573V    -7.5mA     -6.4mA     -7.554mA
[Ramp]
R_load=50.000Ohm
dV/dt_r   548.370mV/216.500ps  480.798mV/325.500ps  571.020mV/171.000ps
dV/dt_f   548.220mV/238.500ps  478.614mV/330.500ps  570.990mV/191.000ps
[Rising waveform]
R_fixture=50.000Ohm
V_fixture=1.800
V_fixture_min=1.650
V_fixture_max=1.950
0s        915.4mV    861.6mV    1.023V
62ps      906.3mV    853.7mV    1.039V
82ps      906.1mV    851.3mV    1.094V
143ps     974.5mV    855.6mV    1.48V
225ps     1.385V     966.6mV    1.809V
266ps     1.546V     1.113V     1.878V
327ps     1.69V      1.334V     1.923V
429ps     1.774V     1.538V     1.943V
593ps     1.795V     1.631V     1.948V
2ns       1.8V       1.65V      1.95V
[Rising waveform]
R_fixture=50.000Ohm
V_fixture=0
0s        112.5mV    87.82mV    152.8mV
103ps     105.3mV    84.44mV    167.2mV
184ps     128.7mV    79.8mV     362.4mV
286ps     312.3mV    100.7mV    653.2mV
388ps     529.1mV    197.9mV    892.2mV
552ps     820.5mV    384.9mV    1.071V
736ps     979.6mV    583.8mV    1.119V
1.062ns   1.044V     806.8mV    1.132V
1.409ns   1.054V     878.2mV    1.133V
2ns       1.056V     903mV      1.133V
[Falling waveform]
R_fixture=50.000Ohm
V_fixture=1.800
V_fixture_min=1.650
V_fixture_max=1.950
0s        1.799V     1.649V     1.948V
103ps     1.817V     1.651V     1.952V
205ps     1.784V     1.677V     1.738V
286ps     1.649V     1.662V     1.536V
409ps     1.418V     1.546V     1.28V
491ps     1.276V     1.451V     1.169V
593ps     1.134V     1.335V     1.096V
776ps     1V         1.149V     1.051V
1.103ns   938.6mV    956.2mV    1.032V
2ns       917.5mV    875.7mV    1.027V
[Falling waveform]
R_fixture=50.000Ohm
V_fixture=0
0s        1.055V     907.4mV    1.136V
62ps      1.069V     916.1mV    1.105V
123ps     1.015V     930.6mV    748mV
164ps     819.5mV    898.9mV    530mV
205ps     606mV      794.5mV    376mV
266ps     379.1mV    561.4mV    251.6mV
327ps     246.2mV    384mV      198.8mV
450ps     149mV      192.9mV    165.7mV
613ps     123mV      119.1mV    156.9mV
2ns       111.6mV    87.52mV    152.9mV
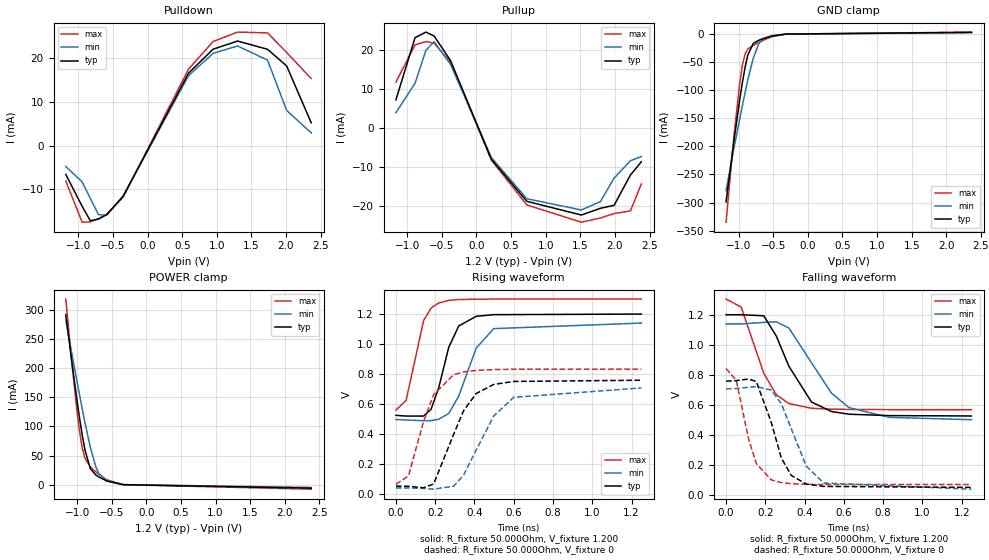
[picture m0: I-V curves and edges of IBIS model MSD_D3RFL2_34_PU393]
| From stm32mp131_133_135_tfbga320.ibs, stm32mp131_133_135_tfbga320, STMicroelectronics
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[Model] MSD_D3RFL2_34_PU393
Model_type   I/O
C_comp 2.377pF   2.291pF   2.503pF
Vinh = 820.000mV
Vinl = 380.000mV
Vmeas = 600.000mV
Vref = 600.000mV
[Model Spec]
Vinh   820.000mV   790.000mV   870.000mV
Vinl   380.000mV   350.000mV   430.000mV
Vmeas   600.000mV   570.000mV   650.000mV
Vref   600.000mV   570.000mV   650.000mV
[Receiver Thresholds]
Vth   =  0.600V
Vth_min  =  0.5880V
Vth_max  =  0.6120V
Vinh_ac  =  0.220V
Vinh_dc  =  0.130V
Vinl_ac  = -0.220V
Vinl_dc  = -0.130V
Tslew_ac =  5.000ns |Not specified, so set to high value
[Temperature Range]   25.000   125.000   -40.000
[Voltage Range]   1.200V   1.140V   1.300V
[GND Clamp Reference]   0.00V   0.00V   0.00V
[Pulldown Reference]   0.00V   0.00V   0.00V
[POWER Clamp Reference]   1.200V   1.140V   1.300V
[Pullup Reference]   1.200V   1.140V   1.300V
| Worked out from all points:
|   slope of the pulldown table from 0 to 0.18 V, typ, clamps not added: 31.3 ohm
|   slope of the pullup table from 0 to 0.18 V, typ, clamps not added: 26.5 ohm
|   GND clamp passes 1 mA (typ) near -0.41 V on its own axis
|   POWER clamp passes 1 mA (typ) near -0.41 V on its own axis
|   rising waveform, R_fixture 50.000Ohm, V_fixture 1.200: 20-80 % time 86.4ps typ, 115ps min, 72.1ps max; typ from 0.525 V to 1.2 V
|   rising waveform, R_fixture 50.000Ohm, V_fixture 0: 20-80 % time 132ps typ, 165ps min, 111ps max; typ from 0.054 V to 0.759 V
|   falling waveform, R_fixture 50.000Ohm, V_fixture 1.200: 20-80 % time 150ps typ, 195ps min, 125ps max; typ from 1.2 V to 0.527 V
|   falling waveform, R_fixture 50.000Ohm, V_fixture 0: 20-80 % time 97.4ps typ, 124ps min, 83.1ps max; typ from 0.759 V to 0.053 V
[GND Clamp]
-1.182V   -298.8mA   -278.8mA   -334.9mA
-1.064V   -186.6mA   -201.1mA   -176.7mA
-984.9mV  -117.3mA   -151.1mA   -87.88mA
-945.5mV  -85.98mA   -126.9mA   -55.1mA
-906.1mV  -58.6mA    -103.4mA   -35.03mA
-866.7mV  -37.14mA   -81.28mA   -26.65mA
-787.9mV  -16.55mA   -42.62mA   -20.11mA
-709.1mV  -11.11mA   -17.23mA   -15.06mA
-630.3mV  -7.64mA    -7.317mA   -10.42mA
-512.1mV  -3.431mA   -2.91mA    -4.569mA
-315.1mV  -140uA     -201.2uA   -134.4uA
2.364V    2.893mA    2.444mA    3.402mA
[Power Clamp]
-1.164V   291.9mA    282.3mA    318.5mA
-1.085V   218.2mA    230.6mA    219.4mA
-1.006V   148mA      179.8mA    130.6mA
-966.7mV  115.5mA    154.9mA    92.81mA
-927.3mV  85.77mA    130.6mA    63.48mA
-887.9mV  60.06mA    107.1mA    45.4mA
-809.1mV  27.54mA    64.12mA    30.75mA
-730.3mV  16.82mA    31mA       22.11mA
-690.9mV  13.74mA    20.18mA    18.27mA
-572.7mV  6.53mA     6.478mA    8.613mA
-336.4mV  191.9uA    365.4uA    212.3uA
2.382V    -5.79mA    -4.601mA   -7.505mA
[Pulldown]
-1.182V   -6.6mA     -4.8mA     -8.1mA
-945.5mV  -13.9mA    -8.3mA     -17.52mA
-827.3mV  -17.19mA   -12.13mA   -17.46mA
-709.1mV  -16.81mA   -15.8mA    -16.69mA
-590.9mV  -15.78mA   -15.93mA   -15.69mA
-354.6mV  -11.63mA   -11.56mA   -11.82mA
590.9mV   16.53mA    15.96mA    17.46mA
945.5mV   22.03mA    21.08mA    23.77mA
1.3V      23.89mA    22.77mA    25.94mA
1.733V    22.01mA    19.53mA    25.76mA
2.009V    18.19mA    8.02mA     21.28mA
2.364V    5.2mA      2.9mA      15.3mA
[Pullup]
-1.164V   7.3mA      4.009mA    11.85mA
-887.9mV  23.27mA    11.56mA    21.42mA
-730.3mV  24.7mA     20.06mA    22.27mA
-612.1mV  23.69mA    22.22mA    21.84mA
-375.8mV  17.41mA    16.45mA    16.97mA
215.2mV   -7.945mA   -7.529mA   -8.168mA
727.3mV   -18.75mA   -18.08mA   -19.68mA
1.515V    -22.27mA   -20.98mA   -24.11mA
1.791V    -20.54mA   -18.82mA   -23.03mA
1.988V    -19.79mA   -12.79mA   -21.9mA
2.224V    -12mA      -8.339mA   -21.22mA
2.382V    -8.6mA     -7.243mA   -14.29mA
[Ramp]
R_load=50.000Ohm
dV/dt_r   413.646mV/110.000ps  391.716mV/139.500ps  447.594mV/91.500ps
dV/dt_f   413.646mV/124.000ps  391.683mV/161.000ps  447.594mV/104.000ps
[Rising waveform]
R_fixture=50.000Ohm
V_fixture=1.200
V_fixture_min=1.140
V_fixture_max=1.300
0s        525.2mV    497.5mV    559.7mV
52ps      520.3mV    494.3mV    625mV
141ps     520.4mV    489mV      1.157V
179ps     565.1mV    490mV      1.24V
218ps     709.4mV    499mV      1.274V
269ps     978.2mV    537.6mV    1.291V
320ps     1.121V     653.7mV    1.297V
409ps     1.185V     973.5mV    1.299V
498ps     1.196V     1.103V     1.3V
1.25ns    1.2V       1.14V      1.3V
[Rising waveform]
R_fixture=50.000Ohm
V_fixture=0
0s        53.76mV    41.8mV     66.13mV
64ps      52.47mV    41.44mV    121.6mV
141ps     42.47mV    38.02mV    485.9mV
192ps     67.78mV    33.18mV    662.7mV
294ps     398.9mV    52.75mV    795.7mV
345ps     556.8mV    127.2mV    814.4mV
409ps     670.7mV    294.6mV    824.6mV
498ps     731.1mV    520.1mV    830.2mV
600ps     750.9mV    645.3mV    832.4mV
1.25ns    759.2mV    707.8mV    833.1mV
[Falling waveform]
R_fixture=50.000Ohm
V_fixture=1.200
V_fixture_min=1.140
V_fixture_max=1.300
0s        1.2V       1.139V     1.304V
77ps      1.2V       1.139V     1.251V
192ps     1.193V     1.149V     811.7mV
256ps     1.058V     1.153V     668.4mV
320ps     857.9mV    1.112V     609.8mV
435ps     620.4mV    881.1mV    578.7mV
537ps     557.1mV    679mV      572.7mV
626ps     539.1mV    583mV      571mV
830ps     529.9mV    518.2mV    569.4mV
1.25ns    527.4mV    502.6mV    569.2mV
[Falling waveform]
R_fixture=50.000Ohm
V_fixture=0
0s        758.6mV    707.5mV    842.5mV
52ps      762.3mV    710.1mV    764mV
115ps     773mV      717.8mV    374.2mV
154ps     756.4mV    722.7mV    211.4mV
230ps     486.1mV    699.6mV    103.4mV
281ps     250.1mV    610.6mV    84.92mV
332ps     132.3mV    443.2mV    77.53mV
409ps     75.1mV     192.8mV    73.51mV
498ps     59.46mV    82.01mV    72.28mV
1.25ns    53.08mV    41.23mV    71.92mV
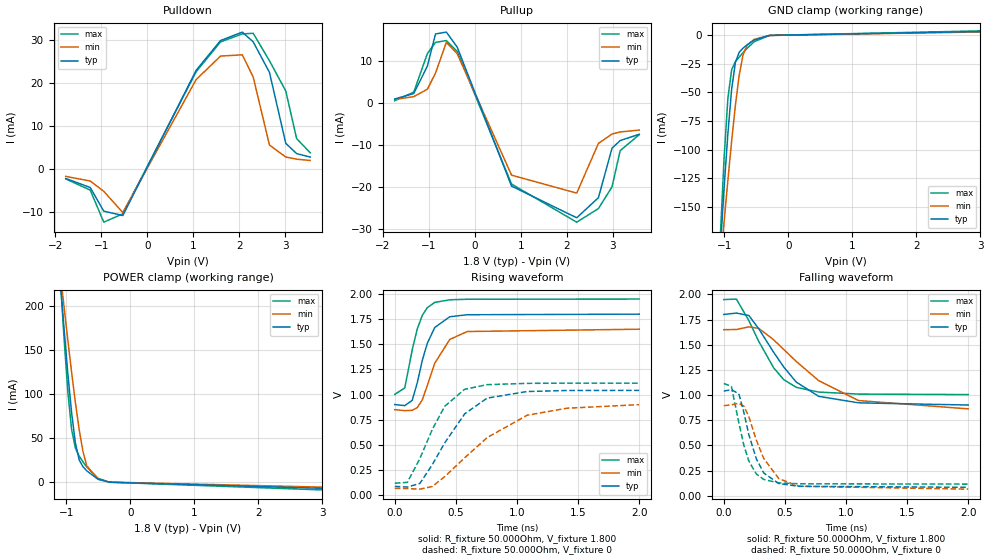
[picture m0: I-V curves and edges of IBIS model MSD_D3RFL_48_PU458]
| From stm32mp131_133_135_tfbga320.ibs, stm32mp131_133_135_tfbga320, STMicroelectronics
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[Model] MSD_D3RFL_48_PU458
Model_type   I/O
C_comp 2.374pF   2.291pF   2.498pF
Vinh = 1.440V
Vinl = 360.000mV
Vmeas = 900.000mV
Vref = 900.000mV
[Model Spec]
Vinh   1.440V   1.365V   1.515V
Vinl   360.000mV   285.000mV   435.000mV
Vmeas   900.000mV   825.000mV   975.000mV
Vref   900.000mV   825.000mV   975.000mV
[Temperature Range]   25.000   125.000   -40.000
[Voltage Range]   1.800V   1.650V   1.950V
[GND Clamp Reference]   0.00V   0.00V   0.00V
[Pulldown Reference]   0.00V   0.00V   0.00V
[POWER Clamp Reference]   1.800V   1.650V   1.950V
[Pullup Reference]   1.800V   1.650V   1.950V
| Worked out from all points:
|   slope of the pulldown table from 0 to 0.27 V, typ, clamps not added: 41 ohm
|   slope of the pullup table from 0 to 0.27 V, typ, clamps not added: 32.3 ohm
|   GND clamp passes 1 mA (typ) near -0.40 V on its own axis
|   POWER clamp passes 1 mA (typ) near -0.41 V on its own axis
|   rising waveform, R_fixture 50.000Ohm, V_fixture 1.800: 20-80 % time 128ps typ, 161ps min, 111ps max; typ from 0.9 V to 1.8 V
|   rising waveform, R_fixture 50.000Ohm, V_fixture 0: 20-80 % time 311ps typ, 504ps min, 239ps max; typ from 0.086 V to 1.04 V
|   falling waveform, R_fixture 50.000Ohm, V_fixture 1.800: 20-80 % time 331ps typ, 476ps min, 261ps max; typ from 1.8 V to 0.901 V
|   falling waveform, R_fixture 50.000Ohm, V_fixture 0: 20-80 % time 142ps typ, 178ps min, 121ps max; typ from 1.04 V to 0.085 V
[GND Clamp]
-1.773V   -889.8mA   -681mA     -1.193A
-1.064V   -186.9mA   -201.4mA   -177mA
-1.005V   -134.2mA   -163.7mA   -108.1mA
-945.5mV  -86.2mA    -127.1mA   -55.35mA
-886.4mV  -47.19mA   -92.39mA   -30.03mA
-827.3mV  -23.54mA   -60.92mA   -23.09mA
-768.2mV  -14.81mA   -34.87mA   -18.98mA
-709.1mV  -11.23mA   -17.34mA   -15.2mA
-650mV    -8.55mA    -8.9mA     -11.65mA
-531.8mV  -4.1mA     -3.466mA   -5.489mA
-295.4mV  -87.62uA   -142uA     -75.03uA
3.545V    3.897mA    3.437mA    4.517mA
[Power Clamp]
-1.745V   859.5mA    674.1mA    1.126A
-1.095V   228.2mA    237.7mA    232.9mA
-1.036V   174.6mA    199.4mA    163.9mA
-977.3mV  124.2mA    161.8mA    103.6mA
-918.2mV  79.56mA    125.4mA    60.43mA
-859.1mV  44.96mA    90.99mA    38.95mA
-800mV    25.69mA    60.15mA    29.89mA
-740.9mV  17.85mA    35.31mA    23.35mA
-681.8mV  13.17mA    18.93mA    17.58mA
-504.5mV  3.537mA    3.649mA    4.636mA
-327.3mV  152uA      332.2uA    193uA
3.573V    -7.907mA   -6.381mA   -10.06mA
[Pulldown]
-1.773V   -2.3mA     -1.8mA     -2.4mA
-1.241V   -4.4mA     -2.9mA     -5mA
-945.5mV  -9.92mA    -5.3mA     -12.49mA
-531.8mV  -10.94mA   -10.23mA   -10.54mA
1.064V    22.92mA    20.76mA    22.58mA
1.595V    29.86mA    26.24mA    29.54mA
2.068V    31.83mA    26.53mA    31.41mA
2.305V    29.56mA    21.37mA    31.55mA
2.659V    22.44mA    5.5mA      25.15mA
3.014V    5.9mA      2.7mA      18.1mA
3.25V     3.5mA      2.2mA      7mA
3.545V    2.7mA      1.9mA      3.7mA
[Pullup]
-1.745V   1mA        900uA      592.3uA
-1.332V   2.3mA      1.554mA    2.623mA
-1.036V   8.8mA      3.323mA    11.79mA
-859.1mV  16.47mA    7.15mA     14.47mA
-622.7mV  16.92mA    14.49mA    14.91mA
-386.4mV  13.34mA    11.77mA    12.33mA
795.5mV   -19.73mA   -17.13mA   -19.24mA
2.214V    -27.27mA   -21.4mA    -28.32mA
2.686V    -22.49mA   -9.569mA   -25.08mA
2.982V    -10.7mA    -7.338mA   -19.91mA
3.159V    -8.9mA     -6.846mA   -11.3mA
3.573V    -7.4mA     -6.4mA     -7.508mA
[Ramp]
R_load=50.000Ohm
dV/dt_r   556.947mV/220.000ps  486.927mV/328.500ps  582.270mV/175.000ps
dV/dt_f   556.791mV/237.500ps  484.899mV/328.000ps  582.240mV/191.500ps
[Rising waveform]
R_fixture=50.000Ohm
V_fixture=1.800
V_fixture_min=1.650
V_fixture_max=1.950
0s        899.7mV    849.5mV    1.001V
82ps      889.8mV    839.4mV    1.066V
143ps     942.4mV    842.5mV    1.446V
184ps     1.116V     869.4mV    1.652V
225ps     1.339V     946.2mV    1.787V
266ps     1.509V     1.088V     1.864V
327ps     1.667V     1.311V     1.917V
450ps     1.774V     1.548V     1.943V
593ps     1.794V     1.627V     1.948V
2ns       1.8V       1.65V      1.95V
[Rising waveform]
R_fixture=50.000Ohm
V_fixture=0
0s        85.79mV    66.93mV    116.8mV
103ps     79.03mV    63.83mV    125.7mV
205ps     114.4mV    57.93mV    361.8mV
307ps     301.1mV    84.87mV    652.2mV
409ps     519mV      182.8mV    883.2mV
572ps     807.7mV    370.3mV    1.052V
756ps     964.3mV    571.5mV    1.098V
1.083ns   1.03V      793.7mV    1.111V
1.409ns   1.04V      863.5mV    1.113V
2ns       1.041V     899mV      1.113V
[Falling waveform]
R_fixture=50.000Ohm
V_fixture=1.800
V_fixture_min=1.650
V_fixture_max=1.950
0s        1.8V       1.649V     1.948V
103ps     1.814V     1.651V     1.953V
205ps     1.79V      1.677V     1.739V
286ps     1.658V     1.663V     1.533V
409ps     1.423V     1.548V     1.269V
491ps     1.278V     1.452V     1.153V
593ps     1.129V     1.334V     1.077V
776ps     987.9mV    1.144V     1.03V
1.103ns   923.2mV    945.6mV    1.01V
2ns       901.4mV    863.4mV    1.005V
[Falling waveform]
R_fixture=50.000Ohm
V_fixture=0
0s        1.04V      895mV      1.115V
62ps      1.054V     903.3mV    1.087V
123ps     1.014V     918.9mV    726.7mV
164ps     829mV      889.4mV    503mV
205ps     607.6mV    786.5mV    345mV
266ps     368.6mV    553.9mV    217.4mV
327ps     226.7mV    370mV      162.9mV
450ps     122.2mV    171.4mV    128.6mV
613ps     95.06mV    95.37mV    119.9mV
2ns       84.89mV    66.47mV    116.8mV
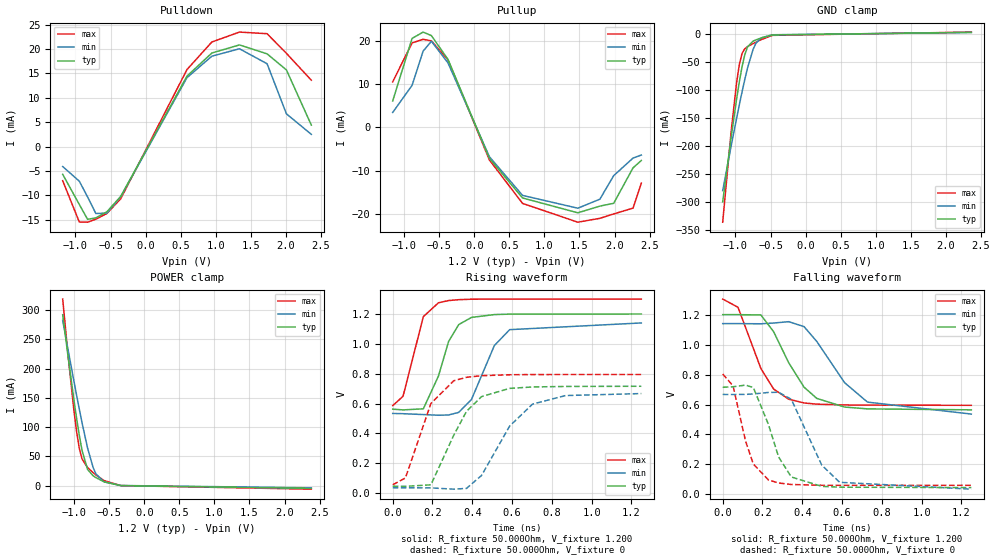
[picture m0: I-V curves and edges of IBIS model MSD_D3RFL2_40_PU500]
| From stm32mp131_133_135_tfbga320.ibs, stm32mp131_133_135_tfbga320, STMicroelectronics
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[Model] MSD_D3RFL2_40_PU500
Model_type   I/O
C_comp 2.422pF   2.336pF   2.548pF
Vinh = 820.000mV
Vinl = 380.000mV
Vmeas = 600.000mV
Vref = 600.000mV
[Model Spec]
Vinh   820.000mV   790.000mV   870.000mV
Vinl   380.000mV   350.000mV   430.000mV
Vmeas   600.000mV   570.000mV   650.000mV
Vref   600.000mV   570.000mV   650.000mV
[Receiver Thresholds]
Vth   =  0.600V
Vth_min  =  0.5880V
Vth_max  =  0.6120V
Vinh_ac  =  0.220V
Vinh_dc  =  0.130V
Vinl_ac  = -0.220V
Vinl_dc  = -0.130V
Tslew_ac =  5.000ns |Not specified, so set to high value
[Temperature Range]   25.000   125.000   -40.000
[Voltage Range]   1.200V   1.140V   1.300V
[GND Clamp Reference]   0.00V   0.00V   0.00V
[Pulldown Reference]   0.00V   0.00V   0.00V
[POWER Clamp Reference]   1.200V   1.140V   1.300V
[Pullup Reference]   1.200V   1.140V   1.300V
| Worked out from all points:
|   slope of the pulldown table from 0 to 0.18 V, typ, clamps not added: 35.6 ohm
|   slope of the pullup table from 0 to 0.18 V, typ, clamps not added: 29.6 ohm
|   GND clamp passes 1 mA (typ) near -0.40 V on its own axis
|   POWER clamp passes 1 mA (typ) near -0.41 V on its own axis
|   rising waveform, R_fixture 50.000Ohm, V_fixture 1.200: 20-80 % time 91.6ps typ, 119ps min, 77.2ps max; typ from 0.562 V to 1.2 V
|   rising waveform, R_fixture 50.000Ohm, V_fixture 0: 20-80 % time 145ps typ, 179ps min, 121ps max; typ from 0.046 V to 0.716 V
|   falling waveform, R_fixture 50.000Ohm, V_fixture 1.200: 20-80 % time 165ps typ, 206ps min, 133ps max; typ from 1.2 V to 0.564 V
|   falling waveform, R_fixture 50.000Ohm, V_fixture 0: 20-80 % time 103ps typ, 128ps min, 86.1ps max; typ from 0.715 V to 0.045 V
[GND Clamp]
-1.182V   -299.2mA   -279.2mA   -335.4mA
-1.064V   -187mA     -201.4mA   -177mA
-984.9mV  -117.5mA   -151.3mA   -88.22mA
-945.5mV  -86.23mA   -127mA     -55.43mA
-906.1mV  -58.85mA   -103.7mA   -35.31mA
-866.7mV  -37.36mA   -81.45mA   -26.92mA
-827.3mV  -23.56mA   -60.91mA   -23.14mA
-748.5mV  -13.42mA   -27.95mA   -17.73mA
-709.1mV  -11.25mA   -17.35mA   -15.24mA
-630.3mV  -7.747mA   -7.41mA    -10.55mA
-472.7mV  -2.393mA   -2.09mA    -3.114mA
2.364V    2.273mA    1.921mA    2.674mA
[Power Clamp]
-1.164V   292.3mA    282.6mA    319mA
-1.085V   218.5mA    230.8mA    219.8mA
-1.006V   148.3mA    180mA      130.9mA
-966.7mV  115.8mA    155.2mA    93.11mA
-927.3mV  86mA       130.8mA    63.78mA
-887.9mV  60.28mA    107.3mA    45.68mA
-809.1mV  27.72mA    64.28mA    30.98mA
-730.3mV  16.96mA    31.12mA    22.29mA
-690.9mV  13.87mA    20.29mA    18.43mA
-572.7mV  6.606mA    6.547mA    8.709mA
-336.4mV  197.1uA    373.8uA    219.2uA
2.382V    -4.548mA   -3.619mA   -5.899mA
[Pulldown]
-1.182V   -5.7mA     -4.1mA     -7mA
-945.5mV  -11.87mA   -7.1mA     -15.47mA
-827.3mV  -14.92mA   -10.32mA   -15.51mA
-709.1mV  -14.62mA   -13.73mA   -14.89mA
-551.5mV  -13.37mA   -13.65mA   -13.72mA
-354.6mV  -10.22mA   -10.29mA   -10.71mA
590.9mV   14.45mA    14.13mA    15.79mA
945.5mV   19.18mA    18.53mA    21.44mA
1.339V    20.84mA    20.05mA    23.47mA
1.733V    19.01mA    16.98mA    23.14mA
2.009V    15.71mA    6.71mA     19.11mA
2.364V    4.4mA      2.5mA      13.6mA
[Pullup]
-1.164V   6.1mA      3.457mA    10.51mA
-887.9mV  20.5mA     9.694mA    19.46mA
-730.3mV  21.96mA    17.57mA    20.3mA
-612.1mV  21.15mA    19.85mA    19.93mA
-375.8mV  15.67mA    14.87mA    15.59mA
215.2mV   -7.105mA   -6.743mA   -7.481mA
687.9mV   -16.23mA   -15.64mA   -17.48mA
1.476V    -19.65mA   -18.59mA   -21.81mA
1.791V    -18.11mA   -16.51mA   -20.92mA
1.988V    -17.46mA   -11.09mA   -19.91mA
2.264V    -9.3mA     -7.043mA   -18.57mA
2.382V    -7.6mA     -6.348mA   -12.82mA
[Ramp]
R_load=50.000Ohm
dV/dt_r   391.848mV/118.500ps  371.775mV/150.000ps  431.757mV/99.500ps
dV/dt_f   391.848mV/135.000ps  371.712mV/168.500ps  431.757mV/109.500ps
[Rising waveform]
R_fixture=50.000Ohm
V_fixture=1.200
V_fixture_min=1.140
V_fixture_max=1.300
0s        562mV      533.3mV    585.5mV
52ps      557.2mV    531.8mV    648.6mV
154ps     564.4mV    525.9mV    1.182V
230ps     783.9mV    521.3mV    1.275V
281ps     1.016V     523.2mV    1.29V
332ps     1.129V     540.5mV    1.296V
396ps     1.177V     626.9mV    1.299V
511ps     1.196V     988.2mV    1.3V
588ps     1.199V     1.095V     1.3V
1.25ns    1.2V       1.14V      1.3V
[Rising waveform]
R_fixture=50.000Ohm
V_fixture=0
0s        46mV       35.03mV    55.31mV
64ps      44.94mV    35.39mV    101mV
192ps     55.03mV    34.5mV     600.1mV
307ps     387.8mV    25.95mV    752.6mV
371ps     547.7mV    31.08mV    775.6mV
447ps     646.5mV    118.2mV    786.4mV
588ps     701.4mV    448.9mV    792.8mV
703ps     710.9mV    595.9mV    794.1mV
869ps     714.3mV    653.4mV    794.5mV
1.25ns    715.6mV    666.7mV    794.5mV
[Falling waveform]
R_fixture=50.000Ohm
V_fixture=1.200
V_fixture_min=1.140
V_fixture_max=1.300
0s        1.2V       1.14V      1.304V
77ps      1.2V       1.14V      1.249V
192ps     1.198V     1.139V     840.4mV
256ps     1.086V     1.144V     703.4mV
332ps     878.3mV    1.153V     635.4mV
409ps     715.8mV    1.12V      610.4mV
473ps     640.9mV    1.021V     602.5mV
613ps     583mV      745.6mV    597.1mV
728ps     570.9mV    616.1mV    595.9mV
1.25ns    564.5mV    536.2mV    594.8mV
[Falling waveform]
R_fixture=50.000Ohm
V_fixture=0
0s        715mV      667.2mV    803.8mV
52ps      718.7mV    666.9mV    724.5mV
115ps     729.6mV    667.7mV    355.1mV
154ps     713.6mV    670.5mV    202.6mV
230ps     466.9mV    680.6mV    96.38mV
281ps     250.3mV    682mV      76.04mV
345ps     116.1mV    634.5mV    66.18mV
498ps     53.67mV    195.5mV    61.03mV
588ps     48.17mV    80.71mV    60.69mV
1.25ns    45.35mV    34.95mV    60.51mV
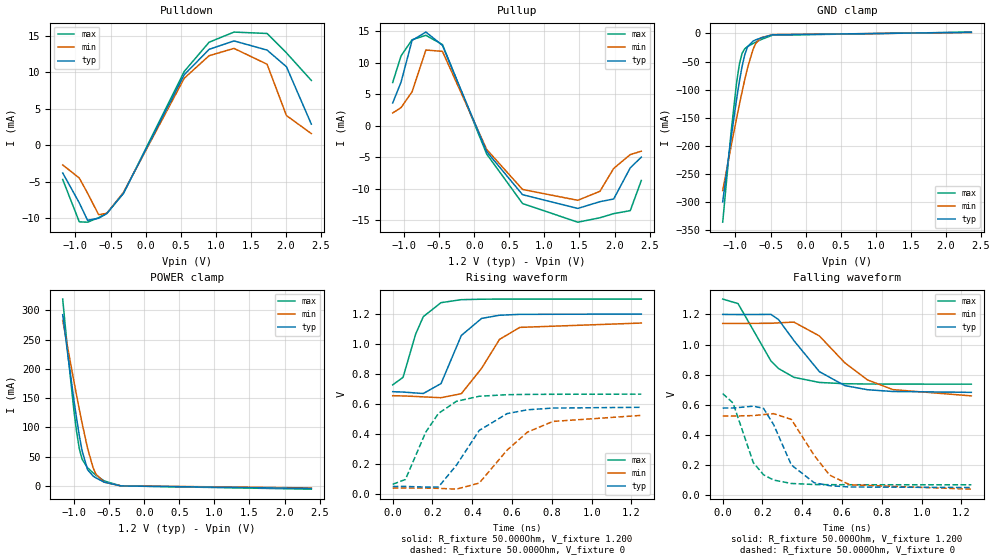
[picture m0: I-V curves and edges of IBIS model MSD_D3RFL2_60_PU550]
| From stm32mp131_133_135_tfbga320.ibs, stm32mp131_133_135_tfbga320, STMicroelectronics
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[Model] MSD_D3RFL2_60_PU550
Model_type   I/O
C_comp 2.435pF   2.348pF   2.561pF
Vinh = 820.000mV
Vinl = 380.000mV
Vmeas = 600.000mV
Vref = 600.000mV
[Model Spec]
Vinh   820.000mV   790.000mV   870.000mV
Vinl   380.000mV   350.000mV   430.000mV
Vmeas   600.000mV   570.000mV   650.000mV
Vref   600.000mV   570.000mV   650.000mV
[Receiver Thresholds]
Vth   =  0.600V
Vth_min  =  0.5880V
Vth_max  =  0.6120V
Vinh_ac  =  0.220V
Vinh_dc  =  0.130V
Vinl_ac  = -0.220V
Vinl_dc  = -0.130V
Tslew_ac =  5.000ns |Not specified, so set to high value
[Temperature Range]   25.000   125.000   -40.000
[Voltage Range]   1.200V   1.140V   1.300V
[GND Clamp Reference]   0.00V   0.00V   0.00V
[Pulldown Reference]   0.00V   0.00V   0.00V
[POWER Clamp Reference]   1.200V   1.140V   1.300V
[Pullup Reference]   1.200V   1.140V   1.300V
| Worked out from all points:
|   slope of the pulldown table from 0 to 0.18 V, typ, clamps not added: 50.1 ohm
|   slope of the pullup table from 0 to 0.18 V, typ, clamps not added: 42.9 ohm
|   GND clamp passes 1 mA (typ) near -0.40 V on its own axis
|   POWER clamp passes 1 mA (typ) near -0.41 V on its own axis
|   rising waveform, R_fixture 50.000Ohm, V_fixture 1.200: 20-80 % time 106ps typ, 136ps min, 86.5ps max; typ from 0.682 V to 1.2 V
|   rising waveform, R_fixture 50.000Ohm, V_fixture 0: 20-80 % time 172ps typ, 213ps min, 141ps max; typ from 0.05 V to 0.578 V
|   falling waveform, R_fixture 50.000Ohm, V_fixture 1.200: 20-80 % time 197ps typ, 247ps min, 159ps max; typ from 1.2 V to 0.682 V
|   falling waveform, R_fixture 50.000Ohm, V_fixture 0: 20-80 % time 116ps typ, 144ps min, 99.3ps max; typ from 0.578 V to 0.05 V
[GND Clamp]
-1.182V   -299.3mA   -279.3mA   -335.5mA
-1.064V   -187.1mA   -201.6mA   -177.2mA
-984.9mV  -117.6mA   -151.4mA   -88.33mA
-945.5mV  -86.31mA   -127.1mA   -55.53mA
-906.1mV  -58.92mA   -103.8mA   -35.42mA
-866.7mV  -37.43mA   -81.52mA   -27.01mA
-827.3mV  -23.64mA   -60.97mA   -23.23mA
-748.5mV  -13.47mA   -27.99mA   -17.8mA
-709.1mV  -11.3mA    -17.39mA   -15.29mA
-630.3mV  -7.775mA   -7.441mA   -10.6mA
-472.7mV  -2.409mA   -2.105mA   -3.132mA
2.364V    2.067mA    1.746mA    2.431mA
[Power Clamp]
-1.164V   292.4mA    282.7mA    319.1mA
-1.085V   218.6mA    231mA      220mA
-1.006V   148.4mA    180.1mA    131mA
-966.7mV  115.9mA    155.2mA    93.22mA
-927.3mV  86.08mA    130.9mA    63.88mA
-887.9mV  60.35mA    107.4mA    45.77mA
-809.1mV  27.78mA    64.33mA    31.06mA
-730.3mV  17mA       31.16mA    22.35mA
-690.9mV  13.91mA    20.33mA    18.49mA
-572.7mV  6.632mA    6.569mA    8.741mA
-336.4mV  198.8uA    376.6uA    221.3uA
2.382V    -4.134mA   -3.29mA    -5.363mA
[Pulldown]
-1.182V   -3.8mA     -2.7mA     -4.7mA
-945.5mV  -7.91mA    -4.5mA     -10.51mA
-827.3mV  -10.3mA    -6.58mA    -10.56mA
-669.7mV  -10.02mA   -9.53mA    -9.94mA
-551.5mV  -9.372mA   -9.341mA   -9.3mA
-315.1mV  -6.567mA   -6.465mA   -6.61mA
551.5mV   9.679mA    9.198mA    10.13mA
906.1mV   13.16mA    12.29mA    14.14mA
1.261V    14.32mA    13.29mA    15.53mA
1.733V    13.06mA    11.12mA    15.34mA
2.009V    10.78mA    4.08mA     12.68mA
2.364V    2.9mA      1.6mA      8.9mA
[Pullup]
-1.164V   3.6mA      2.005mA    6.838mA
-1.045V   6.9mA      2.857mA    11.06mA
-887.9mV  13.51mA    5.365mA    13.61mA
-690.9mV  14.83mA    11.99mA    14.32mA
-454.5mV  12.73mA    11.77mA    12.85mA
175.8mV   -4.108mA   -3.772mA   -4.491mA
687.9mV   -10.95mA   -10.12mA   -12.35mA
1.476V    -13.13mA   -11.84mA   -15.31mA
1.791V    -12.06mA   -10.42mA   -14.61mA
1.988V    -11.63mA   -6.784mA   -13.95mA
2.224V    -6.7mA     -4.595mA   -13.48mA
2.382V    -5mA       -4.048mA   -8.7mA
[Ramp]
R_load=50.000Ohm
dV/dt_r   313.974mV/139.500ps  291.423mV/176.500ps  348.423mV/114.000ps
dV/dt_f   314.004mV/157.500ps  291.420mV/198.500ps  348.423mV/130.000ps
[Rising waveform]
R_fixture=50.000Ohm
V_fixture=1.200
V_fixture_min=1.140
V_fixture_max=1.300
0s        682mV      655.2mV    727.5mV
52ps      679.7mV    653.7mV    777.8mV
115ps     673.3mV    650.3mV    1.065V
154ps     670mV      647.4mV    1.183V
243ps     736.2mV    641.9mV    1.276V
345ps     1.057V     668.6mV    1.296V
447ps     1.171V     838.1mV    1.299V
537ps     1.192V     1.031V     1.3V
639ps     1.198V     1.111V     1.3V
1.25ns    1.2V       1.14V      1.3V
[Rising waveform]
R_fixture=50.000Ohm
V_fixture=0
0s        49.68mV    38.6mV     64.33mV
64ps      50.01mV    38.86mV    96.54mV
166ps     45.38mV    38.76mV    412mV
230ps     46.3mV     37.2mV     536.9mV
320ps     190.9mV    31.7mV     617.7mV
435ps     423.4mV    72.33mV    651.6mV
575ps     535.7mV    291.8mV    662mV
677ps     561.2mV    411.9mV    663.9mV
805ps     572.8mV    483.5mV    664.8mV
1.25ns    577.9mV    523.9mV    665.6mV
[Falling waveform]
R_fixture=50.000Ohm
V_fixture=1.200
V_fixture_min=1.140
V_fixture_max=1.300
0s        1.2V       1.14V      1.302V
77ps      1.199V     1.14V      1.272V
243ps     1.2V       1.141V     889.7mV
281ps     1.165V     1.144V     839.9mV
358ps     1.026V     1.149V     781.9mV
486ps     819.6mV    1.057V     747.9mV
613ps     727.2mV    879.7mV    739.4mV
728ps     699.4mV    764.6mV    737.4mV
856ps     687.7mV    700.2mV    736.8mV
1.25ns    682mV      658.6mV    736.5mV
[Falling waveform]
R_fixture=50.000Ohm
V_fixture=0
0s        577.9mV    524.8mV    673.8mV
52ps      577.7mV    524.4mV    611mV
154ps     590.3mV    527.6mV    214.6mV
205ps     575.8mV    534.1mV    134.5mV
256ps     467.7mV    540.6mV    99.16mV
345ps     199.7mV    502.4mV    76.51mV
460ps     81.55mV    263.3mV    69.45mV
537ps     61.72mV    132.5mV    68.42mV
639ps     53.14mV    67.6mV     68.01mV
1.25ns    49.54mV    38.61mV    67.8mV
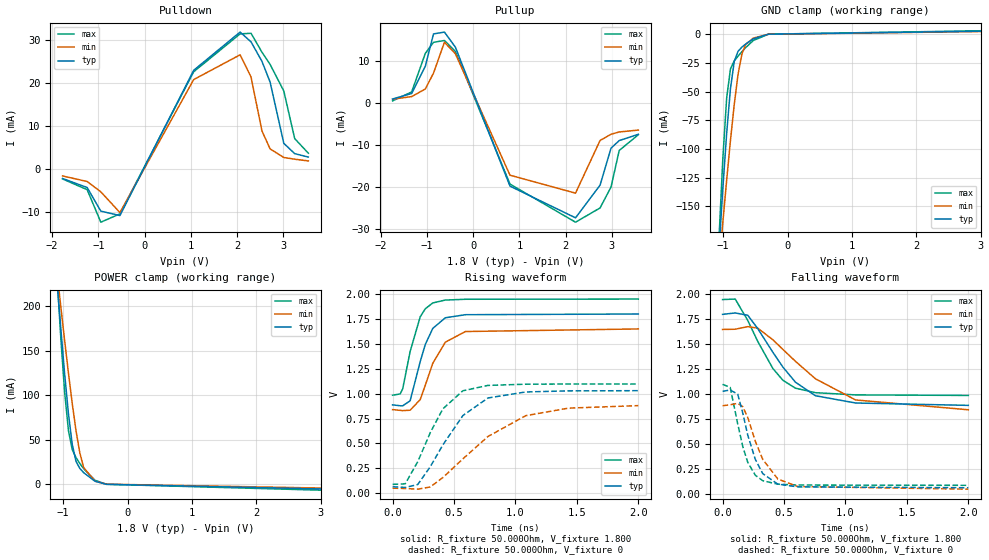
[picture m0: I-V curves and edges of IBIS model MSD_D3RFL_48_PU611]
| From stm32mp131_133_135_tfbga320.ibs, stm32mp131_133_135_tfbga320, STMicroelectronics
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[Model] MSD_D3RFL_48_PU611
Model_type   I/O
C_comp 2.420pF   2.336pF   2.545pF
Vinh = 1.440V
Vinl = 360.000mV
Vmeas = 900.000mV
Vref = 900.000mV
[Model Spec]
Vinh   1.440V   1.365V   1.515V
Vinl   360.000mV   285.000mV   435.000mV
Vmeas   900.000mV   825.000mV   975.000mV
Vref   900.000mV   825.000mV   975.000mV
[Temperature Range]   25.000   125.000   -40.000
[Voltage Range]   1.800V   1.650V   1.950V
[GND Clamp Reference]   0.00V   0.00V   0.00V
[Pulldown Reference]   0.00V   0.00V   0.00V
[POWER Clamp Reference]   1.800V   1.650V   1.950V
[Pullup Reference]   1.800V   1.650V   1.950V
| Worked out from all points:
|   slope of the pulldown table from 0 to 0.27 V, typ, clamps not added: 41 ohm
|   slope of the pullup table from 0 to 0.27 V, typ, clamps not added: 32.3 ohm
|   GND clamp passes 1 mA (typ) near -0.40 V on its own axis
|   POWER clamp passes 1 mA (typ) near -0.41 V on its own axis
|   rising waveform, R_fixture 50.000Ohm, V_fixture 1.800: 20-80 % time 131ps typ, 165ps min, 114ps max; typ from 0.887 V to 1.8 V
|   rising waveform, R_fixture 50.000Ohm, V_fixture 0: 20-80 % time 314ps typ, 494ps min, 242ps max; typ from 0.065 V to 1.03 V
|   falling waveform, R_fixture 50.000Ohm, V_fixture 1.800: 20-80 % time 330ps typ, 484ps min, 261ps max; typ from 1.8 V to 0.889 V
|   falling waveform, R_fixture 50.000Ohm, V_fixture 0: 20-80 % time 141ps typ, 177ps min, 121ps max; typ from 1.03 V to 0.064 V
[GND Clamp]
-1.773V   -890.5mA   -681.6mA   -1.194A
-1.064V   -187.2mA   -201.8mA   -177.3mA
-1.005V   -134.4mA   -163.8mA   -108.4mA
-945.5mV  -86.44mA   -127.2mA   -55.66mA
-886.4mV  -47.41mA   -92.56mA   -30.31mA
-827.3mV  -23.72mA   -61.07mA   -23.32mA
-768.2mV  -14.97mA   -35mA      -19.18mA
-709.1mV  -11.36mA   -17.46mA   -15.37mA
-650mV    -8.657mA   -8.989mA   -11.79mA
-531.8mV  -4.162mA   -3.519mA   -5.565mA
-295.4mV  -91.22uA   -146.2uA   -78.42uA
3.545V    2.923mA    2.578mA    3.388mA
[Power Clamp]
-1.745V   860.2mA    674.6mA    1.127A
-1.095V   228.5mA    238mA      233.3mA
-1.036V   174.9mA    199.6mA    164.3mA
-977.3mV  124.5mA    162mA      104mA
-918.2mV  79.79mA    125.6mA    60.73mA
-859.1mV  45.16mA    91.18mA    39.21mA
-800mV    25.87mA    60.3mA     30.12mA
-740.9mV  18mA       35.44mA    23.55mA
-681.8mV  13.3mA     19.04mA    17.73mA
-504.5mV  3.587mA    3.698mA    4.701mA
-327.3mV  156.8uA    340.6uA    199.2uA
3.573V    -5.931mA   -4.788mA   -7.545mA
[Pulldown]
-1.773V   -2.3mA     -1.7mA     -2.4mA
-1.241V   -4.4mA     -3mA       -4.9mA
-945.5mV  -9.9mA     -5.4mA     -12.48mA
-531.8mV  -10.94mA   -10.24mA   -10.54mA
1.064V    22.92mA    20.76mA    22.58mA
2.068V    31.83mA    26.53mA    31.41mA
2.305V    29.56mA    21.37mA    31.55mA
2.541V    25.01mA    8.8mA      27.15mA
2.718V    20.17mA    4.6mA      24.29mA
3.014V    5.9mA      2.6mA      18.1mA
3.25V     3.5mA      2.2mA      7mA
3.545V    2.7mA      1.8mA      3.6mA
[Pullup]
-1.745V   1mA        953.9uA    546.2uA
-1.332V   2.3mA      1.562mA    2.669mA
-1.036V   8.8mA      3.377mA    11.85mA
-859.1mV  16.48mA    7.15mA     14.48mA
-622.7mV  16.91mA    14.49mA    14.91mA
-386.4mV  13.34mA    11.77mA    12.33mA
795.5mV   -19.73mA   -17.13mA   -19.24mA
2.214V    -27.27mA   -21.4mA    -28.31mA
2.745V    -19.5mA    -8.877mA   -24.92mA
2.982V    -10.7mA    -7.392mA   -19.95mA
3.159V    -8.9mA     -6.846mA   -11.25mA
3.573V    -7.4mA     -6.4mA     -7.508mA
[Ramp]
R_load=50.000Ohm
dV/dt_r   563.463mV/223.000ps  491.529mV/331.000ps  590.892mV/178.000ps
dV/dt_f   563.367mV/236.500ps  489.648mV/326.500ps  590.892mV/191.500ps
[Rising waveform]
R_fixture=50.000Ohm
V_fixture=1.800
V_fixture_min=1.650
V_fixture_max=1.950
0s        887.4mV    840mV      984.7mV
62ps      878.8mV    832.4mV    997.5mV
82ps      877.6mV    829.9mV    1.047V
143ps     928.8mV    833.9mV    1.424V
225ps     1.322V     940.4mV    1.772V
266ps     1.493V     1.084V     1.852V
327ps     1.655V     1.304V     1.911V
429ps     1.762V     1.517V     1.94V
593ps     1.793V     1.624V     1.948V
2ns       1.8V       1.65V      1.95V
[Rising waveform]
R_fixture=50.000Ohm
V_fixture=0
0s        65.29mV    50.95mV    88.9mV
103ps     58.51mV    47.82mV    94.71mV
205ps     87.69mV    41.11mV    317mV
307ps     266.4mV    63.28mV    609.3mV
409ps     485.1mV    157.1mV    847.2mV
572ps     780mV      345.1mV    1.029V
776ps     956.7mV    569.8mV    1.083V
1.083ns   1.017V     778.8mV    1.095V
1.43ns    1.028V     854.7mV    1.097V
2ns       1.03V      880.1mV    1.097V
[Falling waveform]
R_fixture=50.000Ohm
V_fixture=1.800
V_fixture_min=1.650
V_fixture_max=1.950
0s        1.8V       1.649V     1.948V
103ps     1.814V     1.651V     1.953V
205ps     1.791V     1.677V     1.739V
286ps     1.658V     1.662V     1.53V
409ps     1.421V     1.546V     1.259V
491ps     1.272V     1.449V     1.14V
593ps     1.121V     1.33V      1.061V
756ps     985.4mV    1.155V     1.016V
1.083ns   912.7mV    943.1mV    993.8mV
2ns       889mV      845mV      988.5mV
[Falling waveform]
R_fixture=50.000Ohm
V_fixture=0
0s        1.029V     885.4mV    1.099V
62ps      1.043V     894.5mV    1.07V
123ps     1.002V     909.4mV    705mV
164ps     814.8mV    876.5mV    478.5mV
205ps     591.2mV    768.1mV    318.9mV
266ps     349.4mV    531.3mV    190.3mV
327ps     205.7mV    348.5mV    134.9mV
450ps     100.4mV    151.1mV    100mV
613ps     73.43mV    76.46mV    91.49mV
2ns       64.35mV    50.34mV    88.76mV
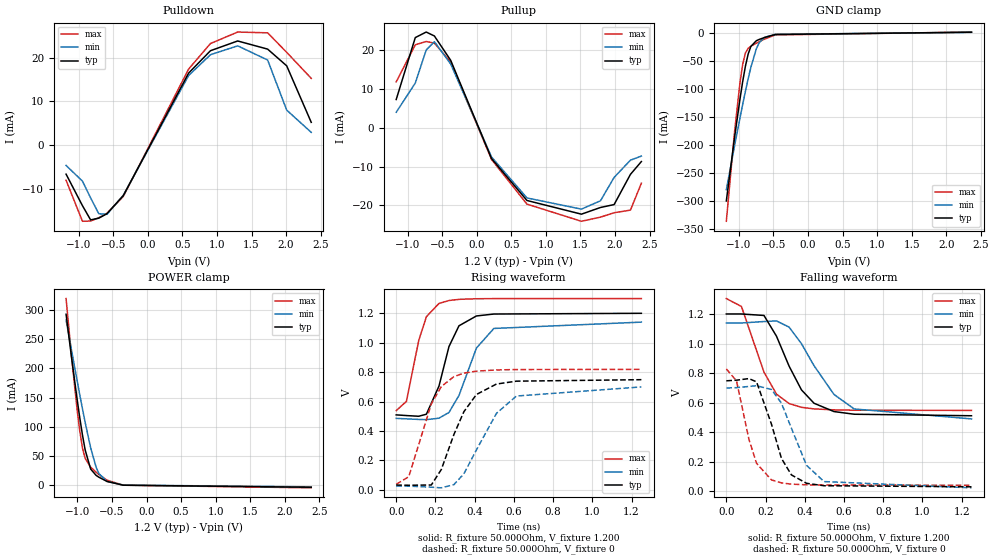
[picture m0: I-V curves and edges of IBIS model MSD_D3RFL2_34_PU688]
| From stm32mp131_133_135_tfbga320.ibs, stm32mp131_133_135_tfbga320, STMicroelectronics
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[Model] MSD_D3RFL2_34_PU688
Model_type   I/O
C_comp 2.464pF   2.377pF   2.591pF
Vinh = 820.000mV
Vinl = 380.000mV
Vmeas = 600.000mV
Vref = 600.000mV
[Model Spec]
Vinh   820.000mV   790.000mV   870.000mV
Vinl   380.000mV   350.000mV   430.000mV
Vmeas   600.000mV   570.000mV   650.000mV
Vref   600.000mV   570.000mV   650.000mV
[Receiver Thresholds]
Vth   =  0.600V
Vth_min  =  0.5880V
Vth_max  =  0.6120V
Vinh_ac  =  0.220V
Vinh_dc  =  0.130V
Vinl_ac  = -0.220V
Vinl_dc  = -0.130V
Tslew_ac =  5.000ns |Not specified, so set to high value
[Temperature Range]   25.000   125.000   -40.000
[Voltage Range]   1.200V   1.140V   1.300V
[GND Clamp Reference]   0.00V   0.00V   0.00V
[Pulldown Reference]   0.00V   0.00V   0.00V
[POWER Clamp Reference]   1.200V   1.140V   1.300V
[Pullup Reference]   1.200V   1.140V   1.300V
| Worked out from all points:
|   slope of the pulldown table from 0 to 0.18 V, typ, clamps not added: 31.3 ohm
|   slope of the pullup table from 0 to 0.18 V, typ, clamps not added: 26.5 ohm
|   GND clamp passes 1 mA (typ) near -0.40 V on its own axis
|   POWER clamp passes 1 mA (typ) near -0.41 V on its own axis
|   rising waveform, R_fixture 50.000Ohm, V_fixture 1.200: 20-80 % time 88.6ps typ, 117ps min, 75.3ps max; typ from 0.509 V to 1.2 V
|   rising waveform, R_fixture 50.000Ohm, V_fixture 0: 20-80 % time 140ps typ, 172ps min, 119ps max; typ from 0.032 V to 0.748 V
|   falling waveform, R_fixture 50.000Ohm, V_fixture 1.200: 20-80 % time 153ps typ, 198ps min, 128ps max; typ from 1.2 V to 0.512 V
|   falling waveform, R_fixture 50.000Ohm, V_fixture 0: 20-80 % time 98.8ps typ, 125ps min, 84.8ps max; typ from 0.748 V to 0.031 V
[GND Clamp]
-1.182V   -299.5mA   -279.5mA   -335.8mA
-1.064V   -187.3mA   -201.8mA   -177.4mA
-984.9mV  -117.9mA   -151.6mA   -88.56mA
-945.5mV  -86.48mA   -127.3mA   -55.74mA
-906.1mV  -59.08mA   -103.8mA   -35.61mA
-866.7mV  -37.56mA   -81.65mA   -27.19mA
-827.3mV  -23.76mA   -61.08mA   -23.39mA
-748.5mV  -13.58mA   -28.09mA   -17.94mA
-709.1mV  -11.39mA   -17.47mA   -15.42mA
-630.3mV  -7.849mA   -7.504mA   -10.69mA
-472.7mV  -2.436mA   -2.132mA   -3.171mA
2.364V    1.653mA    1.397mA    1.945mA
[Power Clamp]
-1.164V   292.6mA    282.9mA    319.4mA
-1.085V   218.8mA    231.1mA    220.2mA
-1.006V   148.6mA    180.3mA    131.2mA
-966.7mV  116mA      155.4mA    93.45mA
-927.3mV  86.24mA    131mA      64.09mA
-887.9mV  60.5mA     107.5mA    45.96mA
-809.1mV  27.9mA     64.44mA    31.21mA
-730.3mV  17.1mA     31.25mA    22.47mA
-690.9mV  14mA       20.4mA     18.6mA
-572.7mV  6.682mA    6.615mA    8.806mA
-336.4mV  202.2uA    381.9uA    225.6uA
2.382V    -3.312mA   -2.631mA   -4.291mA
[Pulldown]
-1.182V   -6.7mA     -4.7mA     -8.1mA
-945.5mV  -13.93mA   -8.3mA     -17.52mA
-827.3mV  -17.2mA    -12.14mA   -17.47mA
-709.1mV  -16.81mA   -15.79mA   -16.7mA
-590.9mV  -15.78mA   -15.93mA   -15.69mA
-354.6mV  -11.63mA   -11.56mA   -11.82mA
590.9mV   16.52mA    15.96mA    17.45mA
906.1mV   21.65mA    20.73mA    23.3mA
1.3V      23.89mA    22.77mA    25.94mA
1.733V    22.02mA    19.52mA    25.76mA
2.009V    18.18mA    8.01mA     21.28mA
2.364V    5.2mA      2.9mA      15.3mA
[Pullup]
-1.164V   7.3mA      4.009mA    11.85mA
-887.9mV  23.27mA    11.55mA    21.41mA
-730.3mV  24.7mA     20.06mA    22.27mA
-612.1mV  23.69mA    22.22mA    21.84mA
-375.8mV  17.4mA     16.45mA    16.97mA
215.2mV   -7.945mA   -7.529mA   -8.168mA
727.3mV   -18.74mA   -18.08mA   -19.68mA
1.515V    -22.27mA   -20.97mA   -24.1mA
1.791V    -20.54mA   -18.81mA   -23.03mA
1.988V    -19.79mA   -12.79mA   -21.9mA
2.224V    -12mA      -8.343mA   -21.22mA
2.382V    -8.7mA     -7.295mA   -14.29mA
[Ramp]
R_load=50.000Ohm
dV/dt_r   421.887mV/115.000ps  398.061mV/144.500ps  458.751mV/97.000ps
dV/dt_f   421.887mV/126.500ps  398.001mV/162.500ps  458.751mV/106.500ps
[Rising waveform]
R_fixture=50.000Ohm
V_fixture=1.200
V_fixture_min=1.140
V_fixture_max=1.300
0s        509.1mV    485.2mV    538.2mV
52ps      504.4mV    482.1mV    600.7mV
115ps     499.6mV    478mV      1.016V
154ps     513.8mV    476.7mV    1.177V
218ps     704.5mV    486.5mV    1.267V
269ps     973.6mV    525.2mV    1.287V
320ps     1.115V     640.9mV    1.295V
409ps     1.182V     963.4mV    1.299V
498ps     1.195V     1.097V     1.3V
1.25ns    1.2V       1.14V      1.3V
[Rising waveform]
R_fixture=50.000Ohm
V_fixture=0
0s        31.59mV    24.57mV    36.27mV
64ps      30.24mV    24.29mV    88.8mV
179ps     31.99mV    17.11mV    583.6mV
230ps     137.4mV    12.72mV    701.6mV
294ps     375mV      34.5mV     769.1mV
345ps     530.5mV    108mV      793.1mV
409ps     647.7mV    270.7mV    806.5mV
511ps     718.8mV    519.2mV    814.7mV
613ps     738.4mV    637.2mV    817.5mV
1.25ns    748.5mV    699.2mV    818.6mV
[Falling waveform]
R_fixture=50.000Ohm
V_fixture=1.200
V_fixture_min=1.140
V_fixture_max=1.300
0s        1.2V       1.139V     1.304V
77ps      1.2V       1.139V     1.251V
192ps     1.19V      1.149V     806.4mV
256ps     1.049V     1.153V     657.3mV
320ps     847.2mV    1.111V     594.2mV
383ps     686.7mV    999.3mV    568.6mV
447ps     596.2mV    850.4mV    557.8mV
549ps     539.8mV    655.4mV    551.4mV
652ps     521.8mV    557.5mV    549mV
1.25ns    511.5mV    490.3mV    547.6mV
[Falling waveform]
R_fixture=50.000Ohm
V_fixture=0
0s        747.9mV    699mV      828.2mV
52ps      752.1mV    701.8mV    747.2mV
115ps     762.9mV    709.7mV    353.6mV
154ps     741.1mV    714.6mV    189.6mV
230ps     455.2mV    689.5mV    77.58mV
281ps     223.1mV    597mV      57.33mV
332ps     111.2mV    426.6mV    48.85mV
409ps     54.49mV    176.1mV    44.01mV
498ps     38.14mV    66.15mV    42.44mV
1.25ns    30.82mV    23.87mV    41.93mV
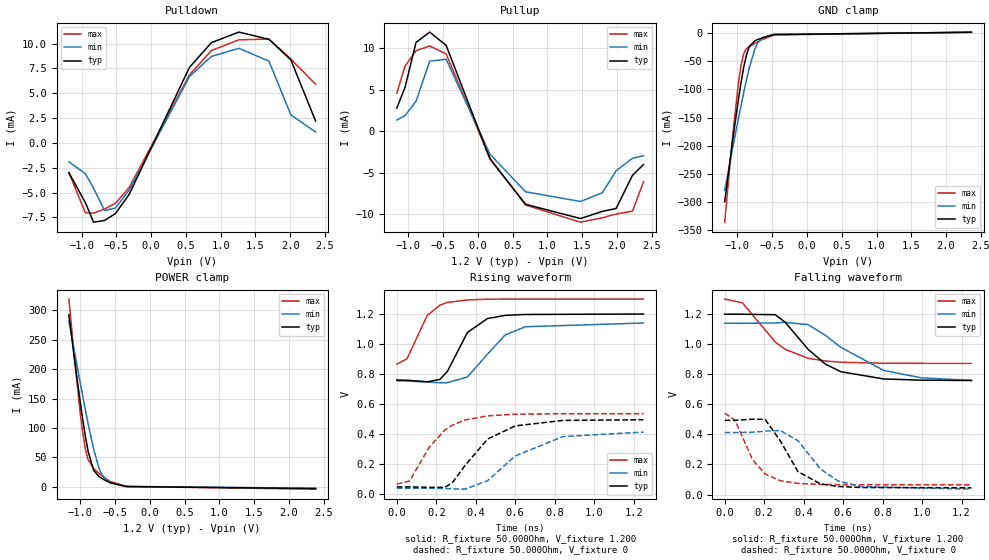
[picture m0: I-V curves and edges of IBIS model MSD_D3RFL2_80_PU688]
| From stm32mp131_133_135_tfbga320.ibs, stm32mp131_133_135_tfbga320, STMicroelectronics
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[Model] MSD_D3RFL2_80_PU688
Model_type   I/O
C_comp 2.464pF   2.377pF   2.591pF
Vinh = 820.000mV
Vinl = 380.000mV
Vmeas = 600.000mV
Vref = 600.000mV
[Model Spec]
Vinh   820.000mV   790.000mV   870.000mV
Vinl   380.000mV   350.000mV   430.000mV
Vmeas   600.000mV   570.000mV   650.000mV
Vref   600.000mV   570.000mV   650.000mV
[Receiver Thresholds]
Vth   =  0.600V
Vth_min  =  0.5880V
Vth_max  =  0.6120V
Vinh_ac  =  0.220V
Vinh_dc  =  0.130V
Vinl_ac  = -0.220V
Vinl_dc  = -0.130V
Tslew_ac =  5.000ns |Not specified, so set to high value
[Temperature Range]   25.000   125.000   -40.000
[Voltage Range]   1.200V   1.140V   1.300V
[GND Clamp Reference]   0.00V   0.00V   0.00V
[Pulldown Reference]   0.00V   0.00V   0.00V
[POWER Clamp Reference]   1.200V   1.140V   1.300V
[Pullup Reference]   1.200V   1.140V   1.300V
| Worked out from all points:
|   slope of the pulldown table from 0 to 0.18 V, typ, clamps not added: 63.6 ohm
|   slope of the pullup table from 0 to 0.18 V, typ, clamps not added: 52.8 ohm
|   GND clamp passes 1 mA (typ) near -0.40 V on its own axis
|   POWER clamp passes 1 mA (typ) near -0.41 V on its own axis
|   rising waveform, R_fixture 50.000Ohm, V_fixture 1.200: 20-80 % time 112ps typ, 150ps min, 98.3ps max; typ from 0.759 V to 1.2 V
|   rising waveform, R_fixture 50.000Ohm, V_fixture 0: 20-80 % time 186ps typ, 232ps min, 160ps max; typ from 0.045 V to 0.494 V
|   falling waveform, R_fixture 50.000Ohm, V_fixture 1.200: 20-80 % time 207ps typ, 279ps min, 190ps max; typ from 1.2 V to 0.759 V
|   falling waveform, R_fixture 50.000Ohm, V_fixture 0: 20-80 % time 121ps typ, 157ps min, 115ps max; typ from 0.494 V to 0.045 V
[GND Clamp]
-1.182V   -299.5mA   -279.5mA   -335.8mA
-1.064V   -187.3mA   -201.8mA   -177.4mA
-984.9mV  -117.9mA   -151.6mA   -88.56mA
-945.5mV  -86.48mA   -127.3mA   -55.74mA
-906.1mV  -59.08mA   -103.8mA   -35.61mA
-866.7mV  -37.56mA   -81.65mA   -27.19mA
-827.3mV  -23.76mA   -61.08mA   -23.39mA
-748.5mV  -13.58mA   -28.09mA   -17.94mA
-709.1mV  -11.39mA   -17.47mA   -15.42mA
-630.3mV  -7.849mA   -7.504mA   -10.69mA
-472.7mV  -2.436mA   -2.132mA   -3.171mA
2.364V    1.653mA    1.397mA    1.945mA
[Power Clamp]
-1.164V   292.6mA    282.9mA    319.4mA
-1.085V   218.8mA    231.1mA    220.2mA
-1.006V   148.6mA    180.3mA    131.2mA
-966.7mV  116mA      155.4mA    93.45mA
-927.3mV  86.24mA    131mA      64.09mA
-887.9mV  60.5mA     107.5mA    45.96mA
-809.1mV  27.9mA     64.44mA    31.21mA
-730.3mV  17.1mA     31.25mA    22.47mA
-690.9mV  14mA       20.4mA     18.6mA
-572.7mV  6.682mA    6.615mA    8.806mA
-336.4mV  202.2uA    381.9uA    225.6uA
2.382V    -3.312mA   -2.631mA   -4.291mA
[Pulldown]
-1.182V   -3mA       -1.9mA     -3mA
-945.5mV  -6mA       -3.1mA     -7.01mA
-827.3mV  -7.98mA    -4.55mA    -7.07mA
-669.7mV  -7.81mA    -6.81mA    -6.66mA
-512.1mV  -7.105mA   -6.552mA   -6.074mA
-315.1mV  -5.18mA    -4.739mA   -4.478mA
551.5mV   7.6mA      6.678mA    6.842mA
866.7mV   10.09mA    8.7mA      9.292mA
1.261V    11.15mA    9.517mA    10.37mA
1.694V    10.42mA    8.227mA    10.45mA
2.009V    8.35mA     2.81mA     8.44mA
2.364V    2.2mA      1.1mA      5.9mA
[Pullup]
-1.164V   2.8mA      1.352mA    4.608mA
-1.045V   5.3mA      1.905mA    7.869mA
-887.9mV  10.71mA    3.619mA    9.709mA
-690.9mV  11.96mA    8.46mA     10.29mA
-454.5mV  10.36mA    8.683mA    9.332mA
175.8mV   -3.334mA   -2.766mA   -3.264mA
687.9mV   -8.798mA   -7.289mA   -8.882mA
1.476V    -10.51mA   -8.455mA   -10.95mA
1.791V    -9.648mA   -7.4mA     -10.42mA
1.988V    -9.3mA     -4.754mA   -9.962mA
2.224V    -5.3mA     -3.248mA   -9.62mA
2.382V    -4mA       -2.948mA   -6.085mA
[Ramp]
R_load=50.000Ohm
dV/dt_r   267.108mV/150.500ps  229.044mV/193.000ps  268.920mV/129.500ps
dV/dt_f   267.108mV/165.000ps  229.017mV/222.500ps  268.920mV/152.500ps
[Rising waveform]
R_fixture=50.000Ohm
V_fixture=1.200
V_fixture_min=1.140
V_fixture_max=1.300
0s        759.4mV    753.7mV    864.7mV
52ps      757.5mV    752.1mV    901.4mV
154ps     747.4mV    745.6mV    1.19V
218ps     762.7mV    741.2mV    1.259V
256ps     815.9mV    741mV      1.277V
358ps     1.077V     779.3mV    1.294V
460ps     1.17V      932.4mV    1.299V
549ps     1.191V     1.06V      1.3V
652ps     1.197V     1.115V     1.3V
1.25ns    1.2V       1.14V      1.3V
[Rising waveform]
R_fixture=50.000Ohm
V_fixture=0
0s        44.61mV    35.71mV    62.72mV
64ps      44.95mV    35.91mV    83.8mV
166ps     42.13mV    35.83mV    312.9mV
243ps     41.74mV    33.99mV    425mV
281ps     71.96mV    32.04mV    457.3mV
345ps     186.9mV    29.79mV    491.8mV
460ps     364.6mV    86.08mV    519.7mV
600ps     452.5mV    251.8mV    530.4mV
843ps     489.2mV    381.6mV    533.8mV
1.25ns    493.9mV    411.3mV    534.2mV
[Falling waveform]
R_fixture=50.000Ohm
V_fixture=1.200
V_fixture_min=1.140
V_fixture_max=1.300
0s        1.2V       1.14V      1.301V
90ps      1.2V       1.14V      1.276V
256ps     1.197V     1.142V     1.015V
307ps     1.146V     1.146V     966.2mV
422ps     967.4mV    1.131V     906.8mV
511ps     867.2mV    1.059V     888.6mV
588ps     817.5mV    980mV      880.6mV
805ps     769.4mV    826mV      873.8mV
996ps     761.1mV    777mV      873mV
1.25ns    759.2mV    759.2mV    872.9mV
[Falling waveform]
R_fixture=50.000Ohm
V_fixture=0
0s        493.9mV    412.6mV    541.5mV
52ps      493.6mV    412.3mV    495.2mV
141ps     501.5mV    414.6mV    231.9mV
205ps     500.2mV    421.8mV    136.9mV
281ps     358.7mV    426mV      92.08mV
371ps     152.7mV    358.7mV    73.89mV
486ps     70.51mV    168.8mV    67.28mV
575ps     53.71mV    89.81mV    65.73mV
690ps     46.77mV    52.98mV    65.21mV
1.25ns    44.53mV    35.68mV    65.1mV
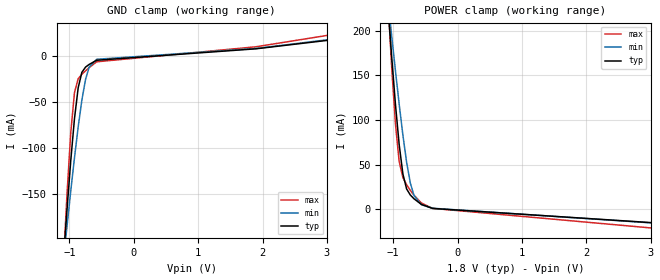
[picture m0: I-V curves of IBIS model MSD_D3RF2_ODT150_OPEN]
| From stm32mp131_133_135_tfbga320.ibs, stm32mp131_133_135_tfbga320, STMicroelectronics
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[Model] MSD_D3RF2_ODT150_OPEN
Model_type   Input
C_comp 2.506pF   2.436pF   2.576pF
Vinh = 1.150V
Vinl = 650.000mV
[Temperature Range]   25.000   125.000   -40.000
[Voltage Range]   1.800V   1.700V   1.900V
[GND Clamp Reference]   0.00V   0.00V   0.00V
[POWER Clamp Reference]   1.800V   1.700V   1.900V
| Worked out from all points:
|   GND clamp passes 1 mA (typ) near -0.42 V on its own axis
|   POWER clamp passes 1 mA (typ) near -0.40 V on its own axis
[GND Clamp]
-1.785V   -950.9mA   -708.4mA   -1.315A
-1.094V   -222.1mA   -223mA     -227mA
-1.036V   -166.1mA   -184.4mA   -148.9mA
-978.8mV  -113.8mA   -146.8mA   -83.33mA
-921.2mV  -68.29mA   -110.8mA   -40.07mA
-863.6mV  -34.75mA   -77.32mA   -24.91mA
-806.1mV  -17.9mA    -47.97mA   -20mA
-748.5mV  -12.2mA    -25.39mA   -16.22mA
-690.9mV  -9.269mA   -11.95mA   -12.69mA
-575.8mV  -4.789mA   -3.741mA   -6.474mA
1.9V      7.65mA     8.034mA    9.858mA
3.57V     21.46mA    22.24mA    28.5mA
[Power Clamp]
-1.77V    962.3mA    725.2mA    1.318A
-1.079V   226mA      232.6mA    231.3mA
-1.021V   169.3mA    193.2mA    157.2mA
-963.6mV  117mA      154.8mA    95.1mA
-906.1mV  72.21mA    117.6mA    53.36mA
-848.5mV  39.42mA    82.99mA    35.44mA
-790.9mV  22.71mA    52.65mA    27.43mA
-733.3mV  15.92mA    29.39mA    21.13mA
-675.8mV  11.65mA    15.21mA    15.61mA
-560.6mV  5.32mA     5.058mA    6.918mA
-387.9mV  838.6uA    1.08mA     945uA
3.585V    -17.76mA   -18.18mA   -24.79mA
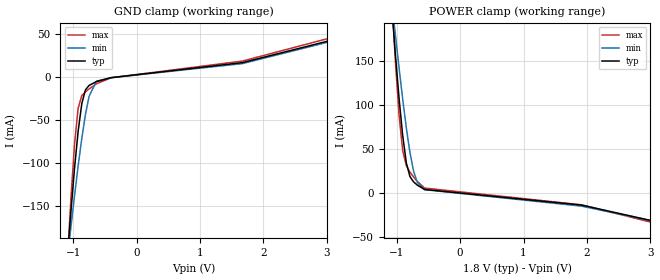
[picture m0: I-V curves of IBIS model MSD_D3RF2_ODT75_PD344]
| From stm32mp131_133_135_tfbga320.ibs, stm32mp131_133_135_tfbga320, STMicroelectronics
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[Model] MSD_D3RF2_ODT75_PD344
Model_type   Input
C_comp 2.244pF   2.179pF   2.307pF
Vinh = 1.150V
Vinl = 650.000mV
[Temperature Range]   25.000   125.000   -40.000
[Voltage Range]   1.800V   1.700V   1.900V
[GND Clamp Reference]   0.00V   0.00V   0.00V
[POWER Clamp Reference]   1.800V   1.700V   1.900V
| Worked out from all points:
|   GND clamp passes 1 mA (typ) near -0.46 V on its own axis
|   POWER clamp passes 1 mA (typ) near -0.38 V on its own axis
[GND Clamp]
-1.785V   -932.7mA   -691.1mA   -1.299A
-1.094V   -212mA     -212.8mA   -219.3mA
-1.036V   -157.3mA   -175mA     -142.6mA
-978.8mV  -106.5mA   -138.3mA   -78.43mA
-921.2mV  -62.81mA   -103.4mA   -35.94mA
-863.6mV  -30.66mA   -71.07mA   -21.28mA
-806.1mV  -14.55mA   -43.18mA   -16.81mA
-748.5mV  -9.369mA   -22.01mA   -13.47mA
-633.3mV  -4.952mA   -4.464mA   -7.527mA
-403mV    -368.8uA   -375.4uA   -494.2uA
1.67V     17.2mA     16.01mA    19mA
3.57V     52.52mA    51.33mA    55.97mA
[Power Clamp]
-1.77V    938.8mA    702.7mA    1.3A
-1.079V   212.4mA    218.3mA    222.8mA
-1.021V   157.9mA    180mA      150.4mA
-963.6mV  108.2mA    142.7mA    89.33mA
-906.1mV  65.75mA    107mA      48.46mA
-848.5mV  34.44mA    74.14mA    31.27mA
-790.9mV  18.73mA    46mA       23.95mA
-733.3mV  12.73mA    24.88mA    18.27mA
-675.8mV  9.164mA    12.33mA    13.34mA
-560.6mV  4.15mA     3.932mA    5.752mA
1.915V    -13.59mA   -14.78mA   -13.27mA
3.585V    -40.32mA   -39.95mA   -43.42mA
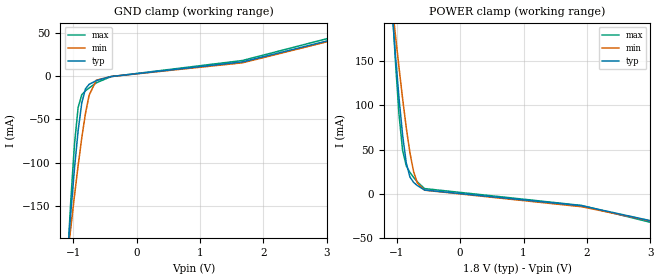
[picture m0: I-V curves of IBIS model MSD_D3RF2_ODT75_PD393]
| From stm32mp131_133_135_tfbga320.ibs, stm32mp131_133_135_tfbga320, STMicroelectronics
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[Model] MSD_D3RF2_ODT75_PD393
Model_type   Input
C_comp 2.273pF   2.209pF   2.337pF
Vinh = 1.150V
Vinl = 650.000mV
[Temperature Range]   25.000   125.000   -40.000
[Voltage Range]   1.800V   1.700V   1.900V
[GND Clamp Reference]   0.00V   0.00V   0.00V
[POWER Clamp Reference]   1.800V   1.700V   1.900V
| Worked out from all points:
|   GND clamp passes 1 mA (typ) near -0.46 V on its own axis
|   POWER clamp passes 1 mA (typ) near -0.38 V on its own axis
[GND Clamp]
-1.785V   -933.2mA   -691.5mA   -1.3A
-1.094V   -212.3mA   -213mA     -219.5mA
-1.036V   -157.5mA   -175.2mA   -142.8mA
-978.8mV  -106.7mA   -138.5mA   -78.71mA
-921.2mV  -62.97mA   -103.5mA   -36.14mA
-863.6mV  -30.79mA   -71.19mA   -21.45mA
-806.1mV  -14.67mA   -43.28mA   -16.96mA
-748.5mV  -9.465mA   -22.09mA   -13.59mA
-633.3mV  -5.024mA   -4.518mA   -7.615mA
-403mV    -382.8uA   -388.6uA   -510.2uA
1.67V     16.58mA    15.5mA     18.19mA
3.57V     51.17mA    50.23mA    54.24mA
[Power Clamp]
-1.77V    939.2mA    703.1mA    1.3A
-1.079V   212.6mA    218.5mA    223mA
-1.021V   158mA      180.2mA    150.6mA
-963.6mV  108.3mA    142.8mA    89.53mA
-906.1mV  65.87mA    107.1mA    48.67mA
-848.5mV  34.58mA    74.29mA    31.46mA
-790.9mV  18.85mA    46.11mA    24.1mA
-733.3mV  12.82mA    24.99mA    18.4mA
-675.8mV  9.248mA    12.42mA    13.45mA
-560.6mV  4.2mA      3.996mA    5.818mA
1.915V    -13.55mA   -14.72mA   -13.27mA
3.585V    -39.64mA   -39.37mA   -42.6mA
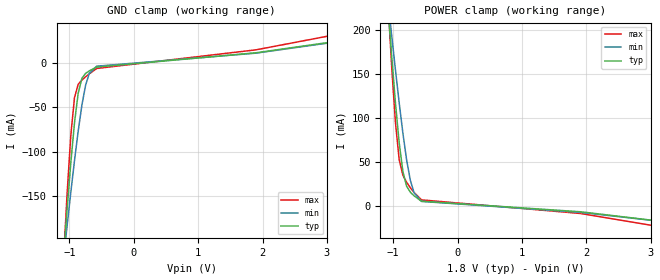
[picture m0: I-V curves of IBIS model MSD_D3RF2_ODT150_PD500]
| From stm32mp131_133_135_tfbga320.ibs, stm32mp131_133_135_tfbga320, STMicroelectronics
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[Model] MSD_D3RF2_ODT150_PD500
Model_type   Input
C_comp 2.345pF   2.278pF   2.411pF
Vinh = 1.150V
Vinl = 650.000mV
[Temperature Range]   25.000   125.000   -40.000
[Voltage Range]   1.800V   1.700V   1.900V
[GND Clamp Reference]   0.00V   0.00V   0.00V
[POWER Clamp Reference]   1.800V   1.700V   1.900V
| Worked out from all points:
|   GND clamp passes 1 mA (typ) near -0.43 V on its own axis
|   POWER clamp passes 1 mA (typ) near -0.40 V on its own axis
[GND Clamp]
-1.785V   -948.6mA   -706.4mA   -1.311A
-1.094V   -221mA     -222mA     -225.6mA
-1.036V   -165.1mA   -183.6mA   -147.6mA
-978.8mV  -112.9mA   -146.1mA   -82.11mA
-921.2mV  -67.46mA   -110.1mA   -38.99mA
-863.6mV  -34.01mA   -76.71mA   -23.95mA
-806.1mV  -17.26mA   -47.45mA   -19.16mA
-748.5mV  -11.66mA   -24.94mA   -15.49mA
-690.9mV  -8.819mA   -11.59mA   -12.09mA
-575.8mV  -4.501mA   -3.501mA   -6.092mA
1.9V      11.6mA     11.19mA    14.92mA
3.57V     28.83mA    28.13mA    38mA
[Power Clamp]
-1.77V    959.8mA    723mA      1.315A
-1.079V   224.7mA    231.5mA    229.7mA
-1.021V   168.3mA    192.3mA    155.8mA
-963.6mV  116.1mA    153.9mA    93.8mA
-906.1mV  71.35mA    116.8mA    52.25mA
-848.5mV  38.67mA    82.3mA     34.46mA
-790.9mV  22.07mA    52.06mA    26.59mA
-733.3mV  15.37mA    28.89mA    20.41mA
-675.8mV  11.2mA     14.8mA     15.01mA
-560.6mV  5.058mA    4.791mA    6.563mA
1.915V    -6.983mA   -7.687mA   -8.927mA
3.585V    -21.51mA   -21.36mA   -29.3mA
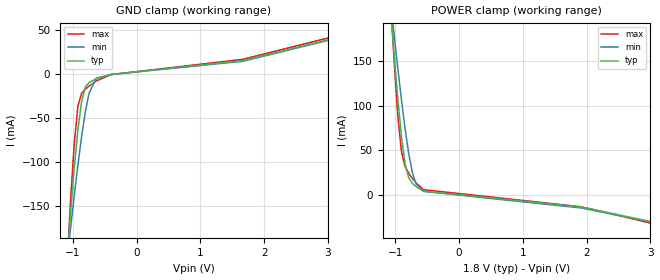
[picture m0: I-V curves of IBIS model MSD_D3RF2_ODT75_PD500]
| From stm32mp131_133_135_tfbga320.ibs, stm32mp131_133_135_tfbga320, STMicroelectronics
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[Model] MSD_D3RF2_ODT75_PD500
Model_type   Input
C_comp 2.320pF   2.255pF   2.385pF
Vinh = 1.150V
Vinl = 650.000mV
[Temperature Range]   25.000   125.000   -40.000
[Voltage Range]   1.800V   1.700V   1.900V
[GND Clamp Reference]   0.00V   0.00V   0.00V
[POWER Clamp Reference]   1.800V   1.700V   1.900V
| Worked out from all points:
|   GND clamp passes 1 mA (typ) near -0.46 V on its own axis
|   POWER clamp passes 1 mA (typ) near -0.38 V on its own axis
[GND Clamp]
-1.785V   -933.8mA   -692mA     -1.301A
-1.094V   -212.6mA   -213.2mA   -219.9mA
-1.036V   -157.8mA   -175.4mA   -143.2mA
-978.8mV  -106.9mA   -138.7mA   -79.02mA
-921.2mV  -63.19mA   -103.7mA   -36.44mA
-863.6mV  -30.99mA   -71.35mA   -21.71mA
-806.1mV  -14.85mA   -43.42mA   -17.19mA
-748.5mV  -9.624mA   -22.21mA   -13.79mA
-633.3mV  -5.117mA   -4.598mA   -7.747mA
-403mV    -403.8uA   -413.4uA   -534.2uA
1.67V     15.63mA    14.75mA    16.99mA
3.57V     49.09mA    48.68mA    51.64mA
[Power Clamp]
-1.77V    940mA      703.7mA    1.301A
-1.079V   213mA      218.7mA    223.5mA
-1.021V   158.4mA    180.4mA    151mA
-963.6mV  108.6mA    143mA      89.9mA
-906.1mV  66.14mA    107.3mA    48.97mA
-848.5mV  34.82mA    74.44mA    31.73mA
-790.9mV  19.06mA    46.25mA    24.33mA
-733.3mV  13mA       25.1mA     18.6mA
-675.8mV  9.406mA    12.52mA    13.61mA
-560.6mV  4.3mA      4.045mA    5.919mA
1.915V    -13.48mA   -14.62mA   -13.26mA
3.585V    -38.62mA   -38.51mA   -41.37mA
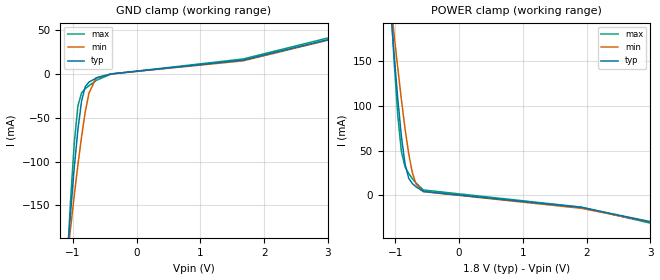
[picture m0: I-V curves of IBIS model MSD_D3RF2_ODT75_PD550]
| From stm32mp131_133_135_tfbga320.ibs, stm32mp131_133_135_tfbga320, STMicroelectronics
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[Model] MSD_D3RF2_ODT75_PD550
Model_type   Input
C_comp 2.332pF   2.267pF   2.398pF
Vinh = 1.150V
Vinl = 650.000mV
[Temperature Range]   25.000   125.000   -40.000
[Voltage Range]   1.800V   1.700V   1.900V
[GND Clamp Reference]   0.00V   0.00V   0.00V
[POWER Clamp Reference]   1.800V   1.700V   1.900V
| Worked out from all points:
|   GND clamp passes 1 mA (typ) near -0.46 V on its own axis
|   POWER clamp passes 1 mA (typ) near -0.38 V on its own axis
[GND Clamp]
-1.785V   -934mA     -692.2mA   -1.301A
-1.094V   -212.7mA   -213.3mA   -220.1mA
-1.036V   -157.8mA   -175.5mA   -143.3mA
-978.8mV  -107mA     -138.7mA   -79.16mA
-921.2mV  -63.27mA   -103.7mA   -36.54mA
-863.6mV  -31.06mA   -71.41mA   -21.8mA
-806.1mV  -14.9mA    -43.46mA   -17.27mA
-748.5mV  -9.667mA   -22.25mA   -13.86mA
-633.3mV  -5.158mA   -4.627mA   -7.793mA
-403mV    -410.8uA   -416.4uA   -543.6uA
1.67V     15.32mA    14.49mA    16.58mA
3.57V     48.51mA    48.09mA    50.77mA
[Power Clamp]
-1.77V    940.1mA    704mA      1.301A
-1.079V   213mA      218.9mA    223.6mA
-1.021V   158.4mA    180.6mA    151.1mA
-963.6mV  108.7mA    143.2mA    90mA
-906.1mV  66.17mA    107.4mA    49.07mA
-848.5mV  34.84mA    74.54mA    31.82mA
-790.9mV  19.07mA    46.33mA    24.41mA
-733.3mV  13.02mA    25.18mA    18.66mA
-675.8mV  9.402mA    12.58mA    13.67mA
-560.6mV  4.29mA     4.089mA    5.955mA
1.915V    -13.46mA   -14.59mA   -13.25mA
3.585V    -38.27mA   -38.21mA   -40.95mA
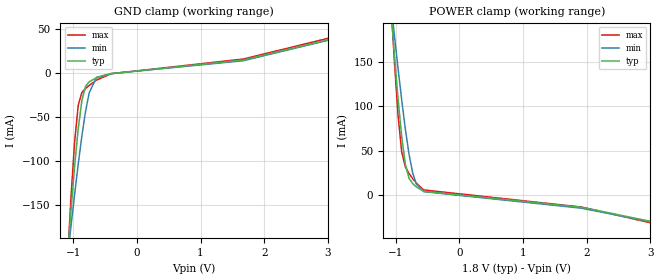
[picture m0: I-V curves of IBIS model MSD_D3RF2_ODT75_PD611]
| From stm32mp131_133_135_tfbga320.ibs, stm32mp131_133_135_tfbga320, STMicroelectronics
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[Model] MSD_D3RF2_ODT75_PD611
Model_type   Input
C_comp 2.350pF   2.284pF   2.415pF
Vinh = 1.150V
Vinl = 650.000mV
[Temperature Range]   25.000   125.000   -40.000
[Voltage Range]   1.800V   1.700V   1.900V
[GND Clamp Reference]   0.00V   0.00V   0.00V
[POWER Clamp Reference]   1.800V   1.700V   1.900V
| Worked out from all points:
|   GND clamp passes 1 mA (typ) near -0.46 V on its own axis
|   POWER clamp passes 1 mA (typ) near -0.38 V on its own axis
[GND Clamp]
-1.785V   -934.2mA   -692.4mA   -1.301A
-1.094V   -212.8mA   -213.3mA   -220.2mA
-1.036V   -157.9mA   -175.6mA   -143.4mA
-978.8mV  -107.1mA   -138.9mA   -79.2mA
-921.2mV  -63.35mA   -103.8mA   -36.64mA
-863.6mV  -31.13mA   -71.46mA   -21.89mA
-806.1mV  -14.97mA   -43.52mA   -17.34mA
-748.5mV  -9.72mA    -22.29mA   -13.92mA
-633.3mV  -5.189mA   -4.654mA   -7.837mA
-403mV    -417.8uA   -418uA     -551.6uA
1.67V     15.01mA    14.24mA    16.18mA
3.57V     47.8mA     47.57mA    49.91mA
[Power Clamp]
-1.77V    940.4mA    704.2mA    1.302A
-1.079V   213.2mA    219mA      223.7mA
-1.021V   158.6mA    180.6mA    151.2mA
-963.6mV  108.8mA    143.2mA    90.1mA
-906.1mV  66.27mA    107.5mA    49.17mA
-848.5mV  34.93mA    74.6mA     31.9mA
-790.9mV  19.15mA    46.38mA    24.49mA
-733.3mV  13.08mA    25.21mA    18.73mA
-675.8mV  9.466mA    12.61mA    13.72mA
-560.6mV  4.33mA     4.109mA    5.982mA
1.915V    -13.44mA   -14.55mA   -13.25mA
3.585V    -37.93mA   -37.93mA   -40.54mA
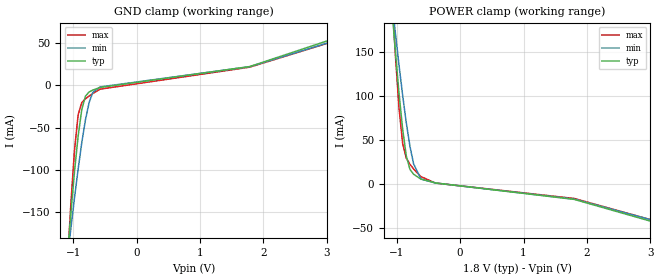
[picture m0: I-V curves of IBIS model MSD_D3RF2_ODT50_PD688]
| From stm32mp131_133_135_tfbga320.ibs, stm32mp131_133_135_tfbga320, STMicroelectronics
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[Model] MSD_D3RF2_ODT50_PD688
Model_type   Input
C_comp 2.340pF   2.301pF   2.370pF
Vinh = 1.150V
Vinl = 650.000mV
[Temperature Range]   25.000   125.000   -40.000
[Voltage Range]   1.800V   1.700V   1.900V
[GND Clamp Reference]   0.00V   0.00V   0.00V
[POWER Clamp Reference]   1.800V   1.700V   1.900V
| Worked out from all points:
|   GND clamp passes 1 mA (typ) near -0.48 V on its own axis
|   POWER clamp passes 1 mA (typ) near -0.31 V on its own axis
[GND Clamp]
-1.785V   -920.4mA   -680.8mA   -1.291A
-1.094V   -205.3mA   -206.6mA   -215.5mA
-1.036V   -151.6mA   -169.3mA   -140.2mA
-978.8mV  -102.3mA   -133.4mA   -77.12mA
-921.2mV  -60.05mA   -99.18mA   -35.01mA
-863.6mV  -28.69mA   -67.81mA   -20.48mA
-806.1mV  -12.96mA   -40.92mA   -16.1mA
-748.5mV  -8.038mA   -20.55mA   -12.85mA
-690.9mV  -5.802mA   -8.64mA    -9.844mA
-575.8mV  -2.66mA    -2.048mA   -4.67mA
1.785V    22.04mA    21.89mA    21.33mA
3.57V     66.38mA    62.57mA    62.41mA
[Power Clamp]
-1.77V    921.9mA    689.8mA    1.288A
-1.079V   203.1mA    209.4mA    218.1mA
-1.021V   150.7mA    171.8mA    146.9mA
-963.6mV  103.2mA    135.2mA    86.58mA
-906.1mV  62.36mA    100.8mA    46.22mA
-848.5mV  31.91mA    69.45mA    29.46mA
-790.9mV  16.79mA    42.89mA    22.49mA
-733.3mV  11.26mA    23mA       17.14mA
-618.2mV  5.764mA    5.826mA    8.598mA
-387.9mV  1.358mA    1.278mA    1.195mA
1.8V      -17.31mA   -16.95mA   -16.28mA
3.585V    -54.01mA   -51.65mA   -51.94mA
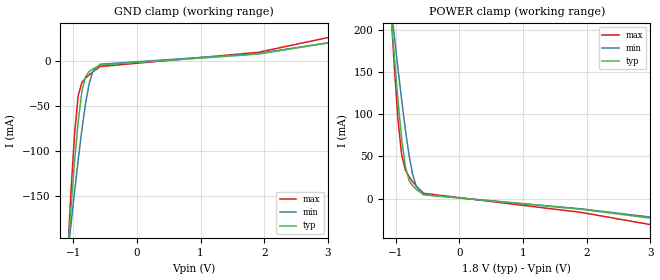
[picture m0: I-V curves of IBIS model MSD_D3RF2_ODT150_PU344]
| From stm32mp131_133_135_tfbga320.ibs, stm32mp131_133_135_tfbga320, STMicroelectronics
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[Model] MSD_D3RF2_ODT150_PU344
Model_type   Input
C_comp 2.271pF   2.205pF   2.336pF
Vinh = 1.150V
Vinl = 650.000mV
[Temperature Range]   25.000   125.000   -40.000
[Voltage Range]   1.800V   1.700V   1.900V
[GND Clamp Reference]   0.00V   0.00V   0.00V
[POWER Clamp Reference]   1.800V   1.700V   1.900V
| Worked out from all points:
|   GND clamp passes 1 mA (typ) near -0.43 V on its own axis
|   POWER clamp passes 1 mA (typ) near -0.41 V on its own axis
[GND Clamp]
-1.785V   -947.4mA   -705.3mA   -1.31A
-1.094V   -220.4mA   -221.5mA   -224.9mA
-1.036V   -164.5mA   -183.1mA   -147mA
-978.8mV  -112.4mA   -145.6mA   -81.57mA
-921.2mV  -67.05mA   -109.8mA   -38.52mA
-863.6mV  -33.66mA   -76.4mA    -23.53mA
-806.1mV  -16.94mA   -47.18mA   -18.79mA
-748.5mV  -11.39mA   -24.71mA   -15.19mA
-690.9mV  -8.59mA    -11.39mA   -11.83mA
-575.8mV  -4.362mA   -3.376mA   -5.94mA
1.9V      7.95mA     8.521mA    9.858mA
3.57V     26.77mA    26.8mA     34.86mA
[Power Clamp]
-1.77V    958.7mA    722.2mA    1.314A
-1.079V   224.2mA    231.1mA    229mA
-1.021V   167.8mA    191.9mA    155.2mA
-963.6mV  115.6mA    153.5mA    93.33mA
-906.1mV  70.97mA    116.5mA    51.78mA
-848.5mV  38.33mA    82.05mA    34.05mA
-790.9mV  21.78mA    51.84mA    26.23mA
-733.3mV  15.12mA    28.7mA     20.11mA
-675.8mV  10.99mA    14.65mA    14.77mA
-560.6mV  4.928mA    4.703mA    6.425mA
1.915V    -12.45mA   -11.96mA   -16.14mA
3.585V    -28.43mA   -26.81mA   -38.3mA
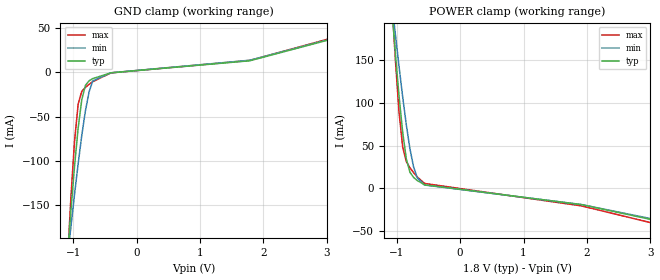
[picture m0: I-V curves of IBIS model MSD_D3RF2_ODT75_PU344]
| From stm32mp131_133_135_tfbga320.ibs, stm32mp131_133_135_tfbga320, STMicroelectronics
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[Model] MSD_D3RF2_ODT75_PU344
Model_type   Input
C_comp 2.246pF   2.182pF   2.310pF
Vinh = 1.150V
Vinl = 650.000mV
[Temperature Range]   25.000   125.000   -40.000
[Voltage Range]   1.800V   1.700V   1.900V
[GND Clamp Reference]   0.00V   0.00V   0.00V
[POWER Clamp Reference]   1.800V   1.700V   1.900V
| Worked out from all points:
|   GND clamp passes 1 mA (typ) near -0.46 V on its own axis
|   POWER clamp passes 1 mA (typ) near -0.38 V on its own axis
[GND Clamp]
-1.785V   -932.7mA   -690.9mA   -1.299A
-1.094V   -212.1mA   -212.7mA   -219.2mA
-1.036V   -157.2mA   -175mA     -142.5mA
-978.8mV  -106.6mA   -138.2mA   -78.46mA
-921.2mV  -62.85mA   -103.3mA   -35.94mA
-863.6mV  -30.68mA   -71.02mA   -21.27mA
-806.1mV  -14.57mA   -43.13mA   -16.81mA
-748.5mV  -9.398mA   -21.95mA   -13.46mA
-690.9mV  -6.922mA   -9.548mA   -10.38mA
-403mV    -392uA     -358uA     -486uA
1.785V    13.21mA    13.81mA    13.59mA
3.57V     47.04mA    47.36mA    48.52mA
[Power Clamp]
-1.77V    939mA      702.9mA    1.3A
-1.079V   212.4mA    218.4mA    222.8mA
-1.021V   157.9mA    180mA      150.4mA
-963.6mV  108.2mA    142.7mA    89.34mA
-906.1mV  65.75mA    107mA      48.48mA
-848.5mV  34.48mA    74.18mA    31.3mA
-790.9mV  18.76mA    46.03mA    23.97mA
-733.3mV  12.76mA    24.91mA    18.29mA
-675.8mV  9.194mA    12.36mA    13.35mA
-560.6mV  4.178mA    3.944mA    5.769mA
1.915V    -18.94mA   -18.9mA    -20.47mA
3.585V    -45.44mA   -44.01mA   -50.4mA
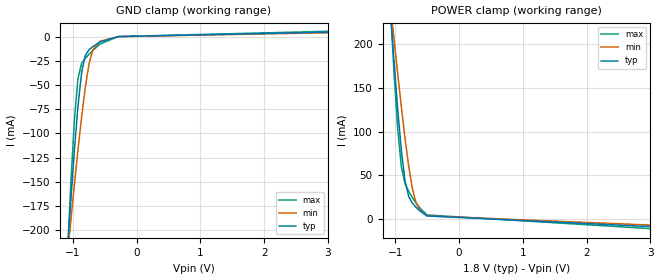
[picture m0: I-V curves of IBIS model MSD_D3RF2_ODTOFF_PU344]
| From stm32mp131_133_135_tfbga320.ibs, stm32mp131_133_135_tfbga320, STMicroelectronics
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[Model] MSD_D3RF2_ODTOFF_PU344
Model_type   Input
C_comp 2.315pF   2.235pF   2.435pF
Vinh = 1.150V
Vinl = 650.000mV
[Temperature Range]   25.000   125.000   -40.000
[Voltage Range]   1.800V   1.700V   1.900V
[GND Clamp Reference]   0.00V   0.00V   0.00V
[POWER Clamp Reference]   1.800V   1.700V   1.900V
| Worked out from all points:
|   GND clamp passes 1 mA (typ) near -0.41 V on its own axis
|   POWER clamp passes 1 mA (typ) near -0.41 V on its own axis
[GND Clamp]
-1.785V   -962.8mA   -720.6mA   -1.332A
-1.094V   -229.5mA   -231.4mA   -236.8mA
-1.036V   -172.8mA   -192.3mA   -156.5mA
-978.8mV  -119.3mA   -154.1mA   -88.14mA
-921.2mV  -72.33mA   -117.4mA   -43.37mA
-863.6mV  -37.33mA   -83.07mA   -27.73mA
-806.1mV  -19.74mA   -52.63mA   -22.5mA
-748.5mV  -13.74mA   -28.75mA   -18.43mA
-690.9mV  -10.6mA    -14.18mA   -14.62mA
-575.8mV  -5.686mA   -4.838mA   -7.794mA
-287.9mV  -67.99uA   -116uA     -53.99uA
3.57V     5.311mA    4.566mA    6.357mA
[Power Clamp]
-1.77V    979.8mA    743.1mA    1.343A
-1.079V   237.5mA    245.2mA    243.7mA
-1.021V   179.4mA    205.2mA    166.7mA
-963.6mV  125.1mA    166mA      102.4mA
-906.1mV  77.93mA    127.9mA    59.35mA
-848.5mV  43.29mA    92.01mA    40.4mA
-790.9mV  25.57mA    59.98mA    31.52mA
-733.3mV  18.14mA    34.65mA    24.45mA
-675.8mV  13.35mA    18.49mA    18.23mA
-618.2mV  9.415mA    10.22mA    12.8mA
-503mV    3.523mA    3.613mA    4.651mA
3.585V    -10.66mA   -8.625mA   -13.56mA
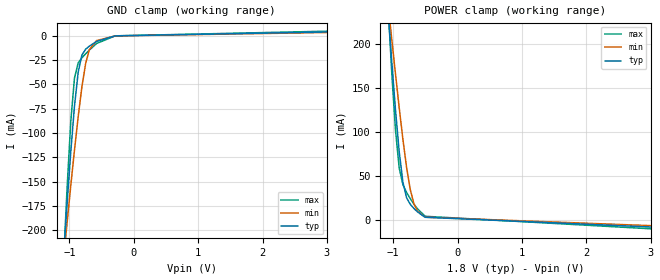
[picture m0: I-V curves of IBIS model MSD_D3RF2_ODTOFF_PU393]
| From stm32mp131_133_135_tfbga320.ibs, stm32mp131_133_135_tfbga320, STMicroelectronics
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[Model] MSD_D3RF2_ODTOFF_PU393
Model_type   Input
C_comp 2.345pF   2.264pF   2.465pF
Vinh = 1.150V
Vinl = 650.000mV
[Temperature Range]   25.000   125.000   -40.000
[Voltage Range]   1.800V   1.700V   1.900V
[GND Clamp Reference]   0.00V   0.00V   0.00V
[POWER Clamp Reference]   1.800V   1.700V   1.900V
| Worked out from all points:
|   GND clamp passes 1 mA (typ) near -0.40 V on its own axis
|   POWER clamp passes 1 mA (typ) near -0.41 V on its own axis
[GND Clamp]
-1.785V   -963.3mA   -721mA     -1.333A
-1.094V   -229.8mA   -231.5mA   -237.1mA
-1.036V   -172.9mA   -192.4mA   -156.7mA
-978.8mV  -119.5mA   -154.2mA   -88.36mA
-921.2mV  -72.5mA    -117.6mA   -43.56mA
-863.6mV  -37.48mA   -83.18mA   -27.89mA
-806.1mV  -19.86mA   -52.72mA   -22.66mA
-748.5mV  -13.84mA   -28.83mA   -18.57mA
-690.9mV  -10.68mA   -14.25mA   -14.73mA
-575.8mV  -5.741mA   -4.882mA   -7.866mA
-287.9mV  -69.99uA   -118uA     -54.99uA
3.57V     4.647mA    3.996mA    5.563mA
[Power Clamp]
-1.77V    980.2mA    743.4mA    1.343A
-1.079V   237.7mA    245.4mA    244mA
-1.021V   179.7mA    205.4mA    166.9mA
-963.6mV  125.4mA    166.2mA    102.6mA
-906.1mV  78.08mA    128mA      59.54mA
-848.5mV  43.42mA    92.11mA    40.57mA
-790.9mV  25.69mA    60.08mA    31.68mA
-733.3mV  18.23mA    34.74mA    24.58mA
-675.8mV  13.44mA    18.57mA    18.33mA
-618.2mV  9.477mA    10.28mA    12.88mA
-503mV    3.557mA    3.646mA    4.694mA
3.585V    -9.322mA   -7.548mA   -11.87mA
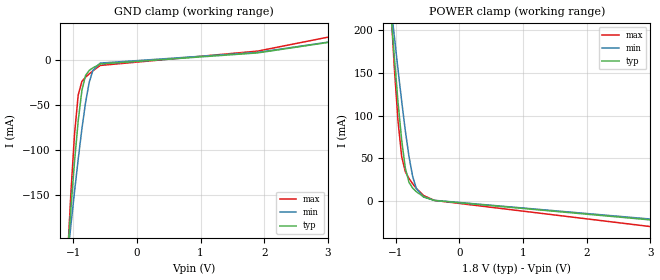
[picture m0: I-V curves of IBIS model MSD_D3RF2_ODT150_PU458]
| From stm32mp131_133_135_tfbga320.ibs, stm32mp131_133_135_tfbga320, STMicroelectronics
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[Model] MSD_D3RF2_ODT150_PU458
Model_type   Input
C_comp 2.330pF   2.263pF   2.396pF
Vinh = 1.150V
Vinl = 650.000mV
[Temperature Range]   25.000   125.000   -40.000
[Voltage Range]   1.800V   1.700V   1.900V
[GND Clamp Reference]   0.00V   0.00V   0.00V
[POWER Clamp Reference]   1.800V   1.700V   1.900V
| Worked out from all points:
|   GND clamp passes 1 mA (typ) near -0.43 V on its own axis
|   POWER clamp passes 1 mA (typ) near -0.41 V on its own axis
[GND Clamp]
-1.785V   -948.2mA   -706.1mA   -1.311A
-1.094V   -220.8mA   -221.9mA   -225.5mA
-1.036V   -164.9mA   -183.5mA   -147.5mA
-978.8mV  -112.7mA   -146mA     -82.09mA
-921.2mV  -67.36mA   -110mA     -38.91mA
-863.6mV  -33.92mA   -76.65mA   -23.88mA
-806.1mV  -17.17mA   -47.38mA   -19.1mA
-748.5mV  -11.59mA   -24.88mA   -15.45mA
-690.9mV  -8.759mA   -11.54mA   -12.05mA
-575.8mV  -4.466mA   -3.474mA   -6.07mA
1.9V      7.876mA    8.4mA      9.858mA
3.57V     25.44mA    25.67mA    33.27mA
[Power Clamp]
-1.77V    959.6mA    723mA      1.315A
-1.079V   224.6mA    231.5mA    229.7mA
-1.021V   168.1mA    192.3mA    155.8mA
-963.6mV  115.9mA    153.9mA    93.75mA
-906.1mV  71.28mA    116.9mA    52.18mA
-848.5mV  38.61mA    82.3mA     34.4mA
-790.9mV  22.01mA    52.05mA    26.53mA
-733.3mV  15.32mA    28.87mA    20.37mA
-675.8mV  11.16mA    14.79mA    14.98mA
-560.6mV  5.028mA    4.79mA     6.544mA
-387.9mV  775.4uA    1.003mA    871.1uA
3.585V    -25.77mA   -24.65mA   -34.92mA
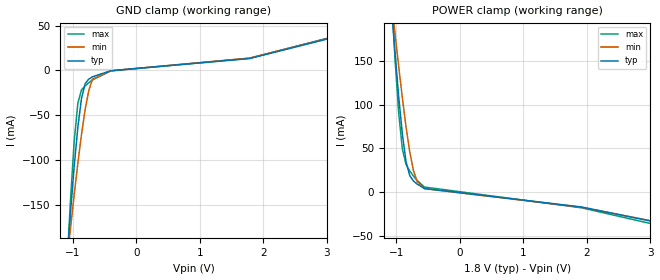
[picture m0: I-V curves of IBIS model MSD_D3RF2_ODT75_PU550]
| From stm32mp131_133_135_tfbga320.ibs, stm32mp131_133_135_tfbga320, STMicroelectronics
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[Model] MSD_D3RF2_ODT75_PU550
Model_type   Input
C_comp 2.334pF   2.268pF   2.400pF
Vinh = 1.150V
Vinl = 650.000mV
[Temperature Range]   25.000   125.000   -40.000
[Voltage Range]   1.800V   1.700V   1.900V
[GND Clamp Reference]   0.00V   0.00V   0.00V
[POWER Clamp Reference]   1.800V   1.700V   1.900V
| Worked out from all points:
|   GND clamp passes 1 mA (typ) near -0.46 V on its own axis
|   POWER clamp passes 1 mA (typ) near -0.38 V on its own axis
[GND Clamp]
-1.785V   -934mA     -692.2mA   -1.301A
-1.094V   -212.7mA   -213.3mA   -220.1mA
-1.036V   -157.8mA   -175.5mA   -143.3mA
-978.8mV  -107mA     -138.8mA   -79.15mA
-921.2mV  -63.27mA   -103.7mA   -36.55mA
-863.6mV  -31.06mA   -71.4mA    -21.81mA
-806.1mV  -14.9mA    -43.46mA   -17.28mA
-748.5mV  -9.674mA   -22.24mA   -13.87mA
-690.9mV  -7.146mA   -9.796mA   -10.71mA
-403mV    -416uA     -416uA     -550uA
1.785V    13.21mA    13.73mA    13.58mA
3.57V     45.07mA    45.59mA    46.14mA
[Power Clamp]
-1.77V    940.2mA    704.1mA    1.301A
-1.079V   213.1mA    218.9mA    223.6mA
-1.021V   158.5mA    180.6mA    151.1mA
-963.6mV  108.7mA    143.2mA    90.02mA
-906.1mV  66.21mA    107.5mA    49.08mA
-848.5mV  34.88mA    74.56mA    31.82mA
-790.9mV  19.11mA    46.36mA    24.42mA
-733.3mV  13.04mA    25.2mA     18.67mA
-675.8mV  9.434mA    12.6mA     13.67mA
-560.6mV  4.31mA     4.105mA    5.957mA
1.915V    -16.8mA    -17.14mA   -17.75mA
3.585V    -41.51mA   -40.69mA   -45.3mA
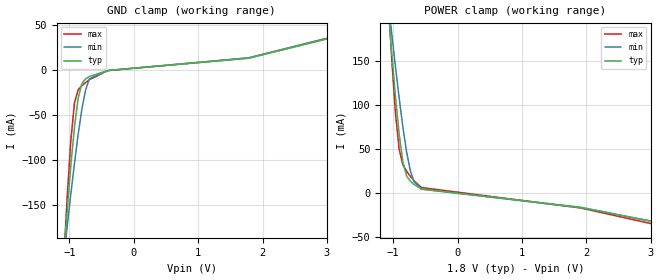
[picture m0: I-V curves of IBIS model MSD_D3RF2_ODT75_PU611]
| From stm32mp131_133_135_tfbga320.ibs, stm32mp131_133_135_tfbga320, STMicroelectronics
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[Model] MSD_D3RF2_ODT75_PU611
Model_type   Input
C_comp 2.351pF   2.285pF   2.417pF
Vinh = 1.150V
Vinl = 650.000mV
[Temperature Range]   25.000   125.000   -40.000
[Voltage Range]   1.800V   1.700V   1.900V
[GND Clamp Reference]   0.00V   0.00V   0.00V
[POWER Clamp Reference]   1.800V   1.700V   1.900V
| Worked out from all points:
|   GND clamp passes 1 mA (typ) near -0.46 V on its own axis
|   POWER clamp passes 1 mA (typ) near -0.37 V on its own axis
[GND Clamp]
-1.785V   -934.1mA   -692.3mA   -1.301A
-1.094V   -212.7mA   -213.3mA   -220.1mA
-1.036V   -157.9mA   -175.5mA   -143.4mA
-978.8mV  -107.1mA   -138.7mA   -79.2mA
-921.2mV  -63.33mA   -103.8mA   -36.62mA
-863.6mV  -31.11mA   -71.42mA   -21.88mA
-806.1mV  -14.95mA   -43.47mA   -17.33mA
-748.5mV  -9.704mA   -22.26mA   -13.92mA
-690.9mV  -7.176mA   -9.805mA   -10.74mA
-403mV    -416uA     -402.2uA   -544uA
1.785V    13.2mA     13.72mA    13.58mA
3.57V     44.72mA    45.35mA    45.74mA
[Power Clamp]
-1.77V    940.5mA    704.2mA    1.302A
-1.079V   213.2mA    219.1mA    223.7mA
-1.021V   158.6mA    180.6mA    151.2mA
-963.6mV  108.8mA    143.2mA    90.14mA
-906.1mV  66.3mA     107.5mA    49.17mA
-848.5mV  34.96mA    74.6mA     31.9mA
-790.9mV  19.18mA    46.39mA    24.49mA
-733.3mV  13.1mA     25.22mA    18.73mA
-675.8mV  9.481mA    12.62mA    13.72mA
-560.6mV  4.344mA    4.115mA    5.982mA
1.915V    -16.45mA   -16.87mA   -17.3mA
3.585V    -40.87mA   -40.23mA   -44.5mA
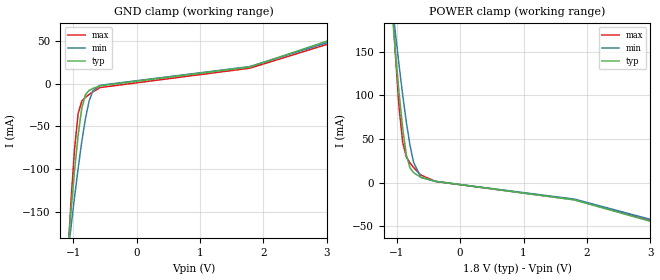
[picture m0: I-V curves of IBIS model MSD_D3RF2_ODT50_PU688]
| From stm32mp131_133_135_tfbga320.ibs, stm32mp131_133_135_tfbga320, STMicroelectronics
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[Model] MSD_D3RF2_ODT50_PU688
Model_type   Input
C_comp 2.341pF   2.302pF   2.371pF
Vinh = 1.150V
Vinl = 650.000mV
[Temperature Range]   25.000   125.000   -40.000
[Voltage Range]   1.800V   1.700V   1.900V
[GND Clamp Reference]   0.00V   0.00V   0.00V
[POWER Clamp Reference]   1.800V   1.700V   1.900V
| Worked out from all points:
|   GND clamp passes 1 mA (typ) near -0.48 V on its own axis
|   POWER clamp passes 1 mA (typ) near -0.31 V on its own axis
[GND Clamp]
-1.785V   -920.4mA   -680.8mA   -1.291A
-1.094V   -205.3mA   -206.6mA   -215.5mA
-1.036V   -151.6mA   -169.3mA   -140.2mA
-978.8mV  -102.3mA   -133.3mA   -77.19mA
-921.2mV  -60.06mA   -99.14mA   -35.02mA
-863.6mV  -28.7mA    -67.76mA   -20.48mA
-806.1mV  -12.98mA   -40.9mA    -16.1mA
-748.5mV  -8.06mA    -20.53mA   -12.85mA
-690.9mV  -5.82mA    -8.614mA   -9.842mA
-575.8mV  -2.67mA    -2.03mA    -4.68mA
1.785V    19.34mA    19.84mA    17.91mA
3.57V     63.58mA    60.57mA    58.67mA
[Power Clamp]
-1.77V    922mA      689.9mA    1.289A
-1.079V   203.1mA    209.4mA    218.2mA
-1.021V   150.8mA    171.8mA    146.9mA
-963.6mV  103.3mA    135.3mA    86.6mA
-906.1mV  62.43mA    100.8mA    46.25mA
-848.5mV  31.96mA    69.5mA     29.48mA
-790.9mV  16.82mA    42.92mA    22.51mA
-733.3mV  11.31mA    23.02mA    17.16mA
-618.2mV  5.796mA    5.843mA    8.609mA
-387.9mV  1.382mA    1.286mA    1.199mA
1.8V      -19.99mA   -19.01mA   -19.7mA
3.585V    -56.57mA   -53.67mA   -55.43mA
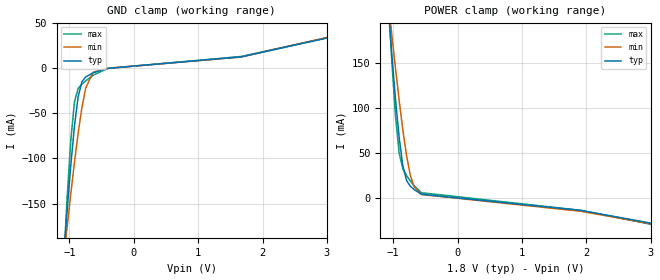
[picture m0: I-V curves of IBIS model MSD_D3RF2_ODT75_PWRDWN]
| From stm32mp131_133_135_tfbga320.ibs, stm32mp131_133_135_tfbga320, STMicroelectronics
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[Model] MSD_D3RF2_ODT75_PWRDWN
Model_type   Input
C_comp 2.480pF   2.412pF   2.550pF
Vinh = 1.150V
Vinl = 650.000mV
[Model Spec]
Vinh   1.150V   1.100V   1.200V
Vinl   650.000mV   600.000mV   700.000mV
[Temperature Range]   25.000   125.000   -40.000
[Voltage Range]   1.800V   1.700V   1.900V
[GND Clamp Reference]   0.00V   0.00V   0.00V
[POWER Clamp Reference]   1.800V   1.700V   1.900V
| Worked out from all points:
|   GND clamp passes 1 mA (typ) near -0.45 V on its own axis
|   POWER clamp passes 1 mA (typ) near -0.37 V on its own axis
[GND Clamp]
-1.785V   -936.2mA   -694.1mA   -1.304A
-1.094V   -213.7mA   -214.2mA   -221.4mA
-1.036V   -158.7mA   -176.3mA   -144.5mA
-978.8mV  -107.9mA   -139.4mA   -80.25mA
-921.2mV  -64.03mA   -104.3mA   -37.53mA
-863.6mV  -31.73mA   -71.95mA   -22.68mA
-806.1mV  -15.49mA   -43.95mA   -18.03mA
-748.5mV  -10.16mA   -22.65mA   -14.52mA
-633.3mV  -5.486mA   -4.907mA   -8.235mA
-403mV    -479.4uA   -473.8uA   -635uA
1.67V     12.18mA    11.98mA    12.57mA
3.57V     41.77mA    42.77mA    42.16mA
[Power Clamp]
-1.77V    942.4mA    706mA      1.304A
-1.079V   214.1mA    219.9mA    225mA
-1.021V   159.5mA    181.4mA    152.4mA
-963.6mV  109.6mA    143.9mA    91.12mA
-906.1mV  66.97mA    108.1mA    50.07mA
-848.5mV  35.55mA    75.14mA    32.69mA
-790.9mV  19.68mA    46.85mA    25.17mA
-733.3mV  13.53mA    25.62mA    19.31mA
-675.8mV  9.835mA    12.95mA    14.19mA
-560.6mV  4.546mA    4.322mA    6.262mA
1.915V    -13.24mA   -14.26mA   -13.21mA
3.585V    -34.87mA   -35.33mA   -36.85mA
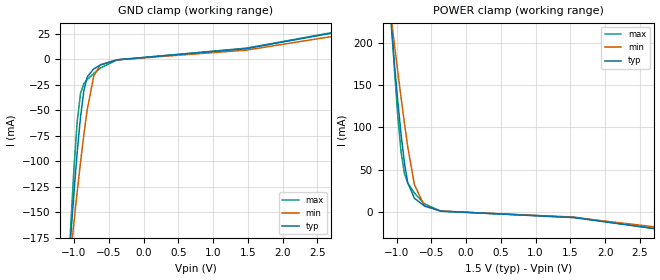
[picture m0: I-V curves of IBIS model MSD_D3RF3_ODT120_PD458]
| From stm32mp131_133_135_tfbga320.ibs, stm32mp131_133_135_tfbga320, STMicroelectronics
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[Model] MSD_D3RF3_ODT120_PD458
Model_type   Input
C_comp 2.326pF   2.282pF   2.429pF
Vinh = 925.000mV
Vinl = 575.000mV
[Temperature Range]   25.000   125.000   -40.000
[Voltage Range]   1.500V   1.425V   1.575V
[GND Clamp Reference]   0.00V   0.00V   0.00V
[POWER Clamp Reference]   1.500V   1.425V   1.575V
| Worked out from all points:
|   GND clamp passes 1 mA (typ) near -0.43 V on its own axis
|   POWER clamp passes 1 mA (typ) near -0.37 V on its own axis
[GND Clamp]
-1.48V    -619.1mA   -488.2mA   -826.1mA
-1.05V    -175.9mA   -191.8mA   -166.4mA
-1.002V   -131.6mA   -160.5mA   -107.6mA
-954.6mV  -91.08mA   -130.1mA   -61.03mA
-906.8mV  -56.4mA    -100.9mA   -33.44mA
-859.1mV  -30.98mA   -73.82mA   -23.83mA
-811.4mV  -17.25mA   -49.61mA   -19.89mA
-715.9mV  -9.287mA   -16.13mA   -13.87mA
-620.5mV  -5.619mA   -5.196mA   -8.548mA
-381.8mV  -427.6uA   -493.8uA   -526.6uA
1.48V     10.54mA    9.064mA    11.02mA
2.959V    28.85mA    25.15mA    29.33mA
[Power Clamp]
-1.459V   621mA      498mA      819.3mA
-1.077V   221mA      230.1mA    230mA
-1.03V    174.3mA    197.6mA    167.7mA
-981.8mV  130.4mA    165.7mA    113mA
-934.1mV  90.88mA    134.5mA    70.45mA
-886.4mV  57.9mA     104.6mA    45.29mA
-838.6mV  34.29mA    76.73mA    34.04mA
-743.2mV  16.13mA    32.36mA    22.35mA
-600mV    7.051mA    7.101mA    9.687mA
-361.4mV  899.6uA    1.087mA    755.8uA
1.548V    -6.742mA   -6.606mA   -6.146mA
2.98V     -22.82mA   -20.21mA   -22.79mA
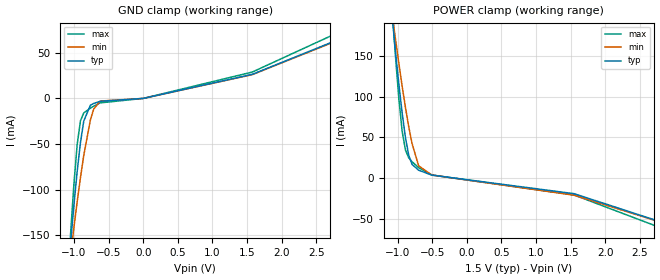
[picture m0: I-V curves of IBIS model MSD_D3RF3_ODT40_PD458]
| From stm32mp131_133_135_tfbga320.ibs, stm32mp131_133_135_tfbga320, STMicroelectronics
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[Model] MSD_D3RF3_ODT40_PD458
Model_type   Input
C_comp 2.284pF   2.243pF   2.361pF
Vinh = 925.000mV
Vinl = 575.000mV
[Temperature Range]   25.000   125.000   -40.000
[Voltage Range]   1.500V   1.425V   1.575V
[GND Clamp Reference]   0.00V   0.00V   0.00V
[POWER Clamp Reference]   1.500V   1.425V   1.575V
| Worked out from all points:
|   GND clamp passes 1 mA (typ) near -0.48 V on its own axis
|   POWER clamp passes 1 mA (typ) near -0.21 V on its own axis
[GND Clamp]
-1.48V    -589.4mA   -457.1mA   -788.3mA
-1.05V    -159.2mA   -171.6mA   -149.4mA
-1.002V   -117.8mA   -142.1mA   -94.94mA
-954.6mV  -80.44mA   -113.7mA   -50.89mA
-906.8mV  -48.54mA   -87.01mA   -24.63mA
-859.1mV  -24.84mA   -62.57mA   -15.97mA
-763.6mV  -7.508mA   -23.77mA   -10.64mA
-715.9mV  -5.58mA    -11.82mA   -8.56mA
-620.5mV  -3.164mA   -2.892mA   -4.878mA
900nV     14.91nA    13.59nA    17.58nA
1.575V    26.42mA    26.06mA    28.94mA
2.959V    68.87mA    68.17mA    77.31mA
[Power Clamp]
-1.459V   582.8mA    458.6mA    772.1mA
-1.077V   197.5mA    201.3mA    207.8mA
-1.03V    155.2mA    170.8mA    149.8mA
-981.8mV  115.9mA    141.4mA    98.07mA
-934.1mV  80.33mA    113.3mA    57.81mA
-886.4mV  49.99mA    87.03mA    34.56mA
-838.6mV  28.09mA    63.23mA    25.02mA
-790.9mV  16.94mA    42.62mA    20.17mA
-695.5mV  9.73mA     15.13mA    12.89mA
-504.6mV  3.726mA    3.827mA    3.899mA
1.548V    -19.04mA   -20.9mA    -20.65mA
2.98V     -58.7mA    -58.88mA   -66.76mA
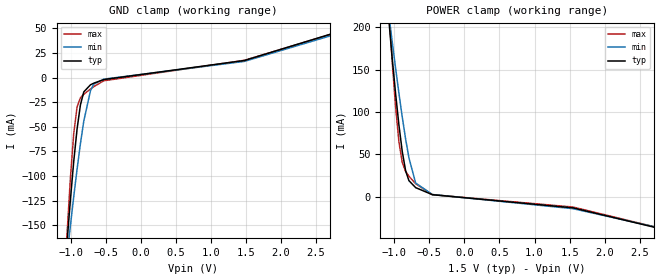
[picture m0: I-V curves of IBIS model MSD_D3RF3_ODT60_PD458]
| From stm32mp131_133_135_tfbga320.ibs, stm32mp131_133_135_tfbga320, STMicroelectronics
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[Model] MSD_D3RF3_ODT60_PD458
Model_type   Input
C_comp 2.317pF   2.271pF   2.376pF
Vinh = 925.000mV
Vinl = 575.000mV
[Temperature Range]   25.000   125.000   -40.000
[Voltage Range]   1.500V   1.425V   1.575V
[GND Clamp Reference]   0.00V   0.00V   0.00V
[POWER Clamp Reference]   1.500V   1.425V   1.575V
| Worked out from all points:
|   GND clamp passes 1 mA (typ) near -0.46 V on its own axis
|   POWER clamp passes 1 mA (typ) near -0.28 V on its own axis
[GND Clamp]
-1.48V    -603.7mA   -471.9mA   -810.5mA
-1.05V    -167mA     -180.8mA   -158.9mA
-1.002V   -124.1mA   -150.4mA   -102mA
-954.6mV  -85.17mA   -120.9mA   -56.75mA
-906.8mV  -52.12mA   -92.98mA   -29.76mA
-859.1mV  -27.74mA   -67.06mA   -20.54mA
-811.4mV  -14.58mA   -44.33mA   -16.95mA
-715.9mV  -7.328mA   -13.38mA   -11.6mA
-668.2mV  -5.689mA   -6.631mA   -9.181mA
-525mV    -2.021mA   -1.56mA    -3.219mA
1.48V     17.35mA    16.44mA    17.55mA
2.959V    49.58mA    47.79mA    49.22mA
[Power Clamp]
-1.459V   601mA      477.1mA    799.6mA
-1.077V   208mA      214.4mA    219.9mA
-1.03V    163.3mA    182.9mA    159.6mA
-981.8mV  121.8mA    152mA      106.3mA
-934.1mV  84.63mA    122.2mA    64.75mA
-886.4mV  53.26mA    93.95mA    40.45mA
-838.6mV  30.69mA    68.12mA    29.94mA
-790.9mV  18.98mA    45.77mA    24.21mA
-695.5mV  10.8mA     16.21mA    15.35mA
-456.8mV  2.47mA     2.694mA    2.457mA
1.548V    -13.05mA   -14.02mA   -12.09mA
2.98V     -41.27mA   -40.31mA   -40.83mA
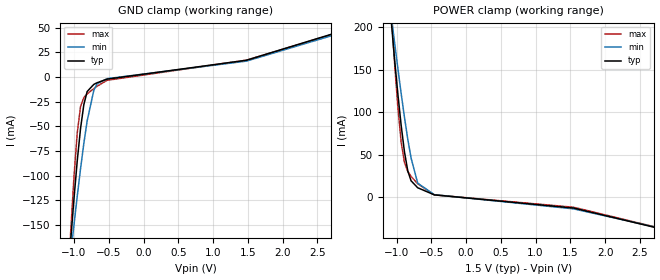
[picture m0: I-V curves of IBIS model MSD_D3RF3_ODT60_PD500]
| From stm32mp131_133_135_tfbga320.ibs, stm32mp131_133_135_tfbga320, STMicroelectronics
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[Model] MSD_D3RF3_ODT60_PD500
Model_type   Input
C_comp 2.333pF   2.287pF   2.393pF
Vinh = 925.000mV
Vinl = 575.000mV
[Temperature Range]   25.000   125.000   -40.000
[Voltage Range]   1.500V   1.425V   1.575V
[GND Clamp Reference]   0.00V   0.00V   0.00V
[POWER Clamp Reference]   1.500V   1.425V   1.575V
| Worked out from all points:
|   GND clamp passes 1 mA (typ) near -0.46 V on its own axis
|   POWER clamp passes 1 mA (typ) near -0.27 V on its own axis
[GND Clamp]
-1.48V    -603.9mA   -472mA     -810.7mA
-1.05V    -167.1mA   -180.9mA   -158.9mA
-1.002V   -124.2mA   -150.5mA   -102.1mA
-954.6mV  -85.25mA   -121mA     -56.85mA
-906.8mV  -52.2mA    -93.02mA   -29.85mA
-859.1mV  -27.81mA   -67.13mA   -20.62mA
-811.4mV  -14.63mA   -44.37mA   -17.03mA
-715.9mV  -7.373mA   -13.41mA   -11.66mA
-668.2mV  -5.725mA   -6.661mA   -9.231mA
-525mV    -2.04mA    -1.579mA   -3.234mA
1.48V     17.07mA    16.22mA    17.2mA
2.959V    48.99mA    47.31mA    48.49mA
[Power Clamp]
-1.459V   601.3mA    477.3mA    799.9mA
-1.077V   208.2mA    214.6mA    220.1mA
-1.03V    163.4mA    183mA      159.8mA
-981.8mV  121.9mA    152.1mA    106.4mA
-934.1mV  84.71mA    122.3mA    64.87mA
-886.4mV  53.36mA    94.08mA    40.57mA
-838.6mV  30.79mA    68.24mA    30.04mA
-790.9mV  19.06mA    45.85mA    24.3mA
-695.5mV  10.87mA    16.28mA    15.42mA
-456.8mV  2.5mA      2.73mA     2.486mA
1.548V    -13.04mA   -14.01mA   -12.09mA
2.98V     -41mA      -40.08mA   -40.5mA
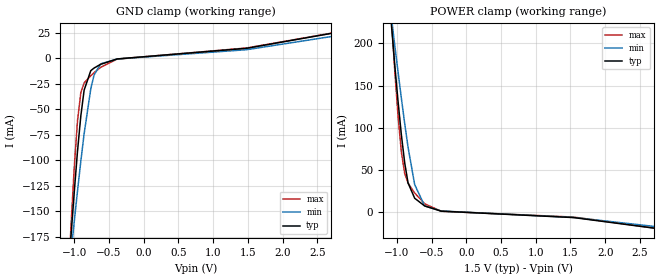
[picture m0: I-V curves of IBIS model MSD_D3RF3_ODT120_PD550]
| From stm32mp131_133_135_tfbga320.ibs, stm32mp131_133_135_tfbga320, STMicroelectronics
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[Model] MSD_D3RF3_ODT120_PD550
Model_type   Input
C_comp 2.355pF   2.311pF   2.459pF
Vinh = 925.000mV
Vinl = 575.000mV
[Temperature Range]   25.000   125.000   -40.000
[Voltage Range]   1.500V   1.425V   1.575V
[GND Clamp Reference]   0.00V   0.00V   0.00V
[POWER Clamp Reference]   1.500V   1.425V   1.575V
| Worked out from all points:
|   GND clamp passes 1 mA (typ) near -0.43 V on its own axis
|   POWER clamp passes 1 mA (typ) near -0.37 V on its own axis
[GND Clamp]
-1.48V    -619.4mA   -488.6mA   -826.5mA
-1.05V    -176.1mA   -192mA     -166.7mA
-1.002V   -131.8mA   -160.6mA   -107.8mA
-954.6mV  -91.24mA   -130.3mA   -61.25mA
-906.8mV  -56.56mA   -101.1mA   -33.63mA
-859.1mV  -31.11mA   -73.93mA   -24mA
-763.6mV  -11.99mA   -29.94mA   -16.92mA
-715.9mV  -9.387mA   -16.2mA    -13.99mA
-620.5mV  -5.683mA   -5.253mA   -8.637mA
-381.8mV  -441.6uA   -504uA     -540.6uA
1.48V     9.991mA    8.629mA    10.31mA
2.959V    27.74mA    24.28mA    27.94mA
[Power Clamp]
-1.459V   621.4mA    498.3mA    819.8mA
-1.077V   221.3mA    230.3mA    230.2mA
-1.03V    174.5mA    197.8mA    168mA
-981.8mV  130.6mA    165.8mA    113.2mA
-934.1mV  91.09mA    134.6mA    70.64mA
-886.4mV  58.06mA    104.7mA    45.47mA
-838.6mV  34.44mA    76.87mA    34.21mA
-743.2mV  16.24mA    32.45mA    22.47mA
-600mV    7.114mA    7.164mA    9.754mA
-361.4mV  914uA      1.096mA    756.6uA
1.548V    -6.724mA   -6.569mA   -6.146mA
2.98V     -22.26mA   -19.74mA   -22.11mA
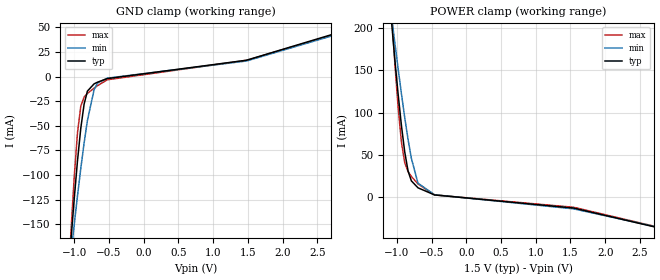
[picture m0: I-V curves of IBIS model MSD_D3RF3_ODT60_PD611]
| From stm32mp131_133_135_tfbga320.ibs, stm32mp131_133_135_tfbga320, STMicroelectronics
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[Model] MSD_D3RF3_ODT60_PD611
Model_type   Input
C_comp 2.363pF   2.317pF   2.424pF
Vinh = 925.000mV
Vinl = 575.000mV
[Temperature Range]   25.000   125.000   -40.000
[Voltage Range]   1.500V   1.425V   1.575V
[GND Clamp Reference]   0.00V   0.00V   0.00V
[POWER Clamp Reference]   1.500V   1.425V   1.575V
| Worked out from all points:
|   GND clamp passes 1 mA (typ) near -0.46 V on its own axis
|   POWER clamp passes 1 mA (typ) near -0.27 V on its own axis
[GND Clamp]
-1.48V    -604.3mA   -472.2mA   -811.1mA
-1.05V    -167.3mA   -181.1mA   -159.2mA
-1.002V   -124.4mA   -150.6mA   -102.4mA
-954.6mV  -85.41mA   -121.1mA   -57.06mA
-906.8mV  -52.35mA   -93.09mA   -30.04mA
-859.1mV  -27.94mA   -67.23mA   -20.79mA
-811.4mV  -14.76mA   -44.48mA   -17.18mA
-715.9mV  -7.463mA   -13.49mA   -11.78mA
-668.2mV  -5.807mA   -6.73mA    -9.333mA
-525mV    -2.078mA   -1.615mA   -3.287mA
1.48V     16.52mA    15.78mA    16.49mA
2.959V    47.88mA    46.43mA    47.1mA
[Power Clamp]
-1.459V   601.6mA    477.7mA    800.3mA
-1.077V   208.4mA    214.8mA    220.3mA
-1.03V    163.7mA    183.2mA    160mA
-981.8mV  122.1mA    152.3mA    106.6mA
-934.1mV  84.92mA    122.5mA    65.06mA
-886.4mV  53.52mA    94.21mA    40.74mA
-838.6mV  30.94mA    68.35mA    30.2mA
-790.9mV  19.19mA    45.99mA    24.44mA
-695.5mV  10.97mA    16.38mA    15.52mA
-456.8mV  2.53mA     2.76mA     2.506mA
1.548V    -13.02mA   -13.97mA   -12.09mA
2.98V     -40.44mA   -39.62mA   -39.82mA
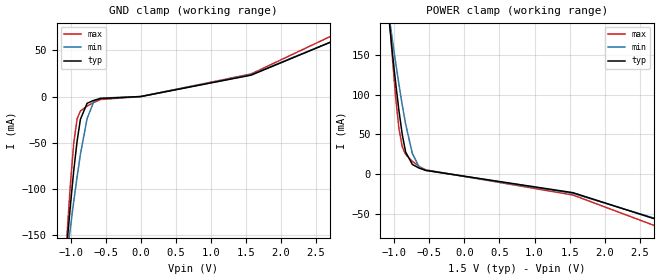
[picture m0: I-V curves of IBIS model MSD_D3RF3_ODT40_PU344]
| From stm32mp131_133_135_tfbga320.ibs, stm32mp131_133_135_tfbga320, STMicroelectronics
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[Model] MSD_D3RF3_ODT40_PU344
Model_type   Input
C_comp 2.228pF   2.187pF   2.304pF
Vinh = 925.000mV
Vinl = 575.000mV
[Temperature Range]   25.000   125.000   -40.000
[Voltage Range]   1.500V   1.425V   1.575V
[GND Clamp Reference]   0.00V   0.00V   0.00V
[POWER Clamp Reference]   1.500V   1.425V   1.575V
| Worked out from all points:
|   GND clamp passes 1 mA (typ) near -0.49 V on its own axis
|   POWER clamp passes 1 mA (typ) near -0.21 V on its own axis
[GND Clamp]
-1.48V    -588.7mA   -456.4mA   -787.4mA
-1.05V    -158.7mA   -171.2mA   -148.8mA
-1.002V   -117.4mA   -141.8mA   -94.41mA
-954.6mV  -80.05mA   -113.4mA   -50.4mA
-906.8mV  -48.22mA   -86.79mA   -24.19mA
-859.1mV  -24.55mA   -62.28mA   -15.58mA
-763.6mV  -7.278mA   -23.58mA   -10.33mA
-668.2mV  -4.092mA   -5.37mA    -6.394mA
-572.7mV  -2.116mA   -1.71mA    -3.192mA
900nV     12.81nA    12.02nA    14.71nA
1.575V    23.13mA    23.65mA    24.42mA
2.959V    66.63mA    66.68mA    74.01mA
[Power Clamp]
-1.459V   582.3mA    458.2mA    771.4mA
-1.077V   197.2mA    201mA      207.4mA
-1.03V    154.9mA    170.6mA    149.4mA
-981.8mV  115.6mA    141.2mA    97.68mA
-934.1mV  80.07mA    113.1mA    57.44mA
-886.4mV  49.69mA    86.85mA    34.26mA
-838.6mV  27.86mA    63.07mA    24.75mA
-743.2mV  12.16mA    26.11mA    16.09mA
-647.7mV  7.59mA     8.958mA    9.762mA
-552.3mV  4.661mA    4.672mA    5.299mA
1.548V    -23.46mA   -24.32mA   -26.43mA
2.98V     -64.02mA   -63.02mA   -73.83mA
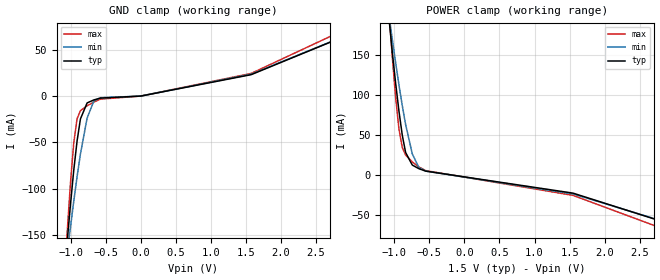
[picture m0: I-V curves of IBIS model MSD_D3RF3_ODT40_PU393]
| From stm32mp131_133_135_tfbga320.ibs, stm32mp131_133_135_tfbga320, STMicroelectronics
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[Model] MSD_D3RF3_ODT40_PU393
Model_type   Input
C_comp 2.258pF   2.216pF   2.334pF
Vinh = 925.000mV
Vinl = 575.000mV
[Temperature Range]   25.000   125.000   -40.000
[Voltage Range]   1.500V   1.425V   1.575V
[GND Clamp Reference]   0.00V   0.00V   0.00V
[POWER Clamp Reference]   1.500V   1.425V   1.575V
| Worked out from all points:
|   GND clamp passes 1 mA (typ) near -0.49 V on its own axis
|   POWER clamp passes 1 mA (typ) near -0.21 V on its own axis
[GND Clamp]
-1.48V    -588.9mA   -456.8mA   -787.8mA
-1.05V    -158.9mA   -171.4mA   -149mA
-1.002V   -117.6mA   -141.9mA   -94.61mA
-954.6mV  -80.22mA   -113.6mA   -50.68mA
-906.8mV  -48.35mA   -86.88mA   -24.39mA
-859.1mV  -24.67mA   -62.45mA   -15.75mA
-763.6mV  -7.364mA   -23.67mA   -10.47mA
-668.2mV  -4.156mA   -5.436mA   -6.502mA
-572.7mV  -2.158mA   -1.758mA   -3.266mA
900nV     12.79nA    11.97nA    14.74nA
1.575V    23.09mA    23.6mA     24.42mA
2.959V    66.07mA    66.23mA    73.37mA
[Power Clamp]
-1.459V   582.6mA    458.5mA    771.7mA
-1.077V   197.5mA    201.2mA    207.7mA
-1.03V    155.1mA    170.8mA    149.6mA
-981.8mV  115.7mA    141.3mA    97.88mA
-934.1mV  80.23mA    113.1mA    57.65mA
-886.4mV  49.85mA    86.91mA    34.43mA
-838.6mV  28mA       63.15mA    24.91mA
-743.2mV  12.28mA    26.19mA    16.22mA
-647.7mV  7.672mA    9.02mA     9.845mA
-552.3mV  4.716mA    4.716mA    5.348mA
1.548V    -22.9mA    -23.86mA   -25.71mA
2.98V     -62.98mA   -62.14mA   -72.44mA
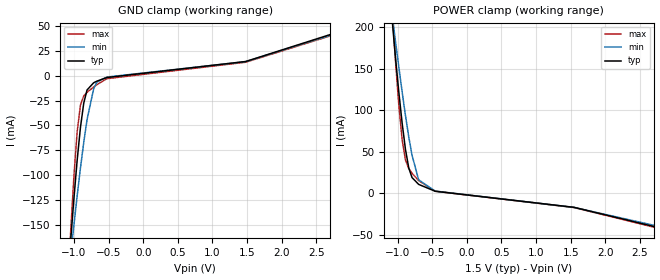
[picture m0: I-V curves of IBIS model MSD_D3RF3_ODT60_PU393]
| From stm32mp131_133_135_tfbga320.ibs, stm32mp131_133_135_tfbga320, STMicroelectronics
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[Model] MSD_D3RF3_ODT60_PU393
Model_type   Input
C_comp 2.290pF   2.244pF   2.350pF
Vinh = 925.000mV
Vinl = 575.000mV
[Temperature Range]   25.000   125.000   -40.000
[Voltage Range]   1.500V   1.425V   1.575V
[GND Clamp Reference]   0.00V   0.00V   0.00V
[POWER Clamp Reference]   1.500V   1.425V   1.575V
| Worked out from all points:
|   GND clamp passes 1 mA (typ) near -0.46 V on its own axis
|   POWER clamp passes 1 mA (typ) near -0.27 V on its own axis
[GND Clamp]
-1.48V    -603.3mA   -471.4mA   -810.1mA
-1.05V    -166.8mA   -180.6mA   -158.5mA
-1.002V   -123.9mA   -150.2mA   -101.7mA
-954.6mV  -84.97mA   -120.7mA   -56.51mA
-906.8mV  -51.94mA   -92.67mA   -29.55mA
-859.1mV  -27.58mA   -66.87mA   -20.34mA
-811.4mV  -14.43mA   -44.15mA   -16.78mA
-715.9mV  -7.22mA    -13.23mA   -11.47mA
-668.2mV  -5.594mA   -6.5mA     -9.066mA
-525mV    -1.966mA   -1.48mA    -3.154mA
1.48V     14.06mA    13.95mA    13.35mA
2.959V    46.78mA    45.82mA    45.29mA
[Power Clamp]
-1.459V   600.8mA    477.1mA    799.3mA
-1.077V   207.8mA    214.4mA    219.7mA
-1.03V    163.2mA    182.8mA    159.4mA
-981.8mV  121.7mA    152mA      106.1mA
-934.1mV  84.52mA    122.2mA    64.58mA
-886.4mV  53.14mA    93.95mA    40.31mA
-838.6mV  30.6mA     68.11mA    29.81mA
-790.9mV  18.89mA    45.75mA    24.1mA
-695.5mV  10.74mA    16.2mA     15.28mA
-456.8mV  2.46mA     2.703mA    2.451mA
1.548V    -16.9mA    -17.01mA   -17.14mA
2.98V     -45.52mA   -43.71mA   -46.48mA
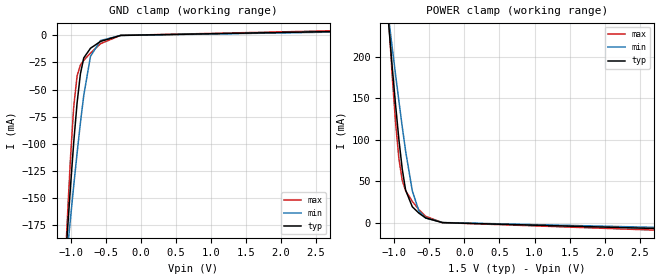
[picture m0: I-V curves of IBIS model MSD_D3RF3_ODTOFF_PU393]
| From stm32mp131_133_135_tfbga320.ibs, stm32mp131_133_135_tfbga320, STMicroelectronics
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[Model] MSD_D3RF3_ODTOFF_PU393
Model_type   Input
C_comp 2.358pF   2.276pF   2.481pF
Vinh = 925.000mV
Vinl = 575.000mV
[Temperature Range]   25.000   125.000   -40.000
[Voltage Range]   1.500V   1.425V   1.575V
[GND Clamp Reference]   0.00V   0.00V   0.00V
[POWER Clamp Reference]   1.500V   1.425V   1.575V
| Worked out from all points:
|   GND clamp passes 1 mA (typ) near -0.40 V on its own axis
|   POWER clamp passes 1 mA (typ) near -0.41 V on its own axis
[GND Clamp]
-1.48V    -635.2mA   -502.2mA   -841.9mA
-1.098V   -233.6mA   -234.1mA   -242.6mA
-1.05V    -186.1mA   -201.6mA   -174.9mA
-1.002V   -140.7mA   -169.7mA   -114.2mA
-954.6mV  -98.64mA   -138.6mA   -65.82mA
-906.8mV  -62.32mA   -108.7mA   -37.39mA
-859.1mV  -35.41mA   -80.59mA   -27.34mA
-811.4mV  -20.81mA   -55.29mA   -23.05mA
-715.9mV  -11.93mA   -19.37mA   -16.36mA
-572.7mV  -5.618mA   -4.768mA   -7.701mA
-286.4mV  -65.02uA   -113uA     -51.02uA
2.959V    3.768mA    3.209mA    4.556mA
[Power Clamp]
-1.459V   642.1mA    516.6mA    839.8mA
-1.077V   236.1mA    244.4mA    241.7mA
-1.03V    187.9mA    211.2mA    177.2mA
-981.8mV  142mA      178.4mA    120.7mA
-934.1mV  99.89mA    146.4mA    76.91mA
-886.4mV  64.49mA    115.4mA    50.82mA
-838.6mV  39.2mA     86.27mA    38.78mA
-743.2mV  19.22mA    38.37mA    25.71mA
-647.7mV  11.43mA    13.64mA    15.56mA
-552.3mV  5.754mA    5.674mA    7.701mA
-313.6mV  104.4uA    240.6uA    117.5uA
2.98V     -7.591mA   -6.102mA   -9.71mA
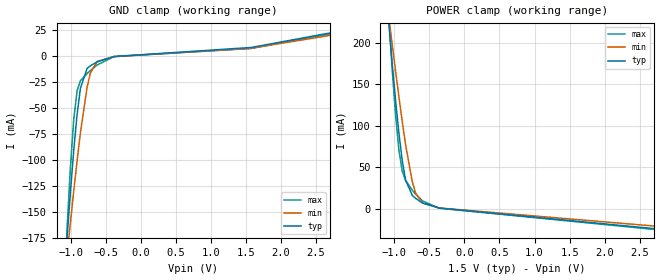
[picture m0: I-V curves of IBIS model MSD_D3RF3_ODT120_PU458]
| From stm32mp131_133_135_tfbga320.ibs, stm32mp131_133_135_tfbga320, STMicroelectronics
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[Model] MSD_D3RF3_ODT120_PU458
Model_type   Input
C_comp 2.329pF   2.285pF   2.433pF
Vinh = 925.000mV
Vinl = 575.000mV
[Temperature Range]   25.000   125.000   -40.000
[Voltage Range]   1.500V   1.425V   1.575V
[GND Clamp Reference]   0.00V   0.00V   0.00V
[POWER Clamp Reference]   1.500V   1.425V   1.575V
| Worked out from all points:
|   GND clamp passes 1 mA (typ) near -0.43 V on its own axis
|   POWER clamp passes 1 mA (typ) near -0.37 V on its own axis
[GND Clamp]
-1.48V    -619mA     -488.2mA   -826.1mA
-1.05V    -175.9mA   -191.8mA   -166.4mA
-1.002V   -131.6mA   -160.5mA   -107.7mA
-954.6mV  -90.97mA   -130mA     -61.03mA
-906.8mV  -56.38mA   -101mA     -33.44mA
-859.1mV  -30.96mA   -73.78mA   -23.82mA
-763.6mV  -11.87mA   -29.82mA   -16.78mA
-715.9mV  -9.279mA   -16.11mA   -13.87mA
-620.5mV  -5.612mA   -5.177mA   -8.552mA
-381.8mV  -430.2uA   -480.6uA   -532uA
1.575V    8.28mA     7.601mA    7.322mA
2.959V    25.51mA    22.75mA    24.78mA
[Power Clamp]
-1.459V   621.1mA    498.2mA    819.4mA
-1.077V   221.1mA    230.2mA    230mA
-1.03V    174.4mA    197.7mA    167.8mA
-981.8mV  130.5mA    165.7mA    113mA
-934.1mV  90.93mA    134.5mA    70.49mA
-886.4mV  57.95mA    104.7mA    45.32mA
-838.6mV  34.35mA    76.83mA    34.08mA
-743.2mV  16.16mA    32.41mA    22.38mA
-695.5mV  12.54mA    18.84mA    17.63mA
-600mV    7.076mA    7.134mA    9.704mA
-361.4mV  916uA      1.102mA    761.3uA
2.98V     -25.98mA   -22.65mA   -27.03mA
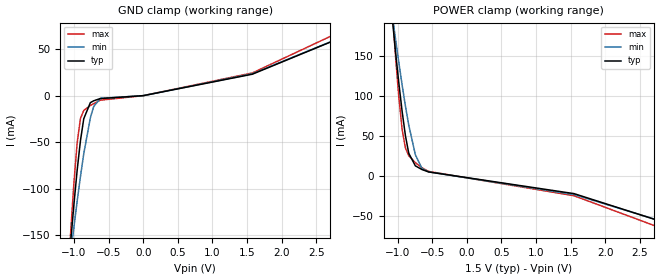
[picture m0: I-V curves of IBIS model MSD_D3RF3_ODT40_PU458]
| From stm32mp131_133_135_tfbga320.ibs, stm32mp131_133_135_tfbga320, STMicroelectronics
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[Model] MSD_D3RF3_ODT40_PU458
Model_type   Input
C_comp 2.287pF   2.245pF   2.364pF
Vinh = 925.000mV
Vinl = 575.000mV
[Temperature Range]   25.000   125.000   -40.000
[Voltage Range]   1.500V   1.425V   1.575V
[GND Clamp Reference]   0.00V   0.00V   0.00V
[POWER Clamp Reference]   1.500V   1.425V   1.575V
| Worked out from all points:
|   GND clamp passes 1 mA (typ) near -0.48 V on its own axis
|   POWER clamp passes 1 mA (typ) near -0.21 V on its own axis
[GND Clamp]
-1.48V    -589.3mA   -457mA     -788.4mA
-1.05V    -159.2mA   -171.6mA   -149.3mA
-1.002V   -117.8mA   -142mA     -94.85mA
-954.6mV  -80.43mA   -113.7mA   -50.9mA
-906.8mV  -48.52mA   -87.06mA   -24.63mA
-859.1mV  -24.83mA   -62.52mA   -15.97mA
-763.6mV  -7.492mA   -23.77mA   -10.64mA
-715.9mV  -5.56mA    -11.81mA   -8.57mA
-620.5mV  -3.146mA   -2.884mA   -4.886mA
900nV     12.86nA    12.01nA    14.78nA
1.575V    23.07mA    23.55mA    24.42mA
2.959V    65.52mA    65.71mA    72.73mA
[Power Clamp]
-1.459V   583mA      458.8mA    772.2mA
-1.077V   197.7mA    201.4mA    207.9mA
-1.03V    155.3mA    171mA      149.9mA
-981.8mV  115.9mA    141.5mA    98.13mA
-934.1mV  80.38mA    113.3mA    57.87mA
-886.4mV  50mA       87.11mA    34.61mA
-838.6mV  28.15mA    63.32mA    25.07mA
-743.2mV  12.39mA    26.32mA    16.34mA
-647.7mV  7.754mA    9.111mA    9.934mA
-552.3mV  4.762mA    4.781mA    5.407mA
1.548V    -22.33mA   -23.41mA   -24.98mA
2.98V     -61.87mA   -61.27mA   -71mA
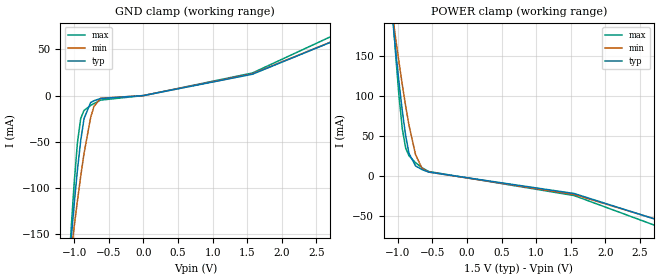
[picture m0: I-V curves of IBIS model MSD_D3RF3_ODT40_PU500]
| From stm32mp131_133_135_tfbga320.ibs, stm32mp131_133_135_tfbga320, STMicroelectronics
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[Model] MSD_D3RF3_ODT40_PU500
Model_type   Input
C_comp 2.304pF   2.262pF   2.380pF
Vinh = 925.000mV
Vinl = 575.000mV
[Temperature Range]   25.000   125.000   -40.000
[Voltage Range]   1.500V   1.425V   1.575V
[GND Clamp Reference]   0.00V   0.00V   0.00V
[POWER Clamp Reference]   1.500V   1.425V   1.575V
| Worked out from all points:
|   GND clamp passes 1 mA (typ) near -0.48 V on its own axis
|   POWER clamp passes 1 mA (typ) near -0.21 V on its own axis
[GND Clamp]
-1.48V    -589.5mA   -457.1mA   -788.5mA
-1.05V    -159.2mA   -171.6mA   -149.5mA
-1.002V   -117.8mA   -142.2mA   -95.02mA
-954.6mV  -80.46mA   -113.8mA   -50.96mA
-906.8mV  -48.57mA   -87.09mA   -24.7mA
-859.1mV  -24.87mA   -62.54mA   -16.03mA
-763.6mV  -7.53mA    -23.79mA   -10.68mA
-715.9mV  -5.59mA    -11.84mA   -8.6mA
-620.5mV  -3.17mA    -2.902mA   -4.906mA
900nV     12.76nA    11.98nA    14.7nA
1.575V    23.07mA    23.53mA    24.42mA
2.959V    65.35mA    65.53mA    72.39mA
[Power Clamp]
-1.459V   583.1mA    458.9mA    772.5mA
-1.077V   197.7mA    201.5mA    208.1mA
-1.03V    155.3mA    171mA      150mA
-981.8mV  116mA      141.5mA    98.28mA
-934.1mV  80.39mA    113.4mA    58mA
-886.4mV  50.02mA    87.11mA    34.72mA
-838.6mV  28.16mA    63.33mA    25.16mA
-743.2mV  12.38mA    26.34mA    16.42mA
-647.7mV  7.748mA    9.127mA    9.991mA
-552.3mV  4.744mA    4.786mA    5.446mA
1.548V    -22.05mA   -23.18mA   -24.63mA
2.98V     -61.35mA   -60.86mA   -70.34mA
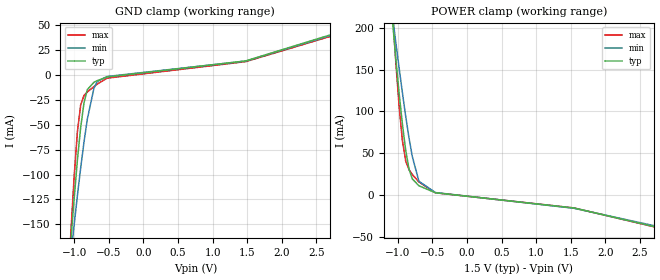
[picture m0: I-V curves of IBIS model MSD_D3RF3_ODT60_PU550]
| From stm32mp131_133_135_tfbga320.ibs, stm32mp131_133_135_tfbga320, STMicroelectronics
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[Model] MSD_D3RF3_ODT60_PU550
Model_type   Input
C_comp 2.348pF   2.302pF   2.409pF
Vinh = 925.000mV
Vinl = 575.000mV
[Temperature Range]   25.000   125.000   -40.000
[Voltage Range]   1.500V   1.425V   1.575V
[GND Clamp Reference]   0.00V   0.00V   0.00V
[POWER Clamp Reference]   1.500V   1.425V   1.575V
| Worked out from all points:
|   GND clamp passes 1 mA (typ) near -0.46 V on its own axis
|   POWER clamp passes 1 mA (typ) near -0.27 V on its own axis
[GND Clamp]
-1.48V    -604.1mA   -472mA     -810.9mA
-1.05V    -167.2mA   -181mA     -159.1mA
-1.002V   -124.3mA   -150.4mA   -102.2mA
-954.6mV  -85.29mA   -121mA     -56.94mA
-906.8mV  -52.28mA   -92.95mA   -29.93mA
-859.1mV  -27.89mA   -67.11mA   -20.69mA
-811.4mV  -14.7mA    -44.37mA   -17.09mA
-715.9mV  -7.43mA    -13.4mA    -11.71mA
-668.2mV  -5.778mA   -6.651mA   -9.272mA
-525mV    -2.062mA   -1.565mA   -3.258mA
1.48V     14.06mA    13.91mA    13.34mA
2.959V    45.67mA    44.87mA    43.99mA
[Power Clamp]
-1.459V   601.5mA    477.7mA    800.2mA
-1.077V   208.4mA    214.8mA    220.2mA
-1.03V    163.6mA    183.2mA    159.9mA
-981.8mV  122mA      152.3mA    106.5mA
-934.1mV  84.83mA    122.5mA    65.03mA
-886.4mV  53.46mA    94.2mA     40.69mA
-838.6mV  30.89mA    68.34mA    30.16mA
-790.9mV  19.15mA    45.97mA    24.4mA
-695.5mV  10.93mA    16.36mA    15.49mA
-456.8mV  2.522mA    2.76mA     2.509mA
1.548V    -15.77mA   -16.09mA   -15.7mA
2.98V     -43.31mA   -41.94mA   -43.71mA
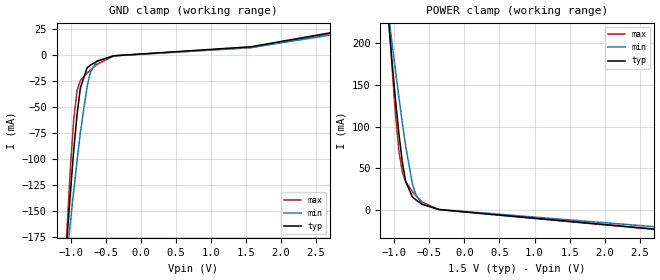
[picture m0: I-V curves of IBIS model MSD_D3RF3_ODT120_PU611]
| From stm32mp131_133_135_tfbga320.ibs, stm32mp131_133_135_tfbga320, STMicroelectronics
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[Model] MSD_D3RF3_ODT120_PU611
Model_type   Input
C_comp 2.375pF   2.330pF   2.479pF
Vinh = 925.000mV
Vinl = 575.000mV
[Temperature Range]   25.000   125.000   -40.000
[Voltage Range]   1.500V   1.425V   1.575V
[GND Clamp Reference]   0.00V   0.00V   0.00V
[POWER Clamp Reference]   1.500V   1.425V   1.575V
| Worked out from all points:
|   GND clamp passes 1 mA (typ) near -0.43 V on its own axis
|   POWER clamp passes 1 mA (typ) near -0.37 V on its own axis
[GND Clamp]
-1.48V    -619.5mA   -488.5mA   -826.7mA
-1.05V    -176.2mA   -192mA     -166.8mA
-1.002V   -131.9mA   -160.7mA   -107.9mA
-954.6mV  -91.21mA   -130.3mA   -61.35mA
-906.8mV  -56.61mA   -101.1mA   -33.72mA
-859.1mV  -31.17mA   -73.96mA   -24.09mA
-763.6mV  -12.02mA   -29.96mA   -16.98mA
-715.9mV  -9.419mA   -16.23mA   -14.04mA
-620.5mV  -5.711mA   -5.268mA   -8.671mA
-381.8mV  -439.6uA   -498uA     -546.4uA
1.575V    8.238mA    7.532mA    7.322mA
2.959V    24.69mA    22.05mA    23.8mA
[Power Clamp]
-1.459V   621.6mA    498.7mA    820.1mA
-1.077V   221.4mA    230.5mA    230.4mA
-1.03V    174.7mA    197.9mA    168.1mA
-981.8mV  130.8mA    165.9mA    113.3mA
-934.1mV  91.25mA    134.8mA    70.77mA
-886.4mV  58.18mA    104.9mA    45.61mA
-838.6mV  34.54mA    77mA       34.33mA
-743.2mV  16.32mA    32.54mA    22.58mA
-695.5mV  12.68mA    18.95mA    17.81mA
-600mV    7.171mA    7.222mA    9.823mA
-361.4mV  927.8uA    1.116mA    775.8uA
2.98V     -24.35mA   -21.34mA   -24.97mA
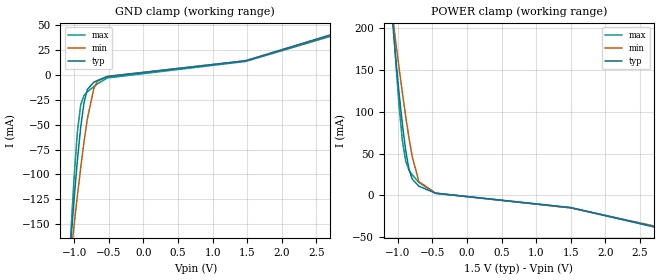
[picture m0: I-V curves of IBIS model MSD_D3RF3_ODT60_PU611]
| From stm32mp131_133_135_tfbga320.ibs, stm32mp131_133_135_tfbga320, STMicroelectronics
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[Model] MSD_D3RF3_ODT60_PU611
Model_type   Input
C_comp 2.365pF   2.318pF   2.426pF
Vinh = 925.000mV
Vinl = 575.000mV
[Temperature Range]   25.000   125.000   -40.000
[Voltage Range]   1.500V   1.425V   1.575V
[GND Clamp Reference]   0.00V   0.00V   0.00V
[POWER Clamp Reference]   1.500V   1.425V   1.575V
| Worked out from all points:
|   GND clamp passes 1 mA (typ) near -0.45 V on its own axis
|   POWER clamp passes 1 mA (typ) near -0.27 V on its own axis
[GND Clamp]
-1.48V    -604.2mA   -472.1mA   -811.2mA
-1.05V    -167.3mA   -181mA     -159.2mA
-1.002V   -124.3mA   -150.6mA   -102.3mA
-954.6mV  -85.43mA   -121mA     -57.06mA
-906.8mV  -52.35mA   -93.09mA   -30.05mA
-859.1mV  -27.94mA   -67.17mA   -20.8mA
-811.4mV  -14.76mA   -44.41mA   -17.18mA
-715.9mV  -7.47mA    -13.44mA   -11.79mA
-668.2mV  -5.81mA    -6.676mA   -9.33mA
-525mV    -2.09mA    -1.579mA   -3.29mA
1.48V     14.05mA    13.9mA     13.34mA
2.959V    45.37mA    44.66mA    43.66mA
[Power Clamp]
-1.459V   601.7mA    477.8mA    800.4mA
-1.077V   208.5mA    214.8mA    220.3mA
-1.03V    163.7mA    183.3mA    160.1mA
-981.8mV  122.2mA    152.4mA    106.7mA
-934.1mV  84.93mA    122.5mA    65.15mA
-886.4mV  53.55mA    94.28mA    40.79mA
-838.6mV  30.97mA    68.41mA    30.24mA
-790.9mV  19.22mA    46mA       24.47mA
-695.5mV  10.99mA    16.39mA    15.55mA
-456.8mV  2.538mA    2.762mA    2.524mA
1.5V      -14.57mA   -15.01mA   -14.85mA
2.98V     -42.78mA   -41.51mA   -42.99mA
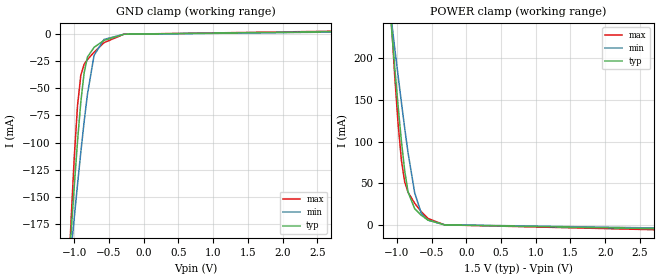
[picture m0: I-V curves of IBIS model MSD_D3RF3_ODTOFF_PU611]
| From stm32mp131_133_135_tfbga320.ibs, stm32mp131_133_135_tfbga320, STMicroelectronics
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[Model] MSD_D3RF3_ODTOFF_PU611
Model_type   Input
C_comp 2.433pF   2.350pF   2.557pF
Vinh = 925.000mV
Vinl = 575.000mV
[Temperature Range]   25.000   125.000   -40.000
[Voltage Range]   1.500V   1.425V   1.575V
[GND Clamp Reference]   0.00V   0.00V   0.00V
[POWER Clamp Reference]   1.500V   1.425V   1.575V
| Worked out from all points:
|   GND clamp passes 1 mA (typ) near -0.40 V on its own axis
|   POWER clamp passes 1 mA (typ) near -0.41 V on its own axis
[GND Clamp]
-1.48V    -636.1mA   -503mA     -843.1mA
-1.098V   -234mA     -234.6mA   -243.2mA
-1.05V    -186.6mA   -202mA     -175.6mA
-1.002V   -141.2mA   -170.1mA   -114.7mA
-954.6mV  -99.08mA   -139mA     -66.36mA
-906.8mV  -62.69mA   -109mA     -37.88mA
-859.1mV  -35.75mA   -80.88mA   -27.78mA
-811.4mV  -21.12mA   -55.55mA   -23.44mA
-715.9mV  -12.16mA   -19.57mA   -16.66mA
-572.7mV  -5.752mA   -4.879mA   -7.875mA
-286.4mV  -70.21uA   -119.6uA   -56.41uA
2.959V    2.422mA    2.063mA    2.929mA
[Power Clamp]
-1.459V   643mA      517.3mA    840.9mA
-1.077V   236.7mA    244.8mA    242.4mA
-1.03V    188.4mA    211.6mA    177.8mA
-981.8mV  142.4mA    178.9mA    121.2mA
-934.1mV  100.3mA    146.8mA    77.44mA
-886.4mV  64.86mA    115.8mA    51.3mA
-838.6mV  39.54mA    86.57mA    39.2mA
-743.2mV  19.48mA    38.59mA    26.04mA
-647.7mV  11.62mA    13.8mA     15.8mA
-552.3mV  5.869mA    5.781mA    7.847mA
-313.6mV  109.7uA    251.2uA    124.2uA
2.98V     -4.88mA    -3.924mA   -6.241mA
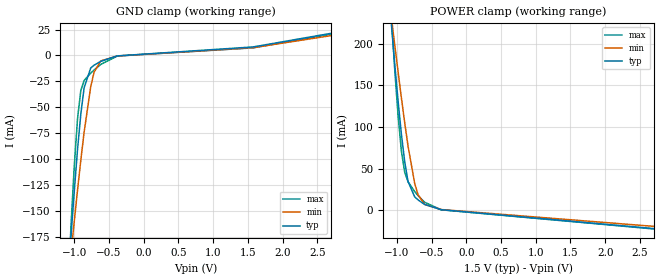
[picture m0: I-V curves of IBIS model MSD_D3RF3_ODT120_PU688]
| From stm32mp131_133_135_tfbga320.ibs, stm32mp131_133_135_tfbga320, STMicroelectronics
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[Model] MSD_D3RF3_ODT120_PU688
Model_type   Input
C_comp 2.387pF   2.342pF   2.492pF
Vinh = 925.000mV
Vinl = 575.000mV
[Temperature Range]   25.000   125.000   -40.000
[Voltage Range]   1.500V   1.425V   1.575V
[GND Clamp Reference]   0.00V   0.00V   0.00V
[POWER Clamp Reference]   1.500V   1.425V   1.575V
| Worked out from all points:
|   GND clamp passes 1 mA (typ) near -0.43 V on its own axis
|   POWER clamp passes 1 mA (typ) near -0.37 V on its own axis
[GND Clamp]
-1.48V    -619.7mA   -488.8mA   -826.9mA
-1.05V    -176.3mA   -192.1mA   -166.9mA
-1.002V   -132mA     -160.8mA   -108mA
-954.6mV  -91.36mA   -130.3mA   -61.46mA
-906.8mV  -56.68mA   -101.2mA   -33.82mA
-859.1mV  -31.23mA   -74.01mA   -24.17mA
-763.6mV  -12.09mA   -30mA      -17.05mA
-715.9mV  -9.462mA   -16.26mA   -14.11mA
-620.5mV  -5.737mA   -5.289mA   -8.711mA
-381.8mV  -442.4uA   -504uA     -551.4uA
1.575V    8.224mA    7.51mA     7.322mA
2.959V    24.42mA    21.83mA    23.48mA
[Power Clamp]
-1.459V   621.8mA    498.8mA    820.3mA
-1.077V   221.5mA    230.6mA    230.5mA
-1.03V    174.8mA    198.1mA    168.3mA
-981.8mV  130.9mA    166mA      113.4mA
-934.1mV  91.32mA    134.8mA    70.89mA
-886.4mV  58.25mA    104.9mA    45.71mA
-838.6mV  34.61mA    77.04mA    34.42mA
-743.2mV  16.38mA    32.59mA    22.64mA
-695.5mV  12.72mA    19mA       17.86mA
-600mV    7.191mA    7.24mA     9.854mA
-361.4mV  934.2uA    1.121mA    780.6uA
2.98V     -23.81mA   -20.9mA    -24.27mA
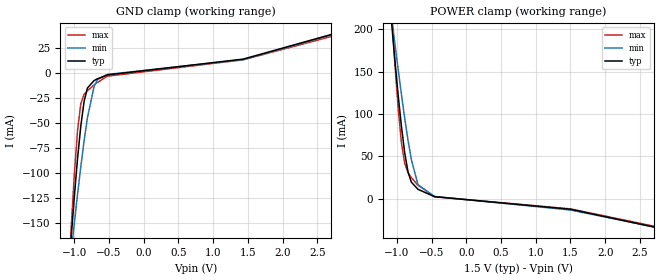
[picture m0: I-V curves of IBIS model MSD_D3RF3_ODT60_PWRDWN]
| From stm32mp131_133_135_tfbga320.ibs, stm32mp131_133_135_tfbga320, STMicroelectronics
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[Model] MSD_D3RF3_ODT60_PWRDWN
Model_type   Input
C_comp 2.495pF   2.446pF   2.559pF
Vinh = 925.000mV
Vinl = 575.000mV
[Model Spec]
Vinh   925.000mV   888.000mV   963.000mV
Vinl   575.000mV   538.000mV   613.000mV
[Temperature Range]   25.000   125.000   -40.000
[Voltage Range]   1.500V   1.425V   1.575V
[GND Clamp Reference]   0.00V   0.00V   0.00V
[POWER Clamp Reference]   1.500V   1.425V   1.575V
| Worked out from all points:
|   GND clamp passes 1 mA (typ) near -0.45 V on its own axis
|   POWER clamp passes 1 mA (typ) near -0.27 V on its own axis
[GND Clamp]
-1.48V    -605.8mA   -473.5mA   -813.1mA
-1.05V    -168.2mA   -181.8mA   -160.3mA
-1.002V   -125.2mA   -151.2mA   -103.4mA
-954.6mV  -86.13mA   -121.7mA   -58.02mA
-906.8mV  -53.01mA   -93.61mA   -30.91mA
-859.1mV  -28.54mA   -67.72mA   -21.58mA
-811.4mV  -15.29mA   -44.91mA   -17.88mA
-715.9mV  -7.865mA   -13.82mA   -12.31mA
-668.2mV  -6.148mA   -7.012mA   -9.783mA
-525mV    -2.247mA   -1.753mA   -3.527mA
1.432V    13.51mA    12.9mA     12.84mA
2.959V    43mA       42.56mA    40.73mA
[Power Clamp]
-1.459V   603.2mA    479.1mA    802.4mA
-1.077V   209.3mA    215.7mA    221.5mA
-1.03V    164.6mA    184mA      161.2mA
-981.8mV  122.9mA    153.1mA    107.7mA
-934.1mV  85.65mA    123.2mA    66.06mA
-886.4mV  54.2mA     94.84mA    41.64mA
-838.6mV  31.54mA    68.91mA    31.01mA
-790.9mV  19.73mA    46.48mA    25.15mA
-695.5mV  11.36mA    16.75mA    16.06mA
-456.8mV  2.628mA    2.884mA    2.652mA
1.5V      -12.11mA   -13.01mA   -11.7mA
2.98V     -37.93mA   -37.52mA   -36.77mA
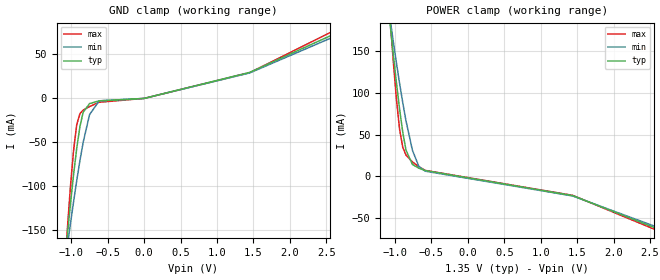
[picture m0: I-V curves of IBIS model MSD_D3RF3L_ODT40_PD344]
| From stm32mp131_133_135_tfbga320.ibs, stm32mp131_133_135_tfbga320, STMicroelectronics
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[Model] MSD_D3RF3L_ODT40_PD344
Model_type   Input
C_comp 2.270pF   2.232pF   2.321pF
Vinh = 810.000mV
Vinl = 540.000mV
[Receiver Thresholds]
Vth   =  0.675V
Vth_min  =  0.6615V
Vth_max  =  0.6885V
Vinh_ac  =  0.160V
Vinh_dc  =  0.090V
Vinl_ac  = -0.160V
Vinl_dc  = -0.090V
Tslew_ac =  5.000ns |Not specified, so set to high value
[Temperature Range]   25.000   125.000   -40.000
[Voltage Range]   1.350V   1.283V   1.450V
[GND Clamp Reference]   0.00V   0.00V   0.00V
[POWER Clamp Reference]   1.350V   1.283V   1.450V
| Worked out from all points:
|   GND clamp passes 1 mA (typ) near -0.47 V on its own axis
|   POWER clamp passes 1 mA (typ) near -0.15 V on its own axis
[GND Clamp]
-1.318V   -414.9mA   -340.9mA   -532.7mA
-1.055V   -158.9mA   -170.2mA   -152.9mA
-1.011V   -121.3mA   -143.4mA   -102.2mA
-966.7mV  -86.9mA    -117.7mA   -59.43mA
-922.7mV  -56.5mA    -93.24mA   -29.85mA
-878.8mV  -31.84mA   -70.46mA   -17.23mA
-834.9mV  -15.73mA   -49.96mA   -13.3mA
-747mV    -5.846mA   -18.4mA    -9.236mA
-615.1mV  -2.742mA   -2.748mA   -4.352mA
200nV     4.014nA    3.751nA    4.249nA
1.45V     29.61mA    29.01mA    29.33mA
2.68V     75.86mA    72.8mA     80.06mA
[Power Clamp]
-1.33V    440.2mA    362.9mA    565.1mA
-1.067V   184.5mA    189.8mA    191.8mA
-1.023V   147.3mA    162.6mA    139.7mA
-978.8mV  112.5mA    136.4mA    92.94mA
-934.9mV  80.41mA    111.4mA    56.18mA
-890.9mV  52.56mA    88.03mA    34.8mA
-847mV    31.47mA    66.49mA    25.53mA
-759.1mV  14.39mA    31.35mA    17.45mA
-671.2mV  9.927mA    12.05mA    11.64mA
-583.3mV  7.051mA    6.307mA    7.248mA
1.438V    -22.96mA   -23.38mA   -22.63mA
2.668V    -65.02mA   -63.08mA   -67.24mA
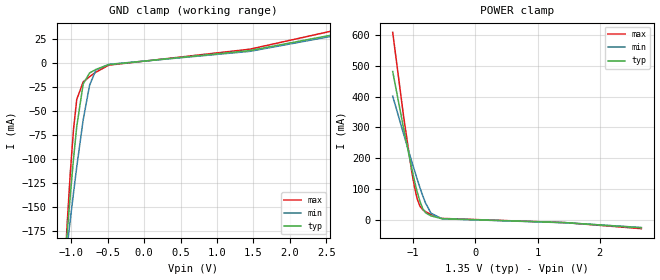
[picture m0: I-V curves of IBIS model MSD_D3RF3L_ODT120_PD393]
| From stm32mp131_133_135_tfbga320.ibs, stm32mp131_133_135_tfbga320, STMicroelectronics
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[Model] MSD_D3RF3L_ODT120_PD393
Model_type   Input
C_comp 2.321pF   2.243pF   2.410pF
Vinh = 810.000mV
Vinl = 540.000mV
[Model Spec]
Vinh   810.000mV   777.000mV   860.000mV
Vinl   540.000mV   507.000mV   590.000mV
[Receiver Thresholds]
Vth   =  0.675V
Vth_min  =  0.6615V
Vth_max  =  0.6885V
Vinh_ac  =  0.160V
Vinh_dc  =  0.090V
Vinl_ac  = -0.160V
Vinl_dc  = -0.090V
Tslew_ac =  5.000ns |Not specified, so set to high value
[Temperature Range]   25.000   125.000   -40.000
[Voltage Range]   1.350V   1.283V   1.450V
[GND Clamp Reference]   0.00V   0.00V   0.00V
[POWER Clamp Reference]   1.350V   1.283V   1.450V
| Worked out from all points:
|   GND clamp passes 1 mA (typ) near -0.43 V on its own axis
|   POWER clamp passes 1 mA (typ) near -0.32 V on its own axis
[GND Clamp]
-1.318V   -446.1mA   -371.1mA   -564.6mA
-1.098V   -221.1mA   -221mA     -229.4mA
-1.055V   -178.4mA   -191.8mA   -168.8mA
-1.011V   -137.5mA   -163.1mA   -114.1mA
-966.7mV  -99.63mA   -135.1mA   -68.87mA
-922.7mV  -66.14mA   -108.2mA   -38.02mA
-834.9mV  -22.05mA   -59.37mA   -19.87mA
-747mV    -10.48mA   -23.34mA   -14.38mA
-659.1mV  -6.774mA   -7.272mA   -9.612mA
-483.3mV  -1.811mA   -1.536mA   -2.358mA
1.45V     12.79mA    11.97mA    14.23mA
2.68V     30.48mA    29.16mA    34.89mA
[Power Clamp]
-1.33V    481.1mA    401.4mA    607.7mA
-1.155V   297.4mA    279.1mA    335.9mA
-1.023V   166.3mA    189.3mA    156mA
-978.8mV  126.6mA    160.2mA    106.7mA
-934.9mV  90.71mA    131.8mA    67.92mA
-890.9mV  60.24mA    104.6mA    44.75mA
-847mV    37.36mA    79.03mA    33.88mA
-803mV    24mA       56.11mA    27.81mA
-715.1mV  13.99mA    22.71mA    18.65mA
-539.4mV  4.814mA    4.519mA    5.738mA
1.438V    -7.735mA   -8.295mA   -7.847mA
2.668V    -24.58mA   -23.72mA   -27.44mA
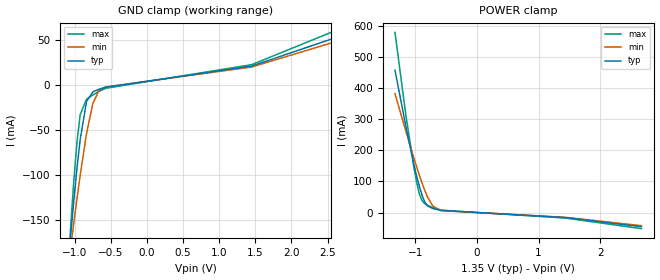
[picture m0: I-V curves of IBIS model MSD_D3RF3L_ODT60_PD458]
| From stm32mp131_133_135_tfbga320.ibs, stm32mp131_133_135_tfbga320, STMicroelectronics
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[Model] MSD_D3RF3L_ODT60_PD458
Model_type   Input
C_comp 2.347pF   2.297pF   2.415pF
Vinh = 810.000mV
Vinl = 540.000mV
[Receiver Thresholds]
Vth   =  0.675V
Vth_min  =  0.6615V
Vth_max  =  0.6885V
Vinh_ac  =  0.160V
Vinh_dc  =  0.090V
Vinl_ac  = -0.160V
Vinl_dc  = -0.090V
Tslew_ac =  5.000ns |Not specified, so set to high value
[Temperature Range]   25.000   125.000   -40.000
[Voltage Range]   1.350V   1.283V   1.450V
[GND Clamp Reference]   0.00V   0.00V   0.00V
[POWER Clamp Reference]   1.350V   1.283V   1.450V
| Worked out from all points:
|   GND clamp passes 1 mA (typ) near -0.46 V on its own axis
|   POWER clamp passes 1 mA (typ) near -0.18 V on its own axis
[GND Clamp]
-1.318V   -429.5mA   -356.5mA   -544.8mA
-1.098V   -208.9mA   -209.5mA   -216.6mA
-1.055V   -167.4mA   -180.9mA   -158.6mA
-1.011V   -128.3mA   -153.1mA   -106.6mA
-966.7mV  -92.21mA   -126.1mA   -63.14mA
-922.7mV  -60.55mA   -100.2mA   -33.16mA
-834.9mV  -18.53mA   -54.01mA   -15.94mA
-747mV    -7.878mA   -20.5mA    -11.27mA
-659.1mV  -4.913mA   -5.799mA   -7.28mA
-571.2mV  -2.779mA   -2.416mA   -3.948mA
1.45V     20.76mA    19.69mA    22.3mA
2.68V     54.13mA    49.48mA    62.4mA
[Power Clamp]
-1.33V    458.6mA    382.7mA    580.1mA
-1.155V   279.1mA    262.7mA    316.2mA
-1.023V   154.4mA    175.5mA    145.1mA
-978.8mV  117.7mA    147.5mA    97.62mA
-934.9mV  84.39mA    120.5mA    60.18mA
-890.9mV  55.65mA    94.89mA    38.2mA
-847mV    33.92mA    71.29mA    28.4mA
-803mV    21.42mA    50.45mA    23.3mA
-715.1mV  12.72mA    20.51mA    15.85mA
-583.3mV  6.852mA    6.121mA    7.584mA
1.438V    -16.34mA   -15.53mA   -17.88mA
2.668V    -45.67mA   -42.23mA   -51.96mA
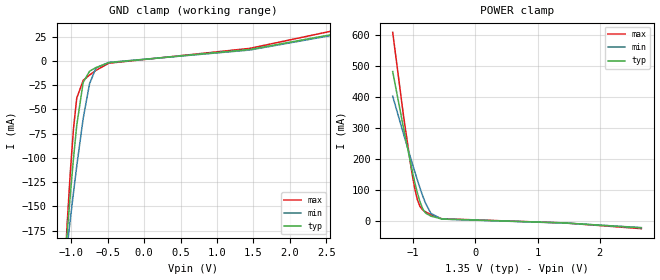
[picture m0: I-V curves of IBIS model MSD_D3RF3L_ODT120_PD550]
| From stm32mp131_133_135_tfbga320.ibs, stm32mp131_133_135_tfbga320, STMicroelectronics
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[Model] MSD_D3RF3L_ODT120_PD550
Model_type   Input
C_comp 2.380pF   2.302pF   2.470pF
Vinh = 810.000mV
Vinl = 540.000mV
[Receiver Thresholds]
Vth   =  0.675V
Vth_min  =  0.6615V
Vth_max  =  0.6885V
Vinh_ac  =  0.160V
Vinh_dc  =  0.090V
Vinl_ac  = -0.160V
Vinl_dc  = -0.090V
Tslew_ac =  5.000ns |Not specified, so set to high value
[Temperature Range]   25.000   125.000   -40.000
[Voltage Range]   1.350V   1.283V   1.450V
[GND Clamp Reference]   0.00V   0.00V   0.00V
[POWER Clamp Reference]   1.350V   1.283V   1.450V
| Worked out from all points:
|   GND clamp passes 1 mA (typ) near -0.43 V on its own axis
|   POWER clamp passes 1 mA (typ) near -0.31 V on its own axis
[GND Clamp]
-1.318V   -446.7mA   -371.6mA   -565.2mA
-1.098V   -221.5mA   -221.3mA   -229.9mA
-1.055V   -178.8mA   -192.1mA   -169.3mA
-1.011V   -138mA     -163.4mA   -114.6mA
-966.7mV  -99.95mA   -135.4mA   -69.31mA
-922.7mV  -66.44mA   -108.4mA   -38.42mA
-834.9mV  -22.29mA   -59.57mA   -20.19mA
-747mV    -10.68mA   -23.5mA    -14.64mA
-659.1mV  -6.923mA   -7.392mA   -9.802mA
-483.3mV  -1.869mA   -1.582mA   -2.43mA
1.45V     11.72mA    11.15mA    12.86mA
2.68V     28.52mA    27.65mA    32.4mA
[Power Clamp]
-1.33V    481.8mA    402mA      608.5mA
-1.155V   298mA      279.5mA    336.5mA
-1.023V   166.7mA    189.7mA    156.5mA
-978.8mV  127mA      160.6mA    107.2mA
-934.9mV  91.08mA    132.1mA    68.34mA
-890.9mV  60.57mA    104.9mA    45.11mA
-847mV    37.65mA    79.31mA    34.21mA
-803mV    24.27mA    56.34mA    28.1mA
-715.1mV  14.2mA     22.9mA     18.87mA
-539.4mV  4.92mA     4.61mA     5.839mA
1.438V    -7.67mA    -8.204mA   -7.847mA
2.668V    -23.6mA    -22.9mA    -26.27mA
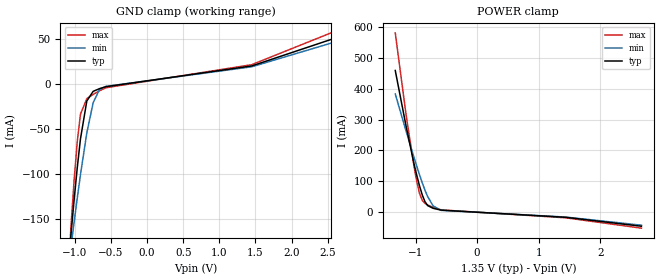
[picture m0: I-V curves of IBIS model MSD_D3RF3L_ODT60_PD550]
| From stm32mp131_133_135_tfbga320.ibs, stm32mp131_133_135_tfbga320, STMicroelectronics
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[Model] MSD_D3RF3L_ODT60_PD550
Model_type   Input
C_comp 2.376pF   2.326pF   2.445pF
Vinh = 810.000mV
Vinl = 540.000mV
[Receiver Thresholds]
Vth   =  0.675V
Vth_min  =  0.6615V
Vth_max  =  0.6885V
Vinh_ac  =  0.160V
Vinh_dc  =  0.090V
Vinl_ac  = -0.160V
Vinl_dc  = -0.090V
Tslew_ac =  5.000ns |Not specified, so set to high value
[Temperature Range]   25.000   125.000   -40.000
[Voltage Range]   1.350V   1.283V   1.450V
[GND Clamp Reference]   0.00V   0.00V   0.00V
[POWER Clamp Reference]   1.350V   1.283V   1.450V
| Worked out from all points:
|   GND clamp passes 1 mA (typ) near -0.45 V on its own axis
|   POWER clamp passes 1 mA (typ) near -0.18 V on its own axis
[GND Clamp]
-1.318V   -429.8mA   -356.8mA   -545.2mA
-1.098V   -209.1mA   -209.6mA   -216.8mA
-1.055V   -167.6mA   -181.2mA   -158.8mA
-1.011V   -128.4mA   -153.3mA   -106.9mA
-966.7mV  -92.37mA   -126.2mA   -63.38mA
-922.7mV  -60.7mA    -100.4mA   -33.33mA
-834.9mV  -18.66mA   -54.1mA    -16.08mA
-747mV    -7.976mA   -20.58mA   -11.38mA
-659.1mV  -4.989mA   -5.861mA   -7.37mA
-571.2mV  -2.822mA   -2.452mA   -3.998mA
1.45V     20.23mA    19.27mA    21.62mA
2.68V     53.16mA    48.72mA    61.16mA
[Power Clamp]
-1.33V    458.9mA    383mA      580.5mA
-1.155V   279.3mA    263mA      316.5mA
-1.023V   154.7mA    175.7mA    145.4mA
-978.8mV  117.9mA    147.7mA    97.85mA
-934.9mV  84.53mA    120.7mA    60.39mA
-890.9mV  55.8mA     95.01mA    38.38mA
-847mV    34.07mA    71.41mA    28.56mA
-803mV    21.55mA    50.56mA    23.44mA
-715.1mV  12.82mA    20.6mA     15.95mA
-583.3mV  6.906mA    6.185mA    7.647mA
1.438V    -16.3mA    -15.49mA   -17.88mA
2.668V    -45.18mA   -41.82mA   -51.41mA
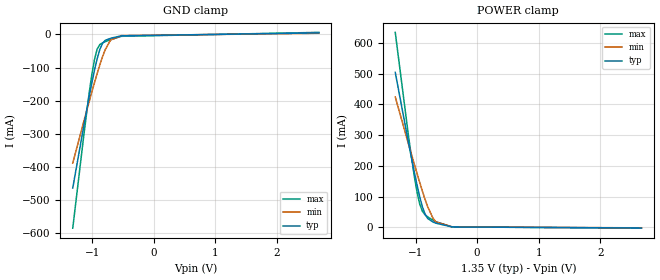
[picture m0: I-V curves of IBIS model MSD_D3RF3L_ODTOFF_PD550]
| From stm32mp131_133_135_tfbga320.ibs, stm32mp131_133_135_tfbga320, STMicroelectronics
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[Model] MSD_D3RF3L_ODTOFF_PD550
Model_type   Input
C_comp 2.422pF   2.338pF   2.546pF
Vinh = 810.000mV
Vinl = 540.000mV
[Receiver Thresholds]
Vth   =  0.675V
Vth_min  =  0.6615V
Vth_max  =  0.6885V
Vinh_ac  =  0.160V
Vinh_dc  =  0.090V
Vinl_ac  = -0.160V
Vinl_dc  = -0.090V
Tslew_ac =  5.000ns |Not specified, so set to high value
[Temperature Range]   25.000   125.000   -40.000
[Voltage Range]   1.350V   1.283V   1.450V
[GND Clamp Reference]   0.00V   0.00V   0.00V
[POWER Clamp Reference]   1.350V   1.283V   1.450V
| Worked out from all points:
|   GND clamp passes 1 mA (typ) near -0.40 V on its own axis
|   POWER clamp passes 1 mA (typ) near -0.41 V on its own axis
[GND Clamp]
-1.318V   -463.9mA   -388.5mA   -585.1mA
-1.142V   -279.6mA   -265.3mA   -309.9mA
-1.055V   -191mA     -205mA     -181.7mA
-1.011V   -148.8mA   -175.5mA   -124.6mA
-966.7mV  -109.3mA   -146.7mA   -76.96mA
-922.7mV  -73.94mA   -118.7mA   -44.75mA
-878.8mV  -45.42mA   -92.19mA   -30.53mA
-834.9mV  -26.78mA   -67.56mA   -25.28mA
-790.9mV  -17.89mA   -45.88mA   -21.84mA
-703mV    -11.46mA   -16.68mA   -15.76mA
-527.3mV  -4.111mA   -3.461mA   -5.543mA
2.68V     4.87mA     3.78mA     6.33mA
[Power Clamp]
-1.33V    504.2mA    424mA      634.2mA
-1.111V   270.9mA    267.9mA    290.4mA
-1.023V   181.5mA    206.7mA    168.7mA
-978.8mV  139.5mA    176.6mA    117.3mA
-934.9mV  100.8mA    147.1mA    76.96mA
-890.9mV  67.73mA    118.5mA    52.55mA
-847mV    42.97mA    91.33mA    40.6mA
-803mV    28.39mA    66.43mA    33.57mA
-715.1mV  16.74mA    28.48mA    22.7mA
-671.2mV  13.24mA    17.51mA    18.02mA
-407.6mV  923uA      1.208mA    1.13mA
2.668V    -2.45mA    -2.038mA   -2.919mA
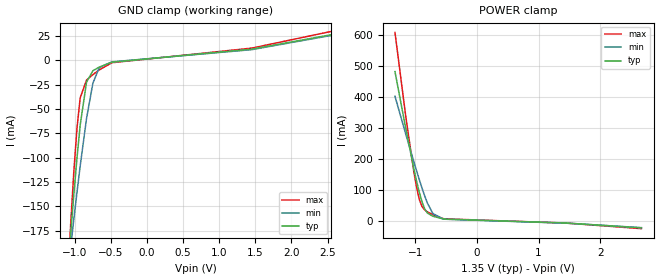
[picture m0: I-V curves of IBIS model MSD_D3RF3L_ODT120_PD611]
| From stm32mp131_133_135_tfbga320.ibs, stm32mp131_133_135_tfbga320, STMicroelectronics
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[Model] MSD_D3RF3L_ODT120_PD611
Model_type   Input
C_comp 2.397pF   2.319pF   2.488pF
Vinh = 810.000mV
Vinl = 540.000mV
[Model Spec]
Vinh   810.000mV   777.000mV   860.000mV
Vinl   540.000mV   507.000mV   590.000mV
[Receiver Thresholds]
Vth   =  0.675V
Vth_min  =  0.6615V
Vth_max  =  0.6885V
Vinh_ac  =  0.160V
Vinh_dc  =  0.090V
Vinl_ac  = -0.160V
Vinl_dc  = -0.090V
Tslew_ac =  5.000ns |Not specified, so set to high value
[Temperature Range]   25.000   125.000   -40.000
[Voltage Range]   1.350V   1.283V   1.450V
[GND Clamp Reference]   0.00V   0.00V   0.00V
[POWER Clamp Reference]   1.350V   1.283V   1.450V
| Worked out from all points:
|   GND clamp passes 1 mA (typ) near -0.43 V on its own axis
|   POWER clamp passes 1 mA (typ) near -0.31 V on its own axis
[GND Clamp]
-1.318V   -446.8mA   -371.7mA   -565.4mA
-1.098V   -221.6mA   -221.4mA   -230.1mA
-1.055V   -178.9mA   -192.2mA   -169.3mA
-1.011V   -138.1mA   -163.5mA   -114.7mA
-966.7mV  -100mA     -135.4mA   -69.42mA
-922.7mV  -66.51mA   -108.5mA   -38.51mA
-834.9mV  -22.35mA   -59.62mA   -20.28mA
-747mV    -10.73mA   -23.54mA   -14.71mA
-659.1mV  -6.956mA   -7.428mA   -9.851mA
-483.3mV  -1.879mA   -1.603mA   -2.457mA
1.45V     11.45mA    10.94mA    12.51mA
2.68V     28.03mA    27.27mA    31.72mA
[Power Clamp]
-1.33V    481.9mA    402.2mA    608.7mA
-1.155V   298mA      279.6mA    336.7mA
-1.023V   166.8mA    189.8mA    156.6mA
-978.8mV  127.1mA    160.7mA    107.3mA
-934.9mV  91.2mA     132.3mA    68.47mA
-890.9mV  60.65mA    105mA      45.25mA
-847mV    37.73mA    79.4mA     34.33mA
-803mV    24.34mA    56.4mA     28.21mA
-715.1mV  14.25mA    22.94mA    18.96mA
-539.4mV  4.946mA    4.63mA     5.889mA
1.438V    -7.654mA   -8.181mA   -7.847mA
2.668V    -23.36mA   -22.7mA    -25.98mA
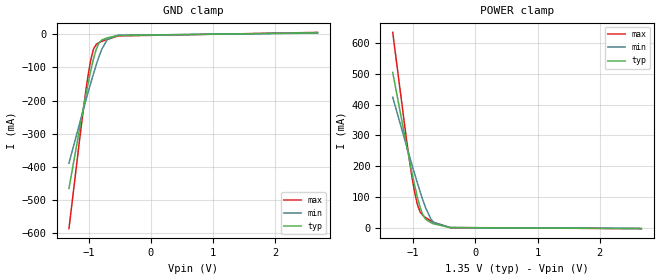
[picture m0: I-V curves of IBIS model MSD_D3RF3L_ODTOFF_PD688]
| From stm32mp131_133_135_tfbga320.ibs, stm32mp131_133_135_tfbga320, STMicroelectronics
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[Model] MSD_D3RF3L_ODTOFF_PD688
Model_type   Input
C_comp 2.452pF   2.367pF   2.576pF
Vinh = 810.000mV
Vinl = 540.000mV
[Receiver Thresholds]
Vth   =  0.675V
Vth_min  =  0.6615V
Vth_max  =  0.6885V
Vinh_ac  =  0.160V
Vinh_dc  =  0.090V
Vinl_ac  = -0.160V
Vinl_dc  = -0.090V
Tslew_ac =  5.000ns |Not specified, so set to high value
[Temperature Range]   25.000   125.000   -40.000
[Voltage Range]   1.350V   1.283V   1.450V
[GND Clamp Reference]   0.00V   0.00V   0.00V
[POWER Clamp Reference]   1.350V   1.283V   1.450V
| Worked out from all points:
|   GND clamp passes 1 mA (typ) near -0.40 V on its own axis
|   POWER clamp passes 1 mA (typ) near -0.41 V on its own axis
[GND Clamp]
-1.318V   -464.2mA   -388.6mA   -585.5mA
-1.142V   -279.8mA   -265.5mA   -310.2mA
-1.055V   -191.2mA   -205.3mA   -182mA
-1.011V   -149mA     -175.7mA   -124.8mA
-966.7mV  -109.5mA   -146.9mA   -77.18mA
-922.7mV  -74.08mA   -118.9mA   -44.94mA
-878.8mV  -45.55mA   -92.3mA    -30.72mA
-834.9mV  -26.9mA    -67.66mA   -25.45mA
-790.9mV  -17.99mA   -45.97mA   -21.99mA
-703mV    -11.54mA   -16.76mA   -15.86mA
-527.3mV  -4.15mA    -3.493mA   -5.595mA
2.68V     3.897mA    3.031mA    5.065mA
[Power Clamp]
-1.33V    504.5mA    424.3mA    634.5mA
-1.111V   271.2mA    268.2mA    290.7mA
-1.023V   181.6mA    206.8mA    168.9mA
-978.8mV  139.6mA    176.7mA    117.5mA
-934.9mV  101mA      147.2mA    77.17mA
-890.9mV  67.89mA    118.6mA    52.74mA
-847mV    43.11mA    91.44mA    40.78mA
-803mV    28.51mA    66.53mA    33.73mA
-715.1mV  16.84mA    28.57mA    22.83mA
-671.2mV  13.31mA    17.59mA    18.13mA
-407.6mV  938uA      1.223mA    1.149mA
2.668V    -1.96mA    -1.631mA   -2.335mA
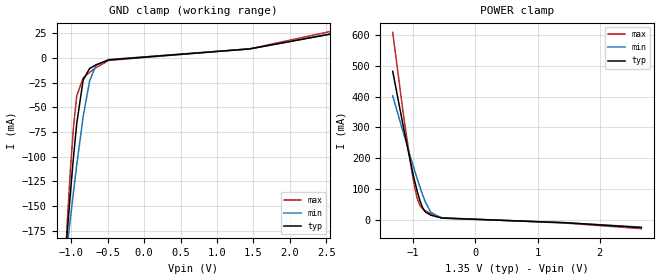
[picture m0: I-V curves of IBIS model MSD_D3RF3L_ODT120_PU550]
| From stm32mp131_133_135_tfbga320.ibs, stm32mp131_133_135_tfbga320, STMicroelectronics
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[Model] MSD_D3RF3L_ODT120_PU550
Model_type   Input
C_comp 2.383pF   2.304pF   2.474pF
Vinh = 810.000mV
Vinl = 540.000mV
[Receiver Thresholds]
Vth   =  0.675V
Vth_min  =  0.6615V
Vth_max  =  0.6885V
Vinh_ac  =  0.160V
Vinh_dc  =  0.090V
Vinl_ac  = -0.160V
Vinl_dc  = -0.090V
Tslew_ac =  5.000ns |Not specified, so set to high value
[Temperature Range]   25.000   125.000   -40.000
[Voltage Range]   1.350V   1.283V   1.450V
[GND Clamp Reference]   0.00V   0.00V   0.00V
[POWER Clamp Reference]   1.350V   1.283V   1.450V
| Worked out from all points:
|   GND clamp passes 1 mA (typ) near -0.43 V on its own axis
|   POWER clamp passes 1 mA (typ) near -0.31 V on its own axis
[GND Clamp]
-1.318V   -446.7mA   -371.5mA   -565.2mA
-1.098V   -221.5mA   -221.2mA   -229.9mA
-1.055V   -178.8mA   -192.1mA   -169.2mA
-1.011V   -137.9mA   -163.4mA   -114.5mA
-966.7mV  -99.9mA    -135.4mA   -69.26mA
-922.7mV  -66.4mA    -108.4mA   -38.37mA
-834.9mV  -22.27mA   -59.53mA   -20.16mA
-747mV    -10.65mA   -23.47mA   -14.6mA
-659.1mV  -6.906mA   -7.373mA   -9.771mA
-483.3mV  -1.858mA   -1.574mA   -2.416mA
1.45V     9.251mA    9.317mA    9.417mA
2.68V     26.07mA    25.91mA    28.92mA
[Power Clamp]
-1.33V    481.9mA    402.3mA    608.6mA
-1.155V   298mA      279.6mA    336.6mA
-1.023V   166.8mA    189.8mA    156.5mA
-978.8mV  127mA      160.7mA    107.2mA
-934.9mV  91.13mA    132.2mA    68.4mA
-890.9mV  60.61mA    104.9mA    45.17mA
-847mV    37.71mA    79.39mA    34.26mA
-803mV    24.32mA    56.41mA    28.15mA
-715.1mV  14.23mA    22.96mA    18.92mA
-539.4mV  4.94mA     4.646mA    5.867mA
1.438V    -10.09mA   -10.05mA   -11.18mA
2.668V    -25.93mA   -24.68mA   -29.54mA
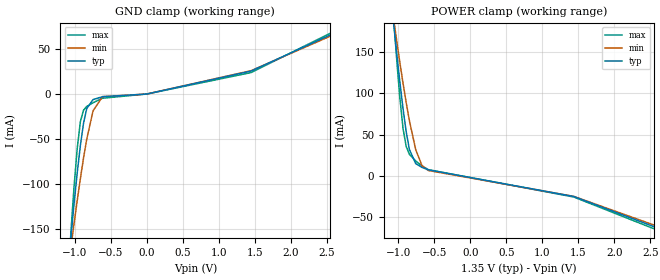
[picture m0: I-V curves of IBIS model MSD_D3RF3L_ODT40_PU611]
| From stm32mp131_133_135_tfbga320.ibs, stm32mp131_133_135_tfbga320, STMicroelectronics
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[Model] MSD_D3RF3L_ODT40_PU611
Model_type   Input
C_comp 2.379pF   2.339pF   2.433pF
Vinh = 810.000mV
Vinl = 540.000mV
[Receiver Thresholds]
Vth   =  0.675V
Vth_min  =  0.6615V
Vth_max  =  0.6885V
Vinh_ac  =  0.160V
Vinh_dc  =  0.090V
Vinl_ac  = -0.160V
Vinl_dc  = -0.090V
Tslew_ac =  5.000ns |Not specified, so set to high value
[Temperature Range]   25.000   125.000   -40.000
[Voltage Range]   1.350V   1.283V   1.450V
[GND Clamp Reference]   0.00V   0.00V   0.00V
[POWER Clamp Reference]   1.350V   1.283V   1.450V
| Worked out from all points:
|   GND clamp passes 1 mA (typ) near -0.46 V on its own axis
|   POWER clamp passes 1 mA (typ) near -0.14 V on its own axis
[GND Clamp]
-1.318V   -415.8mA   -341.7mA   -533.9mA
-1.055V   -159.5mA   -170.7mA   -153.7mA
-1.011V   -121.9mA   -143.9mA   -102.9mA
-966.7mV  -87.43mA   -118.1mA   -60.17mA
-922.7mV  -56.97mA   -93.68mA   -30.48mA
-878.8mV  -32.29mA   -70.85mA   -17.81mA
-834.9mV  -16.13mA   -50.29mA   -13.82mA
-747mV    -6.166mA   -18.67mA   -9.638mA
-615.1mV  -2.932mA   -2.91mA    -4.606mA
200nV     3.403nA    3.263nA    3.449nA
1.45V     25.52mA    25.92mA    23.83mA
2.68V     70.21mA    68.65mA    72.55mA
[Power Clamp]
-1.33V    441.5mA    364mA      566.6mA
-1.067V   185.5mA    190.6mA    192.9mA
-1.023V   148.2mA    163.4mA    140.6mA
-978.8mV  113.2mA    137.1mA    93.82mA
-934.9mV  81.06mA    112mA      57.02mA
-890.9mV  53.15mA    88.53mA    35.52mA
-847mV    32.05mA    66.96mA    26.18mA
-759.1mV  14.85mA    31.74mA    17.95mA
-671.2mV  10.28mA    12.34mA    12.03mA
-583.3mV  7.305mA    6.509mA    7.504mA
1.438V    -25.03mA   -24.88mA   -25.64mA
2.668V    -65.41mA   -63.24mA   -68.17mA
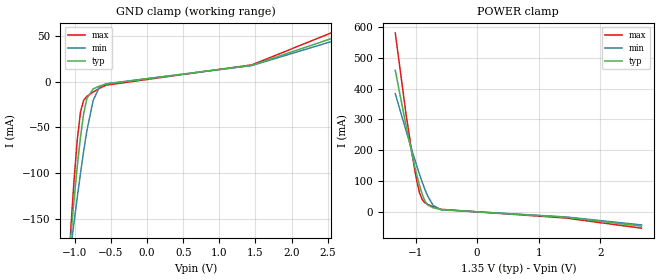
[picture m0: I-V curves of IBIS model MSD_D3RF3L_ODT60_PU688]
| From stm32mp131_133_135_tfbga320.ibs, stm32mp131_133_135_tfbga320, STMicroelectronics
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[Model] MSD_D3RF3L_ODT60_PU688
Model_type   Input
C_comp 2.409pF   2.357pF   2.478pF
Vinh = 810.000mV
Vinl = 540.000mV
[Receiver Thresholds]
Vth   =  0.675V
Vth_min  =  0.6615V
Vth_max  =  0.6885V
Vinh_ac  =  0.160V
Vinh_dc  =  0.090V
Vinl_ac  = -0.160V
Vinl_dc  = -0.090V
Tslew_ac =  5.000ns |Not specified, so set to high value
[Temperature Range]   25.000   125.000   -40.000
[Voltage Range]   1.350V   1.283V   1.450V
[GND Clamp Reference]   0.00V   0.00V   0.00V
[POWER Clamp Reference]   1.350V   1.283V   1.450V
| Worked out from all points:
|   GND clamp passes 1 mA (typ) near -0.45 V on its own axis
|   POWER clamp passes 1 mA (typ) near -0.18 V on its own axis
[GND Clamp]
-1.318V   -430mA     -356.8mA   -545.4mA
-1.055V   -167.8mA   -181.2mA   -159mA
-1.011V   -128.5mA   -153.3mA   -107mA
-966.7mV  -92.4mA    -126.3mA   -63.52mA
-922.7mV  -60.79mA   -100.4mA   -33.5mA
-878.8mV  -35.37mA   -76.1mA    -20.5mA
-834.9mV  -18.72mA   -54.14mA   -16.22mA
-747mV    -8.022mA   -20.61mA   -11.48mA
-659.1mV  -5.01mA    -5.878mA   -7.44mA
-571.2mV  -2.838mA   -2.462mA   -4.05mA
1.45V     17.73mA    17.41mA    18.18mA
2.68V     50.25mA    46.65mA    57.16mA
[Power Clamp]
-1.33V    459.3mA    383.4mA    580.9mA
-1.155V   279.7mA    263.3mA    316.8mA
-1.023V   154.9mA    175.9mA    145.6mA
-978.8mV  118.1mA    147.9mA    98.03mA
-934.9mV  84.7mA     120.9mA    60.62mA
-890.9mV  55.99mA    95.2mA     38.6mA
-847mV    34.24mA    71.57mA    28.75mA
-803mV    21.7mA     50.7mA     23.61mA
-715.1mV  12.93mA    20.7mA     16.08mA
-583.3mV  6.977mA    6.238mA    7.72mA
1.438V    -18.22mA   -16.93mA   -20.54mA
2.668V    -46.61mA   -42.88mA   -53.43mA
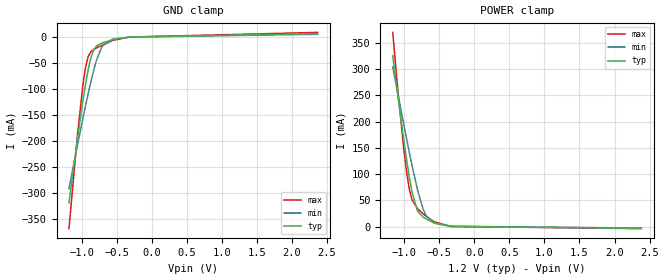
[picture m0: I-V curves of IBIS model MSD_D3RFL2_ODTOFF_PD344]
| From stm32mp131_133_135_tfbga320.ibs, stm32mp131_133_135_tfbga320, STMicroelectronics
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[Model] MSD_D3RFL2_ODTOFF_PD344
Model_type   Input
C_comp 2.341pF   2.256pF   2.465pF
Vinh = 820.000mV
Vinl = 380.000mV
[Model Spec]
Vinh   820.000mV   790.000mV   870.000mV
Vinl   380.000mV   350.000mV   430.000mV
[Temperature Range]   25.000   125.000   -40.000
[Voltage Range]   1.200V   1.140V   1.300V
[GND Clamp Reference]   0.00V   0.00V   0.00V
[POWER Clamp Reference]   1.200V   1.140V   1.300V
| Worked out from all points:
|   GND clamp passes 1 mA (typ) near -0.40 V on its own axis
|   POWER clamp passes 1 mA (typ) near -0.42 V on its own axis
[GND Clamp]
-1.182V   -319.6mA   -292.1mA   -369.4mA
-1.064V   -199.4mA   -210.8mA   -193.6mA
-984.9mV  -124.7mA   -158.1mA   -94.48mA
-945.5mV  -91.09mA   -132.7mA   -58.49mA
-906.1mV  -61.71mA   -108.1mA   -36.94mA
-866.7mV  -38.79mA   -84.85mA   -28.13mA
-827.3mV  -24.3mA    -63.3mA    -24.16mA
-787.9mV  -17.19mA   -44.27mA   -21.19mA
-709.1mV  -11.52mA   -17.78mA   -15.81mA
-551.5mV  -4.822mA   -4.061mA   -6.554mA
-315.1mV  -154.1uA   -220.9uA   -141.1uA
2.364V    6.702mA    5.137mA    8.803mA
[Power Clamp]
-1.164V   325.7mA    304.4mA    369.9mA
-1.085V   243.5mA    249.1mA    251.9mA
-1.006V   164.5mA    194.6mA    147.5mA
-966.7mV  127.8mA    167.7mA    104.2mA
-927.3mV  94.06mA    141.4mA    70.97mA
-887.9mV  65.2mA     116mA      50.6mA
-809.1mV  29.41mA    69.17mA    33.89mA
-730.3mV  17.77mA    33.06mA    24.02mA
-690.9mV  14.44mA    21.31mA    19.71mA
-572.7mV  6.714mA    6.582mA    9.049mA
-336.4mV  165.4uA    320.5uA    193.2uA
2.382V    -3.451mA   -2.842mA   -4.103mA
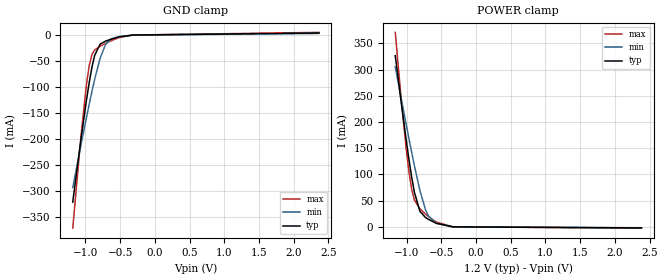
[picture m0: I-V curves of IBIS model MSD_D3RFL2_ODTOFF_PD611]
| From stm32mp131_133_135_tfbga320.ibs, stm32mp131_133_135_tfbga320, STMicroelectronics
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[Model] MSD_D3RFL2_ODTOFF_PD611
Model_type   Input
C_comp 2.448pF   2.362pF   2.573pF
Vinh = 820.000mV
Vinl = 380.000mV
[Temperature Range]   25.000   125.000   -40.000
[Voltage Range]   1.200V   1.140V   1.300V
[GND Clamp Reference]   0.00V   0.00V   0.00V
[POWER Clamp Reference]   1.200V   1.140V   1.300V
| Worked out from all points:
|   GND clamp passes 1 mA (typ) near -0.40 V on its own axis
|   POWER clamp passes 1 mA (typ) near -0.41 V on its own axis
[GND Clamp]
-1.182V   -320.5mA   -292.8mA   -370.5mA
-1.064V   -200.1mA   -211.3mA   -194.4mA
-984.9mV  -125.4mA   -158.6mA   -95.27mA
-945.5mV  -91.65mA   -133.2mA   -59.21mA
-906.1mV  -62.21mA   -108.5mA   -37.62mA
-866.7mV  -39.26mA   -85.22mA   -28.75mA
-787.9mV  -17.58mA   -44.58mA   -21.7mA
-709.1mV  -11.81mA   -18.02mA   -16.22mA
-630.3mV  -8.116mA   -7.712mA   -11.19mA
-512.1mV  -3.64mA    -3.085mA   -4.874mA
-315.1mV  -162.9uA   -229.6uA   -153.3uA
2.364V    3.773mA    2.887mA    4.949mA
[Power Clamp]
-1.164V   326.6mA    305.3mA    371mA
-1.085V   244.4mA    249.8mA    252.9mA
-1.006V   165.3mA    195.2mA    148.3mA
-966.7mV  128.4mA    168.3mA    105mA
-927.3mV  94.68mA    142.1mA    71.73mA
-887.9mV  65.77mA    116.5mA    51.3mA
-809.1mV  29.89mA    69.62mA    34.48mA
-730.3mV  18.15mA    33.42mA    24.48mA
-690.9mV  14.77mA    21.64mA    20.11mA
-572.7mV  6.916mA    6.791mA    9.298mA
-336.4mV  186.2uA    358.7uA    216.6uA
2.382V    -1.941mA   -1.599mA   -2.308mA
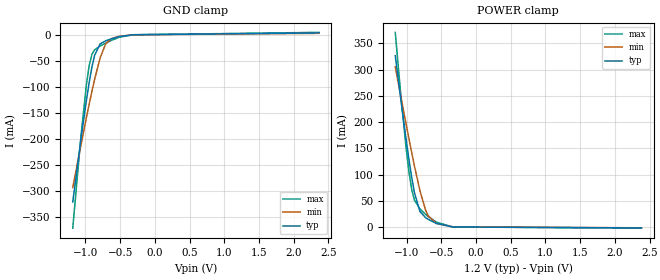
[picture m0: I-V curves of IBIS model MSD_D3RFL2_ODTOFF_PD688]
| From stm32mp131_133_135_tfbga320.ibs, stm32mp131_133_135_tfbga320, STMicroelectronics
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[Model] MSD_D3RFL2_ODTOFF_PD688
Model_type   Input
C_comp 2.461pF   2.374pF   2.586pF
Vinh = 820.000mV
Vinl = 380.000mV
[Temperature Range]   25.000   125.000   -40.000
[Voltage Range]   1.200V   1.140V   1.300V
[GND Clamp Reference]   0.00V   0.00V   0.00V
[POWER Clamp Reference]   1.200V   1.140V   1.300V
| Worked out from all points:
|   GND clamp passes 1 mA (typ) near -0.40 V on its own axis
|   POWER clamp passes 1 mA (typ) near -0.41 V on its own axis
[GND Clamp]
-1.182V   -320.6mA   -292.9mA   -370.7mA
-1.064V   -200.1mA   -211.4mA   -194.6mA
-984.9mV  -125.5mA   -158.7mA   -95.37mA
-945.5mV  -91.72mA   -133.2mA   -59.32mA
-906.1mV  -62.29mA   -108.7mA   -37.71mA
-866.7mV  -39.33mA   -85.28mA   -28.84mA
-787.9mV  -17.63mA   -44.62mA   -21.78mA
-709.1mV  -11.87mA   -18.06mA   -16.28mA
-630.3mV  -8.149mA   -7.738mA   -11.23mA
-512.1mV  -3.657mA   -3.099mA   -4.897mA
-315.1mV  -164.2uA   -230.6uA   -155.1uA
2.364V    3.351mA    2.568mA    4.402mA
[Power Clamp]
-1.164V   326.8mA    305.4mA    371.2mA
-1.085V   244.5mA    250mA      253mA
-1.006V   165.4mA    195.3mA    148.5mA
-966.7mV  128.5mA    168.4mA    105.1mA
-927.3mV  94.77mA    142.1mA    71.83mA
-887.9mV  65.86mA    116.6mA    51.39mA
-809.1mV  29.96mA    69.68mA    34.56mA
-730.3mV  18.21mA    33.48mA    24.54mA
-690.9mV  14.82mA    21.68mA    20.17mA
-572.7mV  6.947mA    6.82mA     9.333mA
-336.4mV  190.2uA    363.6uA    218.6uA
2.382V    -1.725mA   -1.421mA   -2.051mA
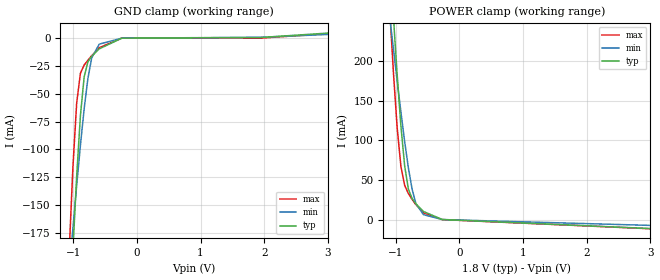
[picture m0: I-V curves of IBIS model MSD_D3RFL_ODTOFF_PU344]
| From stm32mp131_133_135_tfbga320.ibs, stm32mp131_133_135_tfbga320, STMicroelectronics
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[Model] MSD_D3RFL_ODTOFF_PU344
Model_type   Input
C_comp 2.293pF   2.233pF   2.437pF
Vinh = 1.440V
Vinl = 360.000mV
[Model Spec]
Vinh   1.440V   1.365V   1.515V
Vinl   360.000mV   285.000mV   435.000mV
[Temperature Range]   25.000   125.000   -40.000
[Voltage Range]   1.800V   1.650V   1.950V
[GND Clamp Reference]   0.00V   0.00V   0.00V
[POWER Clamp Reference]   1.800V   1.650V   1.950V
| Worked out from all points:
|   GND clamp passes 1 mA (typ) near -0.35 V on its own axis
|   POWER clamp passes 1 mA (typ) near -0.35 V on its own axis
[GND Clamp]
-1.773V   -1.214A    -711.9mA   -1.313A
-1.064V   -263.5mA   -210.7mA   -193.5mA
-1.005V   -191mA     -171mA     -116.6mA
-945.5mV  -124.4mA   -132.7mA   -58.47mA
-886.4mV  -69.49mA   -96.31mA   -31.45mA
-827.3mV  -34.7mA    -63.24mA   -24.15mA
-768.2mV  -21.28mA   -35.97mA   -19.79mA
-709.1mV  -16.28mA   -17.73mA   -15.79mA
-590.9mV  -9.638mA   -5.421mA   -8.61mA
-236.4mV  -69.03uA   -32.02uA   -6.03uA
1.95V     562.7uA    730uA      669.4pA
3.545V    6.549mA    4.613mA    6.086mA
[Power Clamp]
-1.745V   1.22A      725.3mA    1.303A
-1.095V   333.3mA    256.9mA    267.8mA
-1.036V   256.4mA    215.7mA    186.3mA
-977.3mV  183.4mA    175.2mA    116.5mA
-918.2mV  118.4mA    135.9mA    67.41mA
-859.1mV  67.72mA    98.54mA    43.16mA
-800mV    38.32mA    64.91mA    32.81mA
-740.9mV  26.43mA    37.84mA    25.36mA
-681.8mV  19.94mA    20.03mA    18.87mA
-563.6mV  10.29mA    6.281mA    8.486mA
-268.2mV  153.8uA    95.88uA    30.22uA
3.573V    -13.26mA   -8.567mA   -13.54mA
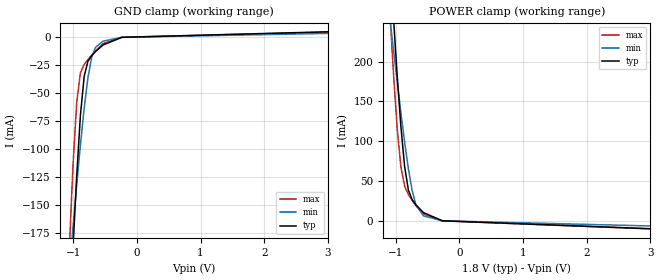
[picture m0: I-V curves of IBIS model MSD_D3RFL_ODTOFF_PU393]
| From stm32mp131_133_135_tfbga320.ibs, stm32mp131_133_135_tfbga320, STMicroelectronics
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[Model] MSD_D3RFL_ODTOFF_PU393
Model_type   Input
C_comp 2.322pF   2.262pF   2.468pF
Vinh = 1.440V
Vinl = 360.000mV
[Temperature Range]   25.000   125.000   -40.000
[Voltage Range]   1.800V   1.650V   1.950V
[GND Clamp Reference]   0.00V   0.00V   0.00V
[POWER Clamp Reference]   1.800V   1.650V   1.950V
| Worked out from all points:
|   GND clamp passes 1 mA (typ) near -0.35 V on its own axis
|   POWER clamp passes 1 mA (typ) near -0.35 V on its own axis
[GND Clamp]
-1.773V   -1.214A    -712.2mA   -1.313A
-1.064V   -263.7mA   -210.8mA   -193.8mA
-1.005V   -191.2mA   -171.2mA   -116.8mA
-945.5mV  -124.7mA   -132.7mA   -58.69mA
-886.4mV  -69.68mA   -96.37mA   -31.64mA
-827.3mV  -34.88mA   -63.34mA   -24.32mA
-768.2mV  -21.44mA   -36.05mA   -19.93mA
-709.1mV  -16.41mA   -17.81mA   -15.92mA
-650mV    -12.87mA   -9.081mA   -12.15mA
-531.8mV  -6.892mA   -3.5mA     -5.644mA
-236.4mV  -72.03uA   -34.02uA   -8.026uA
3.545V    5.733mA    4.036mA    5.323mA
[Power Clamp]
-1.745V   1.221A     725.6mA    1.304A
-1.095V   333.6mA    257.1mA    268mA
-1.036V   256.7mA    215.9mA    186.5mA
-977.3mV  183.7mA    175.4mA    116.7mA
-918.2mV  118.6mA    136mA      67.61mA
-859.1mV  67.91mA    98.63mA    43.34mA
-800mV    38.49mA    65.02mA    32.96mA
-740.9mV  26.58mA    37.93mA    25.49mA
-681.8mV  20.06mA    20.1mA     18.98mA
-563.6mV  10.37mA    6.326mA    8.549mA
-268.2mV  157.2uA    97.83uA    31.03uA
3.573V    -11.6mA    -7.497mA   -11.84mA
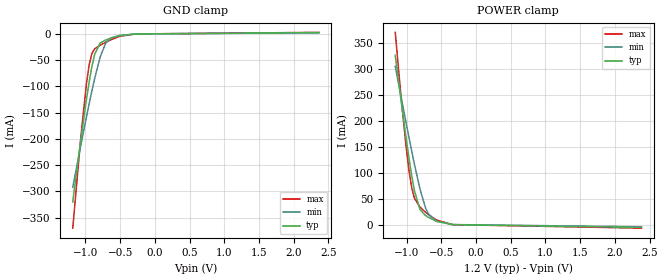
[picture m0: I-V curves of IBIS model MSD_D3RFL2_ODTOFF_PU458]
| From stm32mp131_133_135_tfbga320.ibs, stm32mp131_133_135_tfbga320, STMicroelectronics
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[Model] MSD_D3RFL2_ODTOFF_PU458
Model_type   Input
C_comp 2.406pF   2.319pF   2.532pF
Vinh = 820.000mV
Vinl = 380.000mV
[Temperature Range]   25.000   125.000   -40.000
[Voltage Range]   1.200V   1.140V   1.300V
[GND Clamp Reference]   0.00V   0.00V   0.00V
[POWER Clamp Reference]   1.200V   1.140V   1.300V
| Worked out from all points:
|   GND clamp passes 1 mA (typ) near -0.40 V on its own axis
|   POWER clamp passes 1 mA (typ) near -0.41 V on its own axis
[GND Clamp]
-1.182V   -320mA     -292.3mA   -370mA
-1.064V   -199.7mA   -210.9mA   -194mA
-984.9mV  -125mA     -158.3mA   -94.87mA
-945.5mV  -91.33mA   -132.8mA   -58.85mA
-906.1mV  -61.92mA   -108.3mA   -37.28mA
-866.7mV  -38.99mA   -84.96mA   -28.45mA
-787.9mV  -17.36mA   -44.36mA   -21.45mA
-709.1mV  -11.65mA   -17.84mA   -16.02mA
-630.3mV  -7.983mA   -7.58mA    -11.03mA
-512.1mV  -3.563mA   -3.002mA   -4.784mA
-275.8mV  -45.59uA   -84.59uA   -32.58uA
2.364V    2.499mA    2.108mA    2.946mA
[Power Clamp]
-1.164V   326.5mA    305.3mA    370.6mA
-1.085V   244.2mA    249.8mA    252.6mA
-1.006V   165.1mA    195.2mA    148.1mA
-966.7mV  128.2mA    168.4mA    104.7mA
-927.3mV  94.54mA    142.1mA    71.48mA
-887.9mV  65.63mA    116.5mA    51.07mA
-809.1mV  29.77mA    69.58mA    34.28mA
-730.3mV  18.06mA    33.39mA    24.33mA
-690.9mV  14.7mA     21.61mA    19.98mA
-572.7mV  6.875mA    6.78mA     9.219mA
-336.4mV  196.3uA    373.6uA    218.1uA
2.382V    -4.992mA   -3.966mA   -6.496mA
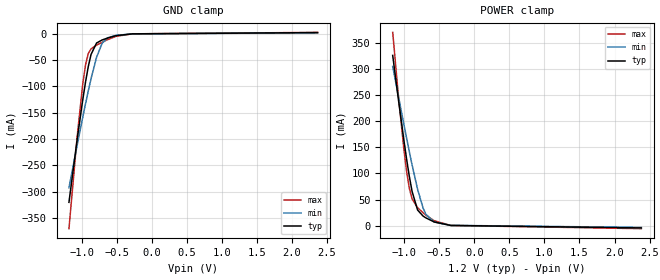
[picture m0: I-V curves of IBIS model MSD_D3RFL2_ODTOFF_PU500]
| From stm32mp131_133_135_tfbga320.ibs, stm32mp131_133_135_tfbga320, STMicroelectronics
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[Model] MSD_D3RFL2_ODTOFF_PU500
Model_type   Input
C_comp 2.422pF   2.336pF   2.548pF
Vinh = 820.000mV
Vinl = 380.000mV
[Temperature Range]   25.000   125.000   -40.000
[Voltage Range]   1.200V   1.140V   1.300V
[GND Clamp Reference]   0.00V   0.00V   0.00V
[POWER Clamp Reference]   1.200V   1.140V   1.300V
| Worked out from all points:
|   GND clamp passes 1 mA (typ) near -0.40 V on its own axis
|   POWER clamp passes 1 mA (typ) near -0.41 V on its own axis
[GND Clamp]
-1.182V   -320.1mA   -292.5mA   -370.1mA
-1.064V   -199.7mA   -211mA     -194.1mA
-984.9mV  -125.1mA   -158.4mA   -94.98mA
-945.5mV  -91.41mA   -132.9mA   -58.96mA
-906.1mV  -61.99mA   -108.4mA   -37.38mA
-866.7mV  -39.06mA   -85.02mA   -28.53mA
-787.9mV  -17.41mA   -44.41mA   -21.52mA
-709.1mV  -11.69mA   -17.89mA   -16.07mA
-630.3mV  -8.01mA    -7.607mA   -11.08mA
-512.1mV  -3.579mA   -3.019mA   -4.808mA
-275.8mV  -44.39uA   -86.79uA   -32.99uA
2.364V    2.29mA     1.932mA    2.7mA
[Power Clamp]
-1.164V   326.6mA    305.4mA    370.8mA
-1.085V   244.3mA    249.9mA    252.7mA
-1.006V   165.2mA    195.2mA    148.2mA
-966.7mV  128.3mA    168.4mA    104.9mA
-927.3mV  94.61mA    142.1mA    71.58mA
-887.9mV  65.7mA     116.6mA    51.16mA
-809.1mV  29.84mA    69.64mA    34.36mA
-730.3mV  18.11mA    33.43mA    24.39mA
-690.9mV  14.74mA    21.65mA    20.04mA
-572.7mV  6.901mA    6.803mA    9.252mA
-336.4mV  197.9uA    376.1uA    220.7uA
2.382V    -4.583mA   -3.635mA   -5.957mA
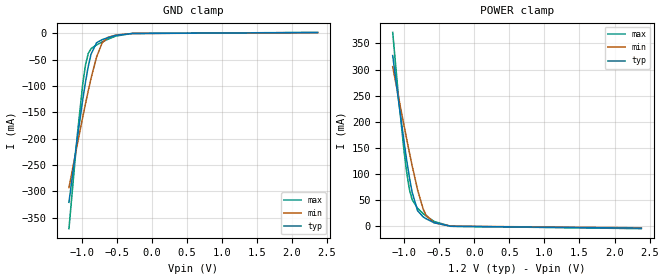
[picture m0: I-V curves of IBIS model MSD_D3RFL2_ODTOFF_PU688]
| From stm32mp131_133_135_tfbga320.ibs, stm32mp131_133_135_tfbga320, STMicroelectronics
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[Model] MSD_D3RFL2_ODTOFF_PU688
Model_type   Input
C_comp 2.464pF   2.376pF   2.591pF
Vinh = 820.000mV
Vinl = 380.000mV
[Temperature Range]   25.000   125.000   -40.000
[Voltage Range]   1.200V   1.140V   1.300V
[GND Clamp Reference]   0.00V   0.00V   0.00V
[POWER Clamp Reference]   1.200V   1.140V   1.300V
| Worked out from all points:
|   GND clamp passes 1 mA (typ) near -0.40 V on its own axis
|   POWER clamp passes 1 mA (typ) near -0.41 V on its own axis
[GND Clamp]
-1.182V   -320.6mA   -292.7mA   -370.6mA
-1.064V   -200mA     -211.3mA   -194.5mA
-984.9mV  -125.3mA   -158.6mA   -95.34mA
-945.5mV  -91.67mA   -133.2mA   -59.29mA
-906.1mV  -62.23mA   -108.5mA   -37.69mA
-866.7mV  -39.29mA   -85.21mA   -28.81mA
-787.9mV  -17.6mA    -44.56mA   -21.75mA
-709.1mV  -11.84mA   -18.01mA   -16.25mA
-630.3mV  -8.125mA   -7.699mA   -11.21mA
-512.1mV  -3.641mA   -3.071mA   -4.885mA
-275.8mV  -49.19uA   -90.39uA   -36.39uA
2.364V    1.665mA    1.406mA    1.963mA
[Power Clamp]
-1.164V   326.9mA    305.7mA    371.2mA
-1.085V   244.5mA    250.2mA    253.1mA
-1.006V   165.5mA    195.5mA    148.5mA
-966.7mV  128.6mA    168.6mA    105.2mA
-927.3mV  94.85mA    142.3mA    71.88mA
-887.9mV  65.93mA    116.8mA    51.44mA
-809.1mV  30.01mA    69.78mA    34.6mA
-730.3mV  18.26mA    33.56mA    24.58mA
-690.9mV  14.86mA    21.76mA    20.2mA
-572.7mV  6.977mA    6.872mA    9.351mA
-336.4mV  203.2uA    384.3uA    227uA
2.382V    -3.33mA    -2.644mA   -4.33mA
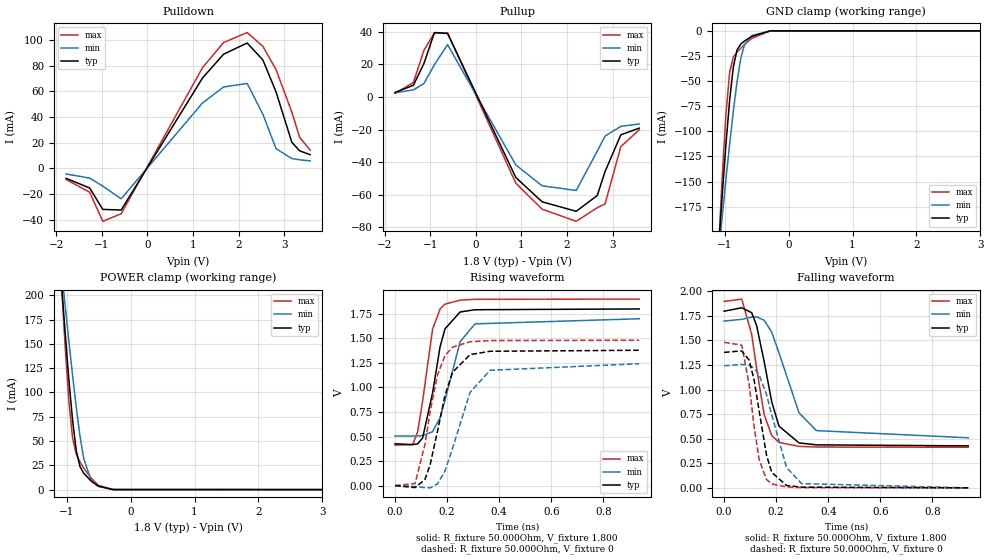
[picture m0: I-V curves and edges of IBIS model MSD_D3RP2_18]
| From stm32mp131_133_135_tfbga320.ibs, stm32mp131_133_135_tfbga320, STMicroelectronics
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[Model] MSD_D3RP2_18
Model_type   I/O
C_comp 2.221pF   2.142pF   2.337pF
Vinh = 1.150V
Vinl = 650.000mV
Vmeas = 900.000mV
Vref = 900.000mV
[Model Spec]
Vinh   1.150V   1.100V   1.200V
Vinl   650.000mV   600.000mV   700.000mV
Vmeas   900.000mV   850.000mV   950.000mV
Vref   900.000mV   850.000mV   950.000mV
[Temperature Range]   25.000   125.000   -40.000
[Voltage Range]   1.800V   1.700V   1.900V
[GND Clamp Reference]   0.00V   0.00V   0.00V
[Pulldown Reference]   0.00V   0.00V   0.00V
[POWER Clamp Reference]   1.800V   1.700V   1.900V
[Pullup Reference]   1.800V   1.700V   1.900V
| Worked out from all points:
|   slope of the pulldown table from 0 to 0.27 V, typ, clamps not added: 15.3 ohm
|   slope of the pullup table from 0 to 0.27 V, typ, clamps not added: 14.6 ohm
|   GND clamp passes 1 mA (typ) near -0.41 V on its own axis
|   POWER clamp passes 1 mA (typ) near -0.41 V on its own axis
|   rising waveform, R_fixture 50.000Ohm, V_fixture 1.800: 20-80 % time 54.6ps typ, 69.9ps min, 47.3ps max; typ from 0.426 V to 1.8 V
|   rising waveform, R_fixture 50.000Ohm, V_fixture 0: 20-80 % time 71.9ps typ, 90.7ps min, 63.2ps max; typ from 0.001 V to 1.38 V
|   falling waveform, R_fixture 50.000Ohm, V_fixture 1.800: 20-80 % time 64.1ps typ, 91ps min, 54.1ps max; typ from 1.8 V to 0.427 V
|   falling waveform, R_fixture 50.000Ohm, V_fixture 0: 20-80 % time 53.7ps typ, 75.2ps min, 44.9ps max; typ from 1.38 V to 0 V
[GND Clamp]
-1.785V   -899.6mA   -687.8mA   -1.207A
-1.094V   -214.3mA   -220.6mA   -214.7mA
-1.036V   -161.5mA   -183.4mA   -143mA
-978.8mV  -112mA     -147.1mA   -81.84mA
-921.2mV  -68.38mA   -112.2mA   -40.88mA
-863.6mV  -35.68mA   -79.52mA   -26.12mA
-806.1mV  -18.97mA   -50.56mA   -21.22mA
-748.5mV  -13.2mA    -27.77mA   -17.43mA
-690.9mV  -10.2mA    -13.79mA   -13.86mA
-575.8mV  -5.517mA   -4.735mA   -7.461mA
-287.9mV  -70.53uA   -119uA     -55.71uA
3.57V     33.93nA    572.8nA    3.714nA
[Power Clamp]
-1.77V    876.4mA    686.4mA    1.147A
-1.079V   211mA      225.3mA    210.2mA
-1.021V   159.9mA    188.4mA    145.5mA
-963.6mV  112.3mA    152.2mA    90.31mA
-906.1mV  70.8mA     117.2mA    52.68mA
-848.5mV  39.88mA    84.39mA    36.1mA
-790.9mV  23.74mA    55.21mA    28.44mA
-733.3mV  16.95mA    32.12mA    22.28mA
-618.2mV  8.937mA    9.714mA    11.91mA
-503mV    3.408mA    3.506mA    4.439mA
-272.7mV  29.94uA    100.2uA    29.64uA
3.585V    -51.59nA   -929.3nA   -5.524nA
[Pulldown]
-1.785V   -7.8mA     -4.4mA     -8.7mA
-1.267V   -15.3mA    -7.6mA     -18.6mA
-978.8mV  -32mA      -13.9mA    -41.26mA
-575.8mV  -32.47mA   -23.75mA   -35.38mA
1.209V    70.35mA    50.91mA    78.4mA
1.67V     88.83mA    63.31mA    97.93mA
2.188V    97.57mA    66.1mA     105.7mA
2.533V    84.35mA    42.07mA    94.94mA
2.821V    59.5mA     15.3mA     76.86mA
3.167V    20.3mA     7.6mA      43.8mA
3.339V    13.6mA     6.6mA      24.1mA
3.57V     10.6mA     5.8mA      14.1mA
[Pullup]
-1.77V    2.8mA      2.547mA    2.179mA
-1.367V   7.2mA      4.368mA    8.916mA
-1.136V   20.6mA     8.305mA    28.64mA
-906.1mV  39.5mA     19.85mA    39.24mA
-618.2mV  38.95mA    32.12mA    39.29mA
878.8mV   -49.36mA   -41.64mA   -52.87mA
1.455V    -64.24mA   -54.44mA   -68.74mA
2.203V    -70.07mA   -57.29mA   -76.2mA
2.664V    -60.43mA   -33.26mA   -67.89mA
2.836V    -45.7mA    -23.95mA   -65.53mA
3.182V    -23.2mA    -18.01mA   -30.43mA
3.585V    -19.1mA    -16.53mA   -20.12mA
[Ramp]
R_load=50.000Ohm
dV/dt_r   825.510mV/64.000ps  729.839mV/81.500ps  890.490mV/55.500ps
dV/dt_f   825.510mV/60.000ps  729.839mV/83.000ps  890.490mV/50.500ps
[Rising waveform]
R_fixture=50.000Ohm
V_fixture=1.800
V_fixture_min=1.700
V_fixture_max=1.900
0s        426.3mV    506.6mV    412.7mV
68ps      418mV      505.2mV    417.9mV
87ps      426.2mV    506.5mV    550mV
106ps     487.1mV    510.3mV    862.9mV
144ps     941.5mV    550.1mV    1.591V
173ps     1.415V     689.7mV    1.799V
192ps     1.598V     870.4mV    1.849V
250ps     1.769V     1.466V     1.89V
307ps     1.792V     1.648V     1.898V
938ps     1.8V       1.7V       1.9V
[Rising waveform]
R_fixture=50.000Ohm
V_fixture=0
0s        1.099mV    921.6uV    1.012mV
77ps      -20.18mV   -8.249mV   21.42mV
115ps     63.59mV    -20.85mV   421.8mV
135ps     214.8mV    -22.61mV   755.6mV
163ps     553.3mV    18.05mV    1.127V
192ps     922mV      150.2mV    1.325V
221ps     1.155V     381.4mV    1.411V
288ps     1.334V     949.2mV    1.466V
365ps     1.369V     1.175V     1.478V
938ps     1.379V     1.242V     1.481V
[Falling waveform]
R_fixture=50.000Ohm
V_fixture=1.800
V_fixture_min=1.700
V_fixture_max=1.900
0s        1.798V     1.698V     1.898V
68ps      1.833V     1.715V     1.921V
106ps     1.783V     1.738V     1.563V
125ps     1.652V     1.741V     1.219V
154ps     1.286V     1.706V     745.2mV
183ps     876.6mV    1.585V     532.7mV
211ps     627.9mV    1.374V     462.1mV
288ps     457.4mV    763mV      422.4mV
355ps     437.7mV    582.7mV    415.8mV
938ps     427.3mV    509.6mV    413mV
[Falling waveform]
R_fixture=50.000Ohm
V_fixture=0
0s        1.379V     1.243V     1.481V
68ps      1.394V     1.256V     1.453V
96ps      1.302V     1.247V     1.058V
115ps     1.103V     1.219V     631.3mV
135ps     779.3mV    1.149V     284.9mV
163ps     333.7mV    950.2mV    85.26mV
183ps     158.1mV    743.5mV    40.43mV
240ps     24mV       206.1mV    8.904mV
298ps     7.38mV     42.98mV    2.647mV
938ps     2.799uV    13.9uV     745nV
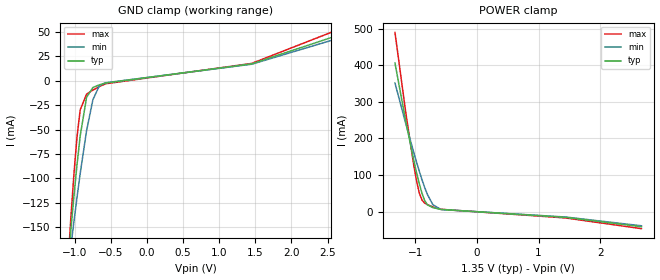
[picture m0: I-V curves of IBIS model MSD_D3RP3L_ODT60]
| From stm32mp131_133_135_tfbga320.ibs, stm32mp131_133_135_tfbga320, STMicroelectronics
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[Model] MSD_D3RP3L_ODT60
Model_type   Input
C_comp 2.193pF   2.146pF   2.256pF
Vinh = 810.000mV
Vinl = 540.000mV
[Receiver Thresholds]
Vth   =  0.675V
Vth_min  =  0.6615V
Vth_max  =  0.6885V
Vinh_ac  =  0.160V
Vinh_dc  =  0.090V
Vinl_ac  = -0.160V
Vinl_dc  = -0.090V
Tslew_ac =  5.000ns |Not specified, so set to high value
[Temperature Range]   25.000   125.000   -40.000
[Voltage Range]   1.350V   1.283V   1.450V
[GND Clamp Reference]   0.00V   0.00V   0.00V
[POWER Clamp Reference]   1.350V   1.283V   1.450V
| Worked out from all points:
|   GND clamp passes 1 mA (typ) near -0.48 V on its own axis
|   POWER clamp passes 1 mA (typ) near -0.20 V on its own axis
[GND Clamp]
-1.318V   -398.7mA   -338.7mA   -488.7mA
-1.098V   -193.5mA   -198.6mA   -195.1mA
-1.055V   -155.3mA   -171.5mA   -143.7mA
-1.011V   -119.2mA   -145.1mA   -97.09mA
-966.7mV  -85.96mA   -119.4mA   -57.43mA
-922.7mV  -56.59mA   -95mA      -29.75mA
-834.9mV  -17.03mA   -51.28mA   -13.73mA
-747mV    -6.911mA   -19.39mA   -9.53mA
-659.1mV  -4.206mA   -5.263mA   -6.01mA
-571.2mV  -2.321mA   -2.075mA   -3.11mA
1.45V     17.25mA    16.91mA    17.76mA
2.68V     47.38mA    44.14mA    53.32mA
[Power Clamp]
-1.33V    406mA      351.2mA    489.7mA
-1.155V   246.6mA    240.3mA    270.3mA
-1.023V   137.9mA    160mA      124.2mA
-978.8mV  105.4mA    134.4mA    82.74mA
-934.9mV  75.51mA    109.8mA    50.15mA
-890.9mV  49.42mA    86.58mA    31.14mA
-847mV    29.66mA    65.21mA    22.83mA
-803mV    18.32mA    46.22mA    18.64mA
-715.1mV  10.66mA    18.63mA    12.6mA
-583.3mV  5.756mA    5.379mA    5.996mA
1.438V    -15.88mA   -15.05mA   -17.61mA
2.668V    -41.58mA   -39.01mA   -46.87mA
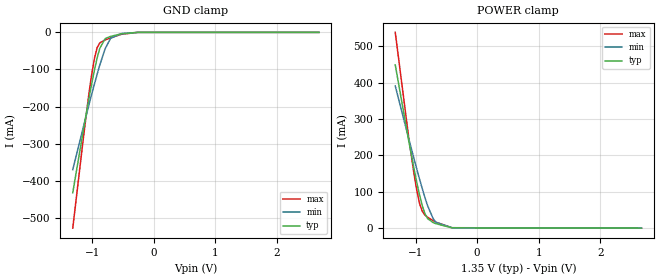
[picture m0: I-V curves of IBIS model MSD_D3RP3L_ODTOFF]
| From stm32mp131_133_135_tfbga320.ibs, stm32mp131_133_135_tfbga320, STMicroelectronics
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[Model] MSD_D3RP3L_ODTOFF
Model_type   Input
C_comp 2.239pF   2.158pF   2.357pF
Vinh = 810.000mV
Vinl = 540.000mV
[Model Spec]
Vinh   810.000mV   777.000mV   860.000mV
Vinl   540.000mV   507.000mV   590.000mV
[Receiver Thresholds]
Vth   =  0.675V
Vth_min  =  0.6615V
Vth_max  =  0.6885V
Vinh_ac  =  0.160V
Vinh_dc  =  0.090V
Vinl_ac  = -0.160V
Vinl_dc  = -0.090V
Tslew_ac =  5.000ns |Not specified, so set to high value
[Temperature Range]   25.000   125.000   -40.000
[Voltage Range]   1.350V   1.283V   1.450V
[GND Clamp Reference]   0.00V   0.00V   0.00V
[POWER Clamp Reference]   1.350V   1.283V   1.450V
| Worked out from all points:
|   GND clamp passes 1 mA (typ) near -0.41 V on its own axis
|   POWER clamp passes 1 mA (typ) near -0.41 V on its own axis
[GND Clamp]
-1.318V   -432mA     -369.8mA   -527.4mA
-1.142V   -260.2mA   -252.4mA   -279.5mA
-1.055V   -177.9mA   -195mA     -164.8mA
-1.011V   -138.8mA   -167mA     -113.9mA
-966.7mV  -102.2mA   -139.6mA   -71.13mA
-922.7mV  -69.41mA   -113.1mA   -41.59mA
-878.8mV  -42.86mA   -87.83mA   -28.26mA
-790.9mV  -16.84mA   -43.84mA   -20.19mA
-703mV    -10.77mA   -15.97mA   -14.59mA
-527.3mV  -3.881mA   -3.286mA   -5.179mA
-263.6mV  -34.33uA   -68.9uA    -22.73uA
2.68V     23.23nA    650.7nA    2.893nA
[Power Clamp]
-1.33V    448.9mA    390.9mA    538.4mA
-1.111V   240.1mA    246mA      248.4mA
-1.023V   161.2mA    189.4mA    146.7mA
-978.8mV  124.3mA    161.6mA    102.6mA
-934.9mV  90.54mA    134.5mA    67.58mA
-890.9mV  61.4mA     108.3mA    46.23mA
-847mV    39.26mA    83.52mA    35.86mA
-803mV    26.02mA    60.85mA    29.84mA
-715.1mV  15.45mA    26.3mA     20.45mA
-671.2mV  12.26mA    16.27mA    16.34mA
-407.6mV  879.7uA    1.157mA    1.067mA
2.668V    -39.91nA   -766.7nA   -3.593nA
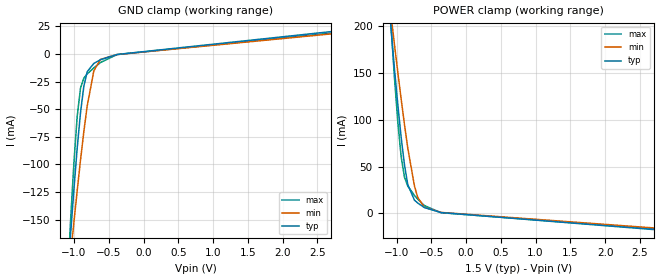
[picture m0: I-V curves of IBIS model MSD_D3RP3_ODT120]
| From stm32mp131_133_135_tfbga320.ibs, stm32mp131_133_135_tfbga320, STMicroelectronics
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[Model] MSD_D3RP3_ODT120
Model_type   Input
C_comp 2.174pF   2.132pF   2.272pF
Vinh = 925.000mV
Vinl = 575.000mV
[Temperature Range]   25.000   125.000   -40.000
[Voltage Range]   1.500V   1.425V   1.575V
[GND Clamp Reference]   0.00V   0.00V   0.00V
[POWER Clamp Reference]   1.500V   1.425V   1.575V
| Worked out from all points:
|   GND clamp passes 1 mA (typ) near -0.44 V on its own axis
|   POWER clamp passes 1 mA (typ) near -0.39 V on its own axis
[GND Clamp]
-1.48V    -576.5mA   -464.8mA   -745.1mA
-1.098V   -206.6mA   -212.6mA   -209.7mA
-1.05V    -163.5mA   -182.2mA   -150.9mA
-1.002V   -122.5mA   -152.4mA   -98.52mA
-954.6mV  -85.01mA   -123.6mA   -56.28mA
-906.8mV  -52.93mA   -95.94mA   -30.71mA
-859.1mV  -29.1mA    -70.16mA   -21.67mA
-811.4mV  -16.05mA   -47.2mA    -18.04mA
-715.9mV  -8.501mA   -15.32mA   -12.54mA
-620.5mV  -5.103mA   -4.829mA   -7.678mA
-381.8mV  -363uA     -432.2uA   -435.6uA
2.959V    22.12mA    19.88mA    20.66mA
[Power Clamp]
-1.459V   552.7mA    458.5mA    695.8mA
-1.077V   195.4mA    210.4mA    197.8mA
-1.03V    154.4mA    180.5mA    145.1mA
-981.8mV  116.2mA    151mA      97.78mA
-934.1mV  81.52mA    122.5mA    60.73mA
-886.4mV  52.06mA    95.22mA    38.8mA
-838.6mV  30.68mA    69.86mA    29.11mA
-743.2mV  14.19mA    29.52mA    19.22mA
-695.5mV  10.99mA    17.13mA    15.16mA
-600mV    6.16mA     6.417mA    8.322mA
-361.4mV  818.6uA    995.7uA    665.5uA
2.98V     -19.07mA   -17.16mA   -18.22mA
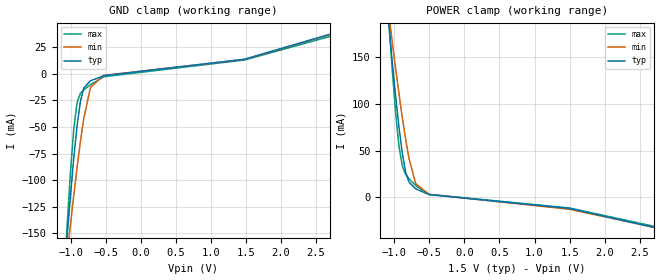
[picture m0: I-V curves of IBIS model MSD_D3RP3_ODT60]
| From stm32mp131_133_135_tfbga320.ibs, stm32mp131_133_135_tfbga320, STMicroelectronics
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[Model] MSD_D3RP3_ODT60
Model_type   Input
C_comp 2.163pF   2.120pF   2.219pF
Vinh = 925.000mV
Vinl = 575.000mV
[Temperature Range]   25.000   125.000   -40.000
[Voltage Range]   1.500V   1.425V   1.575V
[GND Clamp Reference]   0.00V   0.00V   0.00V
[POWER Clamp Reference]   1.500V   1.425V   1.575V
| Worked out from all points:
|   GND clamp passes 1 mA (typ) near -0.48 V on its own axis
|   POWER clamp passes 1 mA (typ) near -0.30 V on its own axis
[GND Clamp]
-1.48V    -561.6mA   -448.7mA   -730mA
-1.098V   -196.9mA   -201.1mA   -201mA
-1.05V    -154.9mA   -171.5mA   -144mA
-1.002V   -115.4mA   -142.5mA   -93.08mA
-954.6mV  -79.5mA    -114.6mA   -51.89mA
-906.8mV  -48.76mA   -88.09mA   -26.87mA
-859.1mV  -25.81mA   -63.65mA   -18.23mA
-811.4mV  -13.3mA    -42.11mA   -14.94mA
-715.9mV  -6.46mA    -12.6mA    -10.12mA
-525mV    -1.674mA   -1.332mA   -2.643mA
1.48V     13.83mA    13.63mA    13.12mA
2.959V    42.38mA    42.05mA    40.02mA
[Power Clamp]
-1.459V   533.7mA    438.4mA    677.5mA
-1.077V   184mA      195.6mA    189mA
-1.03V    145.2mA    166.6mA    137.4mA
-981.8mV  108.8mA    138.3mA    91.01mA
-934.1mV  75.72mA    111.2mA    54.77mA
-886.4mV  47.37mA    85.55mA    33.65mA
-838.6mV  26.85mA    62.12mA    24.69mA
-790.9mV  16.22mA    41.78mA    19.93mA
-695.5mV  9.036mA    14.61mA    12.56mA
-504.6mV  2.817mA    3.027mA    3.08mA
1.5V      -11.98mA   -12.86mA   -11.59mA
2.98V     -36.97mA   -36.78mA   -35.63mA
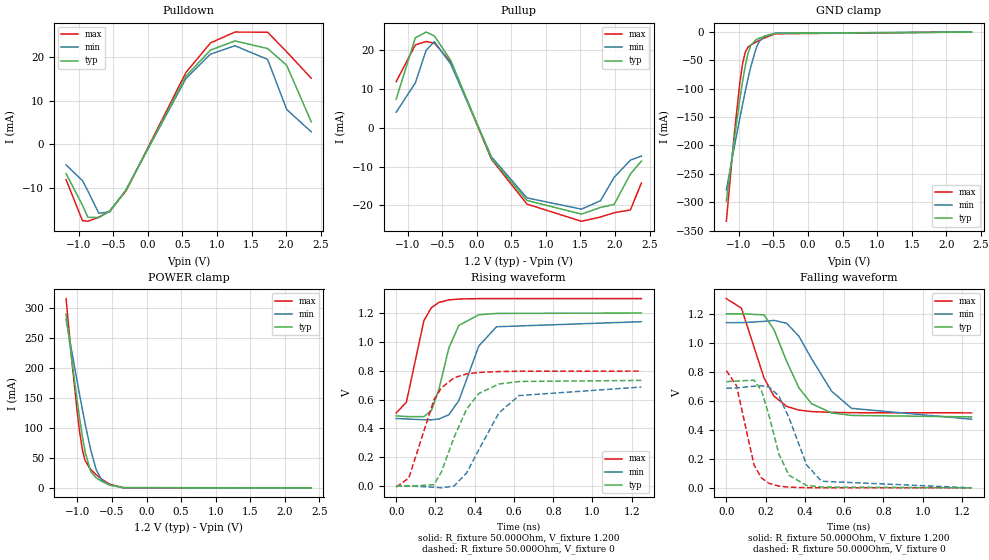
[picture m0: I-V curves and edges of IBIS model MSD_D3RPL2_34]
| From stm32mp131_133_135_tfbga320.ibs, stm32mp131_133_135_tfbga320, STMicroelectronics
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[Model] MSD_D3RPL2_34
Model_type   I/O
C_comp 2.247pF   2.165pF   2.365pF
Vinh = 820.000mV
Vinl = 380.000mV
Vmeas = 600.000mV
Vref = 600.000mV
[Model Spec]
Vinh   820.000mV   790.000mV   870.000mV
Vinl   380.000mV   350.000mV   430.000mV
Vmeas   600.000mV   570.000mV   650.000mV
Vref   600.000mV   570.000mV   650.000mV
[Temperature Range]   25.000   125.000   -40.000
[Voltage Range]   1.200V   1.140V   1.300V
[GND Clamp Reference]   0.00V   0.00V   0.00V
[Pulldown Reference]   0.00V   0.00V   0.00V
[POWER Clamp Reference]   1.200V   1.140V   1.300V
[Pullup Reference]   1.200V   1.140V   1.300V
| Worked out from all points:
|   slope of the pulldown table from 0 to 0.18 V, typ, clamps not added: 31.3 ohm
|   slope of the pullup table from 0 to 0.18 V, typ, clamps not added: 26.5 ohm
|   GND clamp passes 1 mA (typ) near -0.41 V on its own axis
|   POWER clamp passes 1 mA (typ) near -0.41 V on its own axis
|   rising waveform, R_fixture 50.000Ohm, V_fixture 1.200: 20-80 % time 85.3ps typ, 112ps min, 72.9ps max; typ from 0.487 V to 1.2 V
|   rising waveform, R_fixture 50.000Ohm, V_fixture 0: 20-80 % time 138ps typ, 170ps min, 119ps max; typ from 0.001 V to 0.733 V
|   falling waveform, R_fixture 50.000Ohm, V_fixture 1.200: 20-80 % time 145ps typ, 189ps min, 121ps max; typ from 1.2 V to 0.489 V
|   falling waveform, R_fixture 50.000Ohm, V_fixture 0: 20-80 % time 92.5ps typ, 118ps min, 78.6ps max; typ from 0.732 V to 0 V
[GND Clamp]
-1.182V   -298.1mA   -278.5mA   -333.7mA
-1.064V   -186.2mA   -200.9mA   -176mA
-984.9mV  -117mA     -150.8mA   -87.54mA
-945.5mV  -85.76mA   -126.7mA   -54.85mA
-906.1mV  -58.45mA   -103.3mA   -34.84mA
-866.7mV  -37.02mA   -81.16mA   -26.5mA
-827.3mV  -23.29mA   -60.66mA   -22.76mA
-748.5mV  -13.2mA    -27.78mA   -17.43mA
-709.1mV  -11.06mA   -17.2mA    -14.96mA
-630.3mV  -7.603mA   -7.31mA    -10.35mA
-472.7mV  -2.342mA   -2.056mA   -3.036mA
2.364V    24.05nA    406.6nA    2.608nA
[Power Clamp]
-1.164V   289.6mA    280.7mA    315.2mA
-1.085V   216.5mA    229.3mA    217.2mA
-1.006V   146.9mA    178.8mA    129.3mA
-966.7mV  114.6mA    154.1mA    91.94mA
-927.3mV  85.12mA    129.9mA    62.94mA
-887.9mV  59.62mA    106.5mA    45.07mA
-809.1mV  27.34mA    63.75mA    30.55mA
-730.3mV  16.69mA    30.8mA     21.95mA
-651.5mV  10.97mA    13.15mA    14.62mA
-533.3mV  4.62mA     4.579mA    6.036mA
-336.4mV  182.5uA    350.8uA    204.6uA
2.382V    -20.25nA   -432nA     -2.133nA
[Pulldown]
-1.182V   -6.7mA     -4.7mA     -8.1mA
-945.5mV  -13.93mA   -8.3mA     -17.48mA
-866.7mV  -16.72mA   -10.68mA   -17.64mA
-709.1mV  -16.8mA    -15.79mA   -16.69mA
-551.5mV  -15.32mA   -15.49mA   -15.28mA
-315.1mV  -10.49mA   -10.41mA   -10.68mA
551.5mV   15.66mA    15.14mA    16.51mA
906.1mV   21.65mA    20.73mA    23.3mA
1.261V    23.76mA    22.65mA    25.8mA
1.733V    22.01mA    19.52mA    25.76mA
2.009V    18.16mA    8.02mA     21.26mA
2.364V    5.2mA      2.9mA      15.2mA
[Pullup]
-1.164V   7.4mA      4.009mA    11.91mA
-887.9mV  23.18mA    11.56mA    21.36mA
-730.3mV  24.68mA    20.03mA    22.25mA
-612.1mV  23.67mA    22.2mA     21.82mA
-375.8mV  17.39mA    16.44mA    16.97mA
215.2mV   -7.943mA   -7.527mA   -8.165mA
727.3mV   -18.74mA   -18.08mA   -19.68mA
1.515V    -22.27mA   -20.98mA   -24.11mA
1.791V    -20.54mA   -18.81mA   -23.02mA
1.988V    -19.77mA   -12.78mA   -21.9mA
2.224V    -11.9mA    -8.343mA   -21.19mA
2.382V    -8.6mA     -7.295mA   -14.24mA
[Ramp]
R_load=50.000Ohm
dV/dt_r   433.140mV/113.000ps  406.679mV/141.000ps  474.120mV/96.000ps
dV/dt_f   433.140mV/119.500ps  406.649mV/155.500ps  474.120mV/100.000ps
[Rising waveform]
R_fixture=50.000Ohm
V_fixture=1.200
V_fixture_min=1.140
V_fixture_max=1.300
0s        487.2mV    468.8mV    507.3mV
52ps      482.5mV    465.8mV    582.3mV
141ps     481.7mV    460.2mV    1.147V
179ps     523.4mV    459.9mV    1.237V
217ps     668.1mV    465.4mV    1.273V
268ps     957mV      494.7mV    1.291V
319ps     1.114V     592.7mV    1.297V
421ps     1.188V     971.9mV    1.3V
511ps     1.197V     1.105V     1.3V
1.249ns   1.2V       1.14V      1.3V
[Rising waveform]
R_fixture=50.000Ohm
V_fixture=0
0s        938.7uV    901.7uV    -6.584mV
64ps      -88.12uV   864.9uV    55.86mV
192ps     10.33mV    -7.321mV   597.7mV
230ps     97.42mV    -11.6mV    680.8mV
294ps     335.7mV    -24.7uV    750.8mV
358ps     532.5mV    89.93mV    777.8mV
421ps     642.2mV    253mV      788.1mV
523ps     708.2mV    507.5mV    794.3mV
626ps     725.4mV    627.9mV    796.6mV
1.249ns   733mV      687.1mV    797.4mV
[Falling waveform]
R_fixture=50.000Ohm
V_fixture=1.200
V_fixture_min=1.140
V_fixture_max=1.300
0s        1.2V       1.139V     1.305V
77ps      1.2V       1.139V     1.239V
192ps     1.193V     1.148V     757.8mV
243ps     1.09V      1.155V     632.1mV
307ps     873mV      1.135V     561.8mV
370ps     689.1mV    1.045V     536.1mV
434ps     580.4mV    890.9mV    526mV
536ps     517.2mV    667mV      520.4mV
638ps     499.4mV    548.2mV    518.2mV
1.249ns   489.2mV    473.2mV    517mV
[Falling waveform]
R_fixture=50.000Ohm
V_fixture=0
0s        732.3mV    686.7mV    808.4mV
52ps      736.7mV    689mV      703.2mV
141ps     742.3mV    701mV      158.2mV
179ps     670.7mV    704.2mV    68.56mV
217ps     501.3mV    695.4mV    30.97mV
268ps     232.1mV    632.8mV    11.73mV
319ps     87.09mV    483.9mV    4.728mV
409ps     16.41mV    158.4mV    961.7uV
485ps     5.285mV    45.43mV    231.7uV
1.249ns   0V         18.63uV    0V
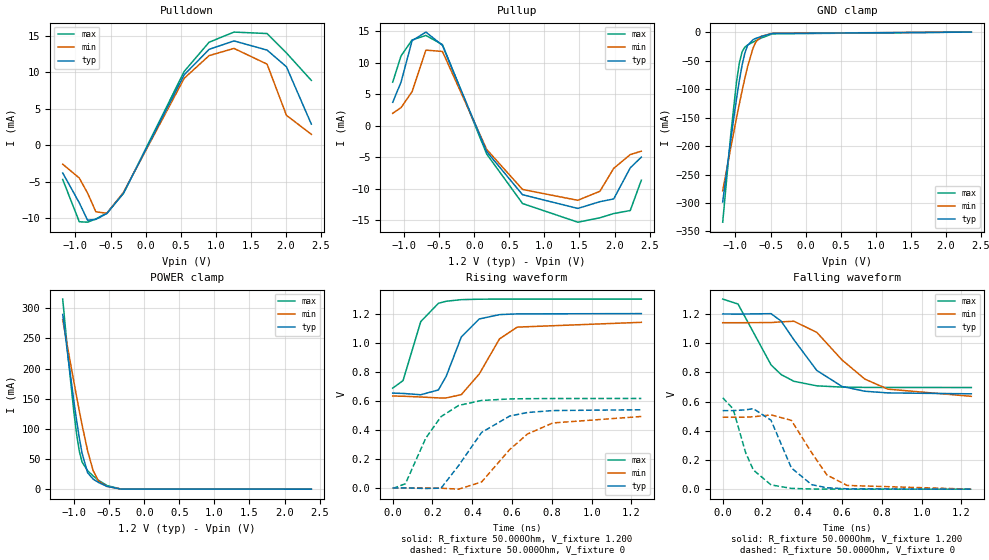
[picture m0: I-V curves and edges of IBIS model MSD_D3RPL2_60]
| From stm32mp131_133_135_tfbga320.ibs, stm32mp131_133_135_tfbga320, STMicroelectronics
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[Model] MSD_D3RPL2_60
Model_type   I/O
C_comp 2.247pF   2.165pF   2.365pF
Vinh = 820.000mV
Vinl = 380.000mV
Vmeas = 600.000mV
Vref = 600.000mV
[Model Spec]
Vinh   820.000mV   790.000mV   870.000mV
Vinl   380.000mV   350.000mV   430.000mV
Vmeas   600.000mV   570.000mV   650.000mV
Vref   600.000mV   570.000mV   650.000mV
[Temperature Range]   25.000   125.000   -40.000
[Voltage Range]   1.200V   1.140V   1.300V
[GND Clamp Reference]   0.00V   0.00V   0.00V
[Pulldown Reference]   0.00V   0.00V   0.00V
[POWER Clamp Reference]   1.200V   1.140V   1.300V
[Pullup Reference]   1.200V   1.140V   1.300V
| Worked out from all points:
|   slope of the pulldown table from 0 to 0.18 V, typ, clamps not added: 50.1 ohm
|   slope of the pullup table from 0 to 0.18 V, typ, clamps not added: 42.9 ohm
|   GND clamp passes 1 mA (typ) near -0.41 V on its own axis
|   POWER clamp passes 1 mA (typ) near -0.41 V on its own axis
|   rising waveform, R_fixture 50.000Ohm, V_fixture 1.200: 20-80 % time 102ps typ, 132ps min, 84.6ps max; typ from 0.653 V to 1.2 V
|   rising waveform, R_fixture 50.000Ohm, V_fixture 0: 20-80 % time 177ps typ, 217ps min, 147ps max; typ from 0 V to 0.538 V
|   falling waveform, R_fixture 50.000Ohm, V_fixture 1.200: 20-80 % time 191ps typ, 239ps min, 154ps max; typ from 1.2 V to 0.653 V
|   falling waveform, R_fixture 50.000Ohm, V_fixture 0: 20-80 % time 109ps typ, 133ps min, 93.3ps max; typ from 0.538 V to 0 V
[GND Clamp]
-1.182V   -298.1mA   -278.5mA   -333.7mA
-1.064V   -186.2mA   -200.9mA   -176mA
-984.9mV  -117mA     -150.8mA   -87.54mA
-945.5mV  -85.76mA   -126.7mA   -54.85mA
-906.1mV  -58.45mA   -103.3mA   -34.84mA
-866.7mV  -37.02mA   -81.16mA   -26.5mA
-827.3mV  -23.29mA   -60.66mA   -22.76mA
-748.5mV  -13.2mA    -27.78mA   -17.43mA
-709.1mV  -11.06mA   -17.2mA    -14.96mA
-630.3mV  -7.603mA   -7.31mA    -10.35mA
-472.7mV  -2.342mA   -2.056mA   -3.036mA
2.364V    24.05nA    406.6nA    2.608nA
[Power Clamp]
-1.164V   289.6mA    280.7mA    315.2mA
-1.085V   216.5mA    229.3mA    217.2mA
-1.006V   146.9mA    178.8mA    129.3mA
-966.7mV  114.6mA    154.1mA    91.94mA
-927.3mV  85.12mA    129.9mA    62.94mA
-887.9mV  59.62mA    106.5mA    45.07mA
-809.1mV  27.34mA    63.75mA    30.55mA
-730.3mV  16.69mA    30.8mA     21.95mA
-651.5mV  10.97mA    13.15mA    14.62mA
-533.3mV  4.62mA     4.579mA    6.036mA
-336.4mV  182.5uA    350.8uA    204.6uA
2.382V    -20.25nA   -432nA     -2.133nA
[Pulldown]
-1.182V   -3.8mA     -2.6mA     -4.7mA
-945.5mV  -7.9mA     -4.5mA     -10.5mA
-827.3mV  -10.29mA   -6.57mA    -10.56mA
-709.1mV  -10.17mA   -9.13mA    -10.12mA
-551.5mV  -9.369mA   -9.335mA   -9.299mA
-315.1mV  -6.566mA   -6.464mA   -6.607mA
551.5mV   9.678mA    9.197mA    10.14mA
906.1mV   13.16mA    12.3mA     14.14mA
1.261V    14.32mA    13.29mA    15.53mA
1.733V    13.06mA    11.13mA    15.33mA
2.009V    10.77mA    4.11mA     12.67mA
2.364V    2.9mA      1.5mA      8.9mA
[Pullup]
-1.164V   3.7mA      1.952mA    6.892mA
-1.045V   6.9mA      2.857mA    11.06mA
-887.9mV  13.46mA    5.381mA    13.58mA
-690.9mV  14.83mA    11.97mA    14.3mA
-454.5mV  12.73mA    11.76mA    12.84mA
175.8mV   -4.107mA   -3.771mA   -4.491mA
687.9mV   -10.95mA   -10.12mA   -12.35mA
1.476V    -13.13mA   -11.84mA   -15.31mA
1.791V    -12.06mA   -10.41mA   -14.61mA
1.988V    -11.62mA   -6.779mA   -13.94mA
2.224V    -6.7mA     -4.595mA   -13.46mA
2.382V    -5mA       -4.048mA   -8.654mA
[Ramp]
R_load=50.000Ohm
dV/dt_r   325.710mV/140.000ps  300.149mV/176.000ps  366.000mV/116.500ps
dV/dt_f   325.710mV/151.000ps  300.090mV/188.500ps  366.000mV/123.500ps
[Rising waveform]
R_fixture=50.000Ohm
V_fixture=1.200
V_fixture_min=1.140
V_fixture_max=1.300
0s        652.8mV    632.8mV    686.9mV
52ps      650.7mV    631.4mV    739.1mV
141ps     641.5mV    626.2mV    1.145V
230ps     674.9mV    619.9mV    1.271V
269ps     769.2mV    619.7mV    1.285V
345ps     1.039V     642.5mV    1.296V
435ps     1.163V     784.3mV    1.299V
537ps     1.193V     1.026V     1.3V
626ps     1.198V     1.107V     1.3V
1.25ns    1.2V       1.14V      1.3V
[Rising waveform]
R_fixture=50.000Ohm
V_fixture=0
0s        136.9uV    117.1uV    -3.568mV
64ps      686.7uV    468.9uV    29.58mV
166ps     -3.593mV   651.3uV    342.3mV
243ps     -1.105mV   -1.476mV   491.2mV
332ps     155.2mV    -8.095mV   568.3mV
447ps     382.5mV    41.54mV    602.2mV
588ps     495mV      264.2mV    612.8mV
677ps     519.3mV    370.9mV    614.6mV
805ps     532.8mV    447.5mV    615.5mV
1.25ns    538.4mV    492mV      616mV
[Falling waveform]
R_fixture=50.000Ohm
V_fixture=1.200
V_fixture_min=1.140
V_fixture_max=1.300
0s        1.2V       1.14V      1.302V
77ps      1.199V     1.14V      1.268V
243ps     1.202V     1.141V     851.3mV
294ps     1.151V     1.146V     784.7mV
358ps     1.023V     1.15V      738.8mV
473ps     813.2mV    1.074V     707.8mV
600ps     703.4mV    884.8mV    698.9mV
715ps     670.6mV    753.6mV    697mV
830ps     659.3mV    685mV      696.5mV
1.25ns    653mV      635.8mV    696.2mV
[Falling waveform]
R_fixture=50.000Ohm
V_fixture=0
0s        538.1mV    492.8mV    625.8mV
52ps      537.7mV    492.4mV    550.7mV
115ps     543.3mV    493.1mV    251mV
154ps     551.5mV    495.8mV    131.4mV
243ps     472mV      508.8mV    29.26mV
345ps     146.2mV    471.2mV    5.434mV
447ps     30.86mV    250.1mV    1.004mV
524ps     9.739mV    96.96mV    213.3uV
626ps     2.258mV    25.36mV    -7.246uV
1.25ns    -1.815uV   9.782uV    0V
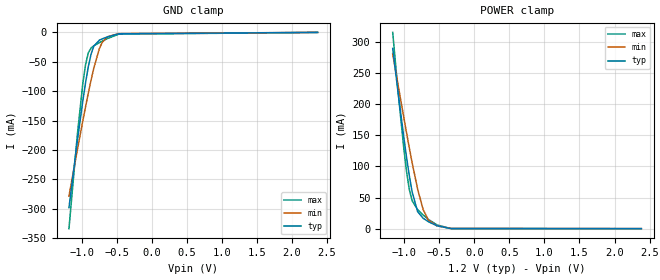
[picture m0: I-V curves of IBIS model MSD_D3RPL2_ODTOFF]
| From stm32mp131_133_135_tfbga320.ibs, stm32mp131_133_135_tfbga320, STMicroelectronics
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[Model] MSD_D3RPL2_ODTOFF
Model_type   Input
C_comp 2.247pF   2.164pF   2.365pF
Vinh = 820.000mV
Vinl = 380.000mV
[Temperature Range]   25.000   125.000   -40.000
[Voltage Range]   1.200V   1.140V   1.300V
[GND Clamp Reference]   0.00V   0.00V   0.00V
[POWER Clamp Reference]   1.200V   1.140V   1.300V
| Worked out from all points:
|   GND clamp passes 1 mA (typ) near -0.41 V on its own axis
|   POWER clamp passes 1 mA (typ) near -0.41 V on its own axis
[GND Clamp]
-1.182V   -298.1mA   -278.5mA   -333.7mA
-1.064V   -186.2mA   -200.9mA   -176mA
-984.9mV  -117mA     -150.8mA   -87.54mA
-945.5mV  -85.76mA   -126.7mA   -54.85mA
-906.1mV  -58.45mA   -103.3mA   -34.84mA
-866.7mV  -37.02mA   -81.16mA   -26.5mA
-827.3mV  -23.29mA   -60.66mA   -22.76mA
-748.5mV  -13.2mA    -27.78mA   -17.43mA
-709.1mV  -11.06mA   -17.2mA    -14.96mA
-630.3mV  -7.603mA   -7.31mA    -10.35mA
-472.7mV  -2.342mA   -2.056mA   -3.036mA
2.364V    24.04nA    406.6nA    2.605nA
[Power Clamp]
-1.164V   289.6mA    280.7mA    315.2mA
-1.085V   216.5mA    229.3mA    217.2mA
-1.006V   146.9mA    178.8mA    129.3mA
-966.7mV  114.6mA    154.1mA    91.94mA
-927.3mV  85.12mA    129.9mA    62.94mA
-887.9mV  59.62mA    106.5mA    45.07mA
-809.1mV  27.34mA    63.75mA    30.55mA
-730.3mV  16.69mA    30.8mA     21.95mA
-651.5mV  10.97mA    13.15mA    14.62mA
-533.3mV  4.62mA     4.579mA    6.036mA
-336.4mV  182.5uA    350.8uA    204.6uA
2.382V    -20.25nA   -432nA     -2.131nA
